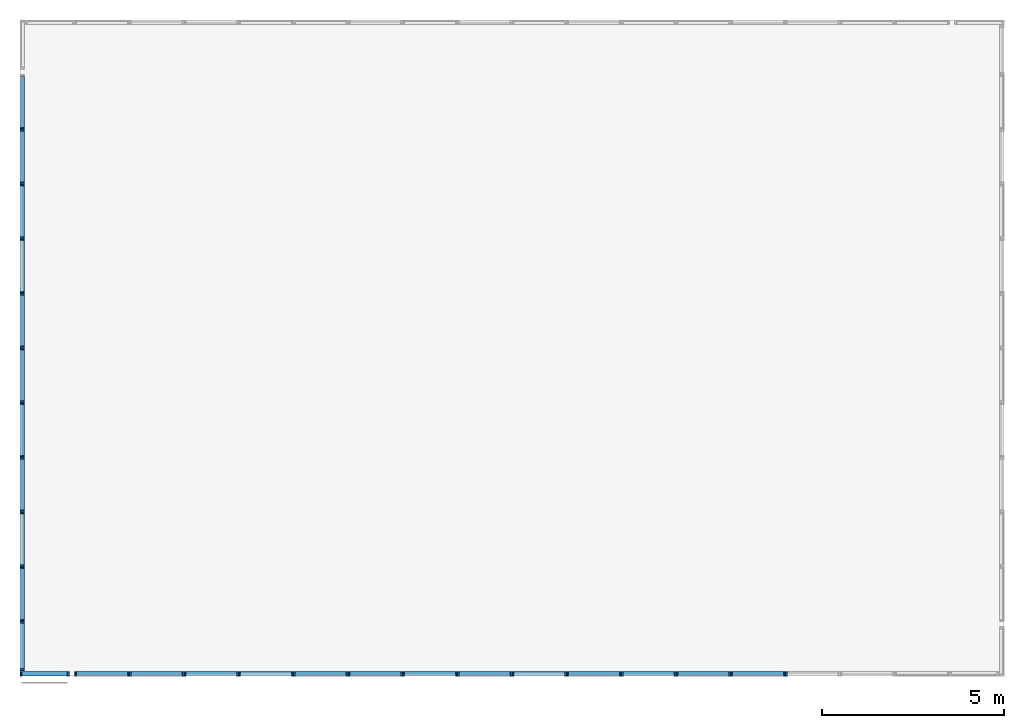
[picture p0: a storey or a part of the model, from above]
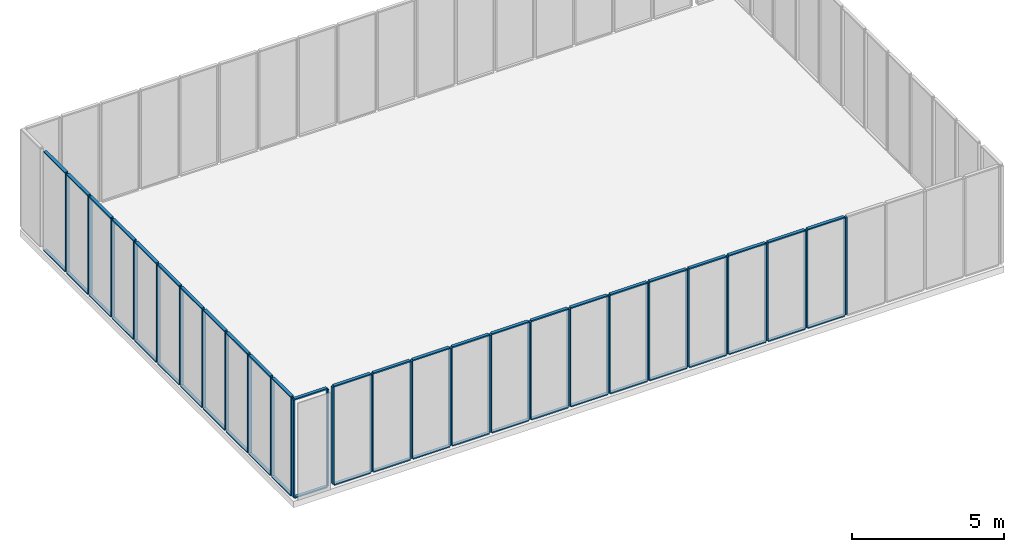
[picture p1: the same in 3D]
Properties of the parts of a building model (IFC4), part 1 of 7

# File
Description: ViewDefinition[DesignTransferView]
File name: ConX_Complex_Tower_IFC4.ifc
Time: 2026-09-19T02:26:32+05:00
Author: ConX Orbit
Written by: IfcOpenShell 0.8.5
Made in: IfcOpenShell 0.8.5
Authorization: Synthetic benchmark; not for construction

# IfcBuildingStorey (12)
In: Complex Tower
Name | Elevation (m)
L01 | 0
L02 | 4.2
L03 | 8.4
L04 | 12.6
L05 | 16.2
L06 | 19.8
L07 | 23.4
L08 | 27
L09 | 30.6
L10 | 34.2
L11 | 37.8
L12 | 41.4

# IfcMember (2304)
PredefinedType: MULLION; Material: Aluminium
ConX_Element - SyntheticData: yes; TypeCode: FR1; Thickness_mm: 120; DrawingRevision: A
Name | In | ElementID | Floor | Elevation | System = Group | Width_mm | Height_mm | Finish | DrawingRef | ParentPanelID
CT-L01-S-001-ML | L01 | CT-L01-S-001-ML | L01 | South | Curtain wall | 50 | 3900 | Blue-grey concept glass | CT-101 | CT-L01-S-001
CT-L01-S-001-MR | L01 | CT-L01-S-001-MR | L01 | South | Curtain wall | 50 | 3900 | Blue-grey concept glass | CT-101 | CT-L01-S-001
CT-L01-S-001-FB | L01 | CT-L01-S-001-FB | L01 | South | Curtain wall | 1250 | 50 | Blue-grey concept glass | CT-101 | CT-L01-S-001
CT-L01-S-001-FT | L01 | CT-L01-S-001-FT | L01 | South | Curtain wall | 1250 | 50 | Blue-grey concept glass | CT-101 | CT-L01-S-001
CT-L01-S-002-ML | L01 | CT-L01-S-002-ML | L01 | South | Curtain wall | 50 | 3900 | Blue-grey concept glass | CT-101 | CT-L01-S-002
CT-L01-S-002-MR | L01 | CT-L01-S-002-MR | L01 | South | Curtain wall | 50 | 3900 | Blue-grey concept glass | CT-101 | CT-L01-S-002
CT-L01-S-002-FB | L01 | CT-L01-S-002-FB | L01 | South | Curtain wall | 1400 | 50 | Blue-grey concept glass | CT-101 | CT-L01-S-002
CT-L01-S-002-FT | L01 | CT-L01-S-002-FT | L01 | South | Curtain wall | 1400 | 50 | Blue-grey concept glass | CT-101 | CT-L01-S-002
CT-L01-S-003-ML | L01 | CT-L01-S-003-ML | L01 | South | Curtain wall | 50 | 3900 | Blue-grey concept glass | CT-101 | CT-L01-S-003
CT-L01-S-003-MR | L01 | CT-L01-S-003-MR | L01 | South | Curtain wall | 50 | 3900 | Blue-grey concept glass | CT-101 | CT-L01-S-003
CT-L01-S-003-FB | L01 | CT-L01-S-003-FB | L01 | South | Curtain wall | 1400 | 50 | Blue-grey concept glass | CT-101 | CT-L01-S-003
CT-L01-S-003-FT | L01 | CT-L01-S-003-FT | L01 | South | Curtain wall | 1400 | 50 | Blue-grey concept glass | CT-101 | CT-L01-S-003
CT-L01-S-004-ML | L01 | CT-L01-S-004-ML | L01 | South | Stone cladding | 50 | 3900 | Warm beige stone | CT-101 | CT-L01-S-004
CT-L01-S-004-MR | L01 | CT-L01-S-004-MR | L01 | South | Stone cladding | 50 | 3900 | Warm beige stone | CT-101 | CT-L01-S-004
CT-L01-S-004-FB | L01 | CT-L01-S-004-FB | L01 | South | Stone cladding | 1400 | 50 | Warm beige stone | CT-101 | CT-L01-S-004
CT-L01-S-004-FT | L01 | CT-L01-S-004-FT | L01 | South | Stone cladding | 1400 | 50 | Warm beige stone | CT-101 | CT-L01-S-004
CT-L01-S-005-ML | L01 | CT-L01-S-005-ML | L01 | South | Metal rainscreen | 50 | 3900 | Olive powder coat | CT-101 | CT-L01-S-005
CT-L01-S-005-MR | L01 | CT-L01-S-005-MR | L01 | South | Metal rainscreen | 50 | 3900 | Olive powder coat | CT-101 | CT-L01-S-005
CT-L01-S-005-FB | L01 | CT-L01-S-005-FB | L01 | South | Metal rainscreen | 1400 | 50 | Olive powder coat | CT-101 | CT-L01-S-005
CT-L01-S-005-FT | L01 | CT-L01-S-005-FT | L01 | South | Metal rainscreen | 1400 | 50 | Olive powder coat | CT-101 | CT-L01-S-005
CT-L01-S-006-ML | L01 | CT-L01-S-006-ML | L01 | South | Curtain wall | 50 | 3900 | Blue-grey concept glass | CT-101 | CT-L01-S-006
CT-L01-S-006-MR | L01 | CT-L01-S-006-MR | L01 | South | Curtain wall | 50 | 3900 | Blue-grey concept glass | CT-101 | CT-L01-S-006
CT-L01-S-006-FB | L01 | CT-L01-S-006-FB | L01 | South | Curtain wall | 1400 | 50 | Blue-grey concept glass | CT-101 | CT-L01-S-006
CT-L01-S-006-FT | L01 | CT-L01-S-006-FT | L01 | South | Curtain wall | 1400 | 50 | Blue-grey concept glass | CT-101 | CT-L01-S-006
CT-L01-S-007-ML | L01 | CT-L01-S-007-ML | L01 | South | Curtain wall | 50 | 3900 | Blue-grey concept glass | CT-101 | CT-L01-S-007
CT-L01-S-007-MR | L01 | CT-L01-S-007-MR | L01 | South | Curtain wall | 50 | 3900 | Blue-grey concept glass | CT-101 | CT-L01-S-007
CT-L01-S-007-FB | L01 | CT-L01-S-007-FB | L01 | South | Curtain wall | 1400 | 50 | Blue-grey concept glass | CT-101 | CT-L01-S-007
CT-L01-S-007-FT | L01 | CT-L01-S-007-FT | L01 | South | Curtain wall | 1400 | 50 | Blue-grey concept glass | CT-101 | CT-L01-S-007
CT-L01-S-008-ML | L01 | CT-L01-S-008-ML | L01 | South | Stone cladding | 50 | 3900 | Warm beige stone | CT-101 | CT-L01-S-008
CT-L01-S-008-MR | L01 | CT-L01-S-008-MR | L01 | South | Stone cladding | 50 | 3900 | Warm beige stone | CT-101 | CT-L01-S-008
CT-L01-S-008-FB | L01 | CT-L01-S-008-FB | L01 | South | Stone cladding | 1400 | 50 | Warm beige stone | CT-101 | CT-L01-S-008
CT-L01-S-008-FT | L01 | CT-L01-S-008-FT | L01 | South | Stone cladding | 1400 | 50 | Warm beige stone | CT-101 | CT-L01-S-008
CT-L01-S-009-ML | L01 | CT-L01-S-009-ML | L01 | South | Curtain wall | 50 | 3900 | Blue-grey concept glass | CT-101 | CT-L01-S-009
CT-L01-S-009-MR | L01 | CT-L01-S-009-MR | L01 | South | Curtain wall | 50 | 3900 | Blue-grey concept glass | CT-101 | CT-L01-S-009
CT-L01-S-009-FB | L01 | CT-L01-S-009-FB | L01 | South | Curtain wall | 1400 | 50 | Blue-grey concept glass | CT-101 | CT-L01-S-009
CT-L01-S-009-FT | L01 | CT-L01-S-009-FT | L01 | South | Curtain wall | 1400 | 50 | Blue-grey concept glass | CT-101 | CT-L01-S-009
CT-L01-S-010-ML | L01 | CT-L01-S-010-ML | L01 | South | Metal rainscreen | 50 | 3900 | Olive powder coat | CT-101 | CT-L01-S-010
CT-L01-S-010-MR | L01 | CT-L01-S-010-MR | L01 | South | Metal rainscreen | 50 | 3900 | Olive powder coat | CT-101 | CT-L01-S-010
CT-L01-S-010-FB | L01 | CT-L01-S-010-FB | L01 | South | Metal rainscreen | 1400 | 50 | Olive powder coat | CT-101 | CT-L01-S-010
CT-L01-S-010-FT | L01 | CT-L01-S-010-FT | L01 | South | Metal rainscreen | 1400 | 50 | Olive powder coat | CT-101 | CT-L01-S-010
CT-L01-S-011-ML | L01 | CT-L01-S-011-ML | L01 | South | Curtain wall | 50 | 3900 | Blue-grey concept glass | CT-101 | CT-L01-S-011
CT-L01-S-011-MR | L01 | CT-L01-S-011-MR | L01 | South | Curtain wall | 50 | 3900 | Blue-grey concept glass | CT-101 | CT-L01-S-011
CT-L01-S-011-FB | L01 | CT-L01-S-011-FB | L01 | South | Curtain wall | 1400 | 50 | Blue-grey concept glass | CT-101 | CT-L01-S-011
CT-L01-S-011-FT | L01 | CT-L01-S-011-FT | L01 | South | Curtain wall | 1400 | 50 | Blue-grey concept glass | CT-101 | CT-L01-S-011
CT-L01-S-012-ML | L01 | CT-L01-S-012-ML | L01 | South | Stone cladding | 50 | 3900 | Warm beige stone | CT-101 | CT-L01-S-012
CT-L01-S-012-MR | L01 | CT-L01-S-012-MR | L01 | South | Stone cladding | 50 | 3900 | Warm beige stone | CT-101 | CT-L01-S-012
CT-L01-S-012-FB | L01 | CT-L01-S-012-FB | L01 | South | Stone cladding | 1400 | 50 | Warm beige stone | CT-101 | CT-L01-S-012
CT-L01-S-012-FT | L01 | CT-L01-S-012-FT | L01 | South | Stone cladding | 1400 | 50 | Warm beige stone | CT-101 | CT-L01-S-012
CT-L01-S-013-ML | L01 | CT-L01-S-013-ML | L01 | South | Curtain wall | 50 | 3900 | Blue-grey concept glass | CT-101 | CT-L01-S-013
CT-L01-S-013-MR | L01 | CT-L01-S-013-MR | L01 | South | Curtain wall | 50 | 3900 | Blue-grey concept glass | CT-101 | CT-L01-S-013
CT-L01-S-013-FB | L01 | CT-L01-S-013-FB | L01 | South | Curtain wall | 1400 | 50 | Blue-grey concept glass | CT-101 | CT-L01-S-013
CT-L01-S-013-FT | L01 | CT-L01-S-013-FT | L01 | South | Curtain wall | 1400 | 50 | Blue-grey concept glass | CT-101 | CT-L01-S-013
CT-L01-S-014-ML | L01 | CT-L01-S-014-ML | L01 | South | Curtain wall | 50 | 3900 | Blue-grey concept glass | CT-101 | CT-L01-S-014
CT-L01-S-014-MR | L01 | CT-L01-S-014-MR | L01 | South | Curtain wall | 50 | 3900 | Blue-grey concept glass | CT-101 | CT-L01-S-014
CT-L01-S-014-FB | L01 | CT-L01-S-014-FB | L01 | South | Curtain wall | 1400 | 50 | Blue-grey concept glass | CT-101 | CT-L01-S-014
CT-L01-S-014-FT | L01 | CT-L01-S-014-FT | L01 | South | Curtain wall | 1400 | 50 | Blue-grey concept glass | CT-101 | CT-L01-S-014
CT-L01-S-015-ML | L01 | CT-L01-S-015-ML | L01 | South | Metal rainscreen | 50 | 3900 | Olive powder coat | CT-101 | CT-L01-S-015
CT-L01-S-015-MR | L01 | CT-L01-S-015-MR | L01 | South | Metal rainscreen | 50 | 3900 | Olive powder coat | CT-101 | CT-L01-S-015
CT-L01-S-015-FB | L01 | CT-L01-S-015-FB | L01 | South | Metal rainscreen | 1400 | 50 | Olive powder coat | CT-101 | CT-L01-S-015
CT-L01-S-015-FT | L01 | CT-L01-S-015-FT | L01 | South | Metal rainscreen | 1400 | 50 | Olive powder coat | CT-101 | CT-L01-S-015
CT-L01-S-016-ML | L01 | CT-L01-S-016-ML | L01 | South | Stone cladding | 50 | 3900 | Warm beige stone | CT-101 | CT-L01-S-016
CT-L01-S-016-MR | L01 | CT-L01-S-016-MR | L01 | South | Stone cladding | 50 | 3900 | Warm beige stone | CT-101 | CT-L01-S-016
CT-L01-S-016-FB | L01 | CT-L01-S-016-FB | L01 | South | Stone cladding | 1400 | 50 | Warm beige stone | CT-101 | CT-L01-S-016
CT-L01-S-016-FT | L01 | CT-L01-S-016-FT | L01 | South | Stone cladding | 1400 | 50 | Warm beige stone | CT-101 | CT-L01-S-016
CT-L01-S-017-ML | L01 | CT-L01-S-017-ML | L01 | South | Curtain wall | 50 | 3900 | Blue-grey concept glass | CT-101 | CT-L01-S-017
CT-L01-S-017-MR | L01 | CT-L01-S-017-MR | L01 | South | Curtain wall | 50 | 3900 | Blue-grey concept glass | CT-101 | CT-L01-S-017
CT-L01-S-017-FB | L01 | CT-L01-S-017-FB | L01 | South | Curtain wall | 1400 | 50 | Blue-grey concept glass | CT-101 | CT-L01-S-017
CT-L01-S-017-FT | L01 | CT-L01-S-017-FT | L01 | South | Curtain wall | 1400 | 50 | Blue-grey concept glass | CT-101 | CT-L01-S-017
CT-L01-S-018-ML | L01 | CT-L01-S-018-ML | L01 | South | Curtain wall | 50 | 3900 | Blue-grey concept glass | CT-101 | CT-L01-S-018
CT-L01-S-018-MR | L01 | CT-L01-S-018-MR | L01 | South | Curtain wall | 50 | 3900 | Blue-grey concept glass | CT-101 | CT-L01-S-018
CT-L01-S-018-FB | L01 | CT-L01-S-018-FB | L01 | South | Curtain wall | 1250 | 50 | Blue-grey concept glass | CT-101 | CT-L01-S-018
CT-L01-S-018-FT | L01 | CT-L01-S-018-FT | L01 | South | Curtain wall | 1250 | 50 | Blue-grey concept glass | CT-101 | CT-L01-S-018
CT-L01-E-001-ML | L01 | CT-L01-E-001-ML | L01 | East | Curtain wall | 50 | 3900 | Blue-grey concept glass | CT-102 | CT-L01-E-001
CT-L01-E-001-MR | L01 | CT-L01-E-001-MR | L01 | East | Curtain wall | 50 | 3900 | Blue-grey concept glass | CT-102 | CT-L01-E-001
CT-L01-E-001-FB | L01 | CT-L01-E-001-FB | L01 | East | Curtain wall | 1250 | 50 | Blue-grey concept glass | CT-102 | CT-L01-E-001
CT-L01-E-001-FT | L01 | CT-L01-E-001-FT | L01 | East | Curtain wall | 1250 | 50 | Blue-grey concept glass | CT-102 | CT-L01-E-001
CT-L01-E-002-ML | L01 | CT-L01-E-002-ML | L01 | East | Curtain wall | 50 | 3900 | Blue-grey concept glass | CT-102 | CT-L01-E-002
CT-L01-E-002-MR | L01 | CT-L01-E-002-MR | L01 | East | Curtain wall | 50 | 3900 | Blue-grey concept glass | CT-102 | CT-L01-E-002
CT-L01-E-002-FB | L01 | CT-L01-E-002-FB | L01 | East | Curtain wall | 1400 | 50 | Blue-grey concept glass | CT-102 | CT-L01-E-002
CT-L01-E-002-FT | L01 | CT-L01-E-002-FT | L01 | East | Curtain wall | 1400 | 50 | Blue-grey concept glass | CT-102 | CT-L01-E-002
CT-L01-E-003-ML | L01 | CT-L01-E-003-ML | L01 | East | Curtain wall | 50 | 3900 | Blue-grey concept glass | CT-102 | CT-L01-E-003
CT-L01-E-003-MR | L01 | CT-L01-E-003-MR | L01 | East | Curtain wall | 50 | 3900 | Blue-grey concept glass | CT-102 | CT-L01-E-003
CT-L01-E-003-FB | L01 | CT-L01-E-003-FB | L01 | East | Curtain wall | 1400 | 50 | Blue-grey concept glass | CT-102 | CT-L01-E-003
CT-L01-E-003-FT | L01 | CT-L01-E-003-FT | L01 | East | Curtain wall | 1400 | 50 | Blue-grey concept glass | CT-102 | CT-L01-E-003
CT-L01-E-004-ML | L01 | CT-L01-E-004-ML | L01 | East | Stone cladding | 50 | 3900 | Warm beige stone | CT-102 | CT-L01-E-004
CT-L01-E-004-MR | L01 | CT-L01-E-004-MR | L01 | East | Stone cladding | 50 | 3900 | Warm beige stone | CT-102 | CT-L01-E-004
CT-L01-E-004-FB | L01 | CT-L01-E-004-FB | L01 | East | Stone cladding | 1400 | 50 | Warm beige stone | CT-102 | CT-L01-E-004
CT-L01-E-004-FT | L01 | CT-L01-E-004-FT | L01 | East | Stone cladding | 1400 | 50 | Warm beige stone | CT-102 | CT-L01-E-004
CT-L01-E-005-ML | L01 | CT-L01-E-005-ML | L01 | East | Metal rainscreen | 50 | 3900 | Olive powder coat | CT-102 | CT-L01-E-005
CT-L01-E-005-MR | L01 | CT-L01-E-005-MR | L01 | East | Metal rainscreen | 50 | 3900 | Olive powder coat | CT-102 | CT-L01-E-005
CT-L01-E-005-FB | L01 | CT-L01-E-005-FB | L01 | East | Metal rainscreen | 1400 | 50 | Olive powder coat | CT-102 | CT-L01-E-005
CT-L01-E-005-FT | L01 | CT-L01-E-005-FT | L01 | East | Metal rainscreen | 1400 | 50 | Olive powder coat | CT-102 | CT-L01-E-005
CT-L01-E-006-ML | L01 | CT-L01-E-006-ML | L01 | East | Curtain wall | 50 | 3900 | Blue-grey concept glass | CT-102 | CT-L01-E-006
CT-L01-E-006-MR | L01 | CT-L01-E-006-MR | L01 | East | Curtain wall | 50 | 3900 | Blue-grey concept glass | CT-102 | CT-L01-E-006
CT-L01-E-006-FB | L01 | CT-L01-E-006-FB | L01 | East | Curtain wall | 1400 | 50 | Blue-grey concept glass | CT-102 | CT-L01-E-006
CT-L01-E-006-FT | L01 | CT-L01-E-006-FT | L01 | East | Curtain wall | 1400 | 50 | Blue-grey concept glass | CT-102 | CT-L01-E-006
CT-L01-E-007-ML | L01 | CT-L01-E-007-ML | L01 | East | Curtain wall | 50 | 3900 | Blue-grey concept glass | CT-102 | CT-L01-E-007
CT-L01-E-007-MR | L01 | CT-L01-E-007-MR | L01 | East | Curtain wall | 50 | 3900 | Blue-grey concept glass | CT-102 | CT-L01-E-007
CT-L01-E-007-FB | L01 | CT-L01-E-007-FB | L01 | East | Curtain wall | 1400 | 50 | Blue-grey concept glass | CT-102 | CT-L01-E-007
CT-L01-E-007-FT | L01 | CT-L01-E-007-FT | L01 | East | Curtain wall | 1400 | 50 | Blue-grey concept glass | CT-102 | CT-L01-E-007
CT-L01-E-008-ML | L01 | CT-L01-E-008-ML | L01 | East | Stone cladding | 50 | 3900 | Warm beige stone | CT-102 | CT-L01-E-008
CT-L01-E-008-MR | L01 | CT-L01-E-008-MR | L01 | East | Stone cladding | 50 | 3900 | Warm beige stone | CT-102 | CT-L01-E-008
CT-L01-E-008-FB | L01 | CT-L01-E-008-FB | L01 | East | Stone cladding | 1400 | 50 | Warm beige stone | CT-102 | CT-L01-E-008
CT-L01-E-008-FT | L01 | CT-L01-E-008-FT | L01 | East | Stone cladding | 1400 | 50 | Warm beige stone | CT-102 | CT-L01-E-008
CT-L01-E-009-ML | L01 | CT-L01-E-009-ML | L01 | East | Curtain wall | 50 | 3900 | Blue-grey concept glass | CT-102 | CT-L01-E-009
CT-L01-E-009-MR | L01 | CT-L01-E-009-MR | L01 | East | Curtain wall | 50 | 3900 | Blue-grey concept glass | CT-102 | CT-L01-E-009
CT-L01-E-009-FB | L01 | CT-L01-E-009-FB | L01 | East | Curtain wall | 1400 | 50 | Blue-grey concept glass | CT-102 | CT-L01-E-009
CT-L01-E-009-FT | L01 | CT-L01-E-009-FT | L01 | East | Curtain wall | 1400 | 50 | Blue-grey concept glass | CT-102 | CT-L01-E-009
CT-L01-E-010-ML | L01 | CT-L01-E-010-ML | L01 | East | Metal rainscreen | 50 | 3900 | Olive powder coat | CT-102 | CT-L01-E-010
CT-L01-E-010-MR | L01 | CT-L01-E-010-MR | L01 | East | Metal rainscreen | 50 | 3900 | Olive powder coat | CT-102 | CT-L01-E-010
CT-L01-E-010-FB | L01 | CT-L01-E-010-FB | L01 | East | Metal rainscreen | 1400 | 50 | Olive powder coat | CT-102 | CT-L01-E-010
CT-L01-E-010-FT | L01 | CT-L01-E-010-FT | L01 | East | Metal rainscreen | 1400 | 50 | Olive powder coat | CT-102 | CT-L01-E-010
CT-L01-E-011-ML | L01 | CT-L01-E-011-ML | L01 | East | Curtain wall | 50 | 3900 | Blue-grey concept glass | CT-102 | CT-L01-E-011
CT-L01-E-011-MR | L01 | CT-L01-E-011-MR | L01 | East | Curtain wall | 50 | 3900 | Blue-grey concept glass | CT-102 | CT-L01-E-011
CT-L01-E-011-FB | L01 | CT-L01-E-011-FB | L01 | East | Curtain wall | 1400 | 50 | Blue-grey concept glass | CT-102 | CT-L01-E-011
CT-L01-E-011-FT | L01 | CT-L01-E-011-FT | L01 | East | Curtain wall | 1400 | 50 | Blue-grey concept glass | CT-102 | CT-L01-E-011
CT-L01-E-012-ML | L01 | CT-L01-E-012-ML | L01 | East | Stone cladding | 50 | 3900 | Warm beige stone | CT-102 | CT-L01-E-012
CT-L01-E-012-MR | L01 | CT-L01-E-012-MR | L01 | East | Stone cladding | 50 | 3900 | Warm beige stone | CT-102 | CT-L01-E-012
CT-L01-E-012-FB | L01 | CT-L01-E-012-FB | L01 | East | Stone cladding | 1250 | 50 | Warm beige stone | CT-102 | CT-L01-E-012
CT-L01-E-012-FT | L01 | CT-L01-E-012-FT | L01 | East | Stone cladding | 1250 | 50 | Warm beige stone | CT-102 | CT-L01-E-012
CT-L01-N-001-ML | L01 | CT-L01-N-001-ML | L01 | North | Curtain wall | 50 | 3900 | Blue-grey concept glass | CT-103 | CT-L01-N-001
CT-L01-N-001-MR | L01 | CT-L01-N-001-MR | L01 | North | Curtain wall | 50 | 3900 | Blue-grey concept glass | CT-103 | CT-L01-N-001
CT-L01-N-001-FB | L01 | CT-L01-N-001-FB | L01 | North | Curtain wall | 1250 | 50 | Blue-grey concept glass | CT-103 | CT-L01-N-001
CT-L01-N-001-FT | L01 | CT-L01-N-001-FT | L01 | North | Curtain wall | 1250 | 50 | Blue-grey concept glass | CT-103 | CT-L01-N-001
CT-L01-N-002-ML | L01 | CT-L01-N-002-ML | L01 | North | Curtain wall | 50 | 3900 | Blue-grey concept glass | CT-103 | CT-L01-N-002
CT-L01-N-002-MR | L01 | CT-L01-N-002-MR | L01 | North | Curtain wall | 50 | 3900 | Blue-grey concept glass | CT-103 | CT-L01-N-002
CT-L01-N-002-FB | L01 | CT-L01-N-002-FB | L01 | North | Curtain wall | 1400 | 50 | Blue-grey concept glass | CT-103 | CT-L01-N-002
CT-L01-N-002-FT | L01 | CT-L01-N-002-FT | L01 | North | Curtain wall | 1400 | 50 | Blue-grey concept glass | CT-103 | CT-L01-N-002
CT-L01-N-003-ML | L01 | CT-L01-N-003-ML | L01 | North | Curtain wall | 50 | 3900 | Blue-grey concept glass | CT-103 | CT-L01-N-003
CT-L01-N-003-MR | L01 | CT-L01-N-003-MR | L01 | North | Curtain wall | 50 | 3900 | Blue-grey concept glass | CT-103 | CT-L01-N-003
CT-L01-N-003-FB | L01 | CT-L01-N-003-FB | L01 | North | Curtain wall | 1400 | 50 | Blue-grey concept glass | CT-103 | CT-L01-N-003
CT-L01-N-003-FT | L01 | CT-L01-N-003-FT | L01 | North | Curtain wall | 1400 | 50 | Blue-grey concept glass | CT-103 | CT-L01-N-003
CT-L01-N-004-ML | L01 | CT-L01-N-004-ML | L01 | North | Stone cladding | 50 | 3900 | Warm beige stone | CT-103 | CT-L01-N-004
CT-L01-N-004-MR | L01 | CT-L01-N-004-MR | L01 | North | Stone cladding | 50 | 3900 | Warm beige stone | CT-103 | CT-L01-N-004
CT-L01-N-004-FB | L01 | CT-L01-N-004-FB | L01 | North | Stone cladding | 1400 | 50 | Warm beige stone | CT-103 | CT-L01-N-004
CT-L01-N-004-FT | L01 | CT-L01-N-004-FT | L01 | North | Stone cladding | 1400 | 50 | Warm beige stone | CT-103 | CT-L01-N-004
CT-L01-N-005-ML | L01 | CT-L01-N-005-ML | L01 | North | Metal rainscreen | 50 | 3900 | Olive powder coat | CT-103 | CT-L01-N-005
CT-L01-N-005-MR | L01 | CT-L01-N-005-MR | L01 | North | Metal rainscreen | 50 | 3900 | Olive powder coat | CT-103 | CT-L01-N-005
CT-L01-N-005-FB | L01 | CT-L01-N-005-FB | L01 | North | Metal rainscreen | 1400 | 50 | Olive powder coat | CT-103 | CT-L01-N-005
CT-L01-N-005-FT | L01 | CT-L01-N-005-FT | L01 | North | Metal rainscreen | 1400 | 50 | Olive powder coat | CT-103 | CT-L01-N-005
CT-L01-N-006-ML | L01 | CT-L01-N-006-ML | L01 | North | Curtain wall | 50 | 3900 | Blue-grey concept glass | CT-103 | CT-L01-N-006
CT-L01-N-006-MR | L01 | CT-L01-N-006-MR | L01 | North | Curtain wall | 50 | 3900 | Blue-grey concept glass | CT-103 | CT-L01-N-006
CT-L01-N-006-FB | L01 | CT-L01-N-006-FB | L01 | North | Curtain wall | 1400 | 50 | Blue-grey concept glass | CT-103 | CT-L01-N-006
CT-L01-N-006-FT | L01 | CT-L01-N-006-FT | L01 | North | Curtain wall | 1400 | 50 | Blue-grey concept glass | CT-103 | CT-L01-N-006
CT-L01-N-007-ML | L01 | CT-L01-N-007-ML | L01 | North | Curtain wall | 50 | 3900 | Blue-grey concept glass | CT-103 | CT-L01-N-007
CT-L01-N-007-MR | L01 | CT-L01-N-007-MR | L01 | North | Curtain wall | 50 | 3900 | Blue-grey concept glass | CT-103 | CT-L01-N-007
CT-L01-N-007-FB | L01 | CT-L01-N-007-FB | L01 | North | Curtain wall | 1400 | 50 | Blue-grey concept glass | CT-103 | CT-L01-N-007
CT-L01-N-007-FT | L01 | CT-L01-N-007-FT | L01 | North | Curtain wall | 1400 | 50 | Blue-grey concept glass | CT-103 | CT-L01-N-007
CT-L01-N-008-ML | L01 | CT-L01-N-008-ML | L01 | North | Stone cladding | 50 | 3900 | Warm beige stone | CT-103 | CT-L01-N-008
CT-L01-N-008-MR | L01 | CT-L01-N-008-MR | L01 | North | Stone cladding | 50 | 3900 | Warm beige stone | CT-103 | CT-L01-N-008
CT-L01-N-008-FB | L01 | CT-L01-N-008-FB | L01 | North | Stone cladding | 1400 | 50 | Warm beige stone | CT-103 | CT-L01-N-008
CT-L01-N-008-FT | L01 | CT-L01-N-008-FT | L01 | North | Stone cladding | 1400 | 50 | Warm beige stone | CT-103 | CT-L01-N-008
CT-L01-N-009-ML | L01 | CT-L01-N-009-ML | L01 | North | Curtain wall | 50 | 3900 | Blue-grey concept glass | CT-103 | CT-L01-N-009
CT-L01-N-009-MR | L01 | CT-L01-N-009-MR | L01 | North | Curtain wall | 50 | 3900 | Blue-grey concept glass | CT-103 | CT-L01-N-009
CT-L01-N-009-FB | L01 | CT-L01-N-009-FB | L01 | North | Curtain wall | 1400 | 50 | Blue-grey concept glass | CT-103 | CT-L01-N-009
CT-L01-N-009-FT | L01 | CT-L01-N-009-FT | L01 | North | Curtain wall | 1400 | 50 | Blue-grey concept glass | CT-103 | CT-L01-N-009
CT-L01-N-010-ML | L01 | CT-L01-N-010-ML | L01 | North | Metal rainscreen | 50 | 3900 | Olive powder coat | CT-103 | CT-L01-N-010
CT-L01-N-010-MR | L01 | CT-L01-N-010-MR | L01 | North | Metal rainscreen | 50 | 3900 | Olive powder coat | CT-103 | CT-L01-N-010
CT-L01-N-010-FB | L01 | CT-L01-N-010-FB | L01 | North | Metal rainscreen | 1400 | 50 | Olive powder coat | CT-103 | CT-L01-N-010
CT-L01-N-010-FT | L01 | CT-L01-N-010-FT | L01 | North | Metal rainscreen | 1400 | 50 | Olive powder coat | CT-103 | CT-L01-N-010
CT-L01-N-011-ML | L01 | CT-L01-N-011-ML | L01 | North | Curtain wall | 50 | 3900 | Blue-grey concept glass | CT-103 | CT-L01-N-011
CT-L01-N-011-MR | L01 | CT-L01-N-011-MR | L01 | North | Curtain wall | 50 | 3900 | Blue-grey concept glass | CT-103 | CT-L01-N-011
CT-L01-N-011-FB | L01 | CT-L01-N-011-FB | L01 | North | Curtain wall | 1400 | 50 | Blue-grey concept glass | CT-103 | CT-L01-N-011
CT-L01-N-011-FT | L01 | CT-L01-N-011-FT | L01 | North | Curtain wall | 1400 | 50 | Blue-grey concept glass | CT-103 | CT-L01-N-011
CT-L01-N-012-ML | L01 | CT-L01-N-012-ML | L01 | North | Stone cladding | 50 | 3900 | Warm beige stone | CT-103 | CT-L01-N-012
CT-L01-N-012-MR | L01 | CT-L01-N-012-MR | L01 | North | Stone cladding | 50 | 3900 | Warm beige stone | CT-103 | CT-L01-N-012
CT-L01-N-012-FB | L01 | CT-L01-N-012-FB | L01 | North | Stone cladding | 1400 | 50 | Warm beige stone | CT-103 | CT-L01-N-012
CT-L01-N-012-FT | L01 | CT-L01-N-012-FT | L01 | North | Stone cladding | 1400 | 50 | Warm beige stone | CT-103 | CT-L01-N-012
CT-L01-N-013-ML | L01 | CT-L01-N-013-ML | L01 | North | Curtain wall | 50 | 3900 | Blue-grey concept glass | CT-103 | CT-L01-N-013
CT-L01-N-013-MR | L01 | CT-L01-N-013-MR | L01 | North | Curtain wall | 50 | 3900 | Blue-grey concept glass | CT-103 | CT-L01-N-013
CT-L01-N-013-FB | L01 | CT-L01-N-013-FB | L01 | North | Curtain wall | 1400 | 50 | Blue-grey concept glass | CT-103 | CT-L01-N-013
CT-L01-N-013-FT | L01 | CT-L01-N-013-FT | L01 | North | Curtain wall | 1400 | 50 | Blue-grey concept glass | CT-103 | CT-L01-N-013
CT-L01-N-014-ML | L01 | CT-L01-N-014-ML | L01 | North | Curtain wall | 50 | 3900 | Blue-grey concept glass | CT-103 | CT-L01-N-014
CT-L01-N-014-MR | L01 | CT-L01-N-014-MR | L01 | North | Curtain wall | 50 | 3900 | Blue-grey concept glass | CT-103 | CT-L01-N-014
CT-L01-N-014-FB | L01 | CT-L01-N-014-FB | L01 | North | Curtain wall | 1400 | 50 | Blue-grey concept glass | CT-103 | CT-L01-N-014
CT-L01-N-014-FT | L01 | CT-L01-N-014-FT | L01 | North | Curtain wall | 1400 | 50 | Blue-grey concept glass | CT-103 | CT-L01-N-014
CT-L01-N-015-ML | L01 | CT-L01-N-015-ML | L01 | North | Metal rainscreen | 50 | 3900 | Olive powder coat | CT-103 | CT-L01-N-015
CT-L01-N-015-MR | L01 | CT-L01-N-015-MR | L01 | North | Metal rainscreen | 50 | 3900 | Olive powder coat | CT-103 | CT-L01-N-015
CT-L01-N-015-FB | L01 | CT-L01-N-015-FB | L01 | North | Metal rainscreen | 1400 | 50 | Olive powder coat | CT-103 | CT-L01-N-015
CT-L01-N-015-FT | L01 | CT-L01-N-015-FT | L01 | North | Metal rainscreen | 1400 | 50 | Olive powder coat | CT-103 | CT-L01-N-015
CT-L01-N-016-ML | L01 | CT-L01-N-016-ML | L01 | North | Stone cladding | 50 | 3900 | Warm beige stone | CT-103 | CT-L01-N-016
CT-L01-N-016-MR | L01 | CT-L01-N-016-MR | L01 | North | Stone cladding | 50 | 3900 | Warm beige stone | CT-103 | CT-L01-N-016
CT-L01-N-016-FB | L01 | CT-L01-N-016-FB | L01 | North | Stone cladding | 1400 | 50 | Warm beige stone | CT-103 | CT-L01-N-016
CT-L01-N-016-FT | L01 | CT-L01-N-016-FT | L01 | North | Stone cladding | 1400 | 50 | Warm beige stone | CT-103 | CT-L01-N-016
CT-L01-N-017-ML | L01 | CT-L01-N-017-ML | L01 | North | Curtain wall | 50 | 3900 | Blue-grey concept glass | CT-103 | CT-L01-N-017
CT-L01-N-017-MR | L01 | CT-L01-N-017-MR | L01 | North | Curtain wall | 50 | 3900 | Blue-grey concept glass | CT-103 | CT-L01-N-017
CT-L01-N-017-FB | L01 | CT-L01-N-017-FB | L01 | North | Curtain wall | 1400 | 50 | Blue-grey concept glass | CT-103 | CT-L01-N-017
CT-L01-N-017-FT | L01 | CT-L01-N-017-FT | L01 | North | Curtain wall | 1400 | 50 | Blue-grey concept glass | CT-103 | CT-L01-N-017
CT-L01-N-018-ML | L01 | CT-L01-N-018-ML | L01 | North | Curtain wall | 50 | 3900 | Blue-grey concept glass | CT-103 | CT-L01-N-018
CT-L01-N-018-MR | L01 | CT-L01-N-018-MR | L01 | North | Curtain wall | 50 | 3900 | Blue-grey concept glass | CT-103 | CT-L01-N-018
CT-L01-N-018-FB | L01 | CT-L01-N-018-FB | L01 | North | Curtain wall | 1250 | 50 | Blue-grey concept glass | CT-103 | CT-L01-N-018
CT-L01-N-018-FT | L01 | CT-L01-N-018-FT | L01 | North | Curtain wall | 1250 | 50 | Blue-grey concept glass | CT-103 | CT-L01-N-018
CT-L01-W-001-ML | L01 | CT-L01-W-001-ML | L01 | West | Curtain wall | 50 | 3900 | Blue-grey concept glass | CT-104 | CT-L01-W-001
CT-L01-W-001-MR | L01 | CT-L01-W-001-MR | L01 | West | Curtain wall | 50 | 3900 | Blue-grey concept glass | CT-104 | CT-L01-W-001
CT-L01-W-001-FB | L01 | CT-L01-W-001-FB | L01 | West | Curtain wall | 1250 | 50 | Blue-grey concept glass | CT-104 | CT-L01-W-001
CT-L01-W-001-FT | L01 | CT-L01-W-001-FT | L01 | West | Curtain wall | 1250 | 50 | Blue-grey concept glass | CT-104 | CT-L01-W-001
CT-L01-W-002-ML | L01 | CT-L01-W-002-ML | L01 | West | Curtain wall | 50 | 3900 | Blue-grey concept glass | CT-104 | CT-L01-W-002
CT-L01-W-002-MR | L01 | CT-L01-W-002-MR | L01 | West | Curtain wall | 50 | 3900 | Blue-grey concept glass | CT-104 | CT-L01-W-002
CT-L01-W-002-FB | L01 | CT-L01-W-002-FB | L01 | West | Curtain wall | 1400 | 50 | Blue-grey concept glass | CT-104 | CT-L01-W-002
CT-L01-W-002-FT | L01 | CT-L01-W-002-FT | L01 | West | Curtain wall | 1400 | 50 | Blue-grey concept glass | CT-104 | CT-L01-W-002
CT-L01-W-003-ML | L01 | CT-L01-W-003-ML | L01 | West | Curtain wall | 50 | 3900 | Blue-grey concept glass | CT-104 | CT-L01-W-003
CT-L01-W-003-MR | L01 | CT-L01-W-003-MR | L01 | West | Curtain wall | 50 | 3900 | Blue-grey concept glass | CT-104 | CT-L01-W-003
CT-L01-W-003-FB | L01 | CT-L01-W-003-FB | L01 | West | Curtain wall | 1400 | 50 | Blue-grey concept glass | CT-104 | CT-L01-W-003
CT-L01-W-003-FT | L01 | CT-L01-W-003-FT | L01 | West | Curtain wall | 1400 | 50 | Blue-grey concept glass | CT-104 | CT-L01-W-003
CT-L01-W-004-ML | L01 | CT-L01-W-004-ML | L01 | West | Stone cladding | 50 | 3900 | Warm beige stone | CT-104 | CT-L01-W-004
CT-L01-W-004-MR | L01 | CT-L01-W-004-MR | L01 | West | Stone cladding | 50 | 3900 | Warm beige stone | CT-104 | CT-L01-W-004
CT-L01-W-004-FB | L01 | CT-L01-W-004-FB | L01 | West | Stone cladding | 1400 | 50 | Warm beige stone | CT-104 | CT-L01-W-004
CT-L01-W-004-FT | L01 | CT-L01-W-004-FT | L01 | West | Stone cladding | 1400 | 50 | Warm beige stone | CT-104 | CT-L01-W-004
CT-L01-W-005-ML | L01 | CT-L01-W-005-ML | L01 | West | Metal rainscreen | 50 | 3900 | Olive powder coat | CT-104 | CT-L01-W-005
CT-L01-W-005-MR | L01 | CT-L01-W-005-MR | L01 | West | Metal rainscreen | 50 | 3900 | Olive powder coat | CT-104 | CT-L01-W-005
CT-L01-W-005-FB | L01 | CT-L01-W-005-FB | L01 | West | Metal rainscreen | 1400 | 50 | Olive powder coat | CT-104 | CT-L01-W-005
CT-L01-W-005-FT | L01 | CT-L01-W-005-FT | L01 | West | Metal rainscreen | 1400 | 50 | Olive powder coat | CT-104 | CT-L01-W-005
CT-L01-W-006-ML | L01 | CT-L01-W-006-ML | L01 | West | Curtain wall | 50 | 3900 | Blue-grey concept glass | CT-104 | CT-L01-W-006
CT-L01-W-006-MR | L01 | CT-L01-W-006-MR | L01 | West | Curtain wall | 50 | 3900 | Blue-grey concept glass | CT-104 | CT-L01-W-006
CT-L01-W-006-FB | L01 | CT-L01-W-006-FB | L01 | West | Curtain wall | 1400 | 50 | Blue-grey concept glass | CT-104 | CT-L01-W-006
CT-L01-W-006-FT | L01 | CT-L01-W-006-FT | L01 | West | Curtain wall | 1400 | 50 | Blue-grey concept glass | CT-104 | CT-L01-W-006
CT-L01-W-007-ML | L01 | CT-L01-W-007-ML | L01 | West | Curtain wall | 50 | 3900 | Blue-grey concept glass | CT-104 | CT-L01-W-007
CT-L01-W-007-MR | L01 | CT-L01-W-007-MR | L01 | West | Curtain wall | 50 | 3900 | Blue-grey concept glass | CT-104 | CT-L01-W-007
CT-L01-W-007-FB | L01 | CT-L01-W-007-FB | L01 | West | Curtain wall | 1400 | 50 | Blue-grey concept glass | CT-104 | CT-L01-W-007
CT-L01-W-007-FT | L01 | CT-L01-W-007-FT | L01 | West | Curtain wall | 1400 | 50 | Blue-grey concept glass | CT-104 | CT-L01-W-007
CT-L01-W-008-ML | L01 | CT-L01-W-008-ML | L01 | West | Stone cladding | 50 | 3900 | Warm beige stone | CT-104 | CT-L01-W-008
CT-L01-W-008-MR | L01 | CT-L01-W-008-MR | L01 | West | Stone cladding | 50 | 3900 | Warm beige stone | CT-104 | CT-L01-W-008
CT-L01-W-008-FB | L01 | CT-L01-W-008-FB | L01 | West | Stone cladding | 1400 | 50 | Warm beige stone | CT-104 | CT-L01-W-008
CT-L01-W-008-FT | L01 | CT-L01-W-008-FT | L01 | West | Stone cladding | 1400 | 50 | Warm beige stone | CT-104 | CT-L01-W-008
CT-L01-W-009-ML | L01 | CT-L01-W-009-ML | L01 | West | Curtain wall | 50 | 3900 | Blue-grey concept glass | CT-104 | CT-L01-W-009
CT-L01-W-009-MR | L01 | CT-L01-W-009-MR | L01 | West | Curtain wall | 50 | 3900 | Blue-grey concept glass | CT-104 | CT-L01-W-009
CT-L01-W-009-FB | L01 | CT-L01-W-009-FB | L01 | West | Curtain wall | 1400 | 50 | Blue-grey concept glass | CT-104 | CT-L01-W-009
CT-L01-W-009-FT | L01 | CT-L01-W-009-FT | L01 | West | Curtain wall | 1400 | 50 | Blue-grey concept glass | CT-104 | CT-L01-W-009
CT-L01-W-010-ML | L01 | CT-L01-W-010-ML | L01 | West | Metal rainscreen | 50 | 3900 | Olive powder coat | CT-104 | CT-L01-W-010
CT-L01-W-010-MR | L01 | CT-L01-W-010-MR | L01 | West | Metal rainscreen | 50 | 3900 | Olive powder coat | CT-104 | CT-L01-W-010
CT-L01-W-010-FB | L01 | CT-L01-W-010-FB | L01 | West | Metal rainscreen | 1400 | 50 | Olive powder coat | CT-104 | CT-L01-W-010
CT-L01-W-010-FT | L01 | CT-L01-W-010-FT | L01 | West | Metal rainscreen | 1400 | 50 | Olive powder coat | CT-104 | CT-L01-W-010
CT-L01-W-011-ML | L01 | CT-L01-W-011-ML | L01 | West | Curtain wall | 50 | 3900 | Blue-grey concept glass | CT-104 | CT-L01-W-011
CT-L01-W-011-MR | L01 | CT-L01-W-011-MR | L01 | West | Curtain wall | 50 | 3900 | Blue-grey concept glass | CT-104 | CT-L01-W-011
CT-L01-W-011-FB | L01 | CT-L01-W-011-FB | L01 | West | Curtain wall | 1400 | 50 | Blue-grey concept glass | CT-104 | CT-L01-W-011
CT-L01-W-011-FT | L01 | CT-L01-W-011-FT | L01 | West | Curtain wall | 1400 | 50 | Blue-grey concept glass | CT-104 | CT-L01-W-011
CT-L01-W-012-ML | L01 | CT-L01-W-012-ML | L01 | West | Stone cladding | 50 | 3900 | Warm beige stone | CT-104 | CT-L01-W-012
CT-L01-W-012-MR | L01 | CT-L01-W-012-MR | L01 | West | Stone cladding | 50 | 3900 | Warm beige stone | CT-104 | CT-L01-W-012
CT-L01-W-012-FB | L01 | CT-L01-W-012-FB | L01 | West | Stone cladding | 1250 | 50 | Warm beige stone | CT-104 | CT-L01-W-012
CT-L01-W-012-FT | L01 | CT-L01-W-012-FT | L01 | West | Stone cladding | 1250 | 50 | Warm beige stone | CT-104 | CT-L01-W-012
CT-L02-S-001-ML | L02 | CT-L02-S-001-ML | L02 | South | Curtain wall | 50 | 3900 | Blue-grey concept glass | CT-101 | CT-L02-S-001
CT-L02-S-001-MR | L02 | CT-L02-S-001-MR | L02 | South | Curtain wall | 50 | 3900 | Blue-grey concept glass | CT-101 | CT-L02-S-001
CT-L02-S-001-FB | L02 | CT-L02-S-001-FB | L02 | South | Curtain wall | 1250 | 50 | Blue-grey concept glass | CT-101 | CT-L02-S-001
CT-L02-S-001-FT | L02 | CT-L02-S-001-FT | L02 | South | Curtain wall | 1250 | 50 | Blue-grey concept glass | CT-101 | CT-L02-S-001
CT-L02-S-002-ML | L02 | CT-L02-S-002-ML | L02 | South | Curtain wall | 50 | 3900 | Blue-grey concept glass | CT-101 | CT-L02-S-002
CT-L02-S-002-MR | L02 | CT-L02-S-002-MR | L02 | South | Curtain wall | 50 | 3900 | Blue-grey concept glass | CT-101 | CT-L02-S-002
CT-L02-S-002-FB | L02 | CT-L02-S-002-FB | L02 | South | Curtain wall | 1400 | 50 | Blue-grey concept glass | CT-101 | CT-L02-S-002
CT-L02-S-002-FT | L02 | CT-L02-S-002-FT | L02 | South | Curtain wall | 1400 | 50 | Blue-grey concept glass | CT-101 | CT-L02-S-002
CT-L02-S-003-ML | L02 | CT-L02-S-003-ML | L02 | South | Curtain wall | 50 | 3900 | Blue-grey concept glass | CT-101 | CT-L02-S-003
CT-L02-S-003-MR | L02 | CT-L02-S-003-MR | L02 | South | Curtain wall | 50 | 3900 | Blue-grey concept glass | CT-101 | CT-L02-S-003
CT-L02-S-003-FB | L02 | CT-L02-S-003-FB | L02 | South | Curtain wall | 1400 | 50 | Blue-grey concept glass | CT-101 | CT-L02-S-003
CT-L02-S-003-FT | L02 | CT-L02-S-003-FT | L02 | South | Curtain wall | 1400 | 50 | Blue-grey concept glass | CT-101 | CT-L02-S-003
CT-L02-S-004-ML | L02 | CT-L02-S-004-ML | L02 | South | Stone cladding | 50 | 3900 | Warm beige stone | CT-101 | CT-L02-S-004
CT-L02-S-004-MR | L02 | CT-L02-S-004-MR | L02 | South | Stone cladding | 50 | 3900 | Warm beige stone | CT-101 | CT-L02-S-004
CT-L02-S-004-FB | L02 | CT-L02-S-004-FB | L02 | South | Stone cladding | 1400 | 50 | Warm beige stone | CT-101 | CT-L02-S-004
CT-L02-S-004-FT | L02 | CT-L02-S-004-FT | L02 | South | Stone cladding | 1400 | 50 | Warm beige stone | CT-101 | CT-L02-S-004
CT-L02-S-005-ML | L02 | CT-L02-S-005-ML | L02 | South | Metal rainscreen | 50 | 3900 | Olive powder coat | CT-101 | CT-L02-S-005
CT-L02-S-005-MR | L02 | CT-L02-S-005-MR | L02 | South | Metal rainscreen | 50 | 3900 | Olive powder coat | CT-101 | CT-L02-S-005
CT-L02-S-005-FB | L02 | CT-L02-S-005-FB | L02 | South | Metal rainscreen | 1400 | 50 | Olive powder coat | CT-101 | CT-L02-S-005
CT-L02-S-005-FT | L02 | CT-L02-S-005-FT | L02 | South | Metal rainscreen | 1400 | 50 | Olive powder coat | CT-101 | CT-L02-S-005
CT-L02-S-006-ML | L02 | CT-L02-S-006-ML | L02 | South | Curtain wall | 50 | 3900 | Blue-grey concept glass | CT-101 | CT-L02-S-006
CT-L02-S-006-MR | L02 | CT-L02-S-006-MR | L02 | South | Curtain wall | 50 | 3900 | Blue-grey concept glass | CT-101 | CT-L02-S-006
CT-L02-S-006-FB | L02 | CT-L02-S-006-FB | L02 | South | Curtain wall | 1400 | 50 | Blue-grey concept glass | CT-101 | CT-L02-S-006
CT-L02-S-006-FT | L02 | CT-L02-S-006-FT | L02 | South | Curtain wall | 1400 | 50 | Blue-grey concept glass | CT-101 | CT-L02-S-006
CT-L02-S-007-ML | L02 | CT-L02-S-007-ML | L02 | South | Curtain wall | 50 | 3900 | Blue-grey concept glass | CT-101 | CT-L02-S-007
CT-L02-S-007-MR | L02 | CT-L02-S-007-MR | L02 | South | Curtain wall | 50 | 3900 | Blue-grey concept glass | CT-101 | CT-L02-S-007
CT-L02-S-007-FB | L02 | CT-L02-S-007-FB | L02 | South | Curtain wall | 1400 | 50 | Blue-grey concept glass | CT-101 | CT-L02-S-007
CT-L02-S-007-FT | L02 | CT-L02-S-007-FT | L02 | South | Curtain wall | 1400 | 50 | Blue-grey concept glass | CT-101 | CT-L02-S-007
CT-L02-S-008-ML | L02 | CT-L02-S-008-ML | L02 | South | Stone cladding | 50 | 3900 | Warm beige stone | CT-101 | CT-L02-S-008
CT-L02-S-008-MR | L02 | CT-L02-S-008-MR | L02 | South | Stone cladding | 50 | 3900 | Warm beige stone | CT-101 | CT-L02-S-008
CT-L02-S-008-FB | L02 | CT-L02-S-008-FB | L02 | South | Stone cladding | 1400 | 50 | Warm beige stone | CT-101 | CT-L02-S-008
CT-L02-S-008-FT | L02 | CT-L02-S-008-FT | L02 | South | Stone cladding | 1400 | 50 | Warm beige stone | CT-101 | CT-L02-S-008
CT-L02-S-009-ML | L02 | CT-L02-S-009-ML | L02 | South | Curtain wall | 50 | 3900 | Blue-grey concept glass | CT-101 | CT-L02-S-009
CT-L02-S-009-MR | L02 | CT-L02-S-009-MR | L02 | South | Curtain wall | 50 | 3900 | Blue-grey concept glass | CT-101 | CT-L02-S-009
CT-L02-S-009-FB | L02 | CT-L02-S-009-FB | L02 | South | Curtain wall | 1400 | 50 | Blue-grey concept glass | CT-101 | CT-L02-S-009
CT-L02-S-009-FT | L02 | CT-L02-S-009-FT | L02 | South | Curtain wall | 1400 | 50 | Blue-grey concept glass | CT-101 | CT-L02-S-009
CT-L02-S-010-ML | L02 | CT-L02-S-010-ML | L02 | South | Metal rainscreen | 50 | 3900 | Olive powder coat | CT-101 | CT-L02-S-010
CT-L02-S-010-MR | L02 | CT-L02-S-010-MR | L02 | South | Metal rainscreen | 50 | 3900 | Olive powder coat | CT-101 | CT-L02-S-010
CT-L02-S-010-FB | L02 | CT-L02-S-010-FB | L02 | South | Metal rainscreen | 1400 | 50 | Olive powder coat | CT-101 | CT-L02-S-010
CT-L02-S-010-FT | L02 | CT-L02-S-010-FT | L02 | South | Metal rainscreen | 1400 | 50 | Olive powder coat | CT-101 | CT-L02-S-010
CT-L02-S-011-ML | L02 | CT-L02-S-011-ML | L02 | South | Curtain wall | 50 | 3900 | Blue-grey concept glass | CT-101 | CT-L02-S-011
CT-L02-S-011-MR | L02 | CT-L02-S-011-MR | L02 | South | Curtain wall | 50 | 3900 | Blue-grey concept glass | CT-101 | CT-L02-S-011
CT-L02-S-011-FB | L02 | CT-L02-S-011-FB | L02 | South | Curtain wall | 1400 | 50 | Blue-grey concept glass | CT-101 | CT-L02-S-011
CT-L02-S-011-FT | L02 | CT-L02-S-011-FT | L02 | South | Curtain wall | 1400 | 50 | Blue-grey concept glass | CT-101 | CT-L02-S-011
CT-L02-S-012-ML | L02 | CT-L02-S-012-ML | L02 | South | Stone cladding | 50 | 3900 | Warm beige stone | CT-101 | CT-L02-S-012
CT-L02-S-012-MR | L02 | CT-L02-S-012-MR | L02 | South | Stone cladding | 50 | 3900 | Warm beige stone | CT-101 | CT-L02-S-012
CT-L02-S-012-FB | L02 | CT-L02-S-012-FB | L02 | South | Stone cladding | 1400 | 50 | Warm beige stone | CT-101 | CT-L02-S-012
CT-L02-S-012-FT | L02 | CT-L02-S-012-FT | L02 | South | Stone cladding | 1400 | 50 | Warm beige stone | CT-101 | CT-L02-S-012
CT-L02-S-013-ML | L02 | CT-L02-S-013-ML | L02 | South | Curtain wall | 50 | 3900 | Blue-grey concept glass | CT-101 | CT-L02-S-013
CT-L02-S-013-MR | L02 | CT-L02-S-013-MR | L02 | South | Curtain wall | 50 | 3900 | Blue-grey concept glass | CT-101 | CT-L02-S-013
CT-L02-S-013-FB | L02 | CT-L02-S-013-FB | L02 | South | Curtain wall | 1400 | 50 | Blue-grey concept glass | CT-101 | CT-L02-S-013
CT-L02-S-013-FT | L02 | CT-L02-S-013-FT | L02 | South | Curtain wall | 1400 | 50 | Blue-grey concept glass | CT-101 | CT-L02-S-013
CT-L02-S-014-ML | L02 | CT-L02-S-014-ML | L02 | South | Curtain wall | 50 | 3900 | Blue-grey concept glass | CT-101 | CT-L02-S-014
CT-L02-S-014-MR | L02 | CT-L02-S-014-MR | L02 | South | Curtain wall | 50 | 3900 | Blue-grey concept glass | CT-101 | CT-L02-S-014
CT-L02-S-014-FB | L02 | CT-L02-S-014-FB | L02 | South | Curtain wall | 1400 | 50 | Blue-grey concept glass | CT-101 | CT-L02-S-014
CT-L02-S-014-FT | L02 | CT-L02-S-014-FT | L02 | South | Curtain wall | 1400 | 50 | Blue-grey concept glass | CT-101 | CT-L02-S-014
CT-L02-S-015-ML | L02 | CT-L02-S-015-ML | L02 | South | Metal rainscreen | 50 | 3900 | Olive powder coat | CT-101 | CT-L02-S-015
CT-L02-S-015-MR | L02 | CT-L02-S-015-MR | L02 | South | Metal rainscreen | 50 | 3900 | Olive powder coat | CT-101 | CT-L02-S-015
CT-L02-S-015-FB | L02 | CT-L02-S-015-FB | L02 | South | Metal rainscreen | 1400 | 50 | Olive powder coat | CT-101 | CT-L02-S-015
CT-L02-S-015-FT | L02 | CT-L02-S-015-FT | L02 | South | Metal rainscreen | 1400 | 50 | Olive powder coat | CT-101 | CT-L02-S-015
CT-L02-S-016-ML | L02 | CT-L02-S-016-ML | L02 | South | Stone cladding | 50 | 3900 | Warm beige stone | CT-101 | CT-L02-S-016
CT-L02-S-016-MR | L02 | CT-L02-S-016-MR | L02 | South | Stone cladding | 50 | 3900 | Warm beige stone | CT-101 | CT-L02-S-016
CT-L02-S-016-FB | L02 | CT-L02-S-016-FB | L02 | South | Stone cladding | 1400 | 50 | Warm beige stone | CT-101 | CT-L02-S-016
CT-L02-S-016-FT | L02 | CT-L02-S-016-FT | L02 | South | Stone cladding | 1400 | 50 | Warm beige stone | CT-101 | CT-L02-S-016
CT-L02-S-017-ML | L02 | CT-L02-S-017-ML | L02 | South | Curtain wall | 50 | 3900 | Blue-grey concept glass | CT-101 | CT-L02-S-017
CT-L02-S-017-MR | L02 | CT-L02-S-017-MR | L02 | South | Curtain wall | 50 | 3900 | Blue-grey concept glass | CT-101 | CT-L02-S-017
CT-L02-S-017-FB | L02 | CT-L02-S-017-FB | L02 | South | Curtain wall | 1400 | 50 | Blue-grey concept glass | CT-101 | CT-L02-S-017
CT-L02-S-017-FT | L02 | CT-L02-S-017-FT | L02 | South | Curtain wall | 1400 | 50 | Blue-grey concept glass | CT-101 | CT-L02-S-017
CT-L02-S-018-ML | L02 | CT-L02-S-018-ML | L02 | South | Curtain wall | 50 | 3900 | Blue-grey concept glass | CT-101 | CT-L02-S-018
CT-L02-S-018-MR | L02 | CT-L02-S-018-MR | L02 | South | Curtain wall | 50 | 3900 | Blue-grey concept glass | CT-101 | CT-L02-S-018
CT-L02-S-018-FB | L02 | CT-L02-S-018-FB | L02 | South | Curtain wall | 1250 | 50 | Blue-grey concept glass | CT-101 | CT-L02-S-018
CT-L02-S-018-FT | L02 | CT-L02-S-018-FT | L02 | South | Curtain wall | 1250 | 50 | Blue-grey concept glass | CT-101 | CT-L02-S-018
CT-L02-E-001-ML | L02 | CT-L02-E-001-ML | L02 | East | Curtain wall | 50 | 3900 | Blue-grey concept glass | CT-102 | CT-L02-E-001
CT-L02-E-001-MR | L02 | CT-L02-E-001-MR | L02 | East | Curtain wall | 50 | 3900 | Blue-grey concept glass | CT-102 | CT-L02-E-001
CT-L02-E-001-FB | L02 | CT-L02-E-001-FB | L02 | East | Curtain wall | 1250 | 50 | Blue-grey concept glass | CT-102 | CT-L02-E-001
CT-L02-E-001-FT | L02 | CT-L02-E-001-FT | L02 | East | Curtain wall | 1250 | 50 | Blue-grey concept glass | CT-102 | CT-L02-E-001
CT-L02-E-002-ML | L02 | CT-L02-E-002-ML | L02 | East | Curtain wall | 50 | 3900 | Blue-grey concept glass | CT-102 | CT-L02-E-002
CT-L02-E-002-MR | L02 | CT-L02-E-002-MR | L02 | East | Curtain wall | 50 | 3900 | Blue-grey concept glass | CT-102 | CT-L02-E-002
CT-L02-E-002-FB | L02 | CT-L02-E-002-FB | L02 | East | Curtain wall | 1400 | 50 | Blue-grey concept glass | CT-102 | CT-L02-E-002
CT-L02-E-002-FT | L02 | CT-L02-E-002-FT | L02 | East | Curtain wall | 1400 | 50 | Blue-grey concept glass | CT-102 | CT-L02-E-002
CT-L02-E-003-ML | L02 | CT-L02-E-003-ML | L02 | East | Curtain wall | 50 | 3900 | Blue-grey concept glass | CT-102 | CT-L02-E-003
CT-L02-E-003-MR | L02 | CT-L02-E-003-MR | L02 | East | Curtain wall | 50 | 3900 | Blue-grey concept glass | CT-102 | CT-L02-E-003
CT-L02-E-003-FB | L02 | CT-L02-E-003-FB | L02 | East | Curtain wall | 1400 | 50 | Blue-grey concept glass | CT-102 | CT-L02-E-003
CT-L02-E-003-FT | L02 | CT-L02-E-003-FT | L02 | East | Curtain wall | 1400 | 50 | Blue-grey concept glass | CT-102 | CT-L02-E-003
CT-L02-E-004-ML | L02 | CT-L02-E-004-ML | L02 | East | Stone cladding | 50 | 3900 | Warm beige stone | CT-102 | CT-L02-E-004
CT-L02-E-004-MR | L02 | CT-L02-E-004-MR | L02 | East | Stone cladding | 50 | 3900 | Warm beige stone | CT-102 | CT-L02-E-004
CT-L02-E-004-FB | L02 | CT-L02-E-004-FB | L02 | East | Stone cladding | 1400 | 50 | Warm beige stone | CT-102 | CT-L02-E-004
CT-L02-E-004-FT | L02 | CT-L02-E-004-FT | L02 | East | Stone cladding | 1400 | 50 | Warm beige stone | CT-102 | CT-L02-E-004
CT-L02-E-005-ML | L02 | CT-L02-E-005-ML | L02 | East | Metal rainscreen | 50 | 3900 | Olive powder coat | CT-102 | CT-L02-E-005
CT-L02-E-005-MR | L02 | CT-L02-E-005-MR | L02 | East | Metal rainscreen | 50 | 3900 | Olive powder coat | CT-102 | CT-L02-E-005
CT-L02-E-005-FB | L02 | CT-L02-E-005-FB | L02 | East | Metal rainscreen | 1400 | 50 | Olive powder coat | CT-102 | CT-L02-E-005
CT-L02-E-005-FT | L02 | CT-L02-E-005-FT | L02 | East | Metal rainscreen | 1400 | 50 | Olive powder coat | CT-102 | CT-L02-E-005
CT-L02-E-006-ML | L02 | CT-L02-E-006-ML | L02 | East | Curtain wall | 50 | 3900 | Blue-grey concept glass | CT-102 | CT-L02-E-006
CT-L02-E-006-MR | L02 | CT-L02-E-006-MR | L02 | East | Curtain wall | 50 | 3900 | Blue-grey concept glass | CT-102 | CT-L02-E-006
CT-L02-E-006-FB | L02 | CT-L02-E-006-FB | L02 | East | Curtain wall | 1400 | 50 | Blue-grey concept glass | CT-102 | CT-L02-E-006
CT-L02-E-006-FT | L02 | CT-L02-E-006-FT | L02 | East | Curtain wall | 1400 | 50 | Blue-grey concept glass | CT-102 | CT-L02-E-006
CT-L02-E-007-ML | L02 | CT-L02-E-007-ML | L02 | East | Curtain wall | 50 | 3900 | Blue-grey concept glass | CT-102 | CT-L02-E-007
CT-L02-E-007-MR | L02 | CT-L02-E-007-MR | L02 | East | Curtain wall | 50 | 3900 | Blue-grey concept glass | CT-102 | CT-L02-E-007
CT-L02-E-007-FB | L02 | CT-L02-E-007-FB | L02 | East | Curtain wall | 1400 | 50 | Blue-grey concept glass | CT-102 | CT-L02-E-007
CT-L02-E-007-FT | L02 | CT-L02-E-007-FT | L02 | East | Curtain wall | 1400 | 50 | Blue-grey concept glass | CT-102 | CT-L02-E-007
CT-L02-E-008-ML | L02 | CT-L02-E-008-ML | L02 | East | Stone cladding | 50 | 3900 | Warm beige stone | CT-102 | CT-L02-E-008
CT-L02-E-008-MR | L02 | CT-L02-E-008-MR | L02 | East | Stone cladding | 50 | 3900 | Warm beige stone | CT-102 | CT-L02-E-008
CT-L02-E-008-FB | L02 | CT-L02-E-008-FB | L02 | East | Stone cladding | 1400 | 50 | Warm beige stone | CT-102 | CT-L02-E-008
CT-L02-E-008-FT | L02 | CT-L02-E-008-FT | L02 | East | Stone cladding | 1400 | 50 | Warm beige stone | CT-102 | CT-L02-E-008
CT-L02-E-009-ML | L02 | CT-L02-E-009-ML | L02 | East | Curtain wall | 50 | 3900 | Blue-grey concept glass | CT-102 | CT-L02-E-009
CT-L02-E-009-MR | L02 | CT-L02-E-009-MR | L02 | East | Curtain wall | 50 | 3900 | Blue-grey concept glass | CT-102 | CT-L02-E-009
CT-L02-E-009-FB | L02 | CT-L02-E-009-FB | L02 | East | Curtain wall | 1400 | 50 | Blue-grey concept glass | CT-102 | CT-L02-E-009
CT-L02-E-009-FT | L02 | CT-L02-E-009-FT | L02 | East | Curtain wall | 1400 | 50 | Blue-grey concept glass | CT-102 | CT-L02-E-009
CT-L02-E-010-ML | L02 | CT-L02-E-010-ML | L02 | East | Metal rainscreen | 50 | 3900 | Olive powder coat | CT-102 | CT-L02-E-010
CT-L02-E-010-MR | L02 | CT-L02-E-010-MR | L02 | East | Metal rainscreen | 50 | 3900 | Olive powder coat | CT-102 | CT-L02-E-010
CT-L02-E-010-FB | L02 | CT-L02-E-010-FB | L02 | East | Metal rainscreen | 1400 | 50 | Olive powder coat | CT-102 | CT-L02-E-010
CT-L02-E-010-FT | L02 | CT-L02-E-010-FT | L02 | East | Metal rainscreen | 1400 | 50 | Olive powder coat | CT-102 | CT-L02-E-010
CT-L02-E-011-ML | L02 | CT-L02-E-011-ML | L02 | East | Curtain wall | 50 | 3900 | Blue-grey concept glass | CT-102 | CT-L02-E-011
CT-L02-E-011-MR | L02 | CT-L02-E-011-MR | L02 | East | Curtain wall | 50 | 3900 | Blue-grey concept glass | CT-102 | CT-L02-E-011
CT-L02-E-011-FB | L02 | CT-L02-E-011-FB | L02 | East | Curtain wall | 1400 | 50 | Blue-grey concept glass | CT-102 | CT-L02-E-011
CT-L02-E-011-FT | L02 | CT-L02-E-011-FT | L02 | East | Curtain wall | 1400 | 50 | Blue-grey concept glass | CT-102 | CT-L02-E-011
CT-L02-E-012-ML | L02 | CT-L02-E-012-ML | L02 | East | Stone cladding | 50 | 3900 | Warm beige stone | CT-102 | CT-L02-E-012
CT-L02-E-012-MR | L02 | CT-L02-E-012-MR | L02 | East | Stone cladding | 50 | 3900 | Warm beige stone | CT-102 | CT-L02-E-012
CT-L02-E-012-FB | L02 | CT-L02-E-012-FB | L02 | East | Stone cladding | 1250 | 50 | Warm beige stone | CT-102 | CT-L02-E-012
CT-L02-E-012-FT | L02 | CT-L02-E-012-FT | L02 | East | Stone cladding | 1250 | 50 | Warm beige stone | CT-102 | CT-L02-E-012
CT-L02-N-001-ML | L02 | CT-L02-N-001-ML | L02 | North | Curtain wall | 50 | 3900 | Blue-grey concept glass | CT-103 | CT-L02-N-001
CT-L02-N-001-MR | L02 | CT-L02-N-001-MR | L02 | North | Curtain wall | 50 | 3900 | Blue-grey concept glass | CT-103 | CT-L02-N-001
CT-L02-N-001-FB | L02 | CT-L02-N-001-FB | L02 | North | Curtain wall | 1250 | 50 | Blue-grey concept glass | CT-103 | CT-L02-N-001
CT-L02-N-001-FT | L02 | CT-L02-N-001-FT | L02 | North | Curtain wall | 1250 | 50 | Blue-grey concept glass | CT-103 | CT-L02-N-001
CT-L02-N-002-ML | L02 | CT-L02-N-002-ML | L02 | North | Curtain wall | 50 | 3900 | Blue-grey concept glass | CT-103 | CT-L02-N-002
CT-L02-N-002-MR | L02 | CT-L02-N-002-MR | L02 | North | Curtain wall | 50 | 3900 | Blue-grey concept glass | CT-103 | CT-L02-N-002
CT-L02-N-002-FB | L02 | CT-L02-N-002-FB | L02 | North | Curtain wall | 1400 | 50 | Blue-grey concept glass | CT-103 | CT-L02-N-002
CT-L02-N-002-FT | L02 | CT-L02-N-002-FT | L02 | North | Curtain wall | 1400 | 50 | Blue-grey concept glass | CT-103 | CT-L02-N-002
CT-L02-N-003-ML | L02 | CT-L02-N-003-ML | L02 | North | Curtain wall | 50 | 3900 | Blue-grey concept glass | CT-103 | CT-L02-N-003
CT-L02-N-003-MR | L02 | CT-L02-N-003-MR | L02 | North | Curtain wall | 50 | 3900 | Blue-grey concept glass | CT-103 | CT-L02-N-003
CT-L02-N-003-FB | L02 | CT-L02-N-003-FB | L02 | North | Curtain wall | 1400 | 50 | Blue-grey concept glass | CT-103 | CT-L02-N-003
CT-L02-N-003-FT | L02 | CT-L02-N-003-FT | L02 | North | Curtain wall | 1400 | 50 | Blue-grey concept glass | CT-103 | CT-L02-N-003
CT-L02-N-004-ML | L02 | CT-L02-N-004-ML | L02 | North | Stone cladding | 50 | 3900 | Warm beige stone | CT-103 | CT-L02-N-004
CT-L02-N-004-MR | L02 | CT-L02-N-004-MR | L02 | North | Stone cladding | 50 | 3900 | Warm beige stone | CT-103 | CT-L02-N-004
CT-L02-N-004-FB | L02 | CT-L02-N-004-FB | L02 | North | Stone cladding | 1400 | 50 | Warm beige stone | CT-103 | CT-L02-N-004
CT-L02-N-004-FT | L02 | CT-L02-N-004-FT | L02 | North | Stone cladding | 1400 | 50 | Warm beige stone | CT-103 | CT-L02-N-004
CT-L02-N-005-ML | L02 | CT-L02-N-005-ML | L02 | North | Metal rainscreen | 50 | 3900 | Olive powder coat | CT-103 | CT-L02-N-005
CT-L02-N-005-MR | L02 | CT-L02-N-005-MR | L02 | North | Metal rainscreen | 50 | 3900 | Olive powder coat | CT-103 | CT-L02-N-005
CT-L02-N-005-FB | L02 | CT-L02-N-005-FB | L02 | North | Metal rainscreen | 1400 | 50 | Olive powder coat | CT-103 | CT-L02-N-005
CT-L02-N-005-FT | L02 | CT-L02-N-005-FT | L02 | North | Metal rainscreen | 1400 | 50 | Olive powder coat | CT-103 | CT-L02-N-005
CT-L02-N-006-ML | L02 | CT-L02-N-006-ML | L02 | North | Curtain wall | 50 | 3900 | Blue-grey concept glass | CT-103 | CT-L02-N-006
CT-L02-N-006-MR | L02 | CT-L02-N-006-MR | L02 | North | Curtain wall | 50 | 3900 | Blue-grey concept glass | CT-103 | CT-L02-N-006
CT-L02-N-006-FB | L02 | CT-L02-N-006-FB | L02 | North | Curtain wall | 1400 | 50 | Blue-grey concept glass | CT-103 | CT-L02-N-006
CT-L02-N-006-FT | L02 | CT-L02-N-006-FT | L02 | North | Curtain wall | 1400 | 50 | Blue-grey concept glass | CT-103 | CT-L02-N-006
CT-L02-N-007-ML | L02 | CT-L02-N-007-ML | L02 | North | Curtain wall | 50 | 3900 | Blue-grey concept glass | CT-103 | CT-L02-N-007
CT-L02-N-007-MR | L02 | CT-L02-N-007-MR | L02 | North | Curtain wall | 50 | 3900 | Blue-grey concept glass | CT-103 | CT-L02-N-007
CT-L02-N-007-FB | L02 | CT-L02-N-007-FB | L02 | North | Curtain wall | 1400 | 50 | Blue-grey concept glass | CT-103 | CT-L02-N-007
CT-L02-N-007-FT | L02 | CT-L02-N-007-FT | L02 | North | Curtain wall | 1400 | 50 | Blue-grey concept glass | CT-103 | CT-L02-N-007
CT-L02-N-008-ML | L02 | CT-L02-N-008-ML | L02 | North | Stone cladding | 50 | 3900 | Warm beige stone | CT-103 | CT-L02-N-008
CT-L02-N-008-MR | L02 | CT-L02-N-008-MR | L02 | North | Stone cladding | 50 | 3900 | Warm beige stone | CT-103 | CT-L02-N-008
CT-L02-N-008-FB | L02 | CT-L02-N-008-FB | L02 | North | Stone cladding | 1400 | 50 | Warm beige stone | CT-103 | CT-L02-N-008
CT-L02-N-008-FT | L02 | CT-L02-N-008-FT | L02 | North | Stone cladding | 1400 | 50 | Warm beige stone | CT-103 | CT-L02-N-008
CT-L02-N-009-ML | L02 | CT-L02-N-009-ML | L02 | North | Curtain wall | 50 | 3900 | Blue-grey concept glass | CT-103 | CT-L02-N-009
CT-L02-N-009-MR | L02 | CT-L02-N-009-MR | L02 | North | Curtain wall | 50 | 3900 | Blue-grey concept glass | CT-103 | CT-L02-N-009
CT-L02-N-009-FB | L02 | CT-L02-N-009-FB | L02 | North | Curtain wall | 1400 | 50 | Blue-grey concept glass | CT-103 | CT-L02-N-009
CT-L02-N-009-FT | L02 | CT-L02-N-009-FT | L02 | North | Curtain wall | 1400 | 50 | Blue-grey concept glass | CT-103 | CT-L02-N-009
CT-L02-N-010-ML | L02 | CT-L02-N-010-ML | L02 | North | Metal rainscreen | 50 | 3900 | Olive powder coat | CT-103 | CT-L02-N-010
CT-L02-N-010-MR | L02 | CT-L02-N-010-MR | L02 | North | Metal rainscreen | 50 | 3900 | Olive powder coat | CT-103 | CT-L02-N-010
CT-L02-N-010-FB | L02 | CT-L02-N-010-FB | L02 | North | Metal rainscreen | 1400 | 50 | Olive powder coat | CT-103 | CT-L02-N-010
CT-L02-N-010-FT | L02 | CT-L02-N-010-FT | L02 | North | Metal rainscreen | 1400 | 50 | Olive powder coat | CT-103 | CT-L02-N-010
CT-L02-N-011-ML | L02 | CT-L02-N-011-ML | L02 | North | Curtain wall | 50 | 3900 | Blue-grey concept glass | CT-103 | CT-L02-N-011
CT-L02-N-011-MR | L02 | CT-L02-N-011-MR | L02 | North | Curtain wall | 50 | 3900 | Blue-grey concept glass | CT-103 | CT-L02-N-011
CT-L02-N-011-FB | L02 | CT-L02-N-011-FB | L02 | North | Curtain wall | 1400 | 50 | Blue-grey concept glass | CT-103 | CT-L02-N-011
CT-L02-N-011-FT | L02 | CT-L02-N-011-FT | L02 | North | Curtain wall | 1400 | 50 | Blue-grey concept glass | CT-103 | CT-L02-N-011
CT-L02-N-012-ML | L02 | CT-L02-N-012-ML | L02 | North | Stone cladding | 50 | 3900 | Warm beige stone | CT-103 | CT-L02-N-012
CT-L02-N-012-MR | L02 | CT-L02-N-012-MR | L02 | North | Stone cladding | 50 | 3900 | Warm beige stone | CT-103 | CT-L02-N-012
CT-L02-N-012-FB | L02 | CT-L02-N-012-FB | L02 | North | Stone cladding | 1400 | 50 | Warm beige stone | CT-103 | CT-L02-N-012
CT-L02-N-012-FT | L02 | CT-L02-N-012-FT | L02 | North | Stone cladding | 1400 | 50 | Warm beige stone | CT-103 | CT-L02-N-012
CT-L02-N-013-ML | L02 | CT-L02-N-013-ML | L02 | North | Curtain wall | 50 | 3900 | Blue-grey concept glass | CT-103 | CT-L02-N-013
CT-L02-N-013-MR | L02 | CT-L02-N-013-MR | L02 | North | Curtain wall | 50 | 3900 | Blue-grey concept glass | CT-103 | CT-L02-N-013
CT-L02-N-013-FB | L02 | CT-L02-N-013-FB | L02 | North | Curtain wall | 1400 | 50 | Blue-grey concept glass | CT-103 | CT-L02-N-013
CT-L02-N-013-FT | L02 | CT-L02-N-013-FT | L02 | North | Curtain wall | 1400 | 50 | Blue-grey concept glass | CT-103 | CT-L02-N-013
CT-L02-N-014-ML | L02 | CT-L02-N-014-ML | L02 | North | Curtain wall | 50 | 3900 | Blue-grey concept glass | CT-103 | CT-L02-N-014
CT-L02-N-014-MR | L02 | CT-L02-N-014-MR | L02 | North | Curtain wall | 50 | 3900 | Blue-grey concept glass | CT-103 | CT-L02-N-014
CT-L02-N-014-FB | L02 | CT-L02-N-014-FB | L02 | North | Curtain wall | 1400 | 50 | Blue-grey concept glass | CT-103 | CT-L02-N-014
CT-L02-N-014-FT | L02 | CT-L02-N-014-FT | L02 | North | Curtain wall | 1400 | 50 | Blue-grey concept glass | CT-103 | CT-L02-N-014
CT-L02-N-015-ML | L02 | CT-L02-N-015-ML | L02 | North | Metal rainscreen | 50 | 3900 | Olive powder coat | CT-103 | CT-L02-N-015
CT-L02-N-015-MR | L02 | CT-L02-N-015-MR | L02 | North | Metal rainscreen | 50 | 3900 | Olive powder coat | CT-103 | CT-L02-N-015
CT-L02-N-015-FB | L02 | CT-L02-N-015-FB | L02 | North | Metal rainscreen | 1400 | 50 | Olive powder coat | CT-103 | CT-L02-N-015
CT-L02-N-015-FT | L02 | CT-L02-N-015-FT | L02 | North | Metal rainscreen | 1400 | 50 | Olive powder coat | CT-103 | CT-L02-N-015
CT-L02-N-016-ML | L02 | CT-L02-N-016-ML | L02 | North | Stone cladding | 50 | 3900 | Warm beige stone | CT-103 | CT-L02-N-016
CT-L02-N-016-MR | L02 | CT-L02-N-016-MR | L02 | North | Stone cladding | 50 | 3900 | Warm beige stone | CT-103 | CT-L02-N-016
CT-L02-N-016-FB | L02 | CT-L02-N-016-FB | L02 | North | Stone cladding | 1400 | 50 | Warm beige stone | CT-103 | CT-L02-N-016
CT-L02-N-016-FT | L02 | CT-L02-N-016-FT | L02 | North | Stone cladding | 1400 | 50 | Warm beige stone | CT-103 | CT-L02-N-016
CT-L02-N-017-ML | L02 | CT-L02-N-017-ML | L02 | North | Curtain wall | 50 | 3900 | Blue-grey concept glass | CT-103 | CT-L02-N-017
CT-L02-N-017-MR | L02 | CT-L02-N-017-MR | L02 | North | Curtain wall | 50 | 3900 | Blue-grey concept glass | CT-103 | CT-L02-N-017
CT-L02-N-017-FB | L02 | CT-L02-N-017-FB | L02 | North | Curtain wall | 1400 | 50 | Blue-grey concept glass | CT-103 | CT-L02-N-017
CT-L02-N-017-FT | L02 | CT-L02-N-017-FT | L02 | North | Curtain wall | 1400 | 50 | Blue-grey concept glass | CT-103 | CT-L02-N-017
CT-L02-N-018-ML | L02 | CT-L02-N-018-ML | L02 | North | Curtain wall | 50 | 3900 | Blue-grey concept glass | CT-103 | CT-L02-N-018
CT-L02-N-018-MR | L02 | CT-L02-N-018-MR | L02 | North | Curtain wall | 50 | 3900 | Blue-grey concept glass | CT-103 | CT-L02-N-018
CT-L02-N-018-FB | L02 | CT-L02-N-018-FB | L02 | North | Curtain wall | 1250 | 50 | Blue-grey concept glass | CT-103 | CT-L02-N-018
CT-L02-N-018-FT | L02 | CT-L02-N-018-FT | L02 | North | Curtain wall | 1250 | 50 | Blue-grey concept glass | CT-103 | CT-L02-N-018
CT-L02-W-001-ML | L02 | CT-L02-W-001-ML | L02 | West | Curtain wall | 50 | 3900 | Blue-grey concept glass | CT-104 | CT-L02-W-001
CT-L02-W-001-MR | L02 | CT-L02-W-001-MR | L02 | West | Curtain wall | 50 | 3900 | Blue-grey concept glass | CT-104 | CT-L02-W-001
CT-L02-W-001-FB | L02 | CT-L02-W-001-FB | L02 | West | Curtain wall | 1250 | 50 | Blue-grey concept glass | CT-104 | CT-L02-W-001
CT-L02-W-001-FT | L02 | CT-L02-W-001-FT | L02 | West | Curtain wall | 1250 | 50 | Blue-grey concept glass | CT-104 | CT-L02-W-001
CT-L02-W-002-ML | L02 | CT-L02-W-002-ML | L02 | West | Curtain wall | 50 | 3900 | Blue-grey concept glass | CT-104 | CT-L02-W-002
CT-L02-W-002-MR | L02 | CT-L02-W-002-MR | L02 | West | Curtain wall | 50 | 3900 | Blue-grey concept glass | CT-104 | CT-L02-W-002
CT-L02-W-002-FB | L02 | CT-L02-W-002-FB | L02 | West | Curtain wall | 1400 | 50 | Blue-grey concept glass | CT-104 | CT-L02-W-002
CT-L02-W-002-FT | L02 | CT-L02-W-002-FT | L02 | West | Curtain wall | 1400 | 50 | Blue-grey concept glass | CT-104 | CT-L02-W-002
CT-L02-W-003-ML | L02 | CT-L02-W-003-ML | L02 | West | Curtain wall | 50 | 3900 | Blue-grey concept glass | CT-104 | CT-L02-W-003
CT-L02-W-003-MR | L02 | CT-L02-W-003-MR | L02 | West | Curtain wall | 50 | 3900 | Blue-grey concept glass | CT-104 | CT-L02-W-003
CT-L02-W-003-FB | L02 | CT-L02-W-003-FB | L02 | West | Curtain wall | 1400 | 50 | Blue-grey concept glass | CT-104 | CT-L02-W-003
CT-L02-W-003-FT | L02 | CT-L02-W-003-FT | L02 | West | Curtain wall | 1400 | 50 | Blue-grey concept glass | CT-104 | CT-L02-W-003
CT-L02-W-004-ML | L02 | CT-L02-W-004-ML | L02 | West | Stone cladding | 50 | 3900 | Warm beige stone | CT-104 | CT-L02-W-004
CT-L02-W-004-MR | L02 | CT-L02-W-004-MR | L02 | West | Stone cladding | 50 | 3900 | Warm beige stone | CT-104 | CT-L02-W-004
CT-L02-W-004-FB | L02 | CT-L02-W-004-FB | L02 | West | Stone cladding | 1400 | 50 | Warm beige stone | CT-104 | CT-L02-W-004
CT-L02-W-004-FT | L02 | CT-L02-W-004-FT | L02 | West | Stone cladding | 1400 | 50 | Warm beige stone | CT-104 | CT-L02-W-004
CT-L02-W-005-ML | L02 | CT-L02-W-005-ML | L02 | West | Metal rainscreen | 50 | 3900 | Olive powder coat | CT-104 | CT-L02-W-005
CT-L02-W-005-MR | L02 | CT-L02-W-005-MR | L02 | West | Metal rainscreen | 50 | 3900 | Olive powder coat | CT-104 | CT-L02-W-005
CT-L02-W-005-FB | L02 | CT-L02-W-005-FB | L02 | West | Metal rainscreen | 1400 | 50 | Olive powder coat | CT-104 | CT-L02-W-005
CT-L02-W-005-FT | L02 | CT-L02-W-005-FT | L02 | West | Metal rainscreen | 1400 | 50 | Olive powder coat | CT-104 | CT-L02-W-005
CT-L02-W-006-ML | L02 | CT-L02-W-006-ML | L02 | West | Curtain wall | 50 | 3900 | Blue-grey concept glass | CT-104 | CT-L02-W-006
CT-L02-W-006-MR | L02 | CT-L02-W-006-MR | L02 | West | Curtain wall | 50 | 3900 | Blue-grey concept glass | CT-104 | CT-L02-W-006
CT-L02-W-006-FB | L02 | CT-L02-W-006-FB | L02 | West | Curtain wall | 1400 | 50 | Blue-grey concept glass | CT-104 | CT-L02-W-006
CT-L02-W-006-FT | L02 | CT-L02-W-006-FT | L02 | West | Curtain wall | 1400 | 50 | Blue-grey concept glass | CT-104 | CT-L02-W-006
CT-L02-W-007-ML | L02 | CT-L02-W-007-ML | L02 | West | Curtain wall | 50 | 3900 | Blue-grey concept glass | CT-104 | CT-L02-W-007
CT-L02-W-007-MR | L02 | CT-L02-W-007-MR | L02 | West | Curtain wall | 50 | 3900 | Blue-grey concept glass | CT-104 | CT-L02-W-007
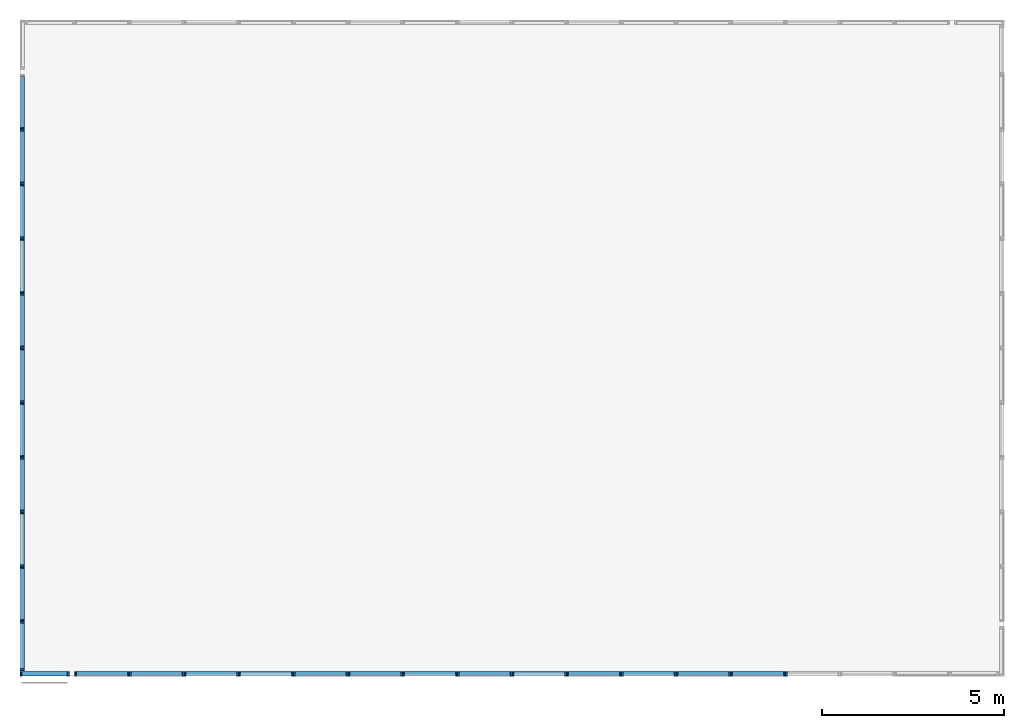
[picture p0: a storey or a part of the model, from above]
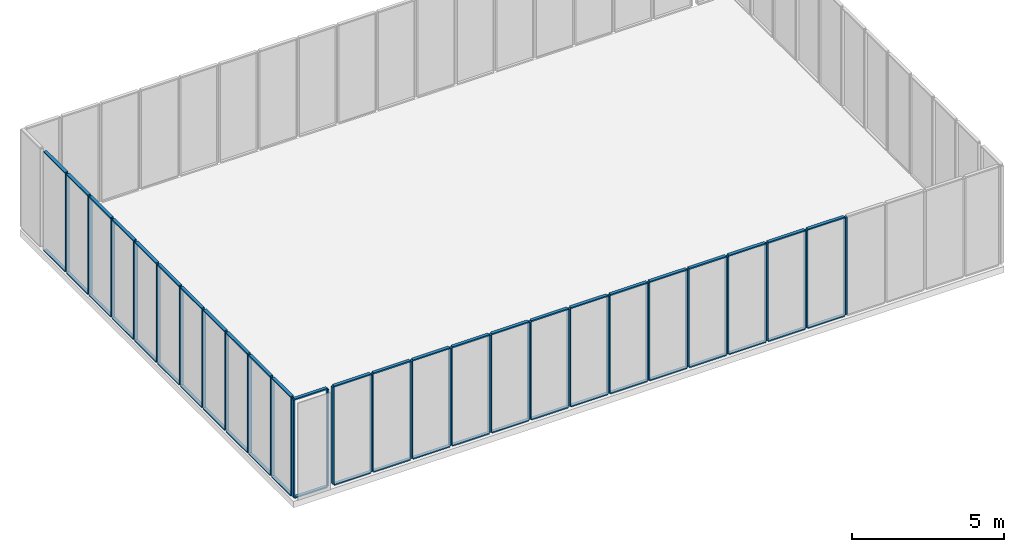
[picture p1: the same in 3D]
Properties of the parts of a building model (IFC4), part 2 of 7

# IfcMember (2304)
Name | In | ElementID | Floor | Elevation | System = Group | Width_mm | Height_mm | Finish | DrawingRef | ParentPanelID
CT-L02-W-007-FB | L02 | CT-L02-W-007-FB | L02 | West | Curtain wall | 1400 | 50 | Blue-grey concept glass | CT-104 | CT-L02-W-007
CT-L02-W-007-FT | L02 | CT-L02-W-007-FT | L02 | West | Curtain wall | 1400 | 50 | Blue-grey concept glass | CT-104 | CT-L02-W-007
CT-L02-W-008-ML | L02 | CT-L02-W-008-ML | L02 | West | Stone cladding | 50 | 3900 | Warm beige stone | CT-104 | CT-L02-W-008
CT-L02-W-008-MR | L02 | CT-L02-W-008-MR | L02 | West | Stone cladding | 50 | 3900 | Warm beige stone | CT-104 | CT-L02-W-008
CT-L02-W-008-FB | L02 | CT-L02-W-008-FB | L02 | West | Stone cladding | 1400 | 50 | Warm beige stone | CT-104 | CT-L02-W-008
CT-L02-W-008-FT | L02 | CT-L02-W-008-FT | L02 | West | Stone cladding | 1400 | 50 | Warm beige stone | CT-104 | CT-L02-W-008
CT-L02-W-009-ML | L02 | CT-L02-W-009-ML | L02 | West | Curtain wall | 50 | 3900 | Blue-grey concept glass | CT-104 | CT-L02-W-009
CT-L02-W-009-MR | L02 | CT-L02-W-009-MR | L02 | West | Curtain wall | 50 | 3900 | Blue-grey concept glass | CT-104 | CT-L02-W-009
CT-L02-W-009-FB | L02 | CT-L02-W-009-FB | L02 | West | Curtain wall | 1400 | 50 | Blue-grey concept glass | CT-104 | CT-L02-W-009
CT-L02-W-009-FT | L02 | CT-L02-W-009-FT | L02 | West | Curtain wall | 1400 | 50 | Blue-grey concept glass | CT-104 | CT-L02-W-009
CT-L02-W-010-ML | L02 | CT-L02-W-010-ML | L02 | West | Metal rainscreen | 50 | 3900 | Olive powder coat | CT-104 | CT-L02-W-010
CT-L02-W-010-MR | L02 | CT-L02-W-010-MR | L02 | West | Metal rainscreen | 50 | 3900 | Olive powder coat | CT-104 | CT-L02-W-010
CT-L02-W-010-FB | L02 | CT-L02-W-010-FB | L02 | West | Metal rainscreen | 1400 | 50 | Olive powder coat | CT-104 | CT-L02-W-010
CT-L02-W-010-FT | L02 | CT-L02-W-010-FT | L02 | West | Metal rainscreen | 1400 | 50 | Olive powder coat | CT-104 | CT-L02-W-010
CT-L02-W-011-ML | L02 | CT-L02-W-011-ML | L02 | West | Curtain wall | 50 | 3900 | Blue-grey concept glass | CT-104 | CT-L02-W-011
CT-L02-W-011-MR | L02 | CT-L02-W-011-MR | L02 | West | Curtain wall | 50 | 3900 | Blue-grey concept glass | CT-104 | CT-L02-W-011
CT-L02-W-011-FB | L02 | CT-L02-W-011-FB | L02 | West | Curtain wall | 1400 | 50 | Blue-grey concept glass | CT-104 | CT-L02-W-011
CT-L02-W-011-FT | L02 | CT-L02-W-011-FT | L02 | West | Curtain wall | 1400 | 50 | Blue-grey concept glass | CT-104 | CT-L02-W-011
CT-L02-W-012-ML | L02 | CT-L02-W-012-ML | L02 | West | Stone cladding | 50 | 3900 | Warm beige stone | CT-104 | CT-L02-W-012
CT-L02-W-012-MR | L02 | CT-L02-W-012-MR | L02 | West | Stone cladding | 50 | 3900 | Warm beige stone | CT-104 | CT-L02-W-012
CT-L02-W-012-FB | L02 | CT-L02-W-012-FB | L02 | West | Stone cladding | 1250 | 50 | Warm beige stone | CT-104 | CT-L02-W-012
CT-L02-W-012-FT | L02 | CT-L02-W-012-FT | L02 | West | Stone cladding | 1250 | 50 | Warm beige stone | CT-104 | CT-L02-W-012
CT-L03-S-001-ML | L03 | CT-L03-S-001-ML | L03 | South | Curtain wall | 50 | 3900 | Blue-grey concept glass | CT-101 | CT-L03-S-001
CT-L03-S-001-MR | L03 | CT-L03-S-001-MR | L03 | South | Curtain wall | 50 | 3900 | Blue-grey concept glass | CT-101 | CT-L03-S-001
CT-L03-S-001-FB | L03 | CT-L03-S-001-FB | L03 | South | Curtain wall | 1250 | 50 | Blue-grey concept glass | CT-101 | CT-L03-S-001
CT-L03-S-001-FT | L03 | CT-L03-S-001-FT | L03 | South | Curtain wall | 1250 | 50 | Blue-grey concept glass | CT-101 | CT-L03-S-001
CT-L03-S-002-ML | L03 | CT-L03-S-002-ML | L03 | South | Curtain wall | 50 | 3900 | Blue-grey concept glass | CT-101 | CT-L03-S-002
CT-L03-S-002-MR | L03 | CT-L03-S-002-MR | L03 | South | Curtain wall | 50 | 3900 | Blue-grey concept glass | CT-101 | CT-L03-S-002
CT-L03-S-002-FB | L03 | CT-L03-S-002-FB | L03 | South | Curtain wall | 1400 | 50 | Blue-grey concept glass | CT-101 | CT-L03-S-002
CT-L03-S-002-FT | L03 | CT-L03-S-002-FT | L03 | South | Curtain wall | 1400 | 50 | Blue-grey concept glass | CT-101 | CT-L03-S-002
CT-L03-S-003-ML | L03 | CT-L03-S-003-ML | L03 | South | Curtain wall | 50 | 3900 | Blue-grey concept glass | CT-101 | CT-L03-S-003
CT-L03-S-003-MR | L03 | CT-L03-S-003-MR | L03 | South | Curtain wall | 50 | 3900 | Blue-grey concept glass | CT-101 | CT-L03-S-003
CT-L03-S-003-FB | L03 | CT-L03-S-003-FB | L03 | South | Curtain wall | 1400 | 50 | Blue-grey concept glass | CT-101 | CT-L03-S-003
CT-L03-S-003-FT | L03 | CT-L03-S-003-FT | L03 | South | Curtain wall | 1400 | 50 | Blue-grey concept glass | CT-101 | CT-L03-S-003
CT-L03-S-004-ML | L03 | CT-L03-S-004-ML | L03 | South | Stone cladding | 50 | 3900 | Warm beige stone | CT-101 | CT-L03-S-004
CT-L03-S-004-MR | L03 | CT-L03-S-004-MR | L03 | South | Stone cladding | 50 | 3900 | Warm beige stone | CT-101 | CT-L03-S-004
CT-L03-S-004-FB | L03 | CT-L03-S-004-FB | L03 | South | Stone cladding | 1400 | 50 | Warm beige stone | CT-101 | CT-L03-S-004
CT-L03-S-004-FT | L03 | CT-L03-S-004-FT | L03 | South | Stone cladding | 1400 | 50 | Warm beige stone | CT-101 | CT-L03-S-004
CT-L03-S-005-ML | L03 | CT-L03-S-005-ML | L03 | South | Metal rainscreen | 50 | 3900 | Olive powder coat | CT-101 | CT-L03-S-005
CT-L03-S-005-MR | L03 | CT-L03-S-005-MR | L03 | South | Metal rainscreen | 50 | 3900 | Olive powder coat | CT-101 | CT-L03-S-005
CT-L03-S-005-FB | L03 | CT-L03-S-005-FB | L03 | South | Metal rainscreen | 1400 | 50 | Olive powder coat | CT-101 | CT-L03-S-005
CT-L03-S-005-FT | L03 | CT-L03-S-005-FT | L03 | South | Metal rainscreen | 1400 | 50 | Olive powder coat | CT-101 | CT-L03-S-005
CT-L03-S-006-ML | L03 | CT-L03-S-006-ML | L03 | South | Curtain wall | 50 | 3900 | Blue-grey concept glass | CT-101 | CT-L03-S-006
CT-L03-S-006-MR | L03 | CT-L03-S-006-MR | L03 | South | Curtain wall | 50 | 3900 | Blue-grey concept glass | CT-101 | CT-L03-S-006
CT-L03-S-006-FB | L03 | CT-L03-S-006-FB | L03 | South | Curtain wall | 1400 | 50 | Blue-grey concept glass | CT-101 | CT-L03-S-006
CT-L03-S-006-FT | L03 | CT-L03-S-006-FT | L03 | South | Curtain wall | 1400 | 50 | Blue-grey concept glass | CT-101 | CT-L03-S-006
CT-L03-S-007-ML | L03 | CT-L03-S-007-ML | L03 | South | Curtain wall | 50 | 3900 | Blue-grey concept glass | CT-101 | CT-L03-S-007
CT-L03-S-007-MR | L03 | CT-L03-S-007-MR | L03 | South | Curtain wall | 50 | 3900 | Blue-grey concept glass | CT-101 | CT-L03-S-007
CT-L03-S-007-FB | L03 | CT-L03-S-007-FB | L03 | South | Curtain wall | 1400 | 50 | Blue-grey concept glass | CT-101 | CT-L03-S-007
CT-L03-S-007-FT | L03 | CT-L03-S-007-FT | L03 | South | Curtain wall | 1400 | 50 | Blue-grey concept glass | CT-101 | CT-L03-S-007
CT-L03-S-008-ML | L03 | CT-L03-S-008-ML | L03 | South | Stone cladding | 50 | 3900 | Warm beige stone | CT-101 | CT-L03-S-008
CT-L03-S-008-MR | L03 | CT-L03-S-008-MR | L03 | South | Stone cladding | 50 | 3900 | Warm beige stone | CT-101 | CT-L03-S-008
CT-L03-S-008-FB | L03 | CT-L03-S-008-FB | L03 | South | Stone cladding | 1400 | 50 | Warm beige stone | CT-101 | CT-L03-S-008
CT-L03-S-008-FT | L03 | CT-L03-S-008-FT | L03 | South | Stone cladding | 1400 | 50 | Warm beige stone | CT-101 | CT-L03-S-008
CT-L03-S-009-ML | L03 | CT-L03-S-009-ML | L03 | South | Curtain wall | 50 | 3900 | Blue-grey concept glass | CT-101 | CT-L03-S-009
CT-L03-S-009-MR | L03 | CT-L03-S-009-MR | L03 | South | Curtain wall | 50 | 3900 | Blue-grey concept glass | CT-101 | CT-L03-S-009
CT-L03-S-009-FB | L03 | CT-L03-S-009-FB | L03 | South | Curtain wall | 1400 | 50 | Blue-grey concept glass | CT-101 | CT-L03-S-009
CT-L03-S-009-FT | L03 | CT-L03-S-009-FT | L03 | South | Curtain wall | 1400 | 50 | Blue-grey concept glass | CT-101 | CT-L03-S-009
CT-L03-S-010-ML | L03 | CT-L03-S-010-ML | L03 | South | Metal rainscreen | 50 | 3900 | Olive powder coat | CT-101 | CT-L03-S-010
CT-L03-S-010-MR | L03 | CT-L03-S-010-MR | L03 | South | Metal rainscreen | 50 | 3900 | Olive powder coat | CT-101 | CT-L03-S-010
CT-L03-S-010-FB | L03 | CT-L03-S-010-FB | L03 | South | Metal rainscreen | 1400 | 50 | Olive powder coat | CT-101 | CT-L03-S-010
CT-L03-S-010-FT | L03 | CT-L03-S-010-FT | L03 | South | Metal rainscreen | 1400 | 50 | Olive powder coat | CT-101 | CT-L03-S-010
CT-L03-S-011-ML | L03 | CT-L03-S-011-ML | L03 | South | Curtain wall | 50 | 3900 | Blue-grey concept glass | CT-101 | CT-L03-S-011
CT-L03-S-011-MR | L03 | CT-L03-S-011-MR | L03 | South | Curtain wall | 50 | 3900 | Blue-grey concept glass | CT-101 | CT-L03-S-011
CT-L03-S-011-FB | L03 | CT-L03-S-011-FB | L03 | South | Curtain wall | 1400 | 50 | Blue-grey concept glass | CT-101 | CT-L03-S-011
CT-L03-S-011-FT | L03 | CT-L03-S-011-FT | L03 | South | Curtain wall | 1400 | 50 | Blue-grey concept glass | CT-101 | CT-L03-S-011
CT-L03-S-012-ML | L03 | CT-L03-S-012-ML | L03 | South | Stone cladding | 50 | 3900 | Warm beige stone | CT-101 | CT-L03-S-012
CT-L03-S-012-MR | L03 | CT-L03-S-012-MR | L03 | South | Stone cladding | 50 | 3900 | Warm beige stone | CT-101 | CT-L03-S-012
CT-L03-S-012-FB | L03 | CT-L03-S-012-FB | L03 | South | Stone cladding | 1400 | 50 | Warm beige stone | CT-101 | CT-L03-S-012
CT-L03-S-012-FT | L03 | CT-L03-S-012-FT | L03 | South | Stone cladding | 1400 | 50 | Warm beige stone | CT-101 | CT-L03-S-012
CT-L03-S-013-ML | L03 | CT-L03-S-013-ML | L03 | South | Curtain wall | 50 | 3900 | Blue-grey concept glass | CT-101 | CT-L03-S-013
CT-L03-S-013-MR | L03 | CT-L03-S-013-MR | L03 | South | Curtain wall | 50 | 3900 | Blue-grey concept glass | CT-101 | CT-L03-S-013
CT-L03-S-013-FB | L03 | CT-L03-S-013-FB | L03 | South | Curtain wall | 1400 | 50 | Blue-grey concept glass | CT-101 | CT-L03-S-013
CT-L03-S-013-FT | L03 | CT-L03-S-013-FT | L03 | South | Curtain wall | 1400 | 50 | Blue-grey concept glass | CT-101 | CT-L03-S-013
CT-L03-S-014-ML | L03 | CT-L03-S-014-ML | L03 | South | Curtain wall | 50 | 3900 | Blue-grey concept glass | CT-101 | CT-L03-S-014
CT-L03-S-014-MR | L03 | CT-L03-S-014-MR | L03 | South | Curtain wall | 50 | 3900 | Blue-grey concept glass | CT-101 | CT-L03-S-014
CT-L03-S-014-FB | L03 | CT-L03-S-014-FB | L03 | South | Curtain wall | 1400 | 50 | Blue-grey concept glass | CT-101 | CT-L03-S-014
CT-L03-S-014-FT | L03 | CT-L03-S-014-FT | L03 | South | Curtain wall | 1400 | 50 | Blue-grey concept glass | CT-101 | CT-L03-S-014
CT-L03-S-015-ML | L03 | CT-L03-S-015-ML | L03 | South | Metal rainscreen | 50 | 3900 | Olive powder coat | CT-101 | CT-L03-S-015
CT-L03-S-015-MR | L03 | CT-L03-S-015-MR | L03 | South | Metal rainscreen | 50 | 3900 | Olive powder coat | CT-101 | CT-L03-S-015
CT-L03-S-015-FB | L03 | CT-L03-S-015-FB | L03 | South | Metal rainscreen | 1400 | 50 | Olive powder coat | CT-101 | CT-L03-S-015
CT-L03-S-015-FT | L03 | CT-L03-S-015-FT | L03 | South | Metal rainscreen | 1400 | 50 | Olive powder coat | CT-101 | CT-L03-S-015
CT-L03-S-016-ML | L03 | CT-L03-S-016-ML | L03 | South | Stone cladding | 50 | 3900 | Warm beige stone | CT-101 | CT-L03-S-016
CT-L03-S-016-MR | L03 | CT-L03-S-016-MR | L03 | South | Stone cladding | 50 | 3900 | Warm beige stone | CT-101 | CT-L03-S-016
CT-L03-S-016-FB | L03 | CT-L03-S-016-FB | L03 | South | Stone cladding | 1400 | 50 | Warm beige stone | CT-101 | CT-L03-S-016
CT-L03-S-016-FT | L03 | CT-L03-S-016-FT | L03 | South | Stone cladding | 1400 | 50 | Warm beige stone | CT-101 | CT-L03-S-016
CT-L03-S-017-ML | L03 | CT-L03-S-017-ML | L03 | South | Curtain wall | 50 | 3900 | Blue-grey concept glass | CT-101 | CT-L03-S-017
CT-L03-S-017-MR | L03 | CT-L03-S-017-MR | L03 | South | Curtain wall | 50 | 3900 | Blue-grey concept glass | CT-101 | CT-L03-S-017
CT-L03-S-017-FB | L03 | CT-L03-S-017-FB | L03 | South | Curtain wall | 1400 | 50 | Blue-grey concept glass | CT-101 | CT-L03-S-017
CT-L03-S-017-FT | L03 | CT-L03-S-017-FT | L03 | South | Curtain wall | 1400 | 50 | Blue-grey concept glass | CT-101 | CT-L03-S-017
CT-L03-S-018-ML | L03 | CT-L03-S-018-ML | L03 | South | Curtain wall | 50 | 3900 | Blue-grey concept glass | CT-101 | CT-L03-S-018
CT-L03-S-018-MR | L03 | CT-L03-S-018-MR | L03 | South | Curtain wall | 50 | 3900 | Blue-grey concept glass | CT-101 | CT-L03-S-018
CT-L03-S-018-FB | L03 | CT-L03-S-018-FB | L03 | South | Curtain wall | 1250 | 50 | Blue-grey concept glass | CT-101 | CT-L03-S-018
CT-L03-S-018-FT | L03 | CT-L03-S-018-FT | L03 | South | Curtain wall | 1250 | 50 | Blue-grey concept glass | CT-101 | CT-L03-S-018
CT-L03-E-001-ML | L03 | CT-L03-E-001-ML | L03 | East | Curtain wall | 50 | 3900 | Blue-grey concept glass | CT-102 | CT-L03-E-001
CT-L03-E-001-MR | L03 | CT-L03-E-001-MR | L03 | East | Curtain wall | 50 | 3900 | Blue-grey concept glass | CT-102 | CT-L03-E-001
CT-L03-E-001-FB | L03 | CT-L03-E-001-FB | L03 | East | Curtain wall | 1250 | 50 | Blue-grey concept glass | CT-102 | CT-L03-E-001
CT-L03-E-001-FT | L03 | CT-L03-E-001-FT | L03 | East | Curtain wall | 1250 | 50 | Blue-grey concept glass | CT-102 | CT-L03-E-001
CT-L03-E-002-ML | L03 | CT-L03-E-002-ML | L03 | East | Curtain wall | 50 | 3900 | Blue-grey concept glass | CT-102 | CT-L03-E-002
CT-L03-E-002-MR | L03 | CT-L03-E-002-MR | L03 | East | Curtain wall | 50 | 3900 | Blue-grey concept glass | CT-102 | CT-L03-E-002
CT-L03-E-002-FB | L03 | CT-L03-E-002-FB | L03 | East | Curtain wall | 1400 | 50 | Blue-grey concept glass | CT-102 | CT-L03-E-002
CT-L03-E-002-FT | L03 | CT-L03-E-002-FT | L03 | East | Curtain wall | 1400 | 50 | Blue-grey concept glass | CT-102 | CT-L03-E-002
CT-L03-E-003-ML | L03 | CT-L03-E-003-ML | L03 | East | Curtain wall | 50 | 3900 | Blue-grey concept glass | CT-102 | CT-L03-E-003
CT-L03-E-003-MR | L03 | CT-L03-E-003-MR | L03 | East | Curtain wall | 50 | 3900 | Blue-grey concept glass | CT-102 | CT-L03-E-003
CT-L03-E-003-FB | L03 | CT-L03-E-003-FB | L03 | East | Curtain wall | 1400 | 50 | Blue-grey concept glass | CT-102 | CT-L03-E-003
CT-L03-E-003-FT | L03 | CT-L03-E-003-FT | L03 | East | Curtain wall | 1400 | 50 | Blue-grey concept glass | CT-102 | CT-L03-E-003
CT-L03-E-004-ML | L03 | CT-L03-E-004-ML | L03 | East | Stone cladding | 50 | 3900 | Warm beige stone | CT-102 | CT-L03-E-004
CT-L03-E-004-MR | L03 | CT-L03-E-004-MR | L03 | East | Stone cladding | 50 | 3900 | Warm beige stone | CT-102 | CT-L03-E-004
CT-L03-E-004-FB | L03 | CT-L03-E-004-FB | L03 | East | Stone cladding | 1400 | 50 | Warm beige stone | CT-102 | CT-L03-E-004
CT-L03-E-004-FT | L03 | CT-L03-E-004-FT | L03 | East | Stone cladding | 1400 | 50 | Warm beige stone | CT-102 | CT-L03-E-004
CT-L03-E-005-ML | L03 | CT-L03-E-005-ML | L03 | East | Metal rainscreen | 50 | 3900 | Olive powder coat | CT-102 | CT-L03-E-005
CT-L03-E-005-MR | L03 | CT-L03-E-005-MR | L03 | East | Metal rainscreen | 50 | 3900 | Olive powder coat | CT-102 | CT-L03-E-005
CT-L03-E-005-FB | L03 | CT-L03-E-005-FB | L03 | East | Metal rainscreen | 1400 | 50 | Olive powder coat | CT-102 | CT-L03-E-005
CT-L03-E-005-FT | L03 | CT-L03-E-005-FT | L03 | East | Metal rainscreen | 1400 | 50 | Olive powder coat | CT-102 | CT-L03-E-005
CT-L03-E-006-ML | L03 | CT-L03-E-006-ML | L03 | East | Curtain wall | 50 | 3900 | Blue-grey concept glass | CT-102 | CT-L03-E-006
CT-L03-E-006-MR | L03 | CT-L03-E-006-MR | L03 | East | Curtain wall | 50 | 3900 | Blue-grey concept glass | CT-102 | CT-L03-E-006
CT-L03-E-006-FB | L03 | CT-L03-E-006-FB | L03 | East | Curtain wall | 1400 | 50 | Blue-grey concept glass | CT-102 | CT-L03-E-006
CT-L03-E-006-FT | L03 | CT-L03-E-006-FT | L03 | East | Curtain wall | 1400 | 50 | Blue-grey concept glass | CT-102 | CT-L03-E-006
CT-L03-E-007-ML | L03 | CT-L03-E-007-ML | L03 | East | Curtain wall | 50 | 3900 | Blue-grey concept glass | CT-102 | CT-L03-E-007
CT-L03-E-007-MR | L03 | CT-L03-E-007-MR | L03 | East | Curtain wall | 50 | 3900 | Blue-grey concept glass | CT-102 | CT-L03-E-007
CT-L03-E-007-FB | L03 | CT-L03-E-007-FB | L03 | East | Curtain wall | 1400 | 50 | Blue-grey concept glass | CT-102 | CT-L03-E-007
CT-L03-E-007-FT | L03 | CT-L03-E-007-FT | L03 | East | Curtain wall | 1400 | 50 | Blue-grey concept glass | CT-102 | CT-L03-E-007
CT-L03-E-008-ML | L03 | CT-L03-E-008-ML | L03 | East | Stone cladding | 50 | 3900 | Warm beige stone | CT-102 | CT-L03-E-008
CT-L03-E-008-MR | L03 | CT-L03-E-008-MR | L03 | East | Stone cladding | 50 | 3900 | Warm beige stone | CT-102 | CT-L03-E-008
CT-L03-E-008-FB | L03 | CT-L03-E-008-FB | L03 | East | Stone cladding | 1400 | 50 | Warm beige stone | CT-102 | CT-L03-E-008
CT-L03-E-008-FT | L03 | CT-L03-E-008-FT | L03 | East | Stone cladding | 1400 | 50 | Warm beige stone | CT-102 | CT-L03-E-008
CT-L03-E-009-ML | L03 | CT-L03-E-009-ML | L03 | East | Curtain wall | 50 | 3900 | Blue-grey concept glass | CT-102 | CT-L03-E-009
CT-L03-E-009-MR | L03 | CT-L03-E-009-MR | L03 | East | Curtain wall | 50 | 3900 | Blue-grey concept glass | CT-102 | CT-L03-E-009
CT-L03-E-009-FB | L03 | CT-L03-E-009-FB | L03 | East | Curtain wall | 1400 | 50 | Blue-grey concept glass | CT-102 | CT-L03-E-009
CT-L03-E-009-FT | L03 | CT-L03-E-009-FT | L03 | East | Curtain wall | 1400 | 50 | Blue-grey concept glass | CT-102 | CT-L03-E-009
CT-L03-E-010-ML | L03 | CT-L03-E-010-ML | L03 | East | Metal rainscreen | 50 | 3900 | Olive powder coat | CT-102 | CT-L03-E-010
CT-L03-E-010-MR | L03 | CT-L03-E-010-MR | L03 | East | Metal rainscreen | 50 | 3900 | Olive powder coat | CT-102 | CT-L03-E-010
CT-L03-E-010-FB | L03 | CT-L03-E-010-FB | L03 | East | Metal rainscreen | 1400 | 50 | Olive powder coat | CT-102 | CT-L03-E-010
CT-L03-E-010-FT | L03 | CT-L03-E-010-FT | L03 | East | Metal rainscreen | 1400 | 50 | Olive powder coat | CT-102 | CT-L03-E-010
CT-L03-E-011-ML | L03 | CT-L03-E-011-ML | L03 | East | Curtain wall | 50 | 3900 | Blue-grey concept glass | CT-102 | CT-L03-E-011
CT-L03-E-011-MR | L03 | CT-L03-E-011-MR | L03 | East | Curtain wall | 50 | 3900 | Blue-grey concept glass | CT-102 | CT-L03-E-011
CT-L03-E-011-FB | L03 | CT-L03-E-011-FB | L03 | East | Curtain wall | 1400 | 50 | Blue-grey concept glass | CT-102 | CT-L03-E-011
CT-L03-E-011-FT | L03 | CT-L03-E-011-FT | L03 | East | Curtain wall | 1400 | 50 | Blue-grey concept glass | CT-102 | CT-L03-E-011
CT-L03-E-012-ML | L03 | CT-L03-E-012-ML | L03 | East | Stone cladding | 50 | 3900 | Warm beige stone | CT-102 | CT-L03-E-012
CT-L03-E-012-MR | L03 | CT-L03-E-012-MR | L03 | East | Stone cladding | 50 | 3900 | Warm beige stone | CT-102 | CT-L03-E-012
CT-L03-E-012-FB | L03 | CT-L03-E-012-FB | L03 | East | Stone cladding | 1250 | 50 | Warm beige stone | CT-102 | CT-L03-E-012
CT-L03-E-012-FT | L03 | CT-L03-E-012-FT | L03 | East | Stone cladding | 1250 | 50 | Warm beige stone | CT-102 | CT-L03-E-012
CT-L03-N-001-ML | L03 | CT-L03-N-001-ML | L03 | North | Curtain wall | 50 | 3900 | Blue-grey concept glass | CT-103 | CT-L03-N-001
CT-L03-N-001-MR | L03 | CT-L03-N-001-MR | L03 | North | Curtain wall | 50 | 3900 | Blue-grey concept glass | CT-103 | CT-L03-N-001
CT-L03-N-001-FB | L03 | CT-L03-N-001-FB | L03 | North | Curtain wall | 1250 | 50 | Blue-grey concept glass | CT-103 | CT-L03-N-001
CT-L03-N-001-FT | L03 | CT-L03-N-001-FT | L03 | North | Curtain wall | 1250 | 50 | Blue-grey concept glass | CT-103 | CT-L03-N-001
CT-L03-N-002-ML | L03 | CT-L03-N-002-ML | L03 | North | Curtain wall | 50 | 3900 | Blue-grey concept glass | CT-103 | CT-L03-N-002
CT-L03-N-002-MR | L03 | CT-L03-N-002-MR | L03 | North | Curtain wall | 50 | 3900 | Blue-grey concept glass | CT-103 | CT-L03-N-002
CT-L03-N-002-FB | L03 | CT-L03-N-002-FB | L03 | North | Curtain wall | 1400 | 50 | Blue-grey concept glass | CT-103 | CT-L03-N-002
CT-L03-N-002-FT | L03 | CT-L03-N-002-FT | L03 | North | Curtain wall | 1400 | 50 | Blue-grey concept glass | CT-103 | CT-L03-N-002
CT-L03-N-003-ML | L03 | CT-L03-N-003-ML | L03 | North | Curtain wall | 50 | 3900 | Blue-grey concept glass | CT-103 | CT-L03-N-003
CT-L03-N-003-MR | L03 | CT-L03-N-003-MR | L03 | North | Curtain wall | 50 | 3900 | Blue-grey concept glass | CT-103 | CT-L03-N-003
CT-L03-N-003-FB | L03 | CT-L03-N-003-FB | L03 | North | Curtain wall | 1400 | 50 | Blue-grey concept glass | CT-103 | CT-L03-N-003
CT-L03-N-003-FT | L03 | CT-L03-N-003-FT | L03 | North | Curtain wall | 1400 | 50 | Blue-grey concept glass | CT-103 | CT-L03-N-003
CT-L03-N-004-ML | L03 | CT-L03-N-004-ML | L03 | North | Stone cladding | 50 | 3900 | Warm beige stone | CT-103 | CT-L03-N-004
CT-L03-N-004-MR | L03 | CT-L03-N-004-MR | L03 | North | Stone cladding | 50 | 3900 | Warm beige stone | CT-103 | CT-L03-N-004
CT-L03-N-004-FB | L03 | CT-L03-N-004-FB | L03 | North | Stone cladding | 1400 | 50 | Warm beige stone | CT-103 | CT-L03-N-004
CT-L03-N-004-FT | L03 | CT-L03-N-004-FT | L03 | North | Stone cladding | 1400 | 50 | Warm beige stone | CT-103 | CT-L03-N-004
CT-L03-N-005-ML | L03 | CT-L03-N-005-ML | L03 | North | Metal rainscreen | 50 | 3900 | Olive powder coat | CT-103 | CT-L03-N-005
CT-L03-N-005-MR | L03 | CT-L03-N-005-MR | L03 | North | Metal rainscreen | 50 | 3900 | Olive powder coat | CT-103 | CT-L03-N-005
CT-L03-N-005-FB | L03 | CT-L03-N-005-FB | L03 | North | Metal rainscreen | 1400 | 50 | Olive powder coat | CT-103 | CT-L03-N-005
CT-L03-N-005-FT | L03 | CT-L03-N-005-FT | L03 | North | Metal rainscreen | 1400 | 50 | Olive powder coat | CT-103 | CT-L03-N-005
CT-L03-N-006-ML | L03 | CT-L03-N-006-ML | L03 | North | Curtain wall | 50 | 3900 | Blue-grey concept glass | CT-103 | CT-L03-N-006
CT-L03-N-006-MR | L03 | CT-L03-N-006-MR | L03 | North | Curtain wall | 50 | 3900 | Blue-grey concept glass | CT-103 | CT-L03-N-006
CT-L03-N-006-FB | L03 | CT-L03-N-006-FB | L03 | North | Curtain wall | 1400 | 50 | Blue-grey concept glass | CT-103 | CT-L03-N-006
CT-L03-N-006-FT | L03 | CT-L03-N-006-FT | L03 | North | Curtain wall | 1400 | 50 | Blue-grey concept glass | CT-103 | CT-L03-N-006
CT-L03-N-007-ML | L03 | CT-L03-N-007-ML | L03 | North | Curtain wall | 50 | 3900 | Blue-grey concept glass | CT-103 | CT-L03-N-007
CT-L03-N-007-MR | L03 | CT-L03-N-007-MR | L03 | North | Curtain wall | 50 | 3900 | Blue-grey concept glass | CT-103 | CT-L03-N-007
CT-L03-N-007-FB | L03 | CT-L03-N-007-FB | L03 | North | Curtain wall | 1400 | 50 | Blue-grey concept glass | CT-103 | CT-L03-N-007
CT-L03-N-007-FT | L03 | CT-L03-N-007-FT | L03 | North | Curtain wall | 1400 | 50 | Blue-grey concept glass | CT-103 | CT-L03-N-007
CT-L03-N-008-ML | L03 | CT-L03-N-008-ML | L03 | North | Stone cladding | 50 | 3900 | Warm beige stone | CT-103 | CT-L03-N-008
CT-L03-N-008-MR | L03 | CT-L03-N-008-MR | L03 | North | Stone cladding | 50 | 3900 | Warm beige stone | CT-103 | CT-L03-N-008
CT-L03-N-008-FB | L03 | CT-L03-N-008-FB | L03 | North | Stone cladding | 1400 | 50 | Warm beige stone | CT-103 | CT-L03-N-008
CT-L03-N-008-FT | L03 | CT-L03-N-008-FT | L03 | North | Stone cladding | 1400 | 50 | Warm beige stone | CT-103 | CT-L03-N-008
CT-L03-N-009-ML | L03 | CT-L03-N-009-ML | L03 | North | Curtain wall | 50 | 3900 | Blue-grey concept glass | CT-103 | CT-L03-N-009
CT-L03-N-009-MR | L03 | CT-L03-N-009-MR | L03 | North | Curtain wall | 50 | 3900 | Blue-grey concept glass | CT-103 | CT-L03-N-009
CT-L03-N-009-FB | L03 | CT-L03-N-009-FB | L03 | North | Curtain wall | 1400 | 50 | Blue-grey concept glass | CT-103 | CT-L03-N-009
CT-L03-N-009-FT | L03 | CT-L03-N-009-FT | L03 | North | Curtain wall | 1400 | 50 | Blue-grey concept glass | CT-103 | CT-L03-N-009
CT-L03-N-010-ML | L03 | CT-L03-N-010-ML | L03 | North | Metal rainscreen | 50 | 3900 | Olive powder coat | CT-103 | CT-L03-N-010
CT-L03-N-010-MR | L03 | CT-L03-N-010-MR | L03 | North | Metal rainscreen | 50 | 3900 | Olive powder coat | CT-103 | CT-L03-N-010
CT-L03-N-010-FB | L03 | CT-L03-N-010-FB | L03 | North | Metal rainscreen | 1400 | 50 | Olive powder coat | CT-103 | CT-L03-N-010
CT-L03-N-010-FT | L03 | CT-L03-N-010-FT | L03 | North | Metal rainscreen | 1400 | 50 | Olive powder coat | CT-103 | CT-L03-N-010
CT-L03-N-011-ML | L03 | CT-L03-N-011-ML | L03 | North | Curtain wall | 50 | 3900 | Blue-grey concept glass | CT-103 | CT-L03-N-011
CT-L03-N-011-MR | L03 | CT-L03-N-011-MR | L03 | North | Curtain wall | 50 | 3900 | Blue-grey concept glass | CT-103 | CT-L03-N-011
CT-L03-N-011-FB | L03 | CT-L03-N-011-FB | L03 | North | Curtain wall | 1400 | 50 | Blue-grey concept glass | CT-103 | CT-L03-N-011
CT-L03-N-011-FT | L03 | CT-L03-N-011-FT | L03 | North | Curtain wall | 1400 | 50 | Blue-grey concept glass | CT-103 | CT-L03-N-011
CT-L03-N-012-ML | L03 | CT-L03-N-012-ML | L03 | North | Stone cladding | 50 | 3900 | Warm beige stone | CT-103 | CT-L03-N-012
CT-L03-N-012-MR | L03 | CT-L03-N-012-MR | L03 | North | Stone cladding | 50 | 3900 | Warm beige stone | CT-103 | CT-L03-N-012
CT-L03-N-012-FB | L03 | CT-L03-N-012-FB | L03 | North | Stone cladding | 1400 | 50 | Warm beige stone | CT-103 | CT-L03-N-012
CT-L03-N-012-FT | L03 | CT-L03-N-012-FT | L03 | North | Stone cladding | 1400 | 50 | Warm beige stone | CT-103 | CT-L03-N-012
CT-L03-N-013-ML | L03 | CT-L03-N-013-ML | L03 | North | Curtain wall | 50 | 3900 | Blue-grey concept glass | CT-103 | CT-L03-N-013
CT-L03-N-013-MR | L03 | CT-L03-N-013-MR | L03 | North | Curtain wall | 50 | 3900 | Blue-grey concept glass | CT-103 | CT-L03-N-013
CT-L03-N-013-FB | L03 | CT-L03-N-013-FB | L03 | North | Curtain wall | 1400 | 50 | Blue-grey concept glass | CT-103 | CT-L03-N-013
CT-L03-N-013-FT | L03 | CT-L03-N-013-FT | L03 | North | Curtain wall | 1400 | 50 | Blue-grey concept glass | CT-103 | CT-L03-N-013
CT-L03-N-014-ML | L03 | CT-L03-N-014-ML | L03 | North | Curtain wall | 50 | 3900 | Blue-grey concept glass | CT-103 | CT-L03-N-014
CT-L03-N-014-MR | L03 | CT-L03-N-014-MR | L03 | North | Curtain wall | 50 | 3900 | Blue-grey concept glass | CT-103 | CT-L03-N-014
CT-L03-N-014-FB | L03 | CT-L03-N-014-FB | L03 | North | Curtain wall | 1400 | 50 | Blue-grey concept glass | CT-103 | CT-L03-N-014
CT-L03-N-014-FT | L03 | CT-L03-N-014-FT | L03 | North | Curtain wall | 1400 | 50 | Blue-grey concept glass | CT-103 | CT-L03-N-014
CT-L03-N-015-ML | L03 | CT-L03-N-015-ML | L03 | North | Metal rainscreen | 50 | 3900 | Olive powder coat | CT-103 | CT-L03-N-015
CT-L03-N-015-MR | L03 | CT-L03-N-015-MR | L03 | North | Metal rainscreen | 50 | 3900 | Olive powder coat | CT-103 | CT-L03-N-015
CT-L03-N-015-FB | L03 | CT-L03-N-015-FB | L03 | North | Metal rainscreen | 1400 | 50 | Olive powder coat | CT-103 | CT-L03-N-015
CT-L03-N-015-FT | L03 | CT-L03-N-015-FT | L03 | North | Metal rainscreen | 1400 | 50 | Olive powder coat | CT-103 | CT-L03-N-015
CT-L03-N-016-ML | L03 | CT-L03-N-016-ML | L03 | North | Stone cladding | 50 | 3900 | Warm beige stone | CT-103 | CT-L03-N-016
CT-L03-N-016-MR | L03 | CT-L03-N-016-MR | L03 | North | Stone cladding | 50 | 3900 | Warm beige stone | CT-103 | CT-L03-N-016
CT-L03-N-016-FB | L03 | CT-L03-N-016-FB | L03 | North | Stone cladding | 1400 | 50 | Warm beige stone | CT-103 | CT-L03-N-016
CT-L03-N-016-FT | L03 | CT-L03-N-016-FT | L03 | North | Stone cladding | 1400 | 50 | Warm beige stone | CT-103 | CT-L03-N-016
CT-L03-N-017-ML | L03 | CT-L03-N-017-ML | L03 | North | Curtain wall | 50 | 3900 | Blue-grey concept glass | CT-103 | CT-L03-N-017
CT-L03-N-017-MR | L03 | CT-L03-N-017-MR | L03 | North | Curtain wall | 50 | 3900 | Blue-grey concept glass | CT-103 | CT-L03-N-017
CT-L03-N-017-FB | L03 | CT-L03-N-017-FB | L03 | North | Curtain wall | 1400 | 50 | Blue-grey concept glass | CT-103 | CT-L03-N-017
CT-L03-N-017-FT | L03 | CT-L03-N-017-FT | L03 | North | Curtain wall | 1400 | 50 | Blue-grey concept glass | CT-103 | CT-L03-N-017
CT-L03-N-018-ML | L03 | CT-L03-N-018-ML | L03 | North | Curtain wall | 50 | 3900 | Blue-grey concept glass | CT-103 | CT-L03-N-018
CT-L03-N-018-MR | L03 | CT-L03-N-018-MR | L03 | North | Curtain wall | 50 | 3900 | Blue-grey concept glass | CT-103 | CT-L03-N-018
CT-L03-N-018-FB | L03 | CT-L03-N-018-FB | L03 | North | Curtain wall | 1250 | 50 | Blue-grey concept glass | CT-103 | CT-L03-N-018
CT-L03-N-018-FT | L03 | CT-L03-N-018-FT | L03 | North | Curtain wall | 1250 | 50 | Blue-grey concept glass | CT-103 | CT-L03-N-018
CT-L03-W-001-ML | L03 | CT-L03-W-001-ML | L03 | West | Curtain wall | 50 | 3900 | Blue-grey concept glass | CT-104 | CT-L03-W-001
CT-L03-W-001-MR | L03 | CT-L03-W-001-MR | L03 | West | Curtain wall | 50 | 3900 | Blue-grey concept glass | CT-104 | CT-L03-W-001
CT-L03-W-001-FB | L03 | CT-L03-W-001-FB | L03 | West | Curtain wall | 1250 | 50 | Blue-grey concept glass | CT-104 | CT-L03-W-001
CT-L03-W-001-FT | L03 | CT-L03-W-001-FT | L03 | West | Curtain wall | 1250 | 50 | Blue-grey concept glass | CT-104 | CT-L03-W-001
CT-L03-W-002-ML | L03 | CT-L03-W-002-ML | L03 | West | Curtain wall | 50 | 3900 | Blue-grey concept glass | CT-104 | CT-L03-W-002
CT-L03-W-002-MR | L03 | CT-L03-W-002-MR | L03 | West | Curtain wall | 50 | 3900 | Blue-grey concept glass | CT-104 | CT-L03-W-002
CT-L03-W-002-FB | L03 | CT-L03-W-002-FB | L03 | West | Curtain wall | 1400 | 50 | Blue-grey concept glass | CT-104 | CT-L03-W-002
CT-L03-W-002-FT | L03 | CT-L03-W-002-FT | L03 | West | Curtain wall | 1400 | 50 | Blue-grey concept glass | CT-104 | CT-L03-W-002
CT-L03-W-003-ML | L03 | CT-L03-W-003-ML | L03 | West | Curtain wall | 50 | 3900 | Blue-grey concept glass | CT-104 | CT-L03-W-003
CT-L03-W-003-MR | L03 | CT-L03-W-003-MR | L03 | West | Curtain wall | 50 | 3900 | Blue-grey concept glass | CT-104 | CT-L03-W-003
CT-L03-W-003-FB | L03 | CT-L03-W-003-FB | L03 | West | Curtain wall | 1400 | 50 | Blue-grey concept glass | CT-104 | CT-L03-W-003
CT-L03-W-003-FT | L03 | CT-L03-W-003-FT | L03 | West | Curtain wall | 1400 | 50 | Blue-grey concept glass | CT-104 | CT-L03-W-003
CT-L03-W-004-ML | L03 | CT-L03-W-004-ML | L03 | West | Stone cladding | 50 | 3900 | Warm beige stone | CT-104 | CT-L03-W-004
CT-L03-W-004-MR | L03 | CT-L03-W-004-MR | L03 | West | Stone cladding | 50 | 3900 | Warm beige stone | CT-104 | CT-L03-W-004
CT-L03-W-004-FB | L03 | CT-L03-W-004-FB | L03 | West | Stone cladding | 1400 | 50 | Warm beige stone | CT-104 | CT-L03-W-004
CT-L03-W-004-FT | L03 | CT-L03-W-004-FT | L03 | West | Stone cladding | 1400 | 50 | Warm beige stone | CT-104 | CT-L03-W-004
CT-L03-W-005-ML | L03 | CT-L03-W-005-ML | L03 | West | Metal rainscreen | 50 | 3900 | Olive powder coat | CT-104 | CT-L03-W-005
CT-L03-W-005-MR | L03 | CT-L03-W-005-MR | L03 | West | Metal rainscreen | 50 | 3900 | Olive powder coat | CT-104 | CT-L03-W-005
CT-L03-W-005-FB | L03 | CT-L03-W-005-FB | L03 | West | Metal rainscreen | 1400 | 50 | Olive powder coat | CT-104 | CT-L03-W-005
CT-L03-W-005-FT | L03 | CT-L03-W-005-FT | L03 | West | Metal rainscreen | 1400 | 50 | Olive powder coat | CT-104 | CT-L03-W-005
CT-L03-W-006-ML | L03 | CT-L03-W-006-ML | L03 | West | Curtain wall | 50 | 3900 | Blue-grey concept glass | CT-104 | CT-L03-W-006
CT-L03-W-006-MR | L03 | CT-L03-W-006-MR | L03 | West | Curtain wall | 50 | 3900 | Blue-grey concept glass | CT-104 | CT-L03-W-006
CT-L03-W-006-FB | L03 | CT-L03-W-006-FB | L03 | West | Curtain wall | 1400 | 50 | Blue-grey concept glass | CT-104 | CT-L03-W-006
CT-L03-W-006-FT | L03 | CT-L03-W-006-FT | L03 | West | Curtain wall | 1400 | 50 | Blue-grey concept glass | CT-104 | CT-L03-W-006
CT-L03-W-007-ML | L03 | CT-L03-W-007-ML | L03 | West | Curtain wall | 50 | 3900 | Blue-grey concept glass | CT-104 | CT-L03-W-007
CT-L03-W-007-MR | L03 | CT-L03-W-007-MR | L03 | West | Curtain wall | 50 | 3900 | Blue-grey concept glass | CT-104 | CT-L03-W-007
CT-L03-W-007-FB | L03 | CT-L03-W-007-FB | L03 | West | Curtain wall | 1400 | 50 | Blue-grey concept glass | CT-104 | CT-L03-W-007
CT-L03-W-007-FT | L03 | CT-L03-W-007-FT | L03 | West | Curtain wall | 1400 | 50 | Blue-grey concept glass | CT-104 | CT-L03-W-007
CT-L03-W-008-ML | L03 | CT-L03-W-008-ML | L03 | West | Stone cladding | 50 | 3900 | Warm beige stone | CT-104 | CT-L03-W-008
CT-L03-W-008-MR | L03 | CT-L03-W-008-MR | L03 | West | Stone cladding | 50 | 3900 | Warm beige stone | CT-104 | CT-L03-W-008
CT-L03-W-008-FB | L03 | CT-L03-W-008-FB | L03 | West | Stone cladding | 1400 | 50 | Warm beige stone | CT-104 | CT-L03-W-008
CT-L03-W-008-FT | L03 | CT-L03-W-008-FT | L03 | West | Stone cladding | 1400 | 50 | Warm beige stone | CT-104 | CT-L03-W-008
CT-L03-W-009-ML | L03 | CT-L03-W-009-ML | L03 | West | Curtain wall | 50 | 3900 | Blue-grey concept glass | CT-104 | CT-L03-W-009
CT-L03-W-009-MR | L03 | CT-L03-W-009-MR | L03 | West | Curtain wall | 50 | 3900 | Blue-grey concept glass | CT-104 | CT-L03-W-009
CT-L03-W-009-FB | L03 | CT-L03-W-009-FB | L03 | West | Curtain wall | 1400 | 50 | Blue-grey concept glass | CT-104 | CT-L03-W-009
CT-L03-W-009-FT | L03 | CT-L03-W-009-FT | L03 | West | Curtain wall | 1400 | 50 | Blue-grey concept glass | CT-104 | CT-L03-W-009
CT-L03-W-010-ML | L03 | CT-L03-W-010-ML | L03 | West | Metal rainscreen | 50 | 3900 | Olive powder coat | CT-104 | CT-L03-W-010
CT-L03-W-010-MR | L03 | CT-L03-W-010-MR | L03 | West | Metal rainscreen | 50 | 3900 | Olive powder coat | CT-104 | CT-L03-W-010
CT-L03-W-010-FB | L03 | CT-L03-W-010-FB | L03 | West | Metal rainscreen | 1400 | 50 | Olive powder coat | CT-104 | CT-L03-W-010
CT-L03-W-010-FT | L03 | CT-L03-W-010-FT | L03 | West | Metal rainscreen | 1400 | 50 | Olive powder coat | CT-104 | CT-L03-W-010
CT-L03-W-011-ML | L03 | CT-L03-W-011-ML | L03 | West | Curtain wall | 50 | 3900 | Blue-grey concept glass | CT-104 | CT-L03-W-011
CT-L03-W-011-MR | L03 | CT-L03-W-011-MR | L03 | West | Curtain wall | 50 | 3900 | Blue-grey concept glass | CT-104 | CT-L03-W-011
CT-L03-W-011-FB | L03 | CT-L03-W-011-FB | L03 | West | Curtain wall | 1400 | 50 | Blue-grey concept glass | CT-104 | CT-L03-W-011
CT-L03-W-011-FT | L03 | CT-L03-W-011-FT | L03 | West | Curtain wall | 1400 | 50 | Blue-grey concept glass | CT-104 | CT-L03-W-011
CT-L03-W-012-ML | L03 | CT-L03-W-012-ML | L03 | West | Stone cladding | 50 | 3900 | Warm beige stone | CT-104 | CT-L03-W-012
CT-L03-W-012-MR | L03 | CT-L03-W-012-MR | L03 | West | Stone cladding | 50 | 3900 | Warm beige stone | CT-104 | CT-L03-W-012
CT-L03-W-012-FB | L03 | CT-L03-W-012-FB | L03 | West | Stone cladding | 1250 | 50 | Warm beige stone | CT-104 | CT-L03-W-012
CT-L03-W-012-FT | L03 | CT-L03-W-012-FT | L03 | West | Stone cladding | 1250 | 50 | Warm beige stone | CT-104 | CT-L03-W-012
CT-L04-S-001-ML | L04 | CT-L04-S-001-ML | L04 | South | Curtain wall | 50 | 3300 | Blue-grey concept glass | CT-101 | CT-L04-S-001
CT-L04-S-001-MR | L04 | CT-L04-S-001-MR | L04 | South | Curtain wall | 50 | 3300 | Blue-grey concept glass | CT-101 | CT-L04-S-001
CT-L04-S-001-FB | L04 | CT-L04-S-001-FB | L04 | South | Curtain wall | 1250 | 50 | Blue-grey concept glass | CT-101 | CT-L04-S-001
CT-L04-S-001-FT | L04 | CT-L04-S-001-FT | L04 | South | Curtain wall | 1250 | 50 | Blue-grey concept glass | CT-101 | CT-L04-S-001
CT-L04-S-002-ML | L04 | CT-L04-S-002-ML | L04 | South | Curtain wall | 50 | 3300 | Blue-grey concept glass | CT-101 | CT-L04-S-002
CT-L04-S-002-MR | L04 | CT-L04-S-002-MR | L04 | South | Curtain wall | 50 | 3300 | Blue-grey concept glass | CT-101 | CT-L04-S-002
CT-L04-S-002-FB | L04 | CT-L04-S-002-FB | L04 | South | Curtain wall | 1400 | 50 | Blue-grey concept glass | CT-101 | CT-L04-S-002
CT-L04-S-002-FT | L04 | CT-L04-S-002-FT | L04 | South | Curtain wall | 1400 | 50 | Blue-grey concept glass | CT-101 | CT-L04-S-002
CT-L04-S-003-ML | L04 | CT-L04-S-003-ML | L04 | South | Curtain wall | 50 | 3300 | Blue-grey concept glass | CT-101 | CT-L04-S-003
CT-L04-S-003-MR | L04 | CT-L04-S-003-MR | L04 | South | Curtain wall | 50 | 3300 | Blue-grey concept glass | CT-101 | CT-L04-S-003
CT-L04-S-003-FB | L04 | CT-L04-S-003-FB | L04 | South | Curtain wall | 1400 | 50 | Blue-grey concept glass | CT-101 | CT-L04-S-003
CT-L04-S-003-FT | L04 | CT-L04-S-003-FT | L04 | South | Curtain wall | 1400 | 50 | Blue-grey concept glass | CT-101 | CT-L04-S-003
CT-L04-S-004-ML | L04 | CT-L04-S-004-ML | L04 | South | Curtain wall | 50 | 3300 | Blue-grey concept glass | CT-101 | CT-L04-S-004
CT-L04-S-004-MR | L04 | CT-L04-S-004-MR | L04 | South | Curtain wall | 50 | 3300 | Blue-grey concept glass | CT-101 | CT-L04-S-004
CT-L04-S-004-FB | L04 | CT-L04-S-004-FB | L04 | South | Curtain wall | 1400 | 50 | Blue-grey concept glass | CT-101 | CT-L04-S-004
CT-L04-S-004-FT | L04 | CT-L04-S-004-FT | L04 | South | Curtain wall | 1400 | 50 | Blue-grey concept glass | CT-101 | CT-L04-S-004
CT-L04-S-005-ML | L04 | CT-L04-S-005-ML | L04 | South | Metal rainscreen | 50 | 3300 | Olive powder coat | CT-101 | CT-L04-S-005
CT-L04-S-005-MR | L04 | CT-L04-S-005-MR | L04 | South | Metal rainscreen | 50 | 3300 | Olive powder coat | CT-101 | CT-L04-S-005
CT-L04-S-005-FB | L04 | CT-L04-S-005-FB | L04 | South | Metal rainscreen | 1400 | 50 | Olive powder coat | CT-101 | CT-L04-S-005
CT-L04-S-005-FT | L04 | CT-L04-S-005-FT | L04 | South | Metal rainscreen | 1400 | 50 | Olive powder coat | CT-101 | CT-L04-S-005
CT-L04-S-006-ML | L04 | CT-L04-S-006-ML | L04 | South | Curtain wall | 50 | 3300 | Blue-grey concept glass | CT-101 | CT-L04-S-006
CT-L04-S-006-MR | L04 | CT-L04-S-006-MR | L04 | South | Curtain wall | 50 | 3300 | Blue-grey concept glass | CT-101 | CT-L04-S-006
CT-L04-S-006-FB | L04 | CT-L04-S-006-FB | L04 | South | Curtain wall | 1400 | 50 | Blue-grey concept glass | CT-101 | CT-L04-S-006
CT-L04-S-006-FT | L04 | CT-L04-S-006-FT | L04 | South | Curtain wall | 1400 | 50 | Blue-grey concept glass | CT-101 | CT-L04-S-006
CT-L04-S-007-ML | L04 | CT-L04-S-007-ML | L04 | South | Curtain wall | 50 | 3300 | Blue-grey concept glass | CT-101 | CT-L04-S-007
CT-L04-S-007-MR | L04 | CT-L04-S-007-MR | L04 | South | Curtain wall | 50 | 3300 | Blue-grey concept glass | CT-101 | CT-L04-S-007
CT-L04-S-007-FB | L04 | CT-L04-S-007-FB | L04 | South | Curtain wall | 1400 | 50 | Blue-grey concept glass | CT-101 | CT-L04-S-007
CT-L04-S-007-FT | L04 | CT-L04-S-007-FT | L04 | South | Curtain wall | 1400 | 50 | Blue-grey concept glass | CT-101 | CT-L04-S-007
CT-L04-S-008-ML | L04 | CT-L04-S-008-ML | L04 | South | Curtain wall | 50 | 3300 | Blue-grey concept glass | CT-101 | CT-L04-S-008
CT-L04-S-008-MR | L04 | CT-L04-S-008-MR | L04 | South | Curtain wall | 50 | 3300 | Blue-grey concept glass | CT-101 | CT-L04-S-008
CT-L04-S-008-FB | L04 | CT-L04-S-008-FB | L04 | South | Curtain wall | 1400 | 50 | Blue-grey concept glass | CT-101 | CT-L04-S-008
CT-L04-S-008-FT | L04 | CT-L04-S-008-FT | L04 | South | Curtain wall | 1400 | 50 | Blue-grey concept glass | CT-101 | CT-L04-S-008
CT-L04-S-009-ML | L04 | CT-L04-S-009-ML | L04 | South | Curtain wall | 50 | 3300 | Blue-grey concept glass | CT-101 | CT-L04-S-009
CT-L04-S-009-MR | L04 | CT-L04-S-009-MR | L04 | South | Curtain wall | 50 | 3300 | Blue-grey concept glass | CT-101 | CT-L04-S-009
CT-L04-S-009-FB | L04 | CT-L04-S-009-FB | L04 | South | Curtain wall | 1400 | 50 | Blue-grey concept glass | CT-101 | CT-L04-S-009
CT-L04-S-009-FT | L04 | CT-L04-S-009-FT | L04 | South | Curtain wall | 1400 | 50 | Blue-grey concept glass | CT-101 | CT-L04-S-009
CT-L04-S-010-ML | L04 | CT-L04-S-010-ML | L04 | South | Metal rainscreen | 50 | 3300 | Olive powder coat | CT-101 | CT-L04-S-010
CT-L04-S-010-MR | L04 | CT-L04-S-010-MR | L04 | South | Metal rainscreen | 50 | 3300 | Olive powder coat | CT-101 | CT-L04-S-010
CT-L04-S-010-FB | L04 | CT-L04-S-010-FB | L04 | South | Metal rainscreen | 1400 | 50 | Olive powder coat | CT-101 | CT-L04-S-010
CT-L04-S-010-FT | L04 | CT-L04-S-010-FT | L04 | South | Metal rainscreen | 1400 | 50 | Olive powder coat | CT-101 | CT-L04-S-010
CT-L04-S-011-ML | L04 | CT-L04-S-011-ML | L04 | South | Curtain wall | 50 | 3300 | Blue-grey concept glass | CT-101 | CT-L04-S-011
CT-L04-S-011-MR | L04 | CT-L04-S-011-MR | L04 | South | Curtain wall | 50 | 3300 | Blue-grey concept glass | CT-101 | CT-L04-S-011
CT-L04-S-011-FB | L04 | CT-L04-S-011-FB | L04 | South | Curtain wall | 1400 | 50 | Blue-grey concept glass | CT-101 | CT-L04-S-011
CT-L04-S-011-FT | L04 | CT-L04-S-011-FT | L04 | South | Curtain wall | 1400 | 50 | Blue-grey concept glass | CT-101 | CT-L04-S-011
CT-L04-S-012-ML | L04 | CT-L04-S-012-ML | L04 | South | Curtain wall | 50 | 3300 | Blue-grey concept glass | CT-101 | CT-L04-S-012
CT-L04-S-012-MR | L04 | CT-L04-S-012-MR | L04 | South | Curtain wall | 50 | 3300 | Blue-grey concept glass | CT-101 | CT-L04-S-012
CT-L04-S-012-FB | L04 | CT-L04-S-012-FB | L04 | South | Curtain wall | 1400 | 50 | Blue-grey concept glass | CT-101 | CT-L04-S-012
CT-L04-S-012-FT | L04 | CT-L04-S-012-FT | L04 | South | Curtain wall | 1400 | 50 | Blue-grey concept glass | CT-101 | CT-L04-S-012
CT-L04-S-013-ML | L04 | CT-L04-S-013-ML | L04 | South | Curtain wall | 50 | 3300 | Blue-grey concept glass | CT-101 | CT-L04-S-013
CT-L04-S-013-MR | L04 | CT-L04-S-013-MR | L04 | South | Curtain wall | 50 | 3300 | Blue-grey concept glass | CT-101 | CT-L04-S-013
CT-L04-S-013-FB | L04 | CT-L04-S-013-FB | L04 | South | Curtain wall | 1400 | 50 | Blue-grey concept glass | CT-101 | CT-L04-S-013
CT-L04-S-013-FT | L04 | CT-L04-S-013-FT | L04 | South | Curtain wall | 1400 | 50 | Blue-grey concept glass | CT-101 | CT-L04-S-013
CT-L04-S-014-ML | L04 | CT-L04-S-014-ML | L04 | South | Curtain wall | 50 | 3300 | Blue-grey concept glass | CT-101 | CT-L04-S-014
CT-L04-S-014-MR | L04 | CT-L04-S-014-MR | L04 | South | Curtain wall | 50 | 3300 | Blue-grey concept glass | CT-101 | CT-L04-S-014
CT-L04-S-014-FB | L04 | CT-L04-S-014-FB | L04 | South | Curtain wall | 1250 | 50 | Blue-grey concept glass | CT-101 | CT-L04-S-014
CT-L04-S-014-FT | L04 | CT-L04-S-014-FT | L04 | South | Curtain wall | 1250 | 50 | Blue-grey concept glass | CT-101 | CT-L04-S-014
CT-L04-E-001-ML | L04 | CT-L04-E-001-ML | L04 | East | Curtain wall | 50 | 3300 | Blue-grey concept glass | CT-102 | CT-L04-E-001
CT-L04-E-001-MR | L04 | CT-L04-E-001-MR | L04 | East | Curtain wall | 50 | 3300 | Blue-grey concept glass | CT-102 | CT-L04-E-001
CT-L04-E-001-FB | L04 | CT-L04-E-001-FB | L04 | East | Curtain wall | 1250 | 50 | Blue-grey concept glass | CT-102 | CT-L04-E-001
CT-L04-E-001-FT | L04 | CT-L04-E-001-FT | L04 | East | Curtain wall | 1250 | 50 | Blue-grey concept glass | CT-102 | CT-L04-E-001
CT-L04-E-002-ML | L04 | CT-L04-E-002-ML | L04 | East | Curtain wall | 50 | 3300 | Blue-grey concept glass | CT-102 | CT-L04-E-002
CT-L04-E-002-MR | L04 | CT-L04-E-002-MR | L04 | East | Curtain wall | 50 | 3300 | Blue-grey concept glass | CT-102 | CT-L04-E-002
CT-L04-E-002-FB | L04 | CT-L04-E-002-FB | L04 | East | Curtain wall | 1400 | 50 | Blue-grey concept glass | CT-102 | CT-L04-E-002
CT-L04-E-002-FT | L04 | CT-L04-E-002-FT | L04 | East | Curtain wall | 1400 | 50 | Blue-grey concept glass | CT-102 | CT-L04-E-002
CT-L04-E-003-ML | L04 | CT-L04-E-003-ML | L04 | East | Curtain wall | 50 | 3300 | Blue-grey concept glass | CT-102 | CT-L04-E-003
CT-L04-E-003-MR | L04 | CT-L04-E-003-MR | L04 | East | Curtain wall | 50 | 3300 | Blue-grey concept glass | CT-102 | CT-L04-E-003
CT-L04-E-003-FB | L04 | CT-L04-E-003-FB | L04 | East | Curtain wall | 1400 | 50 | Blue-grey concept glass | CT-102 | CT-L04-E-003
CT-L04-E-003-FT | L04 | CT-L04-E-003-FT | L04 | East | Curtain wall | 1400 | 50 | Blue-grey concept glass | CT-102 | CT-L04-E-003
CT-L04-E-004-ML | L04 | CT-L04-E-004-ML | L04 | East | Curtain wall | 50 | 3300 | Blue-grey concept glass | CT-102 | CT-L04-E-004
CT-L04-E-004-MR | L04 | CT-L04-E-004-MR | L04 | East | Curtain wall | 50 | 3300 | Blue-grey concept glass | CT-102 | CT-L04-E-004
CT-L04-E-004-FB | L04 | CT-L04-E-004-FB | L04 | East | Curtain wall | 1400 | 50 | Blue-grey concept glass | CT-102 | CT-L04-E-004
CT-L04-E-004-FT | L04 | CT-L04-E-004-FT | L04 | East | Curtain wall | 1400 | 50 | Blue-grey concept glass | CT-102 | CT-L04-E-004
CT-L04-E-005-ML | L04 | CT-L04-E-005-ML | L04 | East | Metal rainscreen | 50 | 3300 | Olive powder coat | CT-102 | CT-L04-E-005
CT-L04-E-005-MR | L04 | CT-L04-E-005-MR | L04 | East | Metal rainscreen | 50 | 3300 | Olive powder coat | CT-102 | CT-L04-E-005
CT-L04-E-005-FB | L04 | CT-L04-E-005-FB | L04 | East | Metal rainscreen | 1400 | 50 | Olive powder coat | CT-102 | CT-L04-E-005
CT-L04-E-005-FT | L04 | CT-L04-E-005-FT | L04 | East | Metal rainscreen | 1400 | 50 | Olive powder coat | CT-102 | CT-L04-E-005
CT-L04-E-006-ML | L04 | CT-L04-E-006-ML | L04 | East | Curtain wall | 50 | 3300 | Blue-grey concept glass | CT-102 | CT-L04-E-006
CT-L04-E-006-MR | L04 | CT-L04-E-006-MR | L04 | East | Curtain wall | 50 | 3300 | Blue-grey concept glass | CT-102 | CT-L04-E-006
CT-L04-E-006-FB | L04 | CT-L04-E-006-FB | L04 | East | Curtain wall | 1400 | 50 | Blue-grey concept glass | CT-102 | CT-L04-E-006
CT-L04-E-006-FT | L04 | CT-L04-E-006-FT | L04 | East | Curtain wall | 1400 | 50 | Blue-grey concept glass | CT-102 | CT-L04-E-006
CT-L04-E-007-ML | L04 | CT-L04-E-007-ML | L04 | East | Curtain wall | 50 | 3300 | Blue-grey concept glass | CT-102 | CT-L04-E-007
CT-L04-E-007-MR | L04 | CT-L04-E-007-MR | L04 | East | Curtain wall | 50 | 3300 | Blue-grey concept glass | CT-102 | CT-L04-E-007
CT-L04-E-007-FB | L04 | CT-L04-E-007-FB | L04 | East | Curtain wall | 1400 | 50 | Blue-grey concept glass | CT-102 | CT-L04-E-007
CT-L04-E-007-FT | L04 | CT-L04-E-007-FT | L04 | East | Curtain wall | 1400 | 50 | Blue-grey concept glass | CT-102 | CT-L04-E-007
CT-L04-E-008-ML | L04 | CT-L04-E-008-ML | L04 | East | Curtain wall | 50 | 3300 | Blue-grey concept glass | CT-102 | CT-L04-E-008
CT-L04-E-008-MR | L04 | CT-L04-E-008-MR | L04 | East | Curtain wall | 50 | 3300 | Blue-grey concept glass | CT-102 | CT-L04-E-008
CT-L04-E-008-FB | L04 | CT-L04-E-008-FB | L04 | East | Curtain wall | 1400 | 50 | Blue-grey concept glass | CT-102 | CT-L04-E-008
CT-L04-E-008-FT | L04 | CT-L04-E-008-FT | L04 | East | Curtain wall | 1400 | 50 | Blue-grey concept glass | CT-102 | CT-L04-E-008
CT-L04-E-009-ML | L04 | CT-L04-E-009-ML | L04 | East | Curtain wall | 50 | 3300 | Blue-grey concept glass | CT-102 | CT-L04-E-009
CT-L04-E-009-MR | L04 | CT-L04-E-009-MR | L04 | East | Curtain wall | 50 | 3300 | Blue-grey concept glass | CT-102 | CT-L04-E-009
CT-L04-E-009-FB | L04 | CT-L04-E-009-FB | L04 | East | Curtain wall | 1400 | 50 | Blue-grey concept glass | CT-102 | CT-L04-E-009
CT-L04-E-009-FT | L04 | CT-L04-E-009-FT | L04 | East | Curtain wall | 1400 | 50 | Blue-grey concept glass | CT-102 | CT-L04-E-009
CT-L04-E-010-ML | L04 | CT-L04-E-010-ML | L04 | East | Metal rainscreen | 50 | 3300 | Olive powder coat | CT-102 | CT-L04-E-010
CT-L04-E-010-MR | L04 | CT-L04-E-010-MR | L04 | East | Metal rainscreen | 50 | 3300 | Olive powder coat | CT-102 | CT-L04-E-010
CT-L04-E-010-FB | L04 | CT-L04-E-010-FB | L04 | East | Metal rainscreen | 1250 | 50 | Olive powder coat | CT-102 | CT-L04-E-010
CT-L04-E-010-FT | L04 | CT-L04-E-010-FT | L04 | East | Metal rainscreen | 1250 | 50 | Olive powder coat | CT-102 | CT-L04-E-010
CT-L04-N-001-ML | L04 | CT-L04-N-001-ML | L04 | North | Curtain wall | 50 | 3300 | Blue-grey concept glass | CT-103 | CT-L04-N-001
CT-L04-N-001-MR | L04 | CT-L04-N-001-MR | L04 | North | Curtain wall | 50 | 3300 | Blue-grey concept glass | CT-103 | CT-L04-N-001
CT-L04-N-001-FB | L04 | CT-L04-N-001-FB | L04 | North | Curtain wall | 1250 | 50 | Blue-grey concept glass | CT-103 | CT-L04-N-001
CT-L04-N-001-FT | L04 | CT-L04-N-001-FT | L04 | North | Curtain wall | 1250 | 50 | Blue-grey concept glass | CT-103 | CT-L04-N-001
CT-L04-N-002-ML | L04 | CT-L04-N-002-ML | L04 | North | Curtain wall | 50 | 3300 | Blue-grey concept glass | CT-103 | CT-L04-N-002
CT-L04-N-002-MR | L04 | CT-L04-N-002-MR | L04 | North | Curtain wall | 50 | 3300 | Blue-grey concept glass | CT-103 | CT-L04-N-002
CT-L04-N-002-FB | L04 | CT-L04-N-002-FB | L04 | North | Curtain wall | 1400 | 50 | Blue-grey concept glass | CT-103 | CT-L04-N-002
CT-L04-N-002-FT | L04 | CT-L04-N-002-FT | L04 | North | Curtain wall | 1400 | 50 | Blue-grey concept glass | CT-103 | CT-L04-N-002
CT-L04-N-003-ML | L04 | CT-L04-N-003-ML | L04 | North | Curtain wall | 50 | 3300 | Blue-grey concept glass | CT-103 | CT-L04-N-003
CT-L04-N-003-MR | L04 | CT-L04-N-003-MR | L04 | North | Curtain wall | 50 | 3300 | Blue-grey concept glass | CT-103 | CT-L04-N-003
CT-L04-N-003-FB | L04 | CT-L04-N-003-FB | L04 | North | Curtain wall | 1400 | 50 | Blue-grey concept glass | CT-103 | CT-L04-N-003
CT-L04-N-003-FT | L04 | CT-L04-N-003-FT | L04 | North | Curtain wall | 1400 | 50 | Blue-grey concept glass | CT-103 | CT-L04-N-003
CT-L04-N-004-ML | L04 | CT-L04-N-004-ML | L04 | North | Curtain wall | 50 | 3300 | Blue-grey concept glass | CT-103 | CT-L04-N-004
CT-L04-N-004-MR | L04 | CT-L04-N-004-MR | L04 | North | Curtain wall | 50 | 3300 | Blue-grey concept glass | CT-103 | CT-L04-N-004
CT-L04-N-004-FB | L04 | CT-L04-N-004-FB | L04 | North | Curtain wall | 1400 | 50 | Blue-grey concept glass | CT-103 | CT-L04-N-004
CT-L04-N-004-FT | L04 | CT-L04-N-004-FT | L04 | North | Curtain wall | 1400 | 50 | Blue-grey concept glass | CT-103 | CT-L04-N-004
CT-L04-N-005-ML | L04 | CT-L04-N-005-ML | L04 | North | Metal rainscreen | 50 | 3300 | Olive powder coat | CT-103 | CT-L04-N-005
CT-L04-N-005-MR | L04 | CT-L04-N-005-MR | L04 | North | Metal rainscreen | 50 | 3300 | Olive powder coat | CT-103 | CT-L04-N-005
CT-L04-N-005-FB | L04 | CT-L04-N-005-FB | L04 | North | Metal rainscreen | 1400 | 50 | Olive powder coat | CT-103 | CT-L04-N-005
CT-L04-N-005-FT | L04 | CT-L04-N-005-FT | L04 | North | Metal rainscreen | 1400 | 50 | Olive powder coat | CT-103 | CT-L04-N-005
CT-L04-N-006-ML | L04 | CT-L04-N-006-ML | L04 | North | Curtain wall | 50 | 3300 | Blue-grey concept glass | CT-103 | CT-L04-N-006
CT-L04-N-006-MR | L04 | CT-L04-N-006-MR | L04 | North | Curtain wall | 50 | 3300 | Blue-grey concept glass | CT-103 | CT-L04-N-006
CT-L04-N-006-FB | L04 | CT-L04-N-006-FB | L04 | North | Curtain wall | 1400 | 50 | Blue-grey concept glass | CT-103 | CT-L04-N-006
CT-L04-N-006-FT | L04 | CT-L04-N-006-FT | L04 | North | Curtain wall | 1400 | 50 | Blue-grey concept glass | CT-103 | CT-L04-N-006
CT-L04-N-007-ML | L04 | CT-L04-N-007-ML | L04 | North | Curtain wall | 50 | 3300 | Blue-grey concept glass | CT-103 | CT-L04-N-007
CT-L04-N-007-MR | L04 | CT-L04-N-007-MR | L04 | North | Curtain wall | 50 | 3300 | Blue-grey concept glass | CT-103 | CT-L04-N-007
CT-L04-N-007-FB | L04 | CT-L04-N-007-FB | L04 | North | Curtain wall | 1400 | 50 | Blue-grey concept glass | CT-103 | CT-L04-N-007
CT-L04-N-007-FT | L04 | CT-L04-N-007-FT | L04 | North | Curtain wall | 1400 | 50 | Blue-grey concept glass | CT-103 | CT-L04-N-007
CT-L04-N-008-ML | L04 | CT-L04-N-008-ML | L04 | North | Curtain wall | 50 | 3300 | Blue-grey concept glass | CT-103 | CT-L04-N-008
CT-L04-N-008-MR | L04 | CT-L04-N-008-MR | L04 | North | Curtain wall | 50 | 3300 | Blue-grey concept glass | CT-103 | CT-L04-N-008
CT-L04-N-008-FB | L04 | CT-L04-N-008-FB | L04 | North | Curtain wall | 1400 | 50 | Blue-grey concept glass | CT-103 | CT-L04-N-008
CT-L04-N-008-FT | L04 | CT-L04-N-008-FT | L04 | North | Curtain wall | 1400 | 50 | Blue-grey concept glass | CT-103 | CT-L04-N-008
CT-L04-N-009-ML | L04 | CT-L04-N-009-ML | L04 | North | Curtain wall | 50 | 3300 | Blue-grey concept glass | CT-103 | CT-L04-N-009
CT-L04-N-009-MR | L04 | CT-L04-N-009-MR | L04 | North | Curtain wall | 50 | 3300 | Blue-grey concept glass | CT-103 | CT-L04-N-009
CT-L04-N-009-FB | L04 | CT-L04-N-009-FB | L04 | North | Curtain wall | 1400 | 50 | Blue-grey concept glass | CT-103 | CT-L04-N-009
CT-L04-N-009-FT | L04 | CT-L04-N-009-FT | L04 | North | Curtain wall | 1400 | 50 | Blue-grey concept glass | CT-103 | CT-L04-N-009
CT-L04-N-010-ML | L04 | CT-L04-N-010-ML | L04 | North | Metal rainscreen | 50 | 3300 | Olive powder coat | CT-103 | CT-L04-N-010
CT-L04-N-010-MR | L04 | CT-L04-N-010-MR | L04 | North | Metal rainscreen | 50 | 3300 | Olive powder coat | CT-103 | CT-L04-N-010
CT-L04-N-010-FB | L04 | CT-L04-N-010-FB | L04 | North | Metal rainscreen | 1400 | 50 | Olive powder coat | CT-103 | CT-L04-N-010
CT-L04-N-010-FT | L04 | CT-L04-N-010-FT | L04 | North | Metal rainscreen | 1400 | 50 | Olive powder coat | CT-103 | CT-L04-N-010
CT-L04-N-011-ML | L04 | CT-L04-N-011-ML | L04 | North | Curtain wall | 50 | 3300 | Blue-grey concept glass | CT-103 | CT-L04-N-011
CT-L04-N-011-MR | L04 | CT-L04-N-011-MR | L04 | North | Curtain wall | 50 | 3300 | Blue-grey concept glass | CT-103 | CT-L04-N-011
CT-L04-N-011-FB | L04 | CT-L04-N-011-FB | L04 | North | Curtain wall | 1400 | 50 | Blue-grey concept glass | CT-103 | CT-L04-N-011
CT-L04-N-011-FT | L04 | CT-L04-N-011-FT | L04 | North | Curtain wall | 1400 | 50 | Blue-grey concept glass | CT-103 | CT-L04-N-011
CT-L04-N-012-ML | L04 | CT-L04-N-012-ML | L04 | North | Curtain wall | 50 | 3300 | Blue-grey concept glass | CT-103 | CT-L04-N-012
CT-L04-N-012-MR | L04 | CT-L04-N-012-MR | L04 | North | Curtain wall | 50 | 3300 | Blue-grey concept glass | CT-103 | CT-L04-N-012
CT-L04-N-012-FB | L04 | CT-L04-N-012-FB | L04 | North | Curtain wall | 1400 | 50 | Blue-grey concept glass | CT-103 | CT-L04-N-012
CT-L04-N-012-FT | L04 | CT-L04-N-012-FT | L04 | North | Curtain wall | 1400 | 50 | Blue-grey concept glass | CT-103 | CT-L04-N-012
CT-L04-N-013-ML | L04 | CT-L04-N-013-ML | L04 | North | Curtain wall | 50 | 3300 | Blue-grey concept glass | CT-103 | CT-L04-N-013
CT-L04-N-013-MR | L04 | CT-L04-N-013-MR | L04 | North | Curtain wall | 50 | 3300 | Blue-grey concept glass | CT-103 | CT-L04-N-013
CT-L04-N-013-FB | L04 | CT-L04-N-013-FB | L04 | North | Curtain wall | 1400 | 50 | Blue-grey concept glass | CT-103 | CT-L04-N-013
CT-L04-N-013-FT | L04 | CT-L04-N-013-FT | L04 | North | Curtain wall | 1400 | 50 | Blue-grey concept glass | CT-103 | CT-L04-N-013
CT-L04-N-014-ML | L04 | CT-L04-N-014-ML | L04 | North | Curtain wall | 50 | 3300 | Blue-grey concept glass | CT-103 | CT-L04-N-014
CT-L04-N-014-MR | L04 | CT-L04-N-014-MR | L04 | North | Curtain wall | 50 | 3300 | Blue-grey concept glass | CT-103 | CT-L04-N-014
CT-L04-N-014-FB | L04 | CT-L04-N-014-FB | L04 | North | Curtain wall | 1250 | 50 | Blue-grey concept glass | CT-103 | CT-L04-N-014
CT-L04-N-014-FT | L04 | CT-L04-N-014-FT | L04 | North | Curtain wall | 1250 | 50 | Blue-grey concept glass | CT-103 | CT-L04-N-014
CT-L04-W-001-ML | L04 | CT-L04-W-001-ML | L04 | West | Curtain wall | 50 | 3300 | Blue-grey concept glass | CT-104 | CT-L04-W-001
CT-L04-W-001-MR | L04 | CT-L04-W-001-MR | L04 | West | Curtain wall | 50 | 3300 | Blue-grey concept glass | CT-104 | CT-L04-W-001
CT-L04-W-001-FB | L04 | CT-L04-W-001-FB | L04 | West | Curtain wall | 1250 | 50 | Blue-grey concept glass | CT-104 | CT-L04-W-001
CT-L04-W-001-FT | L04 | CT-L04-W-001-FT | L04 | West | Curtain wall | 1250 | 50 | Blue-grey concept glass | CT-104 | CT-L04-W-001
CT-L04-W-002-ML | L04 | CT-L04-W-002-ML | L04 | West | Curtain wall | 50 | 3300 | Blue-grey concept glass | CT-104 | CT-L04-W-002
CT-L04-W-002-MR | L04 | CT-L04-W-002-MR | L04 | West | Curtain wall | 50 | 3300 | Blue-grey concept glass | CT-104 | CT-L04-W-002
CT-L04-W-002-FB | L04 | CT-L04-W-002-FB | L04 | West | Curtain wall | 1400 | 50 | Blue-grey concept glass | CT-104 | CT-L04-W-002
CT-L04-W-002-FT | L04 | CT-L04-W-002-FT | L04 | West | Curtain wall | 1400 | 50 | Blue-grey concept glass | CT-104 | CT-L04-W-002
CT-L04-W-003-ML | L04 | CT-L04-W-003-ML | L04 | West | Curtain wall | 50 | 3300 | Blue-grey concept glass | CT-104 | CT-L04-W-003
CT-L04-W-003-MR | L04 | CT-L04-W-003-MR | L04 | West | Curtain wall | 50 | 3300 | Blue-grey concept glass | CT-104 | CT-L04-W-003
CT-L04-W-003-FB | L04 | CT-L04-W-003-FB | L04 | West | Curtain wall | 1400 | 50 | Blue-grey concept glass | CT-104 | CT-L04-W-003
CT-L04-W-003-FT | L04 | CT-L04-W-003-FT | L04 | West | Curtain wall | 1400 | 50 | Blue-grey concept glass | CT-104 | CT-L04-W-003
CT-L04-W-004-ML | L04 | CT-L04-W-004-ML | L04 | West | Curtain wall | 50 | 3300 | Blue-grey concept glass | CT-104 | CT-L04-W-004
CT-L04-W-004-MR | L04 | CT-L04-W-004-MR | L04 | West | Curtain wall | 50 | 3300 | Blue-grey concept glass | CT-104 | CT-L04-W-004
CT-L04-W-004-FB | L04 | CT-L04-W-004-FB | L04 | West | Curtain wall | 1400 | 50 | Blue-grey concept glass | CT-104 | CT-L04-W-004
CT-L04-W-004-FT | L04 | CT-L04-W-004-FT | L04 | West | Curtain wall | 1400 | 50 | Blue-grey concept glass | CT-104 | CT-L04-W-004
CT-L04-W-005-ML | L04 | CT-L04-W-005-ML | L04 | West | Metal rainscreen | 50 | 3300 | Olive powder coat | CT-104 | CT-L04-W-005
CT-L04-W-005-MR | L04 | CT-L04-W-005-MR | L04 | West | Metal rainscreen | 50 | 3300 | Olive powder coat | CT-104 | CT-L04-W-005
CT-L04-W-005-FB | L04 | CT-L04-W-005-FB | L04 | West | Metal rainscreen | 1400 | 50 | Olive powder coat | CT-104 | CT-L04-W-005
CT-L04-W-005-FT | L04 | CT-L04-W-005-FT | L04 | West | Metal rainscreen | 1400 | 50 | Olive powder coat | CT-104 | CT-L04-W-005
CT-L04-W-006-ML | L04 | CT-L04-W-006-ML | L04 | West | Curtain wall | 50 | 3300 | Blue-grey concept glass | CT-104 | CT-L04-W-006
CT-L04-W-006-MR | L04 | CT-L04-W-006-MR | L04 | West | Curtain wall | 50 | 3300 | Blue-grey concept glass | CT-104 | CT-L04-W-006
CT-L04-W-006-FB | L04 | CT-L04-W-006-FB | L04 | West | Curtain wall | 1400 | 50 | Blue-grey concept glass | CT-104 | CT-L04-W-006
CT-L04-W-006-FT | L04 | CT-L04-W-006-FT | L04 | West | Curtain wall | 1400 | 50 | Blue-grey concept glass | CT-104 | CT-L04-W-006
CT-L04-W-007-ML | L04 | CT-L04-W-007-ML | L04 | West | Curtain wall | 50 | 3300 | Blue-grey concept glass | CT-104 | CT-L04-W-007
CT-L04-W-007-MR | L04 | CT-L04-W-007-MR | L04 | West | Curtain wall | 50 | 3300 | Blue-grey concept glass | CT-104 | CT-L04-W-007
CT-L04-W-007-FB | L04 | CT-L04-W-007-FB | L04 | West | Curtain wall | 1400 | 50 | Blue-grey concept glass | CT-104 | CT-L04-W-007
CT-L04-W-007-FT | L04 | CT-L04-W-007-FT | L04 | West | Curtain wall | 1400 | 50 | Blue-grey concept glass | CT-104 | CT-L04-W-007
CT-L04-W-008-ML | L04 | CT-L04-W-008-ML | L04 | West | Curtain wall | 50 | 3300 | Blue-grey concept glass | CT-104 | CT-L04-W-008
CT-L04-W-008-MR | L04 | CT-L04-W-008-MR | L04 | West | Curtain wall | 50 | 3300 | Blue-grey concept glass | CT-104 | CT-L04-W-008
CT-L04-W-008-FB | L04 | CT-L04-W-008-FB | L04 | West | Curtain wall | 1400 | 50 | Blue-grey concept glass | CT-104 | CT-L04-W-008
CT-L04-W-008-FT | L04 | CT-L04-W-008-FT | L04 | West | Curtain wall | 1400 | 50 | Blue-grey concept glass | CT-104 | CT-L04-W-008
CT-L04-W-009-ML | L04 | CT-L04-W-009-ML | L04 | West | Curtain wall | 50 | 3300 | Blue-grey concept glass | CT-104 | CT-L04-W-009
CT-L04-W-009-MR | L04 | CT-L04-W-009-MR | L04 | West | Curtain wall | 50 | 3300 | Blue-grey concept glass | CT-104 | CT-L04-W-009
CT-L04-W-009-FB | L04 | CT-L04-W-009-FB | L04 | West | Curtain wall | 1400 | 50 | Blue-grey concept glass | CT-104 | CT-L04-W-009
CT-L04-W-009-FT | L04 | CT-L04-W-009-FT | L04 | West | Curtain wall | 1400 | 50 | Blue-grey concept glass | CT-104 | CT-L04-W-009
CT-L04-W-010-ML | L04 | CT-L04-W-010-ML | L04 | West | Metal rainscreen | 50 | 3300 | Olive powder coat | CT-104 | CT-L04-W-010
CT-L04-W-010-MR | L04 | CT-L04-W-010-MR | L04 | West | Metal rainscreen | 50 | 3300 | Olive powder coat | CT-104 | CT-L04-W-010
CT-L04-W-010-FB | L04 | CT-L04-W-010-FB | L04 | West | Metal rainscreen | 1250 | 50 | Olive powder coat | CT-104 | CT-L04-W-010
CT-L04-W-010-FT | L04 | CT-L04-W-010-FT | L04 | West | Metal rainscreen | 1250 | 50 | Olive powder coat | CT-104 | CT-L04-W-010
CT-L05-S-001-ML | L05 | CT-L05-S-001-ML | L05 | South | Curtain wall | 50 | 3300 | Blue-grey concept glass | CT-101 | CT-L05-S-001
CT-L05-S-001-MR | L05 | CT-L05-S-001-MR | L05 | South | Curtain wall | 50 | 3300 | Blue-grey concept glass | CT-101 | CT-L05-S-001
CT-L05-S-001-FB | L05 | CT-L05-S-001-FB | L05 | South | Curtain wall | 1250 | 50 | Blue-grey concept glass | CT-101 | CT-L05-S-001
CT-L05-S-001-FT | L05 | CT-L05-S-001-FT | L05 | South | Curtain wall | 1250 | 50 | Blue-grey concept glass | CT-101 | CT-L05-S-001
CT-L05-S-002-ML | L05 | CT-L05-S-002-ML | L05 | South | Curtain wall | 50 | 3300 | Blue-grey concept glass | CT-101 | CT-L05-S-002
CT-L05-S-002-MR | L05 | CT-L05-S-002-MR | L05 | South | Curtain wall | 50 | 3300 | Blue-grey concept glass | CT-101 | CT-L05-S-002
CT-L05-S-002-FB | L05 | CT-L05-S-002-FB | L05 | South | Curtain wall | 1400 | 50 | Blue-grey concept glass | CT-101 | CT-L05-S-002
CT-L05-S-002-FT | L05 | CT-L05-S-002-FT | L05 | South | Curtain wall | 1400 | 50 | Blue-grey concept glass | CT-101 | CT-L05-S-002
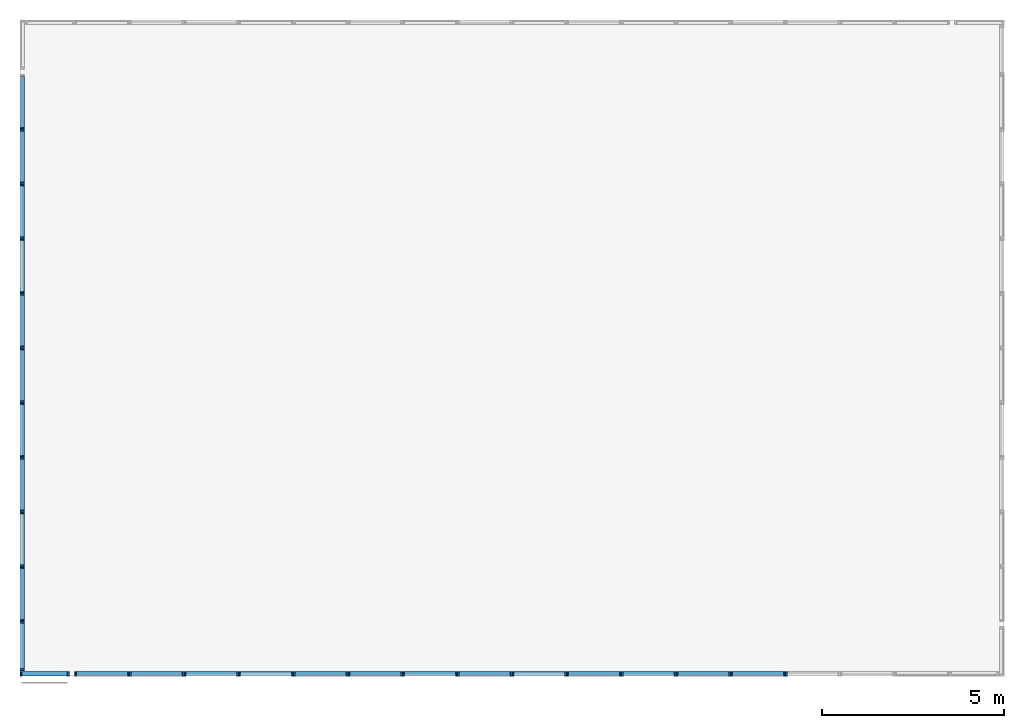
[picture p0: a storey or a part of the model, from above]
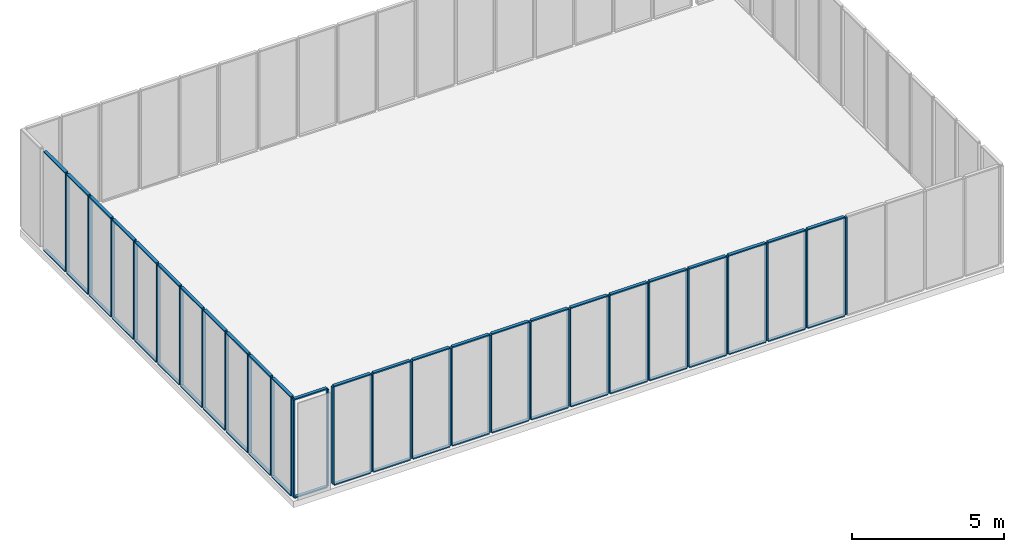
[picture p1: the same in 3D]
Properties of the parts of a building model (IFC4), part 3 of 7

# IfcMember (2304)
Name | In | ElementID | Floor | Elevation | System = Group | Width_mm | Height_mm | Finish | DrawingRef | ParentPanelID
CT-L05-S-003-ML | L05 | CT-L05-S-003-ML | L05 | South | Curtain wall | 50 | 3300 | Blue-grey concept glass | CT-101 | CT-L05-S-003
CT-L05-S-003-MR | L05 | CT-L05-S-003-MR | L05 | South | Curtain wall | 50 | 3300 | Blue-grey concept glass | CT-101 | CT-L05-S-003
CT-L05-S-003-FB | L05 | CT-L05-S-003-FB | L05 | South | Curtain wall | 1400 | 50 | Blue-grey concept glass | CT-101 | CT-L05-S-003
CT-L05-S-003-FT | L05 | CT-L05-S-003-FT | L05 | South | Curtain wall | 1400 | 50 | Blue-grey concept glass | CT-101 | CT-L05-S-003
CT-L05-S-004-ML | L05 | CT-L05-S-004-ML | L05 | South | Curtain wall | 50 | 3300 | Blue-grey concept glass | CT-101 | CT-L05-S-004
CT-L05-S-004-MR | L05 | CT-L05-S-004-MR | L05 | South | Curtain wall | 50 | 3300 | Blue-grey concept glass | CT-101 | CT-L05-S-004
CT-L05-S-004-FB | L05 | CT-L05-S-004-FB | L05 | South | Curtain wall | 1400 | 50 | Blue-grey concept glass | CT-101 | CT-L05-S-004
CT-L05-S-004-FT | L05 | CT-L05-S-004-FT | L05 | South | Curtain wall | 1400 | 50 | Blue-grey concept glass | CT-101 | CT-L05-S-004
CT-L05-S-005-ML | L05 | CT-L05-S-005-ML | L05 | South | Metal rainscreen | 50 | 3300 | Olive powder coat | CT-101 | CT-L05-S-005
CT-L05-S-005-MR | L05 | CT-L05-S-005-MR | L05 | South | Metal rainscreen | 50 | 3300 | Olive powder coat | CT-101 | CT-L05-S-005
CT-L05-S-005-FB | L05 | CT-L05-S-005-FB | L05 | South | Metal rainscreen | 1400 | 50 | Olive powder coat | CT-101 | CT-L05-S-005
CT-L05-S-005-FT | L05 | CT-L05-S-005-FT | L05 | South | Metal rainscreen | 1400 | 50 | Olive powder coat | CT-101 | CT-L05-S-005
CT-L05-S-006-ML | L05 | CT-L05-S-006-ML | L05 | South | Curtain wall | 50 | 3300 | Blue-grey concept glass | CT-101 | CT-L05-S-006
CT-L05-S-006-MR | L05 | CT-L05-S-006-MR | L05 | South | Curtain wall | 50 | 3300 | Blue-grey concept glass | CT-101 | CT-L05-S-006
CT-L05-S-006-FB | L05 | CT-L05-S-006-FB | L05 | South | Curtain wall | 1400 | 50 | Blue-grey concept glass | CT-101 | CT-L05-S-006
CT-L05-S-006-FT | L05 | CT-L05-S-006-FT | L05 | South | Curtain wall | 1400 | 50 | Blue-grey concept glass | CT-101 | CT-L05-S-006
CT-L05-S-007-ML | L05 | CT-L05-S-007-ML | L05 | South | Curtain wall | 50 | 3300 | Blue-grey concept glass | CT-101 | CT-L05-S-007
CT-L05-S-007-MR | L05 | CT-L05-S-007-MR | L05 | South | Curtain wall | 50 | 3300 | Blue-grey concept glass | CT-101 | CT-L05-S-007
CT-L05-S-007-FB | L05 | CT-L05-S-007-FB | L05 | South | Curtain wall | 1400 | 50 | Blue-grey concept glass | CT-101 | CT-L05-S-007
CT-L05-S-007-FT | L05 | CT-L05-S-007-FT | L05 | South | Curtain wall | 1400 | 50 | Blue-grey concept glass | CT-101 | CT-L05-S-007
CT-L05-S-008-ML | L05 | CT-L05-S-008-ML | L05 | South | Curtain wall | 50 | 3300 | Blue-grey concept glass | CT-101 | CT-L05-S-008
CT-L05-S-008-MR | L05 | CT-L05-S-008-MR | L05 | South | Curtain wall | 50 | 3300 | Blue-grey concept glass | CT-101 | CT-L05-S-008
CT-L05-S-008-FB | L05 | CT-L05-S-008-FB | L05 | South | Curtain wall | 1400 | 50 | Blue-grey concept glass | CT-101 | CT-L05-S-008
CT-L05-S-008-FT | L05 | CT-L05-S-008-FT | L05 | South | Curtain wall | 1400 | 50 | Blue-grey concept glass | CT-101 | CT-L05-S-008
CT-L05-S-009-ML | L05 | CT-L05-S-009-ML | L05 | South | Curtain wall | 50 | 3300 | Blue-grey concept glass | CT-101 | CT-L05-S-009
CT-L05-S-009-MR | L05 | CT-L05-S-009-MR | L05 | South | Curtain wall | 50 | 3300 | Blue-grey concept glass | CT-101 | CT-L05-S-009
CT-L05-S-009-FB | L05 | CT-L05-S-009-FB | L05 | South | Curtain wall | 1400 | 50 | Blue-grey concept glass | CT-101 | CT-L05-S-009
CT-L05-S-009-FT | L05 | CT-L05-S-009-FT | L05 | South | Curtain wall | 1400 | 50 | Blue-grey concept glass | CT-101 | CT-L05-S-009
CT-L05-S-010-ML | L05 | CT-L05-S-010-ML | L05 | South | Metal rainscreen | 50 | 3300 | Olive powder coat | CT-101 | CT-L05-S-010
CT-L05-S-010-MR | L05 | CT-L05-S-010-MR | L05 | South | Metal rainscreen | 50 | 3300 | Olive powder coat | CT-101 | CT-L05-S-010
CT-L05-S-010-FB | L05 | CT-L05-S-010-FB | L05 | South | Metal rainscreen | 1400 | 50 | Olive powder coat | CT-101 | CT-L05-S-010
CT-L05-S-010-FT | L05 | CT-L05-S-010-FT | L05 | South | Metal rainscreen | 1400 | 50 | Olive powder coat | CT-101 | CT-L05-S-010
CT-L05-S-011-ML | L05 | CT-L05-S-011-ML | L05 | South | Curtain wall | 50 | 3300 | Blue-grey concept glass | CT-101 | CT-L05-S-011
CT-L05-S-011-MR | L05 | CT-L05-S-011-MR | L05 | South | Curtain wall | 50 | 3300 | Blue-grey concept glass | CT-101 | CT-L05-S-011
CT-L05-S-011-FB | L05 | CT-L05-S-011-FB | L05 | South | Curtain wall | 1400 | 50 | Blue-grey concept glass | CT-101 | CT-L05-S-011
CT-L05-S-011-FT | L05 | CT-L05-S-011-FT | L05 | South | Curtain wall | 1400 | 50 | Blue-grey concept glass | CT-101 | CT-L05-S-011
CT-L05-S-012-ML | L05 | CT-L05-S-012-ML | L05 | South | Curtain wall | 50 | 3300 | Blue-grey concept glass | CT-101 | CT-L05-S-012
CT-L05-S-012-MR | L05 | CT-L05-S-012-MR | L05 | South | Curtain wall | 50 | 3300 | Blue-grey concept glass | CT-101 | CT-L05-S-012
CT-L05-S-012-FB | L05 | CT-L05-S-012-FB | L05 | South | Curtain wall | 1400 | 50 | Blue-grey concept glass | CT-101 | CT-L05-S-012
CT-L05-S-012-FT | L05 | CT-L05-S-012-FT | L05 | South | Curtain wall | 1400 | 50 | Blue-grey concept glass | CT-101 | CT-L05-S-012
CT-L05-S-013-ML | L05 | CT-L05-S-013-ML | L05 | South | Curtain wall | 50 | 3300 | Blue-grey concept glass | CT-101 | CT-L05-S-013
CT-L05-S-013-MR | L05 | CT-L05-S-013-MR | L05 | South | Curtain wall | 50 | 3300 | Blue-grey concept glass | CT-101 | CT-L05-S-013
CT-L05-S-013-FB | L05 | CT-L05-S-013-FB | L05 | South | Curtain wall | 1400 | 50 | Blue-grey concept glass | CT-101 | CT-L05-S-013
CT-L05-S-013-FT | L05 | CT-L05-S-013-FT | L05 | South | Curtain wall | 1400 | 50 | Blue-grey concept glass | CT-101 | CT-L05-S-013
CT-L05-S-014-ML | L05 | CT-L05-S-014-ML | L05 | South | Curtain wall | 50 | 3300 | Blue-grey concept glass | CT-101 | CT-L05-S-014
CT-L05-S-014-MR | L05 | CT-L05-S-014-MR | L05 | South | Curtain wall | 50 | 3300 | Blue-grey concept glass | CT-101 | CT-L05-S-014
CT-L05-S-014-FB | L05 | CT-L05-S-014-FB | L05 | South | Curtain wall | 1250 | 50 | Blue-grey concept glass | CT-101 | CT-L05-S-014
CT-L05-S-014-FT | L05 | CT-L05-S-014-FT | L05 | South | Curtain wall | 1250 | 50 | Blue-grey concept glass | CT-101 | CT-L05-S-014
CT-L05-E-001-ML | L05 | CT-L05-E-001-ML | L05 | East | Curtain wall | 50 | 3300 | Blue-grey concept glass | CT-102 | CT-L05-E-001
CT-L05-E-001-MR | L05 | CT-L05-E-001-MR | L05 | East | Curtain wall | 50 | 3300 | Blue-grey concept glass | CT-102 | CT-L05-E-001
CT-L05-E-001-FB | L05 | CT-L05-E-001-FB | L05 | East | Curtain wall | 1250 | 50 | Blue-grey concept glass | CT-102 | CT-L05-E-001
CT-L05-E-001-FT | L05 | CT-L05-E-001-FT | L05 | East | Curtain wall | 1250 | 50 | Blue-grey concept glass | CT-102 | CT-L05-E-001
CT-L05-E-002-ML | L05 | CT-L05-E-002-ML | L05 | East | Curtain wall | 50 | 3300 | Blue-grey concept glass | CT-102 | CT-L05-E-002
CT-L05-E-002-MR | L05 | CT-L05-E-002-MR | L05 | East | Curtain wall | 50 | 3300 | Blue-grey concept glass | CT-102 | CT-L05-E-002
CT-L05-E-002-FB | L05 | CT-L05-E-002-FB | L05 | East | Curtain wall | 1400 | 50 | Blue-grey concept glass | CT-102 | CT-L05-E-002
CT-L05-E-002-FT | L05 | CT-L05-E-002-FT | L05 | East | Curtain wall | 1400 | 50 | Blue-grey concept glass | CT-102 | CT-L05-E-002
CT-L05-E-003-ML | L05 | CT-L05-E-003-ML | L05 | East | Curtain wall | 50 | 3300 | Blue-grey concept glass | CT-102 | CT-L05-E-003
CT-L05-E-003-MR | L05 | CT-L05-E-003-MR | L05 | East | Curtain wall | 50 | 3300 | Blue-grey concept glass | CT-102 | CT-L05-E-003
CT-L05-E-003-FB | L05 | CT-L05-E-003-FB | L05 | East | Curtain wall | 1400 | 50 | Blue-grey concept glass | CT-102 | CT-L05-E-003
CT-L05-E-003-FT | L05 | CT-L05-E-003-FT | L05 | East | Curtain wall | 1400 | 50 | Blue-grey concept glass | CT-102 | CT-L05-E-003
CT-L05-E-004-ML | L05 | CT-L05-E-004-ML | L05 | East | Curtain wall | 50 | 3300 | Blue-grey concept glass | CT-102 | CT-L05-E-004
CT-L05-E-004-MR | L05 | CT-L05-E-004-MR | L05 | East | Curtain wall | 50 | 3300 | Blue-grey concept glass | CT-102 | CT-L05-E-004
CT-L05-E-004-FB | L05 | CT-L05-E-004-FB | L05 | East | Curtain wall | 1400 | 50 | Blue-grey concept glass | CT-102 | CT-L05-E-004
CT-L05-E-004-FT | L05 | CT-L05-E-004-FT | L05 | East | Curtain wall | 1400 | 50 | Blue-grey concept glass | CT-102 | CT-L05-E-004
CT-L05-E-005-ML | L05 | CT-L05-E-005-ML | L05 | East | Metal rainscreen | 50 | 3300 | Olive powder coat | CT-102 | CT-L05-E-005
CT-L05-E-005-MR | L05 | CT-L05-E-005-MR | L05 | East | Metal rainscreen | 50 | 3300 | Olive powder coat | CT-102 | CT-L05-E-005
CT-L05-E-005-FB | L05 | CT-L05-E-005-FB | L05 | East | Metal rainscreen | 1400 | 50 | Olive powder coat | CT-102 | CT-L05-E-005
CT-L05-E-005-FT | L05 | CT-L05-E-005-FT | L05 | East | Metal rainscreen | 1400 | 50 | Olive powder coat | CT-102 | CT-L05-E-005
CT-L05-E-006-ML | L05 | CT-L05-E-006-ML | L05 | East | Curtain wall | 50 | 3300 | Blue-grey concept glass | CT-102 | CT-L05-E-006
CT-L05-E-006-MR | L05 | CT-L05-E-006-MR | L05 | East | Curtain wall | 50 | 3300 | Blue-grey concept glass | CT-102 | CT-L05-E-006
CT-L05-E-006-FB | L05 | CT-L05-E-006-FB | L05 | East | Curtain wall | 1400 | 50 | Blue-grey concept glass | CT-102 | CT-L05-E-006
CT-L05-E-006-FT | L05 | CT-L05-E-006-FT | L05 | East | Curtain wall | 1400 | 50 | Blue-grey concept glass | CT-102 | CT-L05-E-006
CT-L05-E-007-ML | L05 | CT-L05-E-007-ML | L05 | East | Curtain wall | 50 | 3300 | Blue-grey concept glass | CT-102 | CT-L05-E-007
CT-L05-E-007-MR | L05 | CT-L05-E-007-MR | L05 | East | Curtain wall | 50 | 3300 | Blue-grey concept glass | CT-102 | CT-L05-E-007
CT-L05-E-007-FB | L05 | CT-L05-E-007-FB | L05 | East | Curtain wall | 1400 | 50 | Blue-grey concept glass | CT-102 | CT-L05-E-007
CT-L05-E-007-FT | L05 | CT-L05-E-007-FT | L05 | East | Curtain wall | 1400 | 50 | Blue-grey concept glass | CT-102 | CT-L05-E-007
CT-L05-E-008-ML | L05 | CT-L05-E-008-ML | L05 | East | Curtain wall | 50 | 3300 | Blue-grey concept glass | CT-102 | CT-L05-E-008
CT-L05-E-008-MR | L05 | CT-L05-E-008-MR | L05 | East | Curtain wall | 50 | 3300 | Blue-grey concept glass | CT-102 | CT-L05-E-008
CT-L05-E-008-FB | L05 | CT-L05-E-008-FB | L05 | East | Curtain wall | 1400 | 50 | Blue-grey concept glass | CT-102 | CT-L05-E-008
CT-L05-E-008-FT | L05 | CT-L05-E-008-FT | L05 | East | Curtain wall | 1400 | 50 | Blue-grey concept glass | CT-102 | CT-L05-E-008
CT-L05-E-009-ML | L05 | CT-L05-E-009-ML | L05 | East | Curtain wall | 50 | 3300 | Blue-grey concept glass | CT-102 | CT-L05-E-009
CT-L05-E-009-MR | L05 | CT-L05-E-009-MR | L05 | East | Curtain wall | 50 | 3300 | Blue-grey concept glass | CT-102 | CT-L05-E-009
CT-L05-E-009-FB | L05 | CT-L05-E-009-FB | L05 | East | Curtain wall | 1400 | 50 | Blue-grey concept glass | CT-102 | CT-L05-E-009
CT-L05-E-009-FT | L05 | CT-L05-E-009-FT | L05 | East | Curtain wall | 1400 | 50 | Blue-grey concept glass | CT-102 | CT-L05-E-009
CT-L05-E-010-ML | L05 | CT-L05-E-010-ML | L05 | East | Metal rainscreen | 50 | 3300 | Olive powder coat | CT-102 | CT-L05-E-010
CT-L05-E-010-MR | L05 | CT-L05-E-010-MR | L05 | East | Metal rainscreen | 50 | 3300 | Olive powder coat | CT-102 | CT-L05-E-010
CT-L05-E-010-FB | L05 | CT-L05-E-010-FB | L05 | East | Metal rainscreen | 1250 | 50 | Olive powder coat | CT-102 | CT-L05-E-010
CT-L05-E-010-FT | L05 | CT-L05-E-010-FT | L05 | East | Metal rainscreen | 1250 | 50 | Olive powder coat | CT-102 | CT-L05-E-010
CT-L05-N-001-ML | L05 | CT-L05-N-001-ML | L05 | North | Curtain wall | 50 | 3300 | Blue-grey concept glass | CT-103 | CT-L05-N-001
CT-L05-N-001-MR | L05 | CT-L05-N-001-MR | L05 | North | Curtain wall | 50 | 3300 | Blue-grey concept glass | CT-103 | CT-L05-N-001
CT-L05-N-001-FB | L05 | CT-L05-N-001-FB | L05 | North | Curtain wall | 1250 | 50 | Blue-grey concept glass | CT-103 | CT-L05-N-001
CT-L05-N-001-FT | L05 | CT-L05-N-001-FT | L05 | North | Curtain wall | 1250 | 50 | Blue-grey concept glass | CT-103 | CT-L05-N-001
CT-L05-N-002-ML | L05 | CT-L05-N-002-ML | L05 | North | Curtain wall | 50 | 3300 | Blue-grey concept glass | CT-103 | CT-L05-N-002
CT-L05-N-002-MR | L05 | CT-L05-N-002-MR | L05 | North | Curtain wall | 50 | 3300 | Blue-grey concept glass | CT-103 | CT-L05-N-002
CT-L05-N-002-FB | L05 | CT-L05-N-002-FB | L05 | North | Curtain wall | 1400 | 50 | Blue-grey concept glass | CT-103 | CT-L05-N-002
CT-L05-N-002-FT | L05 | CT-L05-N-002-FT | L05 | North | Curtain wall | 1400 | 50 | Blue-grey concept glass | CT-103 | CT-L05-N-002
CT-L05-N-003-ML | L05 | CT-L05-N-003-ML | L05 | North | Curtain wall | 50 | 3300 | Blue-grey concept glass | CT-103 | CT-L05-N-003
CT-L05-N-003-MR | L05 | CT-L05-N-003-MR | L05 | North | Curtain wall | 50 | 3300 | Blue-grey concept glass | CT-103 | CT-L05-N-003
CT-L05-N-003-FB | L05 | CT-L05-N-003-FB | L05 | North | Curtain wall | 1400 | 50 | Blue-grey concept glass | CT-103 | CT-L05-N-003
CT-L05-N-003-FT | L05 | CT-L05-N-003-FT | L05 | North | Curtain wall | 1400 | 50 | Blue-grey concept glass | CT-103 | CT-L05-N-003
CT-L05-N-004-ML | L05 | CT-L05-N-004-ML | L05 | North | Curtain wall | 50 | 3300 | Blue-grey concept glass | CT-103 | CT-L05-N-004
CT-L05-N-004-MR | L05 | CT-L05-N-004-MR | L05 | North | Curtain wall | 50 | 3300 | Blue-grey concept glass | CT-103 | CT-L05-N-004
CT-L05-N-004-FB | L05 | CT-L05-N-004-FB | L05 | North | Curtain wall | 1400 | 50 | Blue-grey concept glass | CT-103 | CT-L05-N-004
CT-L05-N-004-FT | L05 | CT-L05-N-004-FT | L05 | North | Curtain wall | 1400 | 50 | Blue-grey concept glass | CT-103 | CT-L05-N-004
CT-L05-N-005-ML | L05 | CT-L05-N-005-ML | L05 | North | Metal rainscreen | 50 | 3300 | Olive powder coat | CT-103 | CT-L05-N-005
CT-L05-N-005-MR | L05 | CT-L05-N-005-MR | L05 | North | Metal rainscreen | 50 | 3300 | Olive powder coat | CT-103 | CT-L05-N-005
CT-L05-N-005-FB | L05 | CT-L05-N-005-FB | L05 | North | Metal rainscreen | 1400 | 50 | Olive powder coat | CT-103 | CT-L05-N-005
CT-L05-N-005-FT | L05 | CT-L05-N-005-FT | L05 | North | Metal rainscreen | 1400 | 50 | Olive powder coat | CT-103 | CT-L05-N-005
CT-L05-N-006-ML | L05 | CT-L05-N-006-ML | L05 | North | Curtain wall | 50 | 3300 | Blue-grey concept glass | CT-103 | CT-L05-N-006
CT-L05-N-006-MR | L05 | CT-L05-N-006-MR | L05 | North | Curtain wall | 50 | 3300 | Blue-grey concept glass | CT-103 | CT-L05-N-006
CT-L05-N-006-FB | L05 | CT-L05-N-006-FB | L05 | North | Curtain wall | 1400 | 50 | Blue-grey concept glass | CT-103 | CT-L05-N-006
CT-L05-N-006-FT | L05 | CT-L05-N-006-FT | L05 | North | Curtain wall | 1400 | 50 | Blue-grey concept glass | CT-103 | CT-L05-N-006
CT-L05-N-007-ML | L05 | CT-L05-N-007-ML | L05 | North | Curtain wall | 50 | 3300 | Blue-grey concept glass | CT-103 | CT-L05-N-007
CT-L05-N-007-MR | L05 | CT-L05-N-007-MR | L05 | North | Curtain wall | 50 | 3300 | Blue-grey concept glass | CT-103 | CT-L05-N-007
CT-L05-N-007-FB | L05 | CT-L05-N-007-FB | L05 | North | Curtain wall | 1400 | 50 | Blue-grey concept glass | CT-103 | CT-L05-N-007
CT-L05-N-007-FT | L05 | CT-L05-N-007-FT | L05 | North | Curtain wall | 1400 | 50 | Blue-grey concept glass | CT-103 | CT-L05-N-007
CT-L05-N-008-ML | L05 | CT-L05-N-008-ML | L05 | North | Curtain wall | 50 | 3300 | Blue-grey concept glass | CT-103 | CT-L05-N-008
CT-L05-N-008-MR | L05 | CT-L05-N-008-MR | L05 | North | Curtain wall | 50 | 3300 | Blue-grey concept glass | CT-103 | CT-L05-N-008
CT-L05-N-008-FB | L05 | CT-L05-N-008-FB | L05 | North | Curtain wall | 1400 | 50 | Blue-grey concept glass | CT-103 | CT-L05-N-008
CT-L05-N-008-FT | L05 | CT-L05-N-008-FT | L05 | North | Curtain wall | 1400 | 50 | Blue-grey concept glass | CT-103 | CT-L05-N-008
CT-L05-N-009-ML | L05 | CT-L05-N-009-ML | L05 | North | Curtain wall | 50 | 3300 | Blue-grey concept glass | CT-103 | CT-L05-N-009
CT-L05-N-009-MR | L05 | CT-L05-N-009-MR | L05 | North | Curtain wall | 50 | 3300 | Blue-grey concept glass | CT-103 | CT-L05-N-009
CT-L05-N-009-FB | L05 | CT-L05-N-009-FB | L05 | North | Curtain wall | 1400 | 50 | Blue-grey concept glass | CT-103 | CT-L05-N-009
CT-L05-N-009-FT | L05 | CT-L05-N-009-FT | L05 | North | Curtain wall | 1400 | 50 | Blue-grey concept glass | CT-103 | CT-L05-N-009
CT-L05-N-010-ML | L05 | CT-L05-N-010-ML | L05 | North | Metal rainscreen | 50 | 3300 | Olive powder coat | CT-103 | CT-L05-N-010
CT-L05-N-010-MR | L05 | CT-L05-N-010-MR | L05 | North | Metal rainscreen | 50 | 3300 | Olive powder coat | CT-103 | CT-L05-N-010
CT-L05-N-010-FB | L05 | CT-L05-N-010-FB | L05 | North | Metal rainscreen | 1400 | 50 | Olive powder coat | CT-103 | CT-L05-N-010
CT-L05-N-010-FT | L05 | CT-L05-N-010-FT | L05 | North | Metal rainscreen | 1400 | 50 | Olive powder coat | CT-103 | CT-L05-N-010
CT-L05-N-011-ML | L05 | CT-L05-N-011-ML | L05 | North | Curtain wall | 50 | 3300 | Blue-grey concept glass | CT-103 | CT-L05-N-011
CT-L05-N-011-MR | L05 | CT-L05-N-011-MR | L05 | North | Curtain wall | 50 | 3300 | Blue-grey concept glass | CT-103 | CT-L05-N-011
CT-L05-N-011-FB | L05 | CT-L05-N-011-FB | L05 | North | Curtain wall | 1400 | 50 | Blue-grey concept glass | CT-103 | CT-L05-N-011
CT-L05-N-011-FT | L05 | CT-L05-N-011-FT | L05 | North | Curtain wall | 1400 | 50 | Blue-grey concept glass | CT-103 | CT-L05-N-011
CT-L05-N-012-ML | L05 | CT-L05-N-012-ML | L05 | North | Curtain wall | 50 | 3300 | Blue-grey concept glass | CT-103 | CT-L05-N-012
CT-L05-N-012-MR | L05 | CT-L05-N-012-MR | L05 | North | Curtain wall | 50 | 3300 | Blue-grey concept glass | CT-103 | CT-L05-N-012
CT-L05-N-012-FB | L05 | CT-L05-N-012-FB | L05 | North | Curtain wall | 1400 | 50 | Blue-grey concept glass | CT-103 | CT-L05-N-012
CT-L05-N-012-FT | L05 | CT-L05-N-012-FT | L05 | North | Curtain wall | 1400 | 50 | Blue-grey concept glass | CT-103 | CT-L05-N-012
CT-L05-N-013-ML | L05 | CT-L05-N-013-ML | L05 | North | Curtain wall | 50 | 3300 | Blue-grey concept glass | CT-103 | CT-L05-N-013
CT-L05-N-013-MR | L05 | CT-L05-N-013-MR | L05 | North | Curtain wall | 50 | 3300 | Blue-grey concept glass | CT-103 | CT-L05-N-013
CT-L05-N-013-FB | L05 | CT-L05-N-013-FB | L05 | North | Curtain wall | 1400 | 50 | Blue-grey concept glass | CT-103 | CT-L05-N-013
CT-L05-N-013-FT | L05 | CT-L05-N-013-FT | L05 | North | Curtain wall | 1400 | 50 | Blue-grey concept glass | CT-103 | CT-L05-N-013
CT-L05-N-014-ML | L05 | CT-L05-N-014-ML | L05 | North | Curtain wall | 50 | 3300 | Blue-grey concept glass | CT-103 | CT-L05-N-014
CT-L05-N-014-MR | L05 | CT-L05-N-014-MR | L05 | North | Curtain wall | 50 | 3300 | Blue-grey concept glass | CT-103 | CT-L05-N-014
CT-L05-N-014-FB | L05 | CT-L05-N-014-FB | L05 | North | Curtain wall | 1250 | 50 | Blue-grey concept glass | CT-103 | CT-L05-N-014
CT-L05-N-014-FT | L05 | CT-L05-N-014-FT | L05 | North | Curtain wall | 1250 | 50 | Blue-grey concept glass | CT-103 | CT-L05-N-014
CT-L05-W-001-ML | L05 | CT-L05-W-001-ML | L05 | West | Curtain wall | 50 | 3300 | Blue-grey concept glass | CT-104 | CT-L05-W-001
CT-L05-W-001-MR | L05 | CT-L05-W-001-MR | L05 | West | Curtain wall | 50 | 3300 | Blue-grey concept glass | CT-104 | CT-L05-W-001
CT-L05-W-001-FB | L05 | CT-L05-W-001-FB | L05 | West | Curtain wall | 1250 | 50 | Blue-grey concept glass | CT-104 | CT-L05-W-001
CT-L05-W-001-FT | L05 | CT-L05-W-001-FT | L05 | West | Curtain wall | 1250 | 50 | Blue-grey concept glass | CT-104 | CT-L05-W-001
CT-L05-W-002-ML | L05 | CT-L05-W-002-ML | L05 | West | Curtain wall | 50 | 3300 | Blue-grey concept glass | CT-104 | CT-L05-W-002
CT-L05-W-002-MR | L05 | CT-L05-W-002-MR | L05 | West | Curtain wall | 50 | 3300 | Blue-grey concept glass | CT-104 | CT-L05-W-002
CT-L05-W-002-FB | L05 | CT-L05-W-002-FB | L05 | West | Curtain wall | 1400 | 50 | Blue-grey concept glass | CT-104 | CT-L05-W-002
CT-L05-W-002-FT | L05 | CT-L05-W-002-FT | L05 | West | Curtain wall | 1400 | 50 | Blue-grey concept glass | CT-104 | CT-L05-W-002
CT-L05-W-003-ML | L05 | CT-L05-W-003-ML | L05 | West | Curtain wall | 50 | 3300 | Blue-grey concept glass | CT-104 | CT-L05-W-003
CT-L05-W-003-MR | L05 | CT-L05-W-003-MR | L05 | West | Curtain wall | 50 | 3300 | Blue-grey concept glass | CT-104 | CT-L05-W-003
CT-L05-W-003-FB | L05 | CT-L05-W-003-FB | L05 | West | Curtain wall | 1400 | 50 | Blue-grey concept glass | CT-104 | CT-L05-W-003
CT-L05-W-003-FT | L05 | CT-L05-W-003-FT | L05 | West | Curtain wall | 1400 | 50 | Blue-grey concept glass | CT-104 | CT-L05-W-003
CT-L05-W-004-ML | L05 | CT-L05-W-004-ML | L05 | West | Curtain wall | 50 | 3300 | Blue-grey concept glass | CT-104 | CT-L05-W-004
CT-L05-W-004-MR | L05 | CT-L05-W-004-MR | L05 | West | Curtain wall | 50 | 3300 | Blue-grey concept glass | CT-104 | CT-L05-W-004
CT-L05-W-004-FB | L05 | CT-L05-W-004-FB | L05 | West | Curtain wall | 1400 | 50 | Blue-grey concept glass | CT-104 | CT-L05-W-004
CT-L05-W-004-FT | L05 | CT-L05-W-004-FT | L05 | West | Curtain wall | 1400 | 50 | Blue-grey concept glass | CT-104 | CT-L05-W-004
CT-L05-W-005-ML | L05 | CT-L05-W-005-ML | L05 | West | Metal rainscreen | 50 | 3300 | Olive powder coat | CT-104 | CT-L05-W-005
CT-L05-W-005-MR | L05 | CT-L05-W-005-MR | L05 | West | Metal rainscreen | 50 | 3300 | Olive powder coat | CT-104 | CT-L05-W-005
CT-L05-W-005-FB | L05 | CT-L05-W-005-FB | L05 | West | Metal rainscreen | 1400 | 50 | Olive powder coat | CT-104 | CT-L05-W-005
CT-L05-W-005-FT | L05 | CT-L05-W-005-FT | L05 | West | Metal rainscreen | 1400 | 50 | Olive powder coat | CT-104 | CT-L05-W-005
CT-L05-W-006-ML | L05 | CT-L05-W-006-ML | L05 | West | Curtain wall | 50 | 3300 | Blue-grey concept glass | CT-104 | CT-L05-W-006
CT-L05-W-006-MR | L05 | CT-L05-W-006-MR | L05 | West | Curtain wall | 50 | 3300 | Blue-grey concept glass | CT-104 | CT-L05-W-006
CT-L05-W-006-FB | L05 | CT-L05-W-006-FB | L05 | West | Curtain wall | 1400 | 50 | Blue-grey concept glass | CT-104 | CT-L05-W-006
CT-L05-W-006-FT | L05 | CT-L05-W-006-FT | L05 | West | Curtain wall | 1400 | 50 | Blue-grey concept glass | CT-104 | CT-L05-W-006
CT-L05-W-007-ML | L05 | CT-L05-W-007-ML | L05 | West | Curtain wall | 50 | 3300 | Blue-grey concept glass | CT-104 | CT-L05-W-007
CT-L05-W-007-MR | L05 | CT-L05-W-007-MR | L05 | West | Curtain wall | 50 | 3300 | Blue-grey concept glass | CT-104 | CT-L05-W-007
CT-L05-W-007-FB | L05 | CT-L05-W-007-FB | L05 | West | Curtain wall | 1400 | 50 | Blue-grey concept glass | CT-104 | CT-L05-W-007
CT-L05-W-007-FT | L05 | CT-L05-W-007-FT | L05 | West | Curtain wall | 1400 | 50 | Blue-grey concept glass | CT-104 | CT-L05-W-007
CT-L05-W-008-ML | L05 | CT-L05-W-008-ML | L05 | West | Curtain wall | 50 | 3300 | Blue-grey concept glass | CT-104 | CT-L05-W-008
CT-L05-W-008-MR | L05 | CT-L05-W-008-MR | L05 | West | Curtain wall | 50 | 3300 | Blue-grey concept glass | CT-104 | CT-L05-W-008
CT-L05-W-008-FB | L05 | CT-L05-W-008-FB | L05 | West | Curtain wall | 1400 | 50 | Blue-grey concept glass | CT-104 | CT-L05-W-008
CT-L05-W-008-FT | L05 | CT-L05-W-008-FT | L05 | West | Curtain wall | 1400 | 50 | Blue-grey concept glass | CT-104 | CT-L05-W-008
CT-L05-W-009-ML | L05 | CT-L05-W-009-ML | L05 | West | Curtain wall | 50 | 3300 | Blue-grey concept glass | CT-104 | CT-L05-W-009
CT-L05-W-009-MR | L05 | CT-L05-W-009-MR | L05 | West | Curtain wall | 50 | 3300 | Blue-grey concept glass | CT-104 | CT-L05-W-009
CT-L05-W-009-FB | L05 | CT-L05-W-009-FB | L05 | West | Curtain wall | 1400 | 50 | Blue-grey concept glass | CT-104 | CT-L05-W-009
CT-L05-W-009-FT | L05 | CT-L05-W-009-FT | L05 | West | Curtain wall | 1400 | 50 | Blue-grey concept glass | CT-104 | CT-L05-W-009
CT-L05-W-010-ML | L05 | CT-L05-W-010-ML | L05 | West | Metal rainscreen | 50 | 3300 | Olive powder coat | CT-104 | CT-L05-W-010
CT-L05-W-010-MR | L05 | CT-L05-W-010-MR | L05 | West | Metal rainscreen | 50 | 3300 | Olive powder coat | CT-104 | CT-L05-W-010
CT-L05-W-010-FB | L05 | CT-L05-W-010-FB | L05 | West | Metal rainscreen | 1250 | 50 | Olive powder coat | CT-104 | CT-L05-W-010
CT-L05-W-010-FT | L05 | CT-L05-W-010-FT | L05 | West | Metal rainscreen | 1250 | 50 | Olive powder coat | CT-104 | CT-L05-W-010
CT-L06-S-001-ML | L06 | CT-L06-S-001-ML | L06 | South | Curtain wall | 50 | 3300 | Blue-grey concept glass | CT-101 | CT-L06-S-001
CT-L06-S-001-MR | L06 | CT-L06-S-001-MR | L06 | South | Curtain wall | 50 | 3300 | Blue-grey concept glass | CT-101 | CT-L06-S-001
CT-L06-S-001-FB | L06 | CT-L06-S-001-FB | L06 | South | Curtain wall | 1250 | 50 | Blue-grey concept glass | CT-101 | CT-L06-S-001
CT-L06-S-001-FT | L06 | CT-L06-S-001-FT | L06 | South | Curtain wall | 1250 | 50 | Blue-grey concept glass | CT-101 | CT-L06-S-001
CT-L06-S-002-ML | L06 | CT-L06-S-002-ML | L06 | South | Curtain wall | 50 | 3300 | Blue-grey concept glass | CT-101 | CT-L06-S-002
CT-L06-S-002-MR | L06 | CT-L06-S-002-MR | L06 | South | Curtain wall | 50 | 3300 | Blue-grey concept glass | CT-101 | CT-L06-S-002
CT-L06-S-002-FB | L06 | CT-L06-S-002-FB | L06 | South | Curtain wall | 1400 | 50 | Blue-grey concept glass | CT-101 | CT-L06-S-002
CT-L06-S-002-FT | L06 | CT-L06-S-002-FT | L06 | South | Curtain wall | 1400 | 50 | Blue-grey concept glass | CT-101 | CT-L06-S-002
CT-L06-S-003-ML | L06 | CT-L06-S-003-ML | L06 | South | Curtain wall | 50 | 3300 | Blue-grey concept glass | CT-101 | CT-L06-S-003
CT-L06-S-003-MR | L06 | CT-L06-S-003-MR | L06 | South | Curtain wall | 50 | 3300 | Blue-grey concept glass | CT-101 | CT-L06-S-003
CT-L06-S-003-FB | L06 | CT-L06-S-003-FB | L06 | South | Curtain wall | 1400 | 50 | Blue-grey concept glass | CT-101 | CT-L06-S-003
CT-L06-S-003-FT | L06 | CT-L06-S-003-FT | L06 | South | Curtain wall | 1400 | 50 | Blue-grey concept glass | CT-101 | CT-L06-S-003
CT-L06-S-004-ML | L06 | CT-L06-S-004-ML | L06 | South | Curtain wall | 50 | 3300 | Blue-grey concept glass | CT-101 | CT-L06-S-004
CT-L06-S-004-MR | L06 | CT-L06-S-004-MR | L06 | South | Curtain wall | 50 | 3300 | Blue-grey concept glass | CT-101 | CT-L06-S-004
CT-L06-S-004-FB | L06 | CT-L06-S-004-FB | L06 | South | Curtain wall | 1400 | 50 | Blue-grey concept glass | CT-101 | CT-L06-S-004
CT-L06-S-004-FT | L06 | CT-L06-S-004-FT | L06 | South | Curtain wall | 1400 | 50 | Blue-grey concept glass | CT-101 | CT-L06-S-004
CT-L06-S-005-ML | L06 | CT-L06-S-005-ML | L06 | South | Metal rainscreen | 50 | 3300 | Olive powder coat | CT-101 | CT-L06-S-005
CT-L06-S-005-MR | L06 | CT-L06-S-005-MR | L06 | South | Metal rainscreen | 50 | 3300 | Olive powder coat | CT-101 | CT-L06-S-005
CT-L06-S-005-FB | L06 | CT-L06-S-005-FB | L06 | South | Metal rainscreen | 1400 | 50 | Olive powder coat | CT-101 | CT-L06-S-005
CT-L06-S-005-FT | L06 | CT-L06-S-005-FT | L06 | South | Metal rainscreen | 1400 | 50 | Olive powder coat | CT-101 | CT-L06-S-005
CT-L06-S-006-ML | L06 | CT-L06-S-006-ML | L06 | South | Curtain wall | 50 | 3300 | Blue-grey concept glass | CT-101 | CT-L06-S-006
CT-L06-S-006-MR | L06 | CT-L06-S-006-MR | L06 | South | Curtain wall | 50 | 3300 | Blue-grey concept glass | CT-101 | CT-L06-S-006
CT-L06-S-006-FB | L06 | CT-L06-S-006-FB | L06 | South | Curtain wall | 1400 | 50 | Blue-grey concept glass | CT-101 | CT-L06-S-006
CT-L06-S-006-FT | L06 | CT-L06-S-006-FT | L06 | South | Curtain wall | 1400 | 50 | Blue-grey concept glass | CT-101 | CT-L06-S-006
CT-L06-S-007-ML | L06 | CT-L06-S-007-ML | L06 | South | Curtain wall | 50 | 3300 | Blue-grey concept glass | CT-101 | CT-L06-S-007
CT-L06-S-007-MR | L06 | CT-L06-S-007-MR | L06 | South | Curtain wall | 50 | 3300 | Blue-grey concept glass | CT-101 | CT-L06-S-007
CT-L06-S-007-FB | L06 | CT-L06-S-007-FB | L06 | South | Curtain wall | 1400 | 50 | Blue-grey concept glass | CT-101 | CT-L06-S-007
CT-L06-S-007-FT | L06 | CT-L06-S-007-FT | L06 | South | Curtain wall | 1400 | 50 | Blue-grey concept glass | CT-101 | CT-L06-S-007
CT-L06-S-008-ML | L06 | CT-L06-S-008-ML | L06 | South | Curtain wall | 50 | 3300 | Blue-grey concept glass | CT-101 | CT-L06-S-008
CT-L06-S-008-MR | L06 | CT-L06-S-008-MR | L06 | South | Curtain wall | 50 | 3300 | Blue-grey concept glass | CT-101 | CT-L06-S-008
CT-L06-S-008-FB | L06 | CT-L06-S-008-FB | L06 | South | Curtain wall | 1400 | 50 | Blue-grey concept glass | CT-101 | CT-L06-S-008
CT-L06-S-008-FT | L06 | CT-L06-S-008-FT | L06 | South | Curtain wall | 1400 | 50 | Blue-grey concept glass | CT-101 | CT-L06-S-008
CT-L06-S-009-ML | L06 | CT-L06-S-009-ML | L06 | South | Curtain wall | 50 | 3300 | Blue-grey concept glass | CT-101 | CT-L06-S-009
CT-L06-S-009-MR | L06 | CT-L06-S-009-MR | L06 | South | Curtain wall | 50 | 3300 | Blue-grey concept glass | CT-101 | CT-L06-S-009
CT-L06-S-009-FB | L06 | CT-L06-S-009-FB | L06 | South | Curtain wall | 1400 | 50 | Blue-grey concept glass | CT-101 | CT-L06-S-009
CT-L06-S-009-FT | L06 | CT-L06-S-009-FT | L06 | South | Curtain wall | 1400 | 50 | Blue-grey concept glass | CT-101 | CT-L06-S-009
CT-L06-S-010-ML | L06 | CT-L06-S-010-ML | L06 | South | Metal rainscreen | 50 | 3300 | Olive powder coat | CT-101 | CT-L06-S-010
CT-L06-S-010-MR | L06 | CT-L06-S-010-MR | L06 | South | Metal rainscreen | 50 | 3300 | Olive powder coat | CT-101 | CT-L06-S-010
CT-L06-S-010-FB | L06 | CT-L06-S-010-FB | L06 | South | Metal rainscreen | 1400 | 50 | Olive powder coat | CT-101 | CT-L06-S-010
CT-L06-S-010-FT | L06 | CT-L06-S-010-FT | L06 | South | Metal rainscreen | 1400 | 50 | Olive powder coat | CT-101 | CT-L06-S-010
CT-L06-S-011-ML | L06 | CT-L06-S-011-ML | L06 | South | Curtain wall | 50 | 3300 | Blue-grey concept glass | CT-101 | CT-L06-S-011
CT-L06-S-011-MR | L06 | CT-L06-S-011-MR | L06 | South | Curtain wall | 50 | 3300 | Blue-grey concept glass | CT-101 | CT-L06-S-011
CT-L06-S-011-FB | L06 | CT-L06-S-011-FB | L06 | South | Curtain wall | 1400 | 50 | Blue-grey concept glass | CT-101 | CT-L06-S-011
CT-L06-S-011-FT | L06 | CT-L06-S-011-FT | L06 | South | Curtain wall | 1400 | 50 | Blue-grey concept glass | CT-101 | CT-L06-S-011
CT-L06-S-012-ML | L06 | CT-L06-S-012-ML | L06 | South | Curtain wall | 50 | 3300 | Blue-grey concept glass | CT-101 | CT-L06-S-012
CT-L06-S-012-MR | L06 | CT-L06-S-012-MR | L06 | South | Curtain wall | 50 | 3300 | Blue-grey concept glass | CT-101 | CT-L06-S-012
CT-L06-S-012-FB | L06 | CT-L06-S-012-FB | L06 | South | Curtain wall | 1400 | 50 | Blue-grey concept glass | CT-101 | CT-L06-S-012
CT-L06-S-012-FT | L06 | CT-L06-S-012-FT | L06 | South | Curtain wall | 1400 | 50 | Blue-grey concept glass | CT-101 | CT-L06-S-012
CT-L06-S-013-ML | L06 | CT-L06-S-013-ML | L06 | South | Curtain wall | 50 | 3300 | Blue-grey concept glass | CT-101 | CT-L06-S-013
CT-L06-S-013-MR | L06 | CT-L06-S-013-MR | L06 | South | Curtain wall | 50 | 3300 | Blue-grey concept glass | CT-101 | CT-L06-S-013
CT-L06-S-013-FB | L06 | CT-L06-S-013-FB | L06 | South | Curtain wall | 1400 | 50 | Blue-grey concept glass | CT-101 | CT-L06-S-013
CT-L06-S-013-FT | L06 | CT-L06-S-013-FT | L06 | South | Curtain wall | 1400 | 50 | Blue-grey concept glass | CT-101 | CT-L06-S-013
CT-L06-S-014-ML | L06 | CT-L06-S-014-ML | L06 | South | Curtain wall | 50 | 3300 | Blue-grey concept glass | CT-101 | CT-L06-S-014
CT-L06-S-014-MR | L06 | CT-L06-S-014-MR | L06 | South | Curtain wall | 50 | 3300 | Blue-grey concept glass | CT-101 | CT-L06-S-014
CT-L06-S-014-FB | L06 | CT-L06-S-014-FB | L06 | South | Curtain wall | 1250 | 50 | Blue-grey concept glass | CT-101 | CT-L06-S-014
CT-L06-S-014-FT | L06 | CT-L06-S-014-FT | L06 | South | Curtain wall | 1250 | 50 | Blue-grey concept glass | CT-101 | CT-L06-S-014
CT-L06-E-001-ML | L06 | CT-L06-E-001-ML | L06 | East | Curtain wall | 50 | 3300 | Blue-grey concept glass | CT-102 | CT-L06-E-001
CT-L06-E-001-MR | L06 | CT-L06-E-001-MR | L06 | East | Curtain wall | 50 | 3300 | Blue-grey concept glass | CT-102 | CT-L06-E-001
CT-L06-E-001-FB | L06 | CT-L06-E-001-FB | L06 | East | Curtain wall | 1250 | 50 | Blue-grey concept glass | CT-102 | CT-L06-E-001
CT-L06-E-001-FT | L06 | CT-L06-E-001-FT | L06 | East | Curtain wall | 1250 | 50 | Blue-grey concept glass | CT-102 | CT-L06-E-001
CT-L06-E-002-ML | L06 | CT-L06-E-002-ML | L06 | East | Curtain wall | 50 | 3300 | Blue-grey concept glass | CT-102 | CT-L06-E-002
CT-L06-E-002-MR | L06 | CT-L06-E-002-MR | L06 | East | Curtain wall | 50 | 3300 | Blue-grey concept glass | CT-102 | CT-L06-E-002
CT-L06-E-002-FB | L06 | CT-L06-E-002-FB | L06 | East | Curtain wall | 1400 | 50 | Blue-grey concept glass | CT-102 | CT-L06-E-002
CT-L06-E-002-FT | L06 | CT-L06-E-002-FT | L06 | East | Curtain wall | 1400 | 50 | Blue-grey concept glass | CT-102 | CT-L06-E-002
CT-L06-E-003-ML | L06 | CT-L06-E-003-ML | L06 | East | Curtain wall | 50 | 3300 | Blue-grey concept glass | CT-102 | CT-L06-E-003
CT-L06-E-003-MR | L06 | CT-L06-E-003-MR | L06 | East | Curtain wall | 50 | 3300 | Blue-grey concept glass | CT-102 | CT-L06-E-003
CT-L06-E-003-FB | L06 | CT-L06-E-003-FB | L06 | East | Curtain wall | 1400 | 50 | Blue-grey concept glass | CT-102 | CT-L06-E-003
CT-L06-E-003-FT | L06 | CT-L06-E-003-FT | L06 | East | Curtain wall | 1400 | 50 | Blue-grey concept glass | CT-102 | CT-L06-E-003
CT-L06-E-004-ML | L06 | CT-L06-E-004-ML | L06 | East | Curtain wall | 50 | 3300 | Blue-grey concept glass | CT-102 | CT-L06-E-004
CT-L06-E-004-MR | L06 | CT-L06-E-004-MR | L06 | East | Curtain wall | 50 | 3300 | Blue-grey concept glass | CT-102 | CT-L06-E-004
CT-L06-E-004-FB | L06 | CT-L06-E-004-FB | L06 | East | Curtain wall | 1400 | 50 | Blue-grey concept glass | CT-102 | CT-L06-E-004
CT-L06-E-004-FT | L06 | CT-L06-E-004-FT | L06 | East | Curtain wall | 1400 | 50 | Blue-grey concept glass | CT-102 | CT-L06-E-004
CT-L06-E-005-ML | L06 | CT-L06-E-005-ML | L06 | East | Metal rainscreen | 50 | 3300 | Olive powder coat | CT-102 | CT-L06-E-005
CT-L06-E-005-MR | L06 | CT-L06-E-005-MR | L06 | East | Metal rainscreen | 50 | 3300 | Olive powder coat | CT-102 | CT-L06-E-005
CT-L06-E-005-FB | L06 | CT-L06-E-005-FB | L06 | East | Metal rainscreen | 1400 | 50 | Olive powder coat | CT-102 | CT-L06-E-005
CT-L06-E-005-FT | L06 | CT-L06-E-005-FT | L06 | East | Metal rainscreen | 1400 | 50 | Olive powder coat | CT-102 | CT-L06-E-005
CT-L06-E-006-ML | L06 | CT-L06-E-006-ML | L06 | East | Curtain wall | 50 | 3300 | Blue-grey concept glass | CT-102 | CT-L06-E-006
CT-L06-E-006-MR | L06 | CT-L06-E-006-MR | L06 | East | Curtain wall | 50 | 3300 | Blue-grey concept glass | CT-102 | CT-L06-E-006
CT-L06-E-006-FB | L06 | CT-L06-E-006-FB | L06 | East | Curtain wall | 1400 | 50 | Blue-grey concept glass | CT-102 | CT-L06-E-006
CT-L06-E-006-FT | L06 | CT-L06-E-006-FT | L06 | East | Curtain wall | 1400 | 50 | Blue-grey concept glass | CT-102 | CT-L06-E-006
CT-L06-E-007-ML | L06 | CT-L06-E-007-ML | L06 | East | Curtain wall | 50 | 3300 | Blue-grey concept glass | CT-102 | CT-L06-E-007
CT-L06-E-007-MR | L06 | CT-L06-E-007-MR | L06 | East | Curtain wall | 50 | 3300 | Blue-grey concept glass | CT-102 | CT-L06-E-007
CT-L06-E-007-FB | L06 | CT-L06-E-007-FB | L06 | East | Curtain wall | 1400 | 50 | Blue-grey concept glass | CT-102 | CT-L06-E-007
CT-L06-E-007-FT | L06 | CT-L06-E-007-FT | L06 | East | Curtain wall | 1400 | 50 | Blue-grey concept glass | CT-102 | CT-L06-E-007
CT-L06-E-008-ML | L06 | CT-L06-E-008-ML | L06 | East | Curtain wall | 50 | 3300 | Blue-grey concept glass | CT-102 | CT-L06-E-008
CT-L06-E-008-MR | L06 | CT-L06-E-008-MR | L06 | East | Curtain wall | 50 | 3300 | Blue-grey concept glass | CT-102 | CT-L06-E-008
CT-L06-E-008-FB | L06 | CT-L06-E-008-FB | L06 | East | Curtain wall | 1400 | 50 | Blue-grey concept glass | CT-102 | CT-L06-E-008
CT-L06-E-008-FT | L06 | CT-L06-E-008-FT | L06 | East | Curtain wall | 1400 | 50 | Blue-grey concept glass | CT-102 | CT-L06-E-008
CT-L06-E-009-ML | L06 | CT-L06-E-009-ML | L06 | East | Curtain wall | 50 | 3300 | Blue-grey concept glass | CT-102 | CT-L06-E-009
CT-L06-E-009-MR | L06 | CT-L06-E-009-MR | L06 | East | Curtain wall | 50 | 3300 | Blue-grey concept glass | CT-102 | CT-L06-E-009
CT-L06-E-009-FB | L06 | CT-L06-E-009-FB | L06 | East | Curtain wall | 1400 | 50 | Blue-grey concept glass | CT-102 | CT-L06-E-009
CT-L06-E-009-FT | L06 | CT-L06-E-009-FT | L06 | East | Curtain wall | 1400 | 50 | Blue-grey concept glass | CT-102 | CT-L06-E-009
CT-L06-E-010-ML | L06 | CT-L06-E-010-ML | L06 | East | Metal rainscreen | 50 | 3300 | Olive powder coat | CT-102 | CT-L06-E-010
CT-L06-E-010-MR | L06 | CT-L06-E-010-MR | L06 | East | Metal rainscreen | 50 | 3300 | Olive powder coat | CT-102 | CT-L06-E-010
CT-L06-E-010-FB | L06 | CT-L06-E-010-FB | L06 | East | Metal rainscreen | 1250 | 50 | Olive powder coat | CT-102 | CT-L06-E-010
CT-L06-E-010-FT | L06 | CT-L06-E-010-FT | L06 | East | Metal rainscreen | 1250 | 50 | Olive powder coat | CT-102 | CT-L06-E-010
CT-L06-N-001-ML | L06 | CT-L06-N-001-ML | L06 | North | Curtain wall | 50 | 3300 | Blue-grey concept glass | CT-103 | CT-L06-N-001
CT-L06-N-001-MR | L06 | CT-L06-N-001-MR | L06 | North | Curtain wall | 50 | 3300 | Blue-grey concept glass | CT-103 | CT-L06-N-001
CT-L06-N-001-FB | L06 | CT-L06-N-001-FB | L06 | North | Curtain wall | 1250 | 50 | Blue-grey concept glass | CT-103 | CT-L06-N-001
CT-L06-N-001-FT | L06 | CT-L06-N-001-FT | L06 | North | Curtain wall | 1250 | 50 | Blue-grey concept glass | CT-103 | CT-L06-N-001
CT-L06-N-002-ML | L06 | CT-L06-N-002-ML | L06 | North | Curtain wall | 50 | 3300 | Blue-grey concept glass | CT-103 | CT-L06-N-002
CT-L06-N-002-MR | L06 | CT-L06-N-002-MR | L06 | North | Curtain wall | 50 | 3300 | Blue-grey concept glass | CT-103 | CT-L06-N-002
CT-L06-N-002-FB | L06 | CT-L06-N-002-FB | L06 | North | Curtain wall | 1400 | 50 | Blue-grey concept glass | CT-103 | CT-L06-N-002
CT-L06-N-002-FT | L06 | CT-L06-N-002-FT | L06 | North | Curtain wall | 1400 | 50 | Blue-grey concept glass | CT-103 | CT-L06-N-002
CT-L06-N-003-ML | L06 | CT-L06-N-003-ML | L06 | North | Curtain wall | 50 | 3300 | Blue-grey concept glass | CT-103 | CT-L06-N-003
CT-L06-N-003-MR | L06 | CT-L06-N-003-MR | L06 | North | Curtain wall | 50 | 3300 | Blue-grey concept glass | CT-103 | CT-L06-N-003
CT-L06-N-003-FB | L06 | CT-L06-N-003-FB | L06 | North | Curtain wall | 1400 | 50 | Blue-grey concept glass | CT-103 | CT-L06-N-003
CT-L06-N-003-FT | L06 | CT-L06-N-003-FT | L06 | North | Curtain wall | 1400 | 50 | Blue-grey concept glass | CT-103 | CT-L06-N-003
CT-L06-N-004-ML | L06 | CT-L06-N-004-ML | L06 | North | Curtain wall | 50 | 3300 | Blue-grey concept glass | CT-103 | CT-L06-N-004
CT-L06-N-004-MR | L06 | CT-L06-N-004-MR | L06 | North | Curtain wall | 50 | 3300 | Blue-grey concept glass | CT-103 | CT-L06-N-004
CT-L06-N-004-FB | L06 | CT-L06-N-004-FB | L06 | North | Curtain wall | 1400 | 50 | Blue-grey concept glass | CT-103 | CT-L06-N-004
CT-L06-N-004-FT | L06 | CT-L06-N-004-FT | L06 | North | Curtain wall | 1400 | 50 | Blue-grey concept glass | CT-103 | CT-L06-N-004
CT-L06-N-005-ML | L06 | CT-L06-N-005-ML | L06 | North | Metal rainscreen | 50 | 3300 | Olive powder coat | CT-103 | CT-L06-N-005
CT-L06-N-005-MR | L06 | CT-L06-N-005-MR | L06 | North | Metal rainscreen | 50 | 3300 | Olive powder coat | CT-103 | CT-L06-N-005
CT-L06-N-005-FB | L06 | CT-L06-N-005-FB | L06 | North | Metal rainscreen | 1400 | 50 | Olive powder coat | CT-103 | CT-L06-N-005
CT-L06-N-005-FT | L06 | CT-L06-N-005-FT | L06 | North | Metal rainscreen | 1400 | 50 | Olive powder coat | CT-103 | CT-L06-N-005
CT-L06-N-006-ML | L06 | CT-L06-N-006-ML | L06 | North | Curtain wall | 50 | 3300 | Blue-grey concept glass | CT-103 | CT-L06-N-006
CT-L06-N-006-MR | L06 | CT-L06-N-006-MR | L06 | North | Curtain wall | 50 | 3300 | Blue-grey concept glass | CT-103 | CT-L06-N-006
CT-L06-N-006-FB | L06 | CT-L06-N-006-FB | L06 | North | Curtain wall | 1400 | 50 | Blue-grey concept glass | CT-103 | CT-L06-N-006
CT-L06-N-006-FT | L06 | CT-L06-N-006-FT | L06 | North | Curtain wall | 1400 | 50 | Blue-grey concept glass | CT-103 | CT-L06-N-006
CT-L06-N-007-ML | L06 | CT-L06-N-007-ML | L06 | North | Curtain wall | 50 | 3300 | Blue-grey concept glass | CT-103 | CT-L06-N-007
CT-L06-N-007-MR | L06 | CT-L06-N-007-MR | L06 | North | Curtain wall | 50 | 3300 | Blue-grey concept glass | CT-103 | CT-L06-N-007
CT-L06-N-007-FB | L06 | CT-L06-N-007-FB | L06 | North | Curtain wall | 1400 | 50 | Blue-grey concept glass | CT-103 | CT-L06-N-007
CT-L06-N-007-FT | L06 | CT-L06-N-007-FT | L06 | North | Curtain wall | 1400 | 50 | Blue-grey concept glass | CT-103 | CT-L06-N-007
CT-L06-N-008-ML | L06 | CT-L06-N-008-ML | L06 | North | Curtain wall | 50 | 3300 | Blue-grey concept glass | CT-103 | CT-L06-N-008
CT-L06-N-008-MR | L06 | CT-L06-N-008-MR | L06 | North | Curtain wall | 50 | 3300 | Blue-grey concept glass | CT-103 | CT-L06-N-008
CT-L06-N-008-FB | L06 | CT-L06-N-008-FB | L06 | North | Curtain wall | 1400 | 50 | Blue-grey concept glass | CT-103 | CT-L06-N-008
CT-L06-N-008-FT | L06 | CT-L06-N-008-FT | L06 | North | Curtain wall | 1400 | 50 | Blue-grey concept glass | CT-103 | CT-L06-N-008
CT-L06-N-009-ML | L06 | CT-L06-N-009-ML | L06 | North | Curtain wall | 50 | 3300 | Blue-grey concept glass | CT-103 | CT-L06-N-009
CT-L06-N-009-MR | L06 | CT-L06-N-009-MR | L06 | North | Curtain wall | 50 | 3300 | Blue-grey concept glass | CT-103 | CT-L06-N-009
CT-L06-N-009-FB | L06 | CT-L06-N-009-FB | L06 | North | Curtain wall | 1400 | 50 | Blue-grey concept glass | CT-103 | CT-L06-N-009
CT-L06-N-009-FT | L06 | CT-L06-N-009-FT | L06 | North | Curtain wall | 1400 | 50 | Blue-grey concept glass | CT-103 | CT-L06-N-009
CT-L06-N-010-ML | L06 | CT-L06-N-010-ML | L06 | North | Metal rainscreen | 50 | 3300 | Olive powder coat | CT-103 | CT-L06-N-010
CT-L06-N-010-MR | L06 | CT-L06-N-010-MR | L06 | North | Metal rainscreen | 50 | 3300 | Olive powder coat | CT-103 | CT-L06-N-010
CT-L06-N-010-FB | L06 | CT-L06-N-010-FB | L06 | North | Metal rainscreen | 1400 | 50 | Olive powder coat | CT-103 | CT-L06-N-010
CT-L06-N-010-FT | L06 | CT-L06-N-010-FT | L06 | North | Metal rainscreen | 1400 | 50 | Olive powder coat | CT-103 | CT-L06-N-010
CT-L06-N-011-ML | L06 | CT-L06-N-011-ML | L06 | North | Curtain wall | 50 | 3300 | Blue-grey concept glass | CT-103 | CT-L06-N-011
CT-L06-N-011-MR | L06 | CT-L06-N-011-MR | L06 | North | Curtain wall | 50 | 3300 | Blue-grey concept glass | CT-103 | CT-L06-N-011
CT-L06-N-011-FB | L06 | CT-L06-N-011-FB | L06 | North | Curtain wall | 1400 | 50 | Blue-grey concept glass | CT-103 | CT-L06-N-011
CT-L06-N-011-FT | L06 | CT-L06-N-011-FT | L06 | North | Curtain wall | 1400 | 50 | Blue-grey concept glass | CT-103 | CT-L06-N-011
CT-L06-N-012-ML | L06 | CT-L06-N-012-ML | L06 | North | Curtain wall | 50 | 3300 | Blue-grey concept glass | CT-103 | CT-L06-N-012
CT-L06-N-012-MR | L06 | CT-L06-N-012-MR | L06 | North | Curtain wall | 50 | 3300 | Blue-grey concept glass | CT-103 | CT-L06-N-012
CT-L06-N-012-FB | L06 | CT-L06-N-012-FB | L06 | North | Curtain wall | 1400 | 50 | Blue-grey concept glass | CT-103 | CT-L06-N-012
CT-L06-N-012-FT | L06 | CT-L06-N-012-FT | L06 | North | Curtain wall | 1400 | 50 | Blue-grey concept glass | CT-103 | CT-L06-N-012
CT-L06-N-013-ML | L06 | CT-L06-N-013-ML | L06 | North | Curtain wall | 50 | 3300 | Blue-grey concept glass | CT-103 | CT-L06-N-013
CT-L06-N-013-MR | L06 | CT-L06-N-013-MR | L06 | North | Curtain wall | 50 | 3300 | Blue-grey concept glass | CT-103 | CT-L06-N-013
CT-L06-N-013-FB | L06 | CT-L06-N-013-FB | L06 | North | Curtain wall | 1400 | 50 | Blue-grey concept glass | CT-103 | CT-L06-N-013
CT-L06-N-013-FT | L06 | CT-L06-N-013-FT | L06 | North | Curtain wall | 1400 | 50 | Blue-grey concept glass | CT-103 | CT-L06-N-013
CT-L06-N-014-ML | L06 | CT-L06-N-014-ML | L06 | North | Curtain wall | 50 | 3300 | Blue-grey concept glass | CT-103 | CT-L06-N-014
CT-L06-N-014-MR | L06 | CT-L06-N-014-MR | L06 | North | Curtain wall | 50 | 3300 | Blue-grey concept glass | CT-103 | CT-L06-N-014
CT-L06-N-014-FB | L06 | CT-L06-N-014-FB | L06 | North | Curtain wall | 1250 | 50 | Blue-grey concept glass | CT-103 | CT-L06-N-014
CT-L06-N-014-FT | L06 | CT-L06-N-014-FT | L06 | North | Curtain wall | 1250 | 50 | Blue-grey concept glass | CT-103 | CT-L06-N-014
CT-L06-W-001-ML | L06 | CT-L06-W-001-ML | L06 | West | Curtain wall | 50 | 3300 | Blue-grey concept glass | CT-104 | CT-L06-W-001
CT-L06-W-001-MR | L06 | CT-L06-W-001-MR | L06 | West | Curtain wall | 50 | 3300 | Blue-grey concept glass | CT-104 | CT-L06-W-001
CT-L06-W-001-FB | L06 | CT-L06-W-001-FB | L06 | West | Curtain wall | 1250 | 50 | Blue-grey concept glass | CT-104 | CT-L06-W-001
CT-L06-W-001-FT | L06 | CT-L06-W-001-FT | L06 | West | Curtain wall | 1250 | 50 | Blue-grey concept glass | CT-104 | CT-L06-W-001
CT-L06-W-002-ML | L06 | CT-L06-W-002-ML | L06 | West | Curtain wall | 50 | 3300 | Blue-grey concept glass | CT-104 | CT-L06-W-002
CT-L06-W-002-MR | L06 | CT-L06-W-002-MR | L06 | West | Curtain wall | 50 | 3300 | Blue-grey concept glass | CT-104 | CT-L06-W-002
CT-L06-W-002-FB | L06 | CT-L06-W-002-FB | L06 | West | Curtain wall | 1400 | 50 | Blue-grey concept glass | CT-104 | CT-L06-W-002
CT-L06-W-002-FT | L06 | CT-L06-W-002-FT | L06 | West | Curtain wall | 1400 | 50 | Blue-grey concept glass | CT-104 | CT-L06-W-002
CT-L06-W-003-ML | L06 | CT-L06-W-003-ML | L06 | West | Curtain wall | 50 | 3300 | Blue-grey concept glass | CT-104 | CT-L06-W-003
CT-L06-W-003-MR | L06 | CT-L06-W-003-MR | L06 | West | Curtain wall | 50 | 3300 | Blue-grey concept glass | CT-104 | CT-L06-W-003
CT-L06-W-003-FB | L06 | CT-L06-W-003-FB | L06 | West | Curtain wall | 1400 | 50 | Blue-grey concept glass | CT-104 | CT-L06-W-003
CT-L06-W-003-FT | L06 | CT-L06-W-003-FT | L06 | West | Curtain wall | 1400 | 50 | Blue-grey concept glass | CT-104 | CT-L06-W-003
CT-L06-W-004-ML | L06 | CT-L06-W-004-ML | L06 | West | Curtain wall | 50 | 3300 | Blue-grey concept glass | CT-104 | CT-L06-W-004
CT-L06-W-004-MR | L06 | CT-L06-W-004-MR | L06 | West | Curtain wall | 50 | 3300 | Blue-grey concept glass | CT-104 | CT-L06-W-004
CT-L06-W-004-FB | L06 | CT-L06-W-004-FB | L06 | West | Curtain wall | 1400 | 50 | Blue-grey concept glass | CT-104 | CT-L06-W-004
CT-L06-W-004-FT | L06 | CT-L06-W-004-FT | L06 | West | Curtain wall | 1400 | 50 | Blue-grey concept glass | CT-104 | CT-L06-W-004
CT-L06-W-005-ML | L06 | CT-L06-W-005-ML | L06 | West | Metal rainscreen | 50 | 3300 | Olive powder coat | CT-104 | CT-L06-W-005
CT-L06-W-005-MR | L06 | CT-L06-W-005-MR | L06 | West | Metal rainscreen | 50 | 3300 | Olive powder coat | CT-104 | CT-L06-W-005
CT-L06-W-005-FB | L06 | CT-L06-W-005-FB | L06 | West | Metal rainscreen | 1400 | 50 | Olive powder coat | CT-104 | CT-L06-W-005
CT-L06-W-005-FT | L06 | CT-L06-W-005-FT | L06 | West | Metal rainscreen | 1400 | 50 | Olive powder coat | CT-104 | CT-L06-W-005
CT-L06-W-006-ML | L06 | CT-L06-W-006-ML | L06 | West | Curtain wall | 50 | 3300 | Blue-grey concept glass | CT-104 | CT-L06-W-006
CT-L06-W-006-MR | L06 | CT-L06-W-006-MR | L06 | West | Curtain wall | 50 | 3300 | Blue-grey concept glass | CT-104 | CT-L06-W-006
CT-L06-W-006-FB | L06 | CT-L06-W-006-FB | L06 | West | Curtain wall | 1400 | 50 | Blue-grey concept glass | CT-104 | CT-L06-W-006
CT-L06-W-006-FT | L06 | CT-L06-W-006-FT | L06 | West | Curtain wall | 1400 | 50 | Blue-grey concept glass | CT-104 | CT-L06-W-006
CT-L06-W-007-ML | L06 | CT-L06-W-007-ML | L06 | West | Curtain wall | 50 | 3300 | Blue-grey concept glass | CT-104 | CT-L06-W-007
CT-L06-W-007-MR | L06 | CT-L06-W-007-MR | L06 | West | Curtain wall | 50 | 3300 | Blue-grey concept glass | CT-104 | CT-L06-W-007
CT-L06-W-007-FB | L06 | CT-L06-W-007-FB | L06 | West | Curtain wall | 1400 | 50 | Blue-grey concept glass | CT-104 | CT-L06-W-007
CT-L06-W-007-FT | L06 | CT-L06-W-007-FT | L06 | West | Curtain wall | 1400 | 50 | Blue-grey concept glass | CT-104 | CT-L06-W-007
CT-L06-W-008-ML | L06 | CT-L06-W-008-ML | L06 | West | Curtain wall | 50 | 3300 | Blue-grey concept glass | CT-104 | CT-L06-W-008
CT-L06-W-008-MR | L06 | CT-L06-W-008-MR | L06 | West | Curtain wall | 50 | 3300 | Blue-grey concept glass | CT-104 | CT-L06-W-008
CT-L06-W-008-FB | L06 | CT-L06-W-008-FB | L06 | West | Curtain wall | 1400 | 50 | Blue-grey concept glass | CT-104 | CT-L06-W-008
CT-L06-W-008-FT | L06 | CT-L06-W-008-FT | L06 | West | Curtain wall | 1400 | 50 | Blue-grey concept glass | CT-104 | CT-L06-W-008
CT-L06-W-009-ML | L06 | CT-L06-W-009-ML | L06 | West | Curtain wall | 50 | 3300 | Blue-grey concept glass | CT-104 | CT-L06-W-009
CT-L06-W-009-MR | L06 | CT-L06-W-009-MR | L06 | West | Curtain wall | 50 | 3300 | Blue-grey concept glass | CT-104 | CT-L06-W-009
CT-L06-W-009-FB | L06 | CT-L06-W-009-FB | L06 | West | Curtain wall | 1400 | 50 | Blue-grey concept glass | CT-104 | CT-L06-W-009
CT-L06-W-009-FT | L06 | CT-L06-W-009-FT | L06 | West | Curtain wall | 1400 | 50 | Blue-grey concept glass | CT-104 | CT-L06-W-009
CT-L06-W-010-ML | L06 | CT-L06-W-010-ML | L06 | West | Metal rainscreen | 50 | 3300 | Olive powder coat | CT-104 | CT-L06-W-010
CT-L06-W-010-MR | L06 | CT-L06-W-010-MR | L06 | West | Metal rainscreen | 50 | 3300 | Olive powder coat | CT-104 | CT-L06-W-010
CT-L06-W-010-FB | L06 | CT-L06-W-010-FB | L06 | West | Metal rainscreen | 1250 | 50 | Olive powder coat | CT-104 | CT-L06-W-010
CT-L06-W-010-FT | L06 | CT-L06-W-010-FT | L06 | West | Metal rainscreen | 1250 | 50 | Olive powder coat | CT-104 | CT-L06-W-010
CT-L07-S-001-ML | L07 | CT-L07-S-001-ML | L07 | South | Curtain wall | 50 | 3300 | Blue-grey concept glass | CT-101 | CT-L07-S-001
CT-L07-S-001-MR | L07 | CT-L07-S-001-MR | L07 | South | Curtain wall | 50 | 3300 | Blue-grey concept glass | CT-101 | CT-L07-S-001
CT-L07-S-001-FB | L07 | CT-L07-S-001-FB | L07 | South | Curtain wall | 1250 | 50 | Blue-grey concept glass | CT-101 | CT-L07-S-001
CT-L07-S-001-FT | L07 | CT-L07-S-001-FT | L07 | South | Curtain wall | 1250 | 50 | Blue-grey concept glass | CT-101 | CT-L07-S-001
CT-L07-S-002-ML | L07 | CT-L07-S-002-ML | L07 | South | Curtain wall | 50 | 3300 | Blue-grey concept glass | CT-101 | CT-L07-S-002
CT-L07-S-002-MR | L07 | CT-L07-S-002-MR | L07 | South | Curtain wall | 50 | 3300 | Blue-grey concept glass | CT-101 | CT-L07-S-002
CT-L07-S-002-FB | L07 | CT-L07-S-002-FB | L07 | South | Curtain wall | 1400 | 50 | Blue-grey concept glass | CT-101 | CT-L07-S-002
CT-L07-S-002-FT | L07 | CT-L07-S-002-FT | L07 | South | Curtain wall | 1400 | 50 | Blue-grey concept glass | CT-101 | CT-L07-S-002
CT-L07-S-003-ML | L07 | CT-L07-S-003-ML | L07 | South | Curtain wall | 50 | 3300 | Blue-grey concept glass | CT-101 | CT-L07-S-003
CT-L07-S-003-MR | L07 | CT-L07-S-003-MR | L07 | South | Curtain wall | 50 | 3300 | Blue-grey concept glass | CT-101 | CT-L07-S-003
CT-L07-S-003-FB | L07 | CT-L07-S-003-FB | L07 | South | Curtain wall | 1400 | 50 | Blue-grey concept glass | CT-101 | CT-L07-S-003
CT-L07-S-003-FT | L07 | CT-L07-S-003-FT | L07 | South | Curtain wall | 1400 | 50 | Blue-grey concept glass | CT-101 | CT-L07-S-003
CT-L07-S-004-ML | L07 | CT-L07-S-004-ML | L07 | South | Curtain wall | 50 | 3300 | Blue-grey concept glass | CT-101 | CT-L07-S-004
CT-L07-S-004-MR | L07 | CT-L07-S-004-MR | L07 | South | Curtain wall | 50 | 3300 | Blue-grey concept glass | CT-101 | CT-L07-S-004
CT-L07-S-004-FB | L07 | CT-L07-S-004-FB | L07 | South | Curtain wall | 1400 | 50 | Blue-grey concept glass | CT-101 | CT-L07-S-004
CT-L07-S-004-FT | L07 | CT-L07-S-004-FT | L07 | South | Curtain wall | 1400 | 50 | Blue-grey concept glass | CT-101 | CT-L07-S-004
CT-L07-S-005-ML | L07 | CT-L07-S-005-ML | L07 | South | Metal rainscreen | 50 | 3300 | Olive powder coat | CT-101 | CT-L07-S-005
CT-L07-S-005-MR | L07 | CT-L07-S-005-MR | L07 | South | Metal rainscreen | 50 | 3300 | Olive powder coat | CT-101 | CT-L07-S-005
CT-L07-S-005-FB | L07 | CT-L07-S-005-FB | L07 | South | Metal rainscreen | 1400 | 50 | Olive powder coat | CT-101 | CT-L07-S-005
CT-L07-S-005-FT | L07 | CT-L07-S-005-FT | L07 | South | Metal rainscreen | 1400 | 50 | Olive powder coat | CT-101 | CT-L07-S-005
CT-L07-S-006-ML | L07 | CT-L07-S-006-ML | L07 | South | Curtain wall | 50 | 3300 | Blue-grey concept glass | CT-101 | CT-L07-S-006
CT-L07-S-006-MR | L07 | CT-L07-S-006-MR | L07 | South | Curtain wall | 50 | 3300 | Blue-grey concept glass | CT-101 | CT-L07-S-006
CT-L07-S-006-FB | L07 | CT-L07-S-006-FB | L07 | South | Curtain wall | 1400 | 50 | Blue-grey concept glass | CT-101 | CT-L07-S-006
CT-L07-S-006-FT | L07 | CT-L07-S-006-FT | L07 | South | Curtain wall | 1400 | 50 | Blue-grey concept glass | CT-101 | CT-L07-S-006
CT-L07-S-007-ML | L07 | CT-L07-S-007-ML | L07 | South | Curtain wall | 50 | 3300 | Blue-grey concept glass | CT-101 | CT-L07-S-007
CT-L07-S-007-MR | L07 | CT-L07-S-007-MR | L07 | South | Curtain wall | 50 | 3300 | Blue-grey concept glass | CT-101 | CT-L07-S-007
CT-L07-S-007-FB | L07 | CT-L07-S-007-FB | L07 | South | Curtain wall | 1400 | 50 | Blue-grey concept glass | CT-101 | CT-L07-S-007
CT-L07-S-007-FT | L07 | CT-L07-S-007-FT | L07 | South | Curtain wall | 1400 | 50 | Blue-grey concept glass | CT-101 | CT-L07-S-007
CT-L07-S-008-ML | L07 | CT-L07-S-008-ML | L07 | South | Curtain wall | 50 | 3300 | Blue-grey concept glass | CT-101 | CT-L07-S-008
CT-L07-S-008-MR | L07 | CT-L07-S-008-MR | L07 | South | Curtain wall | 50 | 3300 | Blue-grey concept glass | CT-101 | CT-L07-S-008
CT-L07-S-008-FB | L07 | CT-L07-S-008-FB | L07 | South | Curtain wall | 1400 | 50 | Blue-grey concept glass | CT-101 | CT-L07-S-008
CT-L07-S-008-FT | L07 | CT-L07-S-008-FT | L07 | South | Curtain wall | 1400 | 50 | Blue-grey concept glass | CT-101 | CT-L07-S-008
CT-L07-S-009-ML | L07 | CT-L07-S-009-ML | L07 | South | Curtain wall | 50 | 3300 | Blue-grey concept glass | CT-101 | CT-L07-S-009
CT-L07-S-009-MR | L07 | CT-L07-S-009-MR | L07 | South | Curtain wall | 50 | 3300 | Blue-grey concept glass | CT-101 | CT-L07-S-009
CT-L07-S-009-FB | L07 | CT-L07-S-009-FB | L07 | South | Curtain wall | 1400 | 50 | Blue-grey concept glass | CT-101 | CT-L07-S-009
CT-L07-S-009-FT | L07 | CT-L07-S-009-FT | L07 | South | Curtain wall | 1400 | 50 | Blue-grey concept glass | CT-101 | CT-L07-S-009
CT-L07-S-010-ML | L07 | CT-L07-S-010-ML | L07 | South | Metal rainscreen | 50 | 3300 | Olive powder coat | CT-101 | CT-L07-S-010
CT-L07-S-010-MR | L07 | CT-L07-S-010-MR | L07 | South | Metal rainscreen | 50 | 3300 | Olive powder coat | CT-101 | CT-L07-S-010
CT-L07-S-010-FB | L07 | CT-L07-S-010-FB | L07 | South | Metal rainscreen | 1400 | 50 | Olive powder coat | CT-101 | CT-L07-S-010
CT-L07-S-010-FT | L07 | CT-L07-S-010-FT | L07 | South | Metal rainscreen | 1400 | 50 | Olive powder coat | CT-101 | CT-L07-S-010
CT-L07-S-011-ML | L07 | CT-L07-S-011-ML | L07 | South | Curtain wall | 50 | 3300 | Blue-grey concept glass | CT-101 | CT-L07-S-011
CT-L07-S-011-MR | L07 | CT-L07-S-011-MR | L07 | South | Curtain wall | 50 | 3300 | Blue-grey concept glass | CT-101 | CT-L07-S-011
CT-L07-S-011-FB | L07 | CT-L07-S-011-FB | L07 | South | Curtain wall | 1400 | 50 | Blue-grey concept glass | CT-101 | CT-L07-S-011
CT-L07-S-011-FT | L07 | CT-L07-S-011-FT | L07 | South | Curtain wall | 1400 | 50 | Blue-grey concept glass | CT-101 | CT-L07-S-011
CT-L07-S-012-ML | L07 | CT-L07-S-012-ML | L07 | South | Curtain wall | 50 | 3300 | Blue-grey concept glass | CT-101 | CT-L07-S-012
CT-L07-S-012-MR | L07 | CT-L07-S-012-MR | L07 | South | Curtain wall | 50 | 3300 | Blue-grey concept glass | CT-101 | CT-L07-S-012
CT-L07-S-012-FB | L07 | CT-L07-S-012-FB | L07 | South | Curtain wall | 1400 | 50 | Blue-grey concept glass | CT-101 | CT-L07-S-012
CT-L07-S-012-FT | L07 | CT-L07-S-012-FT | L07 | South | Curtain wall | 1400 | 50 | Blue-grey concept glass | CT-101 | CT-L07-S-012
CT-L07-S-013-ML | L07 | CT-L07-S-013-ML | L07 | South | Curtain wall | 50 | 3300 | Blue-grey concept glass | CT-101 | CT-L07-S-013
CT-L07-S-013-MR | L07 | CT-L07-S-013-MR | L07 | South | Curtain wall | 50 | 3300 | Blue-grey concept glass | CT-101 | CT-L07-S-013
CT-L07-S-013-FB | L07 | CT-L07-S-013-FB | L07 | South | Curtain wall | 1400 | 50 | Blue-grey concept glass | CT-101 | CT-L07-S-013
CT-L07-S-013-FT | L07 | CT-L07-S-013-FT | L07 | South | Curtain wall | 1400 | 50 | Blue-grey concept glass | CT-101 | CT-L07-S-013
CT-L07-S-014-ML | L07 | CT-L07-S-014-ML | L07 | South | Curtain wall | 50 | 3300 | Blue-grey concept glass | CT-101 | CT-L07-S-014
CT-L07-S-014-MR | L07 | CT-L07-S-014-MR | L07 | South | Curtain wall | 50 | 3300 | Blue-grey concept glass | CT-101 | CT-L07-S-014
CT-L07-S-014-FB | L07 | CT-L07-S-014-FB | L07 | South | Curtain wall | 1250 | 50 | Blue-grey concept glass | CT-101 | CT-L07-S-014
CT-L07-S-014-FT | L07 | CT-L07-S-014-FT | L07 | South | Curtain wall | 1250 | 50 | Blue-grey concept glass | CT-101 | CT-L07-S-014
CT-L07-E-001-ML | L07 | CT-L07-E-001-ML | L07 | East | Curtain wall | 50 | 3300 | Blue-grey concept glass | CT-102 | CT-L07-E-001
CT-L07-E-001-MR | L07 | CT-L07-E-001-MR | L07 | East | Curtain wall | 50 | 3300 | Blue-grey concept glass | CT-102 | CT-L07-E-001
CT-L07-E-001-FB | L07 | CT-L07-E-001-FB | L07 | East | Curtain wall | 1250 | 50 | Blue-grey concept glass | CT-102 | CT-L07-E-001
CT-L07-E-001-FT | L07 | CT-L07-E-001-FT | L07 | East | Curtain wall | 1250 | 50 | Blue-grey concept glass | CT-102 | CT-L07-E-001
CT-L07-E-002-ML | L07 | CT-L07-E-002-ML | L07 | East | Curtain wall | 50 | 3300 | Blue-grey concept glass | CT-102 | CT-L07-E-002
CT-L07-E-002-MR | L07 | CT-L07-E-002-MR | L07 | East | Curtain wall | 50 | 3300 | Blue-grey concept glass | CT-102 | CT-L07-E-002
CT-L07-E-002-FB | L07 | CT-L07-E-002-FB | L07 | East | Curtain wall | 1400 | 50 | Blue-grey concept glass | CT-102 | CT-L07-E-002
CT-L07-E-002-FT | L07 | CT-L07-E-002-FT | L07 | East | Curtain wall | 1400 | 50 | Blue-grey concept glass | CT-102 | CT-L07-E-002
CT-L07-E-003-ML | L07 | CT-L07-E-003-ML | L07 | East | Curtain wall | 50 | 3300 | Blue-grey concept glass | CT-102 | CT-L07-E-003
CT-L07-E-003-MR | L07 | CT-L07-E-003-MR | L07 | East | Curtain wall | 50 | 3300 | Blue-grey concept glass | CT-102 | CT-L07-E-003
CT-L07-E-003-FB | L07 | CT-L07-E-003-FB | L07 | East | Curtain wall | 1400 | 50 | Blue-grey concept glass | CT-102 | CT-L07-E-003
CT-L07-E-003-FT | L07 | CT-L07-E-003-FT | L07 | East | Curtain wall | 1400 | 50 | Blue-grey concept glass | CT-102 | CT-L07-E-003
CT-L07-E-004-ML | L07 | CT-L07-E-004-ML | L07 | East | Curtain wall | 50 | 3300 | Blue-grey concept glass | CT-102 | CT-L07-E-004
CT-L07-E-004-MR | L07 | CT-L07-E-004-MR | L07 | East | Curtain wall | 50 | 3300 | Blue-grey concept glass | CT-102 | CT-L07-E-004
CT-L07-E-004-FB | L07 | CT-L07-E-004-FB | L07 | East | Curtain wall | 1400 | 50 | Blue-grey concept glass | CT-102 | CT-L07-E-004
CT-L07-E-004-FT | L07 | CT-L07-E-004-FT | L07 | East | Curtain wall | 1400 | 50 | Blue-grey concept glass | CT-102 | CT-L07-E-004
CT-L07-E-005-ML | L07 | CT-L07-E-005-ML | L07 | East | Metal rainscreen | 50 | 3300 | Olive powder coat | CT-102 | CT-L07-E-005
CT-L07-E-005-MR | L07 | CT-L07-E-005-MR | L07 | East | Metal rainscreen | 50 | 3300 | Olive powder coat | CT-102 | CT-L07-E-005
CT-L07-E-005-FB | L07 | CT-L07-E-005-FB | L07 | East | Metal rainscreen | 1400 | 50 | Olive powder coat | CT-102 | CT-L07-E-005
CT-L07-E-005-FT | L07 | CT-L07-E-005-FT | L07 | East | Metal rainscreen | 1400 | 50 | Olive powder coat | CT-102 | CT-L07-E-005
CT-L07-E-006-ML | L07 | CT-L07-E-006-ML | L07 | East | Curtain wall | 50 | 3300 | Blue-grey concept glass | CT-102 | CT-L07-E-006
CT-L07-E-006-MR | L07 | CT-L07-E-006-MR | L07 | East | Curtain wall | 50 | 3300 | Blue-grey concept glass | CT-102 | CT-L07-E-006
CT-L07-E-006-FB | L07 | CT-L07-E-006-FB | L07 | East | Curtain wall | 1400 | 50 | Blue-grey concept glass | CT-102 | CT-L07-E-006
CT-L07-E-006-FT | L07 | CT-L07-E-006-FT | L07 | East | Curtain wall | 1400 | 50 | Blue-grey concept glass | CT-102 | CT-L07-E-006
CT-L07-E-007-ML | L07 | CT-L07-E-007-ML | L07 | East | Curtain wall | 50 | 3300 | Blue-grey concept glass | CT-102 | CT-L07-E-007
CT-L07-E-007-MR | L07 | CT-L07-E-007-MR | L07 | East | Curtain wall | 50 | 3300 | Blue-grey concept glass | CT-102 | CT-L07-E-007
CT-L07-E-007-FB | L07 | CT-L07-E-007-FB | L07 | East | Curtain wall | 1400 | 50 | Blue-grey concept glass | CT-102 | CT-L07-E-007
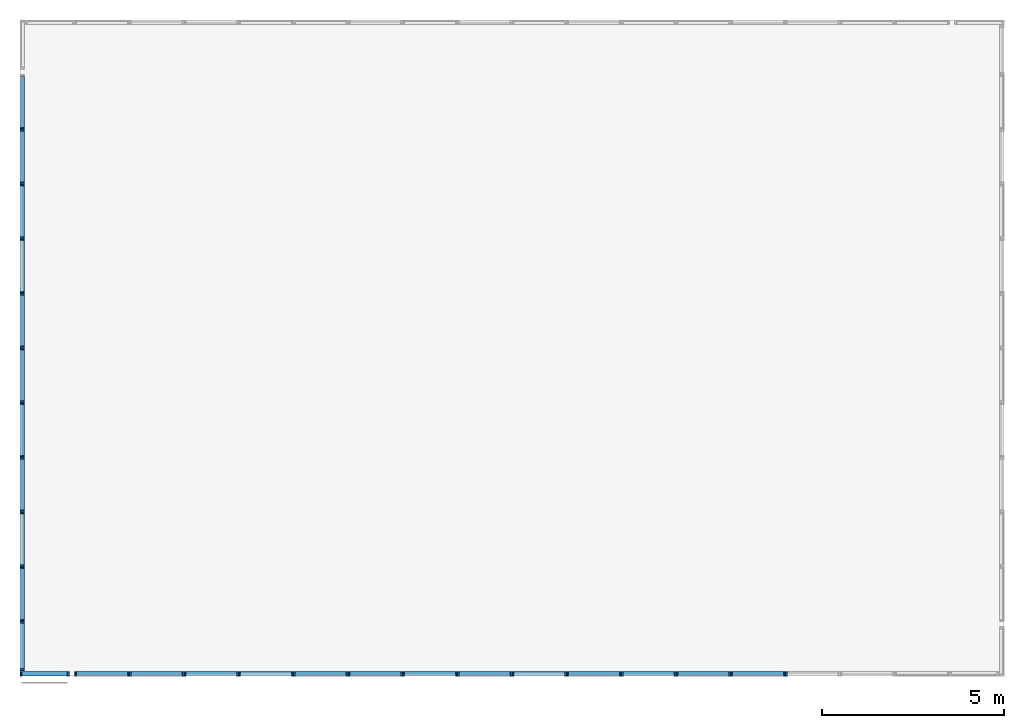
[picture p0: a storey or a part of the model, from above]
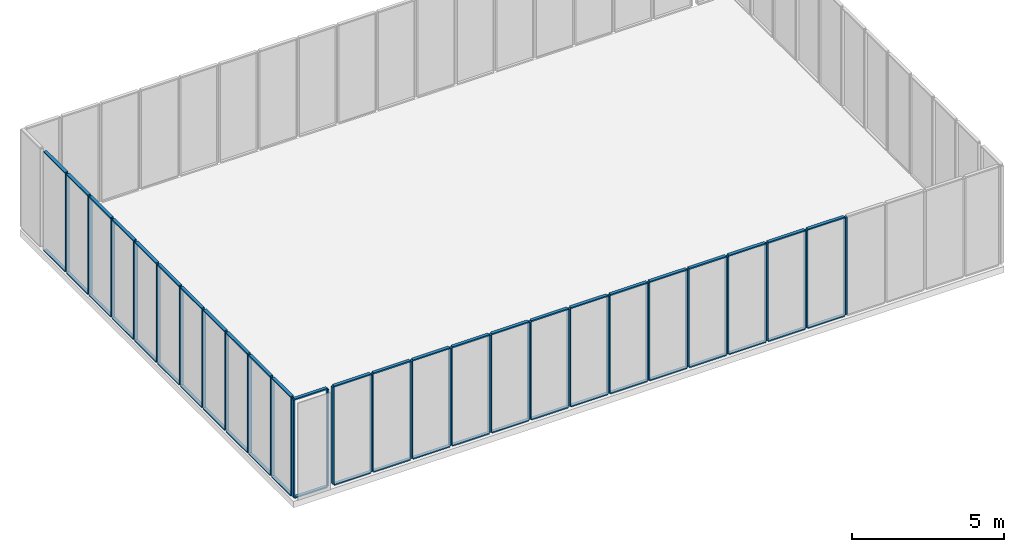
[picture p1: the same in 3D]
Properties of the parts of a building model (IFC4), part 4 of 7

# IfcMember (2304)
Name | In | ElementID | Floor | Elevation | System = Group | Width_mm | Height_mm | Finish | DrawingRef | ParentPanelID
CT-L07-E-007-FT | L07 | CT-L07-E-007-FT | L07 | East | Curtain wall | 1400 | 50 | Blue-grey concept glass | CT-102 | CT-L07-E-007
CT-L07-E-008-ML | L07 | CT-L07-E-008-ML | L07 | East | Curtain wall | 50 | 3300 | Blue-grey concept glass | CT-102 | CT-L07-E-008
CT-L07-E-008-MR | L07 | CT-L07-E-008-MR | L07 | East | Curtain wall | 50 | 3300 | Blue-grey concept glass | CT-102 | CT-L07-E-008
CT-L07-E-008-FB | L07 | CT-L07-E-008-FB | L07 | East | Curtain wall | 1400 | 50 | Blue-grey concept glass | CT-102 | CT-L07-E-008
CT-L07-E-008-FT | L07 | CT-L07-E-008-FT | L07 | East | Curtain wall | 1400 | 50 | Blue-grey concept glass | CT-102 | CT-L07-E-008
CT-L07-E-009-ML | L07 | CT-L07-E-009-ML | L07 | East | Curtain wall | 50 | 3300 | Blue-grey concept glass | CT-102 | CT-L07-E-009
CT-L07-E-009-MR | L07 | CT-L07-E-009-MR | L07 | East | Curtain wall | 50 | 3300 | Blue-grey concept glass | CT-102 | CT-L07-E-009
CT-L07-E-009-FB | L07 | CT-L07-E-009-FB | L07 | East | Curtain wall | 1400 | 50 | Blue-grey concept glass | CT-102 | CT-L07-E-009
CT-L07-E-009-FT | L07 | CT-L07-E-009-FT | L07 | East | Curtain wall | 1400 | 50 | Blue-grey concept glass | CT-102 | CT-L07-E-009
CT-L07-E-010-ML | L07 | CT-L07-E-010-ML | L07 | East | Metal rainscreen | 50 | 3300 | Olive powder coat | CT-102 | CT-L07-E-010
CT-L07-E-010-MR | L07 | CT-L07-E-010-MR | L07 | East | Metal rainscreen | 50 | 3300 | Olive powder coat | CT-102 | CT-L07-E-010
CT-L07-E-010-FB | L07 | CT-L07-E-010-FB | L07 | East | Metal rainscreen | 1250 | 50 | Olive powder coat | CT-102 | CT-L07-E-010
CT-L07-E-010-FT | L07 | CT-L07-E-010-FT | L07 | East | Metal rainscreen | 1250 | 50 | Olive powder coat | CT-102 | CT-L07-E-010
CT-L07-N-001-ML | L07 | CT-L07-N-001-ML | L07 | North | Curtain wall | 50 | 3300 | Blue-grey concept glass | CT-103 | CT-L07-N-001
CT-L07-N-001-MR | L07 | CT-L07-N-001-MR | L07 | North | Curtain wall | 50 | 3300 | Blue-grey concept glass | CT-103 | CT-L07-N-001
CT-L07-N-001-FB | L07 | CT-L07-N-001-FB | L07 | North | Curtain wall | 1250 | 50 | Blue-grey concept glass | CT-103 | CT-L07-N-001
CT-L07-N-001-FT | L07 | CT-L07-N-001-FT | L07 | North | Curtain wall | 1250 | 50 | Blue-grey concept glass | CT-103 | CT-L07-N-001
CT-L07-N-002-ML | L07 | CT-L07-N-002-ML | L07 | North | Curtain wall | 50 | 3300 | Blue-grey concept glass | CT-103 | CT-L07-N-002
CT-L07-N-002-MR | L07 | CT-L07-N-002-MR | L07 | North | Curtain wall | 50 | 3300 | Blue-grey concept glass | CT-103 | CT-L07-N-002
CT-L07-N-002-FB | L07 | CT-L07-N-002-FB | L07 | North | Curtain wall | 1400 | 50 | Blue-grey concept glass | CT-103 | CT-L07-N-002
CT-L07-N-002-FT | L07 | CT-L07-N-002-FT | L07 | North | Curtain wall | 1400 | 50 | Blue-grey concept glass | CT-103 | CT-L07-N-002
CT-L07-N-003-ML | L07 | CT-L07-N-003-ML | L07 | North | Curtain wall | 50 | 3300 | Blue-grey concept glass | CT-103 | CT-L07-N-003
CT-L07-N-003-MR | L07 | CT-L07-N-003-MR | L07 | North | Curtain wall | 50 | 3300 | Blue-grey concept glass | CT-103 | CT-L07-N-003
CT-L07-N-003-FB | L07 | CT-L07-N-003-FB | L07 | North | Curtain wall | 1400 | 50 | Blue-grey concept glass | CT-103 | CT-L07-N-003
CT-L07-N-003-FT | L07 | CT-L07-N-003-FT | L07 | North | Curtain wall | 1400 | 50 | Blue-grey concept glass | CT-103 | CT-L07-N-003
CT-L07-N-004-ML | L07 | CT-L07-N-004-ML | L07 | North | Curtain wall | 50 | 3300 | Blue-grey concept glass | CT-103 | CT-L07-N-004
CT-L07-N-004-MR | L07 | CT-L07-N-004-MR | L07 | North | Curtain wall | 50 | 3300 | Blue-grey concept glass | CT-103 | CT-L07-N-004
CT-L07-N-004-FB | L07 | CT-L07-N-004-FB | L07 | North | Curtain wall | 1400 | 50 | Blue-grey concept glass | CT-103 | CT-L07-N-004
CT-L07-N-004-FT | L07 | CT-L07-N-004-FT | L07 | North | Curtain wall | 1400 | 50 | Blue-grey concept glass | CT-103 | CT-L07-N-004
CT-L07-N-005-ML | L07 | CT-L07-N-005-ML | L07 | North | Metal rainscreen | 50 | 3300 | Olive powder coat | CT-103 | CT-L07-N-005
CT-L07-N-005-MR | L07 | CT-L07-N-005-MR | L07 | North | Metal rainscreen | 50 | 3300 | Olive powder coat | CT-103 | CT-L07-N-005
CT-L07-N-005-FB | L07 | CT-L07-N-005-FB | L07 | North | Metal rainscreen | 1400 | 50 | Olive powder coat | CT-103 | CT-L07-N-005
CT-L07-N-005-FT | L07 | CT-L07-N-005-FT | L07 | North | Metal rainscreen | 1400 | 50 | Olive powder coat | CT-103 | CT-L07-N-005
CT-L07-N-006-ML | L07 | CT-L07-N-006-ML | L07 | North | Curtain wall | 50 | 3300 | Blue-grey concept glass | CT-103 | CT-L07-N-006
CT-L07-N-006-MR | L07 | CT-L07-N-006-MR | L07 | North | Curtain wall | 50 | 3300 | Blue-grey concept glass | CT-103 | CT-L07-N-006
CT-L07-N-006-FB | L07 | CT-L07-N-006-FB | L07 | North | Curtain wall | 1400 | 50 | Blue-grey concept glass | CT-103 | CT-L07-N-006
CT-L07-N-006-FT | L07 | CT-L07-N-006-FT | L07 | North | Curtain wall | 1400 | 50 | Blue-grey concept glass | CT-103 | CT-L07-N-006
CT-L07-N-007-ML | L07 | CT-L07-N-007-ML | L07 | North | Curtain wall | 50 | 3300 | Blue-grey concept glass | CT-103 | CT-L07-N-007
CT-L07-N-007-MR | L07 | CT-L07-N-007-MR | L07 | North | Curtain wall | 50 | 3300 | Blue-grey concept glass | CT-103 | CT-L07-N-007
CT-L07-N-007-FB | L07 | CT-L07-N-007-FB | L07 | North | Curtain wall | 1400 | 50 | Blue-grey concept glass | CT-103 | CT-L07-N-007
CT-L07-N-007-FT | L07 | CT-L07-N-007-FT | L07 | North | Curtain wall | 1400 | 50 | Blue-grey concept glass | CT-103 | CT-L07-N-007
CT-L07-N-008-ML | L07 | CT-L07-N-008-ML | L07 | North | Curtain wall | 50 | 3300 | Blue-grey concept glass | CT-103 | CT-L07-N-008
CT-L07-N-008-MR | L07 | CT-L07-N-008-MR | L07 | North | Curtain wall | 50 | 3300 | Blue-grey concept glass | CT-103 | CT-L07-N-008
CT-L07-N-008-FB | L07 | CT-L07-N-008-FB | L07 | North | Curtain wall | 1400 | 50 | Blue-grey concept glass | CT-103 | CT-L07-N-008
CT-L07-N-008-FT | L07 | CT-L07-N-008-FT | L07 | North | Curtain wall | 1400 | 50 | Blue-grey concept glass | CT-103 | CT-L07-N-008
CT-L07-N-009-ML | L07 | CT-L07-N-009-ML | L07 | North | Curtain wall | 50 | 3300 | Blue-grey concept glass | CT-103 | CT-L07-N-009
CT-L07-N-009-MR | L07 | CT-L07-N-009-MR | L07 | North | Curtain wall | 50 | 3300 | Blue-grey concept glass | CT-103 | CT-L07-N-009
CT-L07-N-009-FB | L07 | CT-L07-N-009-FB | L07 | North | Curtain wall | 1400 | 50 | Blue-grey concept glass | CT-103 | CT-L07-N-009
CT-L07-N-009-FT | L07 | CT-L07-N-009-FT | L07 | North | Curtain wall | 1400 | 50 | Blue-grey concept glass | CT-103 | CT-L07-N-009
CT-L07-N-010-ML | L07 | CT-L07-N-010-ML | L07 | North | Metal rainscreen | 50 | 3300 | Olive powder coat | CT-103 | CT-L07-N-010
CT-L07-N-010-MR | L07 | CT-L07-N-010-MR | L07 | North | Metal rainscreen | 50 | 3300 | Olive powder coat | CT-103 | CT-L07-N-010
CT-L07-N-010-FB | L07 | CT-L07-N-010-FB | L07 | North | Metal rainscreen | 1400 | 50 | Olive powder coat | CT-103 | CT-L07-N-010
CT-L07-N-010-FT | L07 | CT-L07-N-010-FT | L07 | North | Metal rainscreen | 1400 | 50 | Olive powder coat | CT-103 | CT-L07-N-010
CT-L07-N-011-ML | L07 | CT-L07-N-011-ML | L07 | North | Curtain wall | 50 | 3300 | Blue-grey concept glass | CT-103 | CT-L07-N-011
CT-L07-N-011-MR | L07 | CT-L07-N-011-MR | L07 | North | Curtain wall | 50 | 3300 | Blue-grey concept glass | CT-103 | CT-L07-N-011
CT-L07-N-011-FB | L07 | CT-L07-N-011-FB | L07 | North | Curtain wall | 1400 | 50 | Blue-grey concept glass | CT-103 | CT-L07-N-011
CT-L07-N-011-FT | L07 | CT-L07-N-011-FT | L07 | North | Curtain wall | 1400 | 50 | Blue-grey concept glass | CT-103 | CT-L07-N-011
CT-L07-N-012-ML | L07 | CT-L07-N-012-ML | L07 | North | Curtain wall | 50 | 3300 | Blue-grey concept glass | CT-103 | CT-L07-N-012
CT-L07-N-012-MR | L07 | CT-L07-N-012-MR | L07 | North | Curtain wall | 50 | 3300 | Blue-grey concept glass | CT-103 | CT-L07-N-012
CT-L07-N-012-FB | L07 | CT-L07-N-012-FB | L07 | North | Curtain wall | 1400 | 50 | Blue-grey concept glass | CT-103 | CT-L07-N-012
CT-L07-N-012-FT | L07 | CT-L07-N-012-FT | L07 | North | Curtain wall | 1400 | 50 | Blue-grey concept glass | CT-103 | CT-L07-N-012
CT-L07-N-013-ML | L07 | CT-L07-N-013-ML | L07 | North | Curtain wall | 50 | 3300 | Blue-grey concept glass | CT-103 | CT-L07-N-013
CT-L07-N-013-MR | L07 | CT-L07-N-013-MR | L07 | North | Curtain wall | 50 | 3300 | Blue-grey concept glass | CT-103 | CT-L07-N-013
CT-L07-N-013-FB | L07 | CT-L07-N-013-FB | L07 | North | Curtain wall | 1400 | 50 | Blue-grey concept glass | CT-103 | CT-L07-N-013
CT-L07-N-013-FT | L07 | CT-L07-N-013-FT | L07 | North | Curtain wall | 1400 | 50 | Blue-grey concept glass | CT-103 | CT-L07-N-013
CT-L07-N-014-ML | L07 | CT-L07-N-014-ML | L07 | North | Curtain wall | 50 | 3300 | Blue-grey concept glass | CT-103 | CT-L07-N-014
CT-L07-N-014-MR | L07 | CT-L07-N-014-MR | L07 | North | Curtain wall | 50 | 3300 | Blue-grey concept glass | CT-103 | CT-L07-N-014
CT-L07-N-014-FB | L07 | CT-L07-N-014-FB | L07 | North | Curtain wall | 1250 | 50 | Blue-grey concept glass | CT-103 | CT-L07-N-014
CT-L07-N-014-FT | L07 | CT-L07-N-014-FT | L07 | North | Curtain wall | 1250 | 50 | Blue-grey concept glass | CT-103 | CT-L07-N-014
CT-L07-W-001-ML | L07 | CT-L07-W-001-ML | L07 | West | Curtain wall | 50 | 3300 | Blue-grey concept glass | CT-104 | CT-L07-W-001
CT-L07-W-001-MR | L07 | CT-L07-W-001-MR | L07 | West | Curtain wall | 50 | 3300 | Blue-grey concept glass | CT-104 | CT-L07-W-001
CT-L07-W-001-FB | L07 | CT-L07-W-001-FB | L07 | West | Curtain wall | 1250 | 50 | Blue-grey concept glass | CT-104 | CT-L07-W-001
CT-L07-W-001-FT | L07 | CT-L07-W-001-FT | L07 | West | Curtain wall | 1250 | 50 | Blue-grey concept glass | CT-104 | CT-L07-W-001
CT-L07-W-002-ML | L07 | CT-L07-W-002-ML | L07 | West | Curtain wall | 50 | 3300 | Blue-grey concept glass | CT-104 | CT-L07-W-002
CT-L07-W-002-MR | L07 | CT-L07-W-002-MR | L07 | West | Curtain wall | 50 | 3300 | Blue-grey concept glass | CT-104 | CT-L07-W-002
CT-L07-W-002-FB | L07 | CT-L07-W-002-FB | L07 | West | Curtain wall | 1400 | 50 | Blue-grey concept glass | CT-104 | CT-L07-W-002
CT-L07-W-002-FT | L07 | CT-L07-W-002-FT | L07 | West | Curtain wall | 1400 | 50 | Blue-grey concept glass | CT-104 | CT-L07-W-002
CT-L07-W-003-ML | L07 | CT-L07-W-003-ML | L07 | West | Curtain wall | 50 | 3300 | Blue-grey concept glass | CT-104 | CT-L07-W-003
CT-L07-W-003-MR | L07 | CT-L07-W-003-MR | L07 | West | Curtain wall | 50 | 3300 | Blue-grey concept glass | CT-104 | CT-L07-W-003
CT-L07-W-003-FB | L07 | CT-L07-W-003-FB | L07 | West | Curtain wall | 1400 | 50 | Blue-grey concept glass | CT-104 | CT-L07-W-003
CT-L07-W-003-FT | L07 | CT-L07-W-003-FT | L07 | West | Curtain wall | 1400 | 50 | Blue-grey concept glass | CT-104 | CT-L07-W-003
CT-L07-W-004-ML | L07 | CT-L07-W-004-ML | L07 | West | Curtain wall | 50 | 3300 | Blue-grey concept glass | CT-104 | CT-L07-W-004
CT-L07-W-004-MR | L07 | CT-L07-W-004-MR | L07 | West | Curtain wall | 50 | 3300 | Blue-grey concept glass | CT-104 | CT-L07-W-004
CT-L07-W-004-FB | L07 | CT-L07-W-004-FB | L07 | West | Curtain wall | 1400 | 50 | Blue-grey concept glass | CT-104 | CT-L07-W-004
CT-L07-W-004-FT | L07 | CT-L07-W-004-FT | L07 | West | Curtain wall | 1400 | 50 | Blue-grey concept glass | CT-104 | CT-L07-W-004
CT-L07-W-005-ML | L07 | CT-L07-W-005-ML | L07 | West | Metal rainscreen | 50 | 3300 | Olive powder coat | CT-104 | CT-L07-W-005
CT-L07-W-005-MR | L07 | CT-L07-W-005-MR | L07 | West | Metal rainscreen | 50 | 3300 | Olive powder coat | CT-104 | CT-L07-W-005
CT-L07-W-005-FB | L07 | CT-L07-W-005-FB | L07 | West | Metal rainscreen | 1400 | 50 | Olive powder coat | CT-104 | CT-L07-W-005
CT-L07-W-005-FT | L07 | CT-L07-W-005-FT | L07 | West | Metal rainscreen | 1400 | 50 | Olive powder coat | CT-104 | CT-L07-W-005
CT-L07-W-006-ML | L07 | CT-L07-W-006-ML | L07 | West | Curtain wall | 50 | 3300 | Blue-grey concept glass | CT-104 | CT-L07-W-006
CT-L07-W-006-MR | L07 | CT-L07-W-006-MR | L07 | West | Curtain wall | 50 | 3300 | Blue-grey concept glass | CT-104 | CT-L07-W-006
CT-L07-W-006-FB | L07 | CT-L07-W-006-FB | L07 | West | Curtain wall | 1400 | 50 | Blue-grey concept glass | CT-104 | CT-L07-W-006
CT-L07-W-006-FT | L07 | CT-L07-W-006-FT | L07 | West | Curtain wall | 1400 | 50 | Blue-grey concept glass | CT-104 | CT-L07-W-006
CT-L07-W-007-ML | L07 | CT-L07-W-007-ML | L07 | West | Curtain wall | 50 | 3300 | Blue-grey concept glass | CT-104 | CT-L07-W-007
CT-L07-W-007-MR | L07 | CT-L07-W-007-MR | L07 | West | Curtain wall | 50 | 3300 | Blue-grey concept glass | CT-104 | CT-L07-W-007
CT-L07-W-007-FB | L07 | CT-L07-W-007-FB | L07 | West | Curtain wall | 1400 | 50 | Blue-grey concept glass | CT-104 | CT-L07-W-007
CT-L07-W-007-FT | L07 | CT-L07-W-007-FT | L07 | West | Curtain wall | 1400 | 50 | Blue-grey concept glass | CT-104 | CT-L07-W-007
CT-L07-W-008-ML | L07 | CT-L07-W-008-ML | L07 | West | Curtain wall | 50 | 3300 | Blue-grey concept glass | CT-104 | CT-L07-W-008
CT-L07-W-008-MR | L07 | CT-L07-W-008-MR | L07 | West | Curtain wall | 50 | 3300 | Blue-grey concept glass | CT-104 | CT-L07-W-008
CT-L07-W-008-FB | L07 | CT-L07-W-008-FB | L07 | West | Curtain wall | 1400 | 50 | Blue-grey concept glass | CT-104 | CT-L07-W-008
CT-L07-W-008-FT | L07 | CT-L07-W-008-FT | L07 | West | Curtain wall | 1400 | 50 | Blue-grey concept glass | CT-104 | CT-L07-W-008
CT-L07-W-009-ML | L07 | CT-L07-W-009-ML | L07 | West | Curtain wall | 50 | 3300 | Blue-grey concept glass | CT-104 | CT-L07-W-009
CT-L07-W-009-MR | L07 | CT-L07-W-009-MR | L07 | West | Curtain wall | 50 | 3300 | Blue-grey concept glass | CT-104 | CT-L07-W-009
CT-L07-W-009-FB | L07 | CT-L07-W-009-FB | L07 | West | Curtain wall | 1400 | 50 | Blue-grey concept glass | CT-104 | CT-L07-W-009
CT-L07-W-009-FT | L07 | CT-L07-W-009-FT | L07 | West | Curtain wall | 1400 | 50 | Blue-grey concept glass | CT-104 | CT-L07-W-009
CT-L07-W-010-ML | L07 | CT-L07-W-010-ML | L07 | West | Metal rainscreen | 50 | 3300 | Olive powder coat | CT-104 | CT-L07-W-010
CT-L07-W-010-MR | L07 | CT-L07-W-010-MR | L07 | West | Metal rainscreen | 50 | 3300 | Olive powder coat | CT-104 | CT-L07-W-010
CT-L07-W-010-FB | L07 | CT-L07-W-010-FB | L07 | West | Metal rainscreen | 1250 | 50 | Olive powder coat | CT-104 | CT-L07-W-010
CT-L07-W-010-FT | L07 | CT-L07-W-010-FT | L07 | West | Metal rainscreen | 1250 | 50 | Olive powder coat | CT-104 | CT-L07-W-010
CT-L08-S-001-ML | L08 | CT-L08-S-001-ML | L08 | South | Curtain wall | 50 | 3300 | Blue-grey concept glass | CT-101 | CT-L08-S-001
CT-L08-S-001-MR | L08 | CT-L08-S-001-MR | L08 | South | Curtain wall | 50 | 3300 | Blue-grey concept glass | CT-101 | CT-L08-S-001
CT-L08-S-001-FB | L08 | CT-L08-S-001-FB | L08 | South | Curtain wall | 1250 | 50 | Blue-grey concept glass | CT-101 | CT-L08-S-001
CT-L08-S-001-FT | L08 | CT-L08-S-001-FT | L08 | South | Curtain wall | 1250 | 50 | Blue-grey concept glass | CT-101 | CT-L08-S-001
CT-L08-S-002-ML | L08 | CT-L08-S-002-ML | L08 | South | Curtain wall | 50 | 3300 | Blue-grey concept glass | CT-101 | CT-L08-S-002
CT-L08-S-002-MR | L08 | CT-L08-S-002-MR | L08 | South | Curtain wall | 50 | 3300 | Blue-grey concept glass | CT-101 | CT-L08-S-002
CT-L08-S-002-FB | L08 | CT-L08-S-002-FB | L08 | South | Curtain wall | 1400 | 50 | Blue-grey concept glass | CT-101 | CT-L08-S-002
CT-L08-S-002-FT | L08 | CT-L08-S-002-FT | L08 | South | Curtain wall | 1400 | 50 | Blue-grey concept glass | CT-101 | CT-L08-S-002
CT-L08-S-003-ML | L08 | CT-L08-S-003-ML | L08 | South | Curtain wall | 50 | 3300 | Blue-grey concept glass | CT-101 | CT-L08-S-003
CT-L08-S-003-MR | L08 | CT-L08-S-003-MR | L08 | South | Curtain wall | 50 | 3300 | Blue-grey concept glass | CT-101 | CT-L08-S-003
CT-L08-S-003-FB | L08 | CT-L08-S-003-FB | L08 | South | Curtain wall | 1400 | 50 | Blue-grey concept glass | CT-101 | CT-L08-S-003
CT-L08-S-003-FT | L08 | CT-L08-S-003-FT | L08 | South | Curtain wall | 1400 | 50 | Blue-grey concept glass | CT-101 | CT-L08-S-003
CT-L08-S-004-ML | L08 | CT-L08-S-004-ML | L08 | South | Curtain wall | 50 | 3300 | Blue-grey concept glass | CT-101 | CT-L08-S-004
CT-L08-S-004-MR | L08 | CT-L08-S-004-MR | L08 | South | Curtain wall | 50 | 3300 | Blue-grey concept glass | CT-101 | CT-L08-S-004
CT-L08-S-004-FB | L08 | CT-L08-S-004-FB | L08 | South | Curtain wall | 1400 | 50 | Blue-grey concept glass | CT-101 | CT-L08-S-004
CT-L08-S-004-FT | L08 | CT-L08-S-004-FT | L08 | South | Curtain wall | 1400 | 50 | Blue-grey concept glass | CT-101 | CT-L08-S-004
CT-L08-S-005-ML | L08 | CT-L08-S-005-ML | L08 | South | Metal rainscreen | 50 | 3300 | Olive powder coat | CT-101 | CT-L08-S-005
CT-L08-S-005-MR | L08 | CT-L08-S-005-MR | L08 | South | Metal rainscreen | 50 | 3300 | Olive powder coat | CT-101 | CT-L08-S-005
CT-L08-S-005-FB | L08 | CT-L08-S-005-FB | L08 | South | Metal rainscreen | 1400 | 50 | Olive powder coat | CT-101 | CT-L08-S-005
CT-L08-S-005-FT | L08 | CT-L08-S-005-FT | L08 | South | Metal rainscreen | 1400 | 50 | Olive powder coat | CT-101 | CT-L08-S-005
CT-L08-S-006-ML | L08 | CT-L08-S-006-ML | L08 | South | Curtain wall | 50 | 3300 | Blue-grey concept glass | CT-101 | CT-L08-S-006
CT-L08-S-006-MR | L08 | CT-L08-S-006-MR | L08 | South | Curtain wall | 50 | 3300 | Blue-grey concept glass | CT-101 | CT-L08-S-006
CT-L08-S-006-FB | L08 | CT-L08-S-006-FB | L08 | South | Curtain wall | 1400 | 50 | Blue-grey concept glass | CT-101 | CT-L08-S-006
CT-L08-S-006-FT | L08 | CT-L08-S-006-FT | L08 | South | Curtain wall | 1400 | 50 | Blue-grey concept glass | CT-101 | CT-L08-S-006
CT-L08-S-007-ML | L08 | CT-L08-S-007-ML | L08 | South | Curtain wall | 50 | 3300 | Blue-grey concept glass | CT-101 | CT-L08-S-007
CT-L08-S-007-MR | L08 | CT-L08-S-007-MR | L08 | South | Curtain wall | 50 | 3300 | Blue-grey concept glass | CT-101 | CT-L08-S-007
CT-L08-S-007-FB | L08 | CT-L08-S-007-FB | L08 | South | Curtain wall | 1400 | 50 | Blue-grey concept glass | CT-101 | CT-L08-S-007
CT-L08-S-007-FT | L08 | CT-L08-S-007-FT | L08 | South | Curtain wall | 1400 | 50 | Blue-grey concept glass | CT-101 | CT-L08-S-007
CT-L08-S-008-ML | L08 | CT-L08-S-008-ML | L08 | South | Curtain wall | 50 | 3300 | Blue-grey concept glass | CT-101 | CT-L08-S-008
CT-L08-S-008-MR | L08 | CT-L08-S-008-MR | L08 | South | Curtain wall | 50 | 3300 | Blue-grey concept glass | CT-101 | CT-L08-S-008
CT-L08-S-008-FB | L08 | CT-L08-S-008-FB | L08 | South | Curtain wall | 1400 | 50 | Blue-grey concept glass | CT-101 | CT-L08-S-008
CT-L08-S-008-FT | L08 | CT-L08-S-008-FT | L08 | South | Curtain wall | 1400 | 50 | Blue-grey concept glass | CT-101 | CT-L08-S-008
CT-L08-S-009-ML | L08 | CT-L08-S-009-ML | L08 | South | Curtain wall | 50 | 3300 | Blue-grey concept glass | CT-101 | CT-L08-S-009
CT-L08-S-009-MR | L08 | CT-L08-S-009-MR | L08 | South | Curtain wall | 50 | 3300 | Blue-grey concept glass | CT-101 | CT-L08-S-009
CT-L08-S-009-FB | L08 | CT-L08-S-009-FB | L08 | South | Curtain wall | 1400 | 50 | Blue-grey concept glass | CT-101 | CT-L08-S-009
CT-L08-S-009-FT | L08 | CT-L08-S-009-FT | L08 | South | Curtain wall | 1400 | 50 | Blue-grey concept glass | CT-101 | CT-L08-S-009
CT-L08-S-010-ML | L08 | CT-L08-S-010-ML | L08 | South | Metal rainscreen | 50 | 3300 | Olive powder coat | CT-101 | CT-L08-S-010
CT-L08-S-010-MR | L08 | CT-L08-S-010-MR | L08 | South | Metal rainscreen | 50 | 3300 | Olive powder coat | CT-101 | CT-L08-S-010
CT-L08-S-010-FB | L08 | CT-L08-S-010-FB | L08 | South | Metal rainscreen | 1400 | 50 | Olive powder coat | CT-101 | CT-L08-S-010
CT-L08-S-010-FT | L08 | CT-L08-S-010-FT | L08 | South | Metal rainscreen | 1400 | 50 | Olive powder coat | CT-101 | CT-L08-S-010
CT-L08-S-011-ML | L08 | CT-L08-S-011-ML | L08 | South | Curtain wall | 50 | 3300 | Blue-grey concept glass | CT-101 | CT-L08-S-011
CT-L08-S-011-MR | L08 | CT-L08-S-011-MR | L08 | South | Curtain wall | 50 | 3300 | Blue-grey concept glass | CT-101 | CT-L08-S-011
CT-L08-S-011-FB | L08 | CT-L08-S-011-FB | L08 | South | Curtain wall | 1400 | 50 | Blue-grey concept glass | CT-101 | CT-L08-S-011
CT-L08-S-011-FT | L08 | CT-L08-S-011-FT | L08 | South | Curtain wall | 1400 | 50 | Blue-grey concept glass | CT-101 | CT-L08-S-011
CT-L08-S-012-ML | L08 | CT-L08-S-012-ML | L08 | South | Curtain wall | 50 | 3300 | Blue-grey concept glass | CT-101 | CT-L08-S-012
CT-L08-S-012-MR | L08 | CT-L08-S-012-MR | L08 | South | Curtain wall | 50 | 3300 | Blue-grey concept glass | CT-101 | CT-L08-S-012
CT-L08-S-012-FB | L08 | CT-L08-S-012-FB | L08 | South | Curtain wall | 1400 | 50 | Blue-grey concept glass | CT-101 | CT-L08-S-012
CT-L08-S-012-FT | L08 | CT-L08-S-012-FT | L08 | South | Curtain wall | 1400 | 50 | Blue-grey concept glass | CT-101 | CT-L08-S-012
CT-L08-S-013-ML | L08 | CT-L08-S-013-ML | L08 | South | Curtain wall | 50 | 3300 | Blue-grey concept glass | CT-101 | CT-L08-S-013
CT-L08-S-013-MR | L08 | CT-L08-S-013-MR | L08 | South | Curtain wall | 50 | 3300 | Blue-grey concept glass | CT-101 | CT-L08-S-013
CT-L08-S-013-FB | L08 | CT-L08-S-013-FB | L08 | South | Curtain wall | 1400 | 50 | Blue-grey concept glass | CT-101 | CT-L08-S-013
CT-L08-S-013-FT | L08 | CT-L08-S-013-FT | L08 | South | Curtain wall | 1400 | 50 | Blue-grey concept glass | CT-101 | CT-L08-S-013
CT-L08-S-014-ML | L08 | CT-L08-S-014-ML | L08 | South | Curtain wall | 50 | 3300 | Blue-grey concept glass | CT-101 | CT-L08-S-014
CT-L08-S-014-MR | L08 | CT-L08-S-014-MR | L08 | South | Curtain wall | 50 | 3300 | Blue-grey concept glass | CT-101 | CT-L08-S-014
CT-L08-S-014-FB | L08 | CT-L08-S-014-FB | L08 | South | Curtain wall | 1250 | 50 | Blue-grey concept glass | CT-101 | CT-L08-S-014
CT-L08-S-014-FT | L08 | CT-L08-S-014-FT | L08 | South | Curtain wall | 1250 | 50 | Blue-grey concept glass | CT-101 | CT-L08-S-014
CT-L08-E-001-ML | L08 | CT-L08-E-001-ML | L08 | East | Curtain wall | 50 | 3300 | Blue-grey concept glass | CT-102 | CT-L08-E-001
CT-L08-E-001-MR | L08 | CT-L08-E-001-MR | L08 | East | Curtain wall | 50 | 3300 | Blue-grey concept glass | CT-102 | CT-L08-E-001
CT-L08-E-001-FB | L08 | CT-L08-E-001-FB | L08 | East | Curtain wall | 1250 | 50 | Blue-grey concept glass | CT-102 | CT-L08-E-001
CT-L08-E-001-FT | L08 | CT-L08-E-001-FT | L08 | East | Curtain wall | 1250 | 50 | Blue-grey concept glass | CT-102 | CT-L08-E-001
CT-L08-E-002-ML | L08 | CT-L08-E-002-ML | L08 | East | Curtain wall | 50 | 3300 | Blue-grey concept glass | CT-102 | CT-L08-E-002
CT-L08-E-002-MR | L08 | CT-L08-E-002-MR | L08 | East | Curtain wall | 50 | 3300 | Blue-grey concept glass | CT-102 | CT-L08-E-002
CT-L08-E-002-FB | L08 | CT-L08-E-002-FB | L08 | East | Curtain wall | 1400 | 50 | Blue-grey concept glass | CT-102 | CT-L08-E-002
CT-L08-E-002-FT | L08 | CT-L08-E-002-FT | L08 | East | Curtain wall | 1400 | 50 | Blue-grey concept glass | CT-102 | CT-L08-E-002
CT-L08-E-003-ML | L08 | CT-L08-E-003-ML | L08 | East | Curtain wall | 50 | 3300 | Blue-grey concept glass | CT-102 | CT-L08-E-003
CT-L08-E-003-MR | L08 | CT-L08-E-003-MR | L08 | East | Curtain wall | 50 | 3300 | Blue-grey concept glass | CT-102 | CT-L08-E-003
CT-L08-E-003-FB | L08 | CT-L08-E-003-FB | L08 | East | Curtain wall | 1400 | 50 | Blue-grey concept glass | CT-102 | CT-L08-E-003
CT-L08-E-003-FT | L08 | CT-L08-E-003-FT | L08 | East | Curtain wall | 1400 | 50 | Blue-grey concept glass | CT-102 | CT-L08-E-003
CT-L08-E-004-ML | L08 | CT-L08-E-004-ML | L08 | East | Curtain wall | 50 | 3300 | Blue-grey concept glass | CT-102 | CT-L08-E-004
CT-L08-E-004-MR | L08 | CT-L08-E-004-MR | L08 | East | Curtain wall | 50 | 3300 | Blue-grey concept glass | CT-102 | CT-L08-E-004
CT-L08-E-004-FB | L08 | CT-L08-E-004-FB | L08 | East | Curtain wall | 1400 | 50 | Blue-grey concept glass | CT-102 | CT-L08-E-004
CT-L08-E-004-FT | L08 | CT-L08-E-004-FT | L08 | East | Curtain wall | 1400 | 50 | Blue-grey concept glass | CT-102 | CT-L08-E-004
CT-L08-E-005-ML | L08 | CT-L08-E-005-ML | L08 | East | Metal rainscreen | 50 | 3300 | Olive powder coat | CT-102 | CT-L08-E-005
CT-L08-E-005-MR | L08 | CT-L08-E-005-MR | L08 | East | Metal rainscreen | 50 | 3300 | Olive powder coat | CT-102 | CT-L08-E-005
CT-L08-E-005-FB | L08 | CT-L08-E-005-FB | L08 | East | Metal rainscreen | 1400 | 50 | Olive powder coat | CT-102 | CT-L08-E-005
CT-L08-E-005-FT | L08 | CT-L08-E-005-FT | L08 | East | Metal rainscreen | 1400 | 50 | Olive powder coat | CT-102 | CT-L08-E-005
CT-L08-E-006-ML | L08 | CT-L08-E-006-ML | L08 | East | Curtain wall | 50 | 3300 | Blue-grey concept glass | CT-102 | CT-L08-E-006
CT-L08-E-006-MR | L08 | CT-L08-E-006-MR | L08 | East | Curtain wall | 50 | 3300 | Blue-grey concept glass | CT-102 | CT-L08-E-006
CT-L08-E-006-FB | L08 | CT-L08-E-006-FB | L08 | East | Curtain wall | 1400 | 50 | Blue-grey concept glass | CT-102 | CT-L08-E-006
CT-L08-E-006-FT | L08 | CT-L08-E-006-FT | L08 | East | Curtain wall | 1400 | 50 | Blue-grey concept glass | CT-102 | CT-L08-E-006
CT-L08-E-007-ML | L08 | CT-L08-E-007-ML | L08 | East | Curtain wall | 50 | 3300 | Blue-grey concept glass | CT-102 | CT-L08-E-007
CT-L08-E-007-MR | L08 | CT-L08-E-007-MR | L08 | East | Curtain wall | 50 | 3300 | Blue-grey concept glass | CT-102 | CT-L08-E-007
CT-L08-E-007-FB | L08 | CT-L08-E-007-FB | L08 | East | Curtain wall | 1400 | 50 | Blue-grey concept glass | CT-102 | CT-L08-E-007
CT-L08-E-007-FT | L08 | CT-L08-E-007-FT | L08 | East | Curtain wall | 1400 | 50 | Blue-grey concept glass | CT-102 | CT-L08-E-007
CT-L08-E-008-ML | L08 | CT-L08-E-008-ML | L08 | East | Curtain wall | 50 | 3300 | Blue-grey concept glass | CT-102 | CT-L08-E-008
CT-L08-E-008-MR | L08 | CT-L08-E-008-MR | L08 | East | Curtain wall | 50 | 3300 | Blue-grey concept glass | CT-102 | CT-L08-E-008
CT-L08-E-008-FB | L08 | CT-L08-E-008-FB | L08 | East | Curtain wall | 1400 | 50 | Blue-grey concept glass | CT-102 | CT-L08-E-008
CT-L08-E-008-FT | L08 | CT-L08-E-008-FT | L08 | East | Curtain wall | 1400 | 50 | Blue-grey concept glass | CT-102 | CT-L08-E-008
CT-L08-E-009-ML | L08 | CT-L08-E-009-ML | L08 | East | Curtain wall | 50 | 3300 | Blue-grey concept glass | CT-102 | CT-L08-E-009
CT-L08-E-009-MR | L08 | CT-L08-E-009-MR | L08 | East | Curtain wall | 50 | 3300 | Blue-grey concept glass | CT-102 | CT-L08-E-009
CT-L08-E-009-FB | L08 | CT-L08-E-009-FB | L08 | East | Curtain wall | 1400 | 50 | Blue-grey concept glass | CT-102 | CT-L08-E-009
CT-L08-E-009-FT | L08 | CT-L08-E-009-FT | L08 | East | Curtain wall | 1400 | 50 | Blue-grey concept glass | CT-102 | CT-L08-E-009
CT-L08-E-010-ML | L08 | CT-L08-E-010-ML | L08 | East | Metal rainscreen | 50 | 3300 | Olive powder coat | CT-102 | CT-L08-E-010
CT-L08-E-010-MR | L08 | CT-L08-E-010-MR | L08 | East | Metal rainscreen | 50 | 3300 | Olive powder coat | CT-102 | CT-L08-E-010
CT-L08-E-010-FB | L08 | CT-L08-E-010-FB | L08 | East | Metal rainscreen | 1250 | 50 | Olive powder coat | CT-102 | CT-L08-E-010
CT-L08-E-010-FT | L08 | CT-L08-E-010-FT | L08 | East | Metal rainscreen | 1250 | 50 | Olive powder coat | CT-102 | CT-L08-E-010
CT-L08-N-001-ML | L08 | CT-L08-N-001-ML | L08 | North | Curtain wall | 50 | 3300 | Blue-grey concept glass | CT-103 | CT-L08-N-001
CT-L08-N-001-MR | L08 | CT-L08-N-001-MR | L08 | North | Curtain wall | 50 | 3300 | Blue-grey concept glass | CT-103 | CT-L08-N-001
CT-L08-N-001-FB | L08 | CT-L08-N-001-FB | L08 | North | Curtain wall | 1250 | 50 | Blue-grey concept glass | CT-103 | CT-L08-N-001
CT-L08-N-001-FT | L08 | CT-L08-N-001-FT | L08 | North | Curtain wall | 1250 | 50 | Blue-grey concept glass | CT-103 | CT-L08-N-001
CT-L08-N-002-ML | L08 | CT-L08-N-002-ML | L08 | North | Curtain wall | 50 | 3300 | Blue-grey concept glass | CT-103 | CT-L08-N-002
CT-L08-N-002-MR | L08 | CT-L08-N-002-MR | L08 | North | Curtain wall | 50 | 3300 | Blue-grey concept glass | CT-103 | CT-L08-N-002
CT-L08-N-002-FB | L08 | CT-L08-N-002-FB | L08 | North | Curtain wall | 1400 | 50 | Blue-grey concept glass | CT-103 | CT-L08-N-002
CT-L08-N-002-FT | L08 | CT-L08-N-002-FT | L08 | North | Curtain wall | 1400 | 50 | Blue-grey concept glass | CT-103 | CT-L08-N-002
CT-L08-N-003-ML | L08 | CT-L08-N-003-ML | L08 | North | Curtain wall | 50 | 3300 | Blue-grey concept glass | CT-103 | CT-L08-N-003
CT-L08-N-003-MR | L08 | CT-L08-N-003-MR | L08 | North | Curtain wall | 50 | 3300 | Blue-grey concept glass | CT-103 | CT-L08-N-003
CT-L08-N-003-FB | L08 | CT-L08-N-003-FB | L08 | North | Curtain wall | 1400 | 50 | Blue-grey concept glass | CT-103 | CT-L08-N-003
CT-L08-N-003-FT | L08 | CT-L08-N-003-FT | L08 | North | Curtain wall | 1400 | 50 | Blue-grey concept glass | CT-103 | CT-L08-N-003
CT-L08-N-004-ML | L08 | CT-L08-N-004-ML | L08 | North | Curtain wall | 50 | 3300 | Blue-grey concept glass | CT-103 | CT-L08-N-004
CT-L08-N-004-MR | L08 | CT-L08-N-004-MR | L08 | North | Curtain wall | 50 | 3300 | Blue-grey concept glass | CT-103 | CT-L08-N-004
CT-L08-N-004-FB | L08 | CT-L08-N-004-FB | L08 | North | Curtain wall | 1400 | 50 | Blue-grey concept glass | CT-103 | CT-L08-N-004
CT-L08-N-004-FT | L08 | CT-L08-N-004-FT | L08 | North | Curtain wall | 1400 | 50 | Blue-grey concept glass | CT-103 | CT-L08-N-004
CT-L08-N-005-ML | L08 | CT-L08-N-005-ML | L08 | North | Metal rainscreen | 50 | 3300 | Olive powder coat | CT-103 | CT-L08-N-005
CT-L08-N-005-MR | L08 | CT-L08-N-005-MR | L08 | North | Metal rainscreen | 50 | 3300 | Olive powder coat | CT-103 | CT-L08-N-005
CT-L08-N-005-FB | L08 | CT-L08-N-005-FB | L08 | North | Metal rainscreen | 1400 | 50 | Olive powder coat | CT-103 | CT-L08-N-005
CT-L08-N-005-FT | L08 | CT-L08-N-005-FT | L08 | North | Metal rainscreen | 1400 | 50 | Olive powder coat | CT-103 | CT-L08-N-005
CT-L08-N-006-ML | L08 | CT-L08-N-006-ML | L08 | North | Curtain wall | 50 | 3300 | Blue-grey concept glass | CT-103 | CT-L08-N-006
CT-L08-N-006-MR | L08 | CT-L08-N-006-MR | L08 | North | Curtain wall | 50 | 3300 | Blue-grey concept glass | CT-103 | CT-L08-N-006
CT-L08-N-006-FB | L08 | CT-L08-N-006-FB | L08 | North | Curtain wall | 1400 | 50 | Blue-grey concept glass | CT-103 | CT-L08-N-006
CT-L08-N-006-FT | L08 | CT-L08-N-006-FT | L08 | North | Curtain wall | 1400 | 50 | Blue-grey concept glass | CT-103 | CT-L08-N-006
CT-L08-N-007-ML | L08 | CT-L08-N-007-ML | L08 | North | Curtain wall | 50 | 3300 | Blue-grey concept glass | CT-103 | CT-L08-N-007
CT-L08-N-007-MR | L08 | CT-L08-N-007-MR | L08 | North | Curtain wall | 50 | 3300 | Blue-grey concept glass | CT-103 | CT-L08-N-007
CT-L08-N-007-FB | L08 | CT-L08-N-007-FB | L08 | North | Curtain wall | 1400 | 50 | Blue-grey concept glass | CT-103 | CT-L08-N-007
CT-L08-N-007-FT | L08 | CT-L08-N-007-FT | L08 | North | Curtain wall | 1400 | 50 | Blue-grey concept glass | CT-103 | CT-L08-N-007
CT-L08-N-008-ML | L08 | CT-L08-N-008-ML | L08 | North | Curtain wall | 50 | 3300 | Blue-grey concept glass | CT-103 | CT-L08-N-008
CT-L08-N-008-MR | L08 | CT-L08-N-008-MR | L08 | North | Curtain wall | 50 | 3300 | Blue-grey concept glass | CT-103 | CT-L08-N-008
CT-L08-N-008-FB | L08 | CT-L08-N-008-FB | L08 | North | Curtain wall | 1400 | 50 | Blue-grey concept glass | CT-103 | CT-L08-N-008
CT-L08-N-008-FT | L08 | CT-L08-N-008-FT | L08 | North | Curtain wall | 1400 | 50 | Blue-grey concept glass | CT-103 | CT-L08-N-008
CT-L08-N-009-ML | L08 | CT-L08-N-009-ML | L08 | North | Curtain wall | 50 | 3300 | Blue-grey concept glass | CT-103 | CT-L08-N-009
CT-L08-N-009-MR | L08 | CT-L08-N-009-MR | L08 | North | Curtain wall | 50 | 3300 | Blue-grey concept glass | CT-103 | CT-L08-N-009
CT-L08-N-009-FB | L08 | CT-L08-N-009-FB | L08 | North | Curtain wall | 1400 | 50 | Blue-grey concept glass | CT-103 | CT-L08-N-009
CT-L08-N-009-FT | L08 | CT-L08-N-009-FT | L08 | North | Curtain wall | 1400 | 50 | Blue-grey concept glass | CT-103 | CT-L08-N-009
CT-L08-N-010-ML | L08 | CT-L08-N-010-ML | L08 | North | Metal rainscreen | 50 | 3300 | Olive powder coat | CT-103 | CT-L08-N-010
CT-L08-N-010-MR | L08 | CT-L08-N-010-MR | L08 | North | Metal rainscreen | 50 | 3300 | Olive powder coat | CT-103 | CT-L08-N-010
CT-L08-N-010-FB | L08 | CT-L08-N-010-FB | L08 | North | Metal rainscreen | 1400 | 50 | Olive powder coat | CT-103 | CT-L08-N-010
CT-L08-N-010-FT | L08 | CT-L08-N-010-FT | L08 | North | Metal rainscreen | 1400 | 50 | Olive powder coat | CT-103 | CT-L08-N-010
CT-L08-N-011-ML | L08 | CT-L08-N-011-ML | L08 | North | Curtain wall | 50 | 3300 | Blue-grey concept glass | CT-103 | CT-L08-N-011
CT-L08-N-011-MR | L08 | CT-L08-N-011-MR | L08 | North | Curtain wall | 50 | 3300 | Blue-grey concept glass | CT-103 | CT-L08-N-011
CT-L08-N-011-FB | L08 | CT-L08-N-011-FB | L08 | North | Curtain wall | 1400 | 50 | Blue-grey concept glass | CT-103 | CT-L08-N-011
CT-L08-N-011-FT | L08 | CT-L08-N-011-FT | L08 | North | Curtain wall | 1400 | 50 | Blue-grey concept glass | CT-103 | CT-L08-N-011
CT-L08-N-012-ML | L08 | CT-L08-N-012-ML | L08 | North | Curtain wall | 50 | 3300 | Blue-grey concept glass | CT-103 | CT-L08-N-012
CT-L08-N-012-MR | L08 | CT-L08-N-012-MR | L08 | North | Curtain wall | 50 | 3300 | Blue-grey concept glass | CT-103 | CT-L08-N-012
CT-L08-N-012-FB | L08 | CT-L08-N-012-FB | L08 | North | Curtain wall | 1400 | 50 | Blue-grey concept glass | CT-103 | CT-L08-N-012
CT-L08-N-012-FT | L08 | CT-L08-N-012-FT | L08 | North | Curtain wall | 1400 | 50 | Blue-grey concept glass | CT-103 | CT-L08-N-012
CT-L08-N-013-ML | L08 | CT-L08-N-013-ML | L08 | North | Curtain wall | 50 | 3300 | Blue-grey concept glass | CT-103 | CT-L08-N-013
CT-L08-N-013-MR | L08 | CT-L08-N-013-MR | L08 | North | Curtain wall | 50 | 3300 | Blue-grey concept glass | CT-103 | CT-L08-N-013
CT-L08-N-013-FB | L08 | CT-L08-N-013-FB | L08 | North | Curtain wall | 1400 | 50 | Blue-grey concept glass | CT-103 | CT-L08-N-013
CT-L08-N-013-FT | L08 | CT-L08-N-013-FT | L08 | North | Curtain wall | 1400 | 50 | Blue-grey concept glass | CT-103 | CT-L08-N-013
CT-L08-N-014-ML | L08 | CT-L08-N-014-ML | L08 | North | Curtain wall | 50 | 3300 | Blue-grey concept glass | CT-103 | CT-L08-N-014
CT-L08-N-014-MR | L08 | CT-L08-N-014-MR | L08 | North | Curtain wall | 50 | 3300 | Blue-grey concept glass | CT-103 | CT-L08-N-014
CT-L08-N-014-FB | L08 | CT-L08-N-014-FB | L08 | North | Curtain wall | 1250 | 50 | Blue-grey concept glass | CT-103 | CT-L08-N-014
CT-L08-N-014-FT | L08 | CT-L08-N-014-FT | L08 | North | Curtain wall | 1250 | 50 | Blue-grey concept glass | CT-103 | CT-L08-N-014
CT-L08-W-001-ML | L08 | CT-L08-W-001-ML | L08 | West | Curtain wall | 50 | 3300 | Blue-grey concept glass | CT-104 | CT-L08-W-001
CT-L08-W-001-MR | L08 | CT-L08-W-001-MR | L08 | West | Curtain wall | 50 | 3300 | Blue-grey concept glass | CT-104 | CT-L08-W-001
CT-L08-W-001-FB | L08 | CT-L08-W-001-FB | L08 | West | Curtain wall | 1250 | 50 | Blue-grey concept glass | CT-104 | CT-L08-W-001
CT-L08-W-001-FT | L08 | CT-L08-W-001-FT | L08 | West | Curtain wall | 1250 | 50 | Blue-grey concept glass | CT-104 | CT-L08-W-001
CT-L08-W-002-ML | L08 | CT-L08-W-002-ML | L08 | West | Curtain wall | 50 | 3300 | Blue-grey concept glass | CT-104 | CT-L08-W-002
CT-L08-W-002-MR | L08 | CT-L08-W-002-MR | L08 | West | Curtain wall | 50 | 3300 | Blue-grey concept glass | CT-104 | CT-L08-W-002
CT-L08-W-002-FB | L08 | CT-L08-W-002-FB | L08 | West | Curtain wall | 1400 | 50 | Blue-grey concept glass | CT-104 | CT-L08-W-002
CT-L08-W-002-FT | L08 | CT-L08-W-002-FT | L08 | West | Curtain wall | 1400 | 50 | Blue-grey concept glass | CT-104 | CT-L08-W-002
CT-L08-W-003-ML | L08 | CT-L08-W-003-ML | L08 | West | Curtain wall | 50 | 3300 | Blue-grey concept glass | CT-104 | CT-L08-W-003
CT-L08-W-003-MR | L08 | CT-L08-W-003-MR | L08 | West | Curtain wall | 50 | 3300 | Blue-grey concept glass | CT-104 | CT-L08-W-003
CT-L08-W-003-FB | L08 | CT-L08-W-003-FB | L08 | West | Curtain wall | 1400 | 50 | Blue-grey concept glass | CT-104 | CT-L08-W-003
CT-L08-W-003-FT | L08 | CT-L08-W-003-FT | L08 | West | Curtain wall | 1400 | 50 | Blue-grey concept glass | CT-104 | CT-L08-W-003
CT-L08-W-004-ML | L08 | CT-L08-W-004-ML | L08 | West | Curtain wall | 50 | 3300 | Blue-grey concept glass | CT-104 | CT-L08-W-004
CT-L08-W-004-MR | L08 | CT-L08-W-004-MR | L08 | West | Curtain wall | 50 | 3300 | Blue-grey concept glass | CT-104 | CT-L08-W-004
CT-L08-W-004-FB | L08 | CT-L08-W-004-FB | L08 | West | Curtain wall | 1400 | 50 | Blue-grey concept glass | CT-104 | CT-L08-W-004
CT-L08-W-004-FT | L08 | CT-L08-W-004-FT | L08 | West | Curtain wall | 1400 | 50 | Blue-grey concept glass | CT-104 | CT-L08-W-004
CT-L08-W-005-ML | L08 | CT-L08-W-005-ML | L08 | West | Metal rainscreen | 50 | 3300 | Olive powder coat | CT-104 | CT-L08-W-005
CT-L08-W-005-MR | L08 | CT-L08-W-005-MR | L08 | West | Metal rainscreen | 50 | 3300 | Olive powder coat | CT-104 | CT-L08-W-005
CT-L08-W-005-FB | L08 | CT-L08-W-005-FB | L08 | West | Metal rainscreen | 1400 | 50 | Olive powder coat | CT-104 | CT-L08-W-005
CT-L08-W-005-FT | L08 | CT-L08-W-005-FT | L08 | West | Metal rainscreen | 1400 | 50 | Olive powder coat | CT-104 | CT-L08-W-005
CT-L08-W-006-ML | L08 | CT-L08-W-006-ML | L08 | West | Curtain wall | 50 | 3300 | Blue-grey concept glass | CT-104 | CT-L08-W-006
CT-L08-W-006-MR | L08 | CT-L08-W-006-MR | L08 | West | Curtain wall | 50 | 3300 | Blue-grey concept glass | CT-104 | CT-L08-W-006
CT-L08-W-006-FB | L08 | CT-L08-W-006-FB | L08 | West | Curtain wall | 1400 | 50 | Blue-grey concept glass | CT-104 | CT-L08-W-006
CT-L08-W-006-FT | L08 | CT-L08-W-006-FT | L08 | West | Curtain wall | 1400 | 50 | Blue-grey concept glass | CT-104 | CT-L08-W-006
CT-L08-W-007-ML | L08 | CT-L08-W-007-ML | L08 | West | Curtain wall | 50 | 3300 | Blue-grey concept glass | CT-104 | CT-L08-W-007
CT-L08-W-007-MR | L08 | CT-L08-W-007-MR | L08 | West | Curtain wall | 50 | 3300 | Blue-grey concept glass | CT-104 | CT-L08-W-007
CT-L08-W-007-FB | L08 | CT-L08-W-007-FB | L08 | West | Curtain wall | 1400 | 50 | Blue-grey concept glass | CT-104 | CT-L08-W-007
CT-L08-W-007-FT | L08 | CT-L08-W-007-FT | L08 | West | Curtain wall | 1400 | 50 | Blue-grey concept glass | CT-104 | CT-L08-W-007
CT-L08-W-008-ML | L08 | CT-L08-W-008-ML | L08 | West | Curtain wall | 50 | 3300 | Blue-grey concept glass | CT-104 | CT-L08-W-008
CT-L08-W-008-MR | L08 | CT-L08-W-008-MR | L08 | West | Curtain wall | 50 | 3300 | Blue-grey concept glass | CT-104 | CT-L08-W-008
CT-L08-W-008-FB | L08 | CT-L08-W-008-FB | L08 | West | Curtain wall | 1400 | 50 | Blue-grey concept glass | CT-104 | CT-L08-W-008
CT-L08-W-008-FT | L08 | CT-L08-W-008-FT | L08 | West | Curtain wall | 1400 | 50 | Blue-grey concept glass | CT-104 | CT-L08-W-008
CT-L08-W-009-ML | L08 | CT-L08-W-009-ML | L08 | West | Curtain wall | 50 | 3300 | Blue-grey concept glass | CT-104 | CT-L08-W-009
CT-L08-W-009-MR | L08 | CT-L08-W-009-MR | L08 | West | Curtain wall | 50 | 3300 | Blue-grey concept glass | CT-104 | CT-L08-W-009
CT-L08-W-009-FB | L08 | CT-L08-W-009-FB | L08 | West | Curtain wall | 1400 | 50 | Blue-grey concept glass | CT-104 | CT-L08-W-009
CT-L08-W-009-FT | L08 | CT-L08-W-009-FT | L08 | West | Curtain wall | 1400 | 50 | Blue-grey concept glass | CT-104 | CT-L08-W-009
CT-L08-W-010-ML | L08 | CT-L08-W-010-ML | L08 | West | Metal rainscreen | 50 | 3300 | Olive powder coat | CT-104 | CT-L08-W-010
CT-L08-W-010-MR | L08 | CT-L08-W-010-MR | L08 | West | Metal rainscreen | 50 | 3300 | Olive powder coat | CT-104 | CT-L08-W-010
CT-L08-W-010-FB | L08 | CT-L08-W-010-FB | L08 | West | Metal rainscreen | 1250 | 50 | Olive powder coat | CT-104 | CT-L08-W-010
CT-L08-W-010-FT | L08 | CT-L08-W-010-FT | L08 | West | Metal rainscreen | 1250 | 50 | Olive powder coat | CT-104 | CT-L08-W-010
CT-L09-S-001-ML | L09 | CT-L09-S-001-ML | L09 | South | Curtain wall | 50 | 3300 | Blue-grey concept glass | CT-101 | CT-L09-S-001
CT-L09-S-001-MR | L09 | CT-L09-S-001-MR | L09 | South | Curtain wall | 50 | 3300 | Blue-grey concept glass | CT-101 | CT-L09-S-001
CT-L09-S-001-FB | L09 | CT-L09-S-001-FB | L09 | South | Curtain wall | 1250 | 50 | Blue-grey concept glass | CT-101 | CT-L09-S-001
CT-L09-S-001-FT | L09 | CT-L09-S-001-FT | L09 | South | Curtain wall | 1250 | 50 | Blue-grey concept glass | CT-101 | CT-L09-S-001
CT-L09-S-002-ML | L09 | CT-L09-S-002-ML | L09 | South | Curtain wall | 50 | 3300 | Blue-grey concept glass | CT-101 | CT-L09-S-002
CT-L09-S-002-MR | L09 | CT-L09-S-002-MR | L09 | South | Curtain wall | 50 | 3300 | Blue-grey concept glass | CT-101 | CT-L09-S-002
CT-L09-S-002-FB | L09 | CT-L09-S-002-FB | L09 | South | Curtain wall | 1400 | 50 | Blue-grey concept glass | CT-101 | CT-L09-S-002
CT-L09-S-002-FT | L09 | CT-L09-S-002-FT | L09 | South | Curtain wall | 1400 | 50 | Blue-grey concept glass | CT-101 | CT-L09-S-002
CT-L09-S-003-ML | L09 | CT-L09-S-003-ML | L09 | South | Curtain wall | 50 | 3300 | Blue-grey concept glass | CT-101 | CT-L09-S-003
CT-L09-S-003-MR | L09 | CT-L09-S-003-MR | L09 | South | Curtain wall | 50 | 3300 | Blue-grey concept glass | CT-101 | CT-L09-S-003
CT-L09-S-003-FB | L09 | CT-L09-S-003-FB | L09 | South | Curtain wall | 1400 | 50 | Blue-grey concept glass | CT-101 | CT-L09-S-003
CT-L09-S-003-FT | L09 | CT-L09-S-003-FT | L09 | South | Curtain wall | 1400 | 50 | Blue-grey concept glass | CT-101 | CT-L09-S-003
CT-L09-S-004-ML | L09 | CT-L09-S-004-ML | L09 | South | Curtain wall | 50 | 3300 | Blue-grey concept glass | CT-101 | CT-L09-S-004
CT-L09-S-004-MR | L09 | CT-L09-S-004-MR | L09 | South | Curtain wall | 50 | 3300 | Blue-grey concept glass | CT-101 | CT-L09-S-004
CT-L09-S-004-FB | L09 | CT-L09-S-004-FB | L09 | South | Curtain wall | 1400 | 50 | Blue-grey concept glass | CT-101 | CT-L09-S-004
CT-L09-S-004-FT | L09 | CT-L09-S-004-FT | L09 | South | Curtain wall | 1400 | 50 | Blue-grey concept glass | CT-101 | CT-L09-S-004
CT-L09-S-005-ML | L09 | CT-L09-S-005-ML | L09 | South | Metal rainscreen | 50 | 3300 | Olive powder coat | CT-101 | CT-L09-S-005
CT-L09-S-005-MR | L09 | CT-L09-S-005-MR | L09 | South | Metal rainscreen | 50 | 3300 | Olive powder coat | CT-101 | CT-L09-S-005
CT-L09-S-005-FB | L09 | CT-L09-S-005-FB | L09 | South | Metal rainscreen | 1400 | 50 | Olive powder coat | CT-101 | CT-L09-S-005
CT-L09-S-005-FT | L09 | CT-L09-S-005-FT | L09 | South | Metal rainscreen | 1400 | 50 | Olive powder coat | CT-101 | CT-L09-S-005
CT-L09-S-006-ML | L09 | CT-L09-S-006-ML | L09 | South | Curtain wall | 50 | 3300 | Blue-grey concept glass | CT-101 | CT-L09-S-006
CT-L09-S-006-MR | L09 | CT-L09-S-006-MR | L09 | South | Curtain wall | 50 | 3300 | Blue-grey concept glass | CT-101 | CT-L09-S-006
CT-L09-S-006-FB | L09 | CT-L09-S-006-FB | L09 | South | Curtain wall | 1400 | 50 | Blue-grey concept glass | CT-101 | CT-L09-S-006
CT-L09-S-006-FT | L09 | CT-L09-S-006-FT | L09 | South | Curtain wall | 1400 | 50 | Blue-grey concept glass | CT-101 | CT-L09-S-006
CT-L09-S-007-ML | L09 | CT-L09-S-007-ML | L09 | South | Curtain wall | 50 | 3300 | Blue-grey concept glass | CT-101 | CT-L09-S-007
CT-L09-S-007-MR | L09 | CT-L09-S-007-MR | L09 | South | Curtain wall | 50 | 3300 | Blue-grey concept glass | CT-101 | CT-L09-S-007
CT-L09-S-007-FB | L09 | CT-L09-S-007-FB | L09 | South | Curtain wall | 1400 | 50 | Blue-grey concept glass | CT-101 | CT-L09-S-007
CT-L09-S-007-FT | L09 | CT-L09-S-007-FT | L09 | South | Curtain wall | 1400 | 50 | Blue-grey concept glass | CT-101 | CT-L09-S-007
CT-L09-S-008-ML | L09 | CT-L09-S-008-ML | L09 | South | Curtain wall | 50 | 3300 | Blue-grey concept glass | CT-101 | CT-L09-S-008
CT-L09-S-008-MR | L09 | CT-L09-S-008-MR | L09 | South | Curtain wall | 50 | 3300 | Blue-grey concept glass | CT-101 | CT-L09-S-008
CT-L09-S-008-FB | L09 | CT-L09-S-008-FB | L09 | South | Curtain wall | 1400 | 50 | Blue-grey concept glass | CT-101 | CT-L09-S-008
CT-L09-S-008-FT | L09 | CT-L09-S-008-FT | L09 | South | Curtain wall | 1400 | 50 | Blue-grey concept glass | CT-101 | CT-L09-S-008
CT-L09-S-009-ML | L09 | CT-L09-S-009-ML | L09 | South | Curtain wall | 50 | 3300 | Blue-grey concept glass | CT-101 | CT-L09-S-009
CT-L09-S-009-MR | L09 | CT-L09-S-009-MR | L09 | South | Curtain wall | 50 | 3300 | Blue-grey concept glass | CT-101 | CT-L09-S-009
CT-L09-S-009-FB | L09 | CT-L09-S-009-FB | L09 | South | Curtain wall | 1400 | 50 | Blue-grey concept glass | CT-101 | CT-L09-S-009
CT-L09-S-009-FT | L09 | CT-L09-S-009-FT | L09 | South | Curtain wall | 1400 | 50 | Blue-grey concept glass | CT-101 | CT-L09-S-009
CT-L09-S-010-ML | L09 | CT-L09-S-010-ML | L09 | South | Metal rainscreen | 50 | 3300 | Olive powder coat | CT-101 | CT-L09-S-010
CT-L09-S-010-MR | L09 | CT-L09-S-010-MR | L09 | South | Metal rainscreen | 50 | 3300 | Olive powder coat | CT-101 | CT-L09-S-010
CT-L09-S-010-FB | L09 | CT-L09-S-010-FB | L09 | South | Metal rainscreen | 1400 | 50 | Olive powder coat | CT-101 | CT-L09-S-010
CT-L09-S-010-FT | L09 | CT-L09-S-010-FT | L09 | South | Metal rainscreen | 1400 | 50 | Olive powder coat | CT-101 | CT-L09-S-010
CT-L09-S-011-ML | L09 | CT-L09-S-011-ML | L09 | South | Curtain wall | 50 | 3300 | Blue-grey concept glass | CT-101 | CT-L09-S-011
CT-L09-S-011-MR | L09 | CT-L09-S-011-MR | L09 | South | Curtain wall | 50 | 3300 | Blue-grey concept glass | CT-101 | CT-L09-S-011
CT-L09-S-011-FB | L09 | CT-L09-S-011-FB | L09 | South | Curtain wall | 1400 | 50 | Blue-grey concept glass | CT-101 | CT-L09-S-011
CT-L09-S-011-FT | L09 | CT-L09-S-011-FT | L09 | South | Curtain wall | 1400 | 50 | Blue-grey concept glass | CT-101 | CT-L09-S-011
CT-L09-S-012-ML | L09 | CT-L09-S-012-ML | L09 | South | Curtain wall | 50 | 3300 | Blue-grey concept glass | CT-101 | CT-L09-S-012
CT-L09-S-012-MR | L09 | CT-L09-S-012-MR | L09 | South | Curtain wall | 50 | 3300 | Blue-grey concept glass | CT-101 | CT-L09-S-012
CT-L09-S-012-FB | L09 | CT-L09-S-012-FB | L09 | South | Curtain wall | 1400 | 50 | Blue-grey concept glass | CT-101 | CT-L09-S-012
CT-L09-S-012-FT | L09 | CT-L09-S-012-FT | L09 | South | Curtain wall | 1400 | 50 | Blue-grey concept glass | CT-101 | CT-L09-S-012
CT-L09-S-013-ML | L09 | CT-L09-S-013-ML | L09 | South | Curtain wall | 50 | 3300 | Blue-grey concept glass | CT-101 | CT-L09-S-013
CT-L09-S-013-MR | L09 | CT-L09-S-013-MR | L09 | South | Curtain wall | 50 | 3300 | Blue-grey concept glass | CT-101 | CT-L09-S-013
CT-L09-S-013-FB | L09 | CT-L09-S-013-FB | L09 | South | Curtain wall | 1400 | 50 | Blue-grey concept glass | CT-101 | CT-L09-S-013
CT-L09-S-013-FT | L09 | CT-L09-S-013-FT | L09 | South | Curtain wall | 1400 | 50 | Blue-grey concept glass | CT-101 | CT-L09-S-013
CT-L09-S-014-ML | L09 | CT-L09-S-014-ML | L09 | South | Curtain wall | 50 | 3300 | Blue-grey concept glass | CT-101 | CT-L09-S-014
CT-L09-S-014-MR | L09 | CT-L09-S-014-MR | L09 | South | Curtain wall | 50 | 3300 | Blue-grey concept glass | CT-101 | CT-L09-S-014
CT-L09-S-014-FB | L09 | CT-L09-S-014-FB | L09 | South | Curtain wall | 1250 | 50 | Blue-grey concept glass | CT-101 | CT-L09-S-014
CT-L09-S-014-FT | L09 | CT-L09-S-014-FT | L09 | South | Curtain wall | 1250 | 50 | Blue-grey concept glass | CT-101 | CT-L09-S-014
CT-L09-E-001-ML | L09 | CT-L09-E-001-ML | L09 | East | Curtain wall | 50 | 3300 | Blue-grey concept glass | CT-102 | CT-L09-E-001
CT-L09-E-001-MR | L09 | CT-L09-E-001-MR | L09 | East | Curtain wall | 50 | 3300 | Blue-grey concept glass | CT-102 | CT-L09-E-001
CT-L09-E-001-FB | L09 | CT-L09-E-001-FB | L09 | East | Curtain wall | 1250 | 50 | Blue-grey concept glass | CT-102 | CT-L09-E-001
CT-L09-E-001-FT | L09 | CT-L09-E-001-FT | L09 | East | Curtain wall | 1250 | 50 | Blue-grey concept glass | CT-102 | CT-L09-E-001
CT-L09-E-002-ML | L09 | CT-L09-E-002-ML | L09 | East | Curtain wall | 50 | 3300 | Blue-grey concept glass | CT-102 | CT-L09-E-002
CT-L09-E-002-MR | L09 | CT-L09-E-002-MR | L09 | East | Curtain wall | 50 | 3300 | Blue-grey concept glass | CT-102 | CT-L09-E-002
CT-L09-E-002-FB | L09 | CT-L09-E-002-FB | L09 | East | Curtain wall | 1400 | 50 | Blue-grey concept glass | CT-102 | CT-L09-E-002
CT-L09-E-002-FT | L09 | CT-L09-E-002-FT | L09 | East | Curtain wall | 1400 | 50 | Blue-grey concept glass | CT-102 | CT-L09-E-002
CT-L09-E-003-ML | L09 | CT-L09-E-003-ML | L09 | East | Curtain wall | 50 | 3300 | Blue-grey concept glass | CT-102 | CT-L09-E-003
CT-L09-E-003-MR | L09 | CT-L09-E-003-MR | L09 | East | Curtain wall | 50 | 3300 | Blue-grey concept glass | CT-102 | CT-L09-E-003
CT-L09-E-003-FB | L09 | CT-L09-E-003-FB | L09 | East | Curtain wall | 1400 | 50 | Blue-grey concept glass | CT-102 | CT-L09-E-003
CT-L09-E-003-FT | L09 | CT-L09-E-003-FT | L09 | East | Curtain wall | 1400 | 50 | Blue-grey concept glass | CT-102 | CT-L09-E-003
CT-L09-E-004-ML | L09 | CT-L09-E-004-ML | L09 | East | Curtain wall | 50 | 3300 | Blue-grey concept glass | CT-102 | CT-L09-E-004
CT-L09-E-004-MR | L09 | CT-L09-E-004-MR | L09 | East | Curtain wall | 50 | 3300 | Blue-grey concept glass | CT-102 | CT-L09-E-004
CT-L09-E-004-FB | L09 | CT-L09-E-004-FB | L09 | East | Curtain wall | 1400 | 50 | Blue-grey concept glass | CT-102 | CT-L09-E-004
CT-L09-E-004-FT | L09 | CT-L09-E-004-FT | L09 | East | Curtain wall | 1400 | 50 | Blue-grey concept glass | CT-102 | CT-L09-E-004
CT-L09-E-005-ML | L09 | CT-L09-E-005-ML | L09 | East | Metal rainscreen | 50 | 3300 | Olive powder coat | CT-102 | CT-L09-E-005
CT-L09-E-005-MR | L09 | CT-L09-E-005-MR | L09 | East | Metal rainscreen | 50 | 3300 | Olive powder coat | CT-102 | CT-L09-E-005
CT-L09-E-005-FB | L09 | CT-L09-E-005-FB | L09 | East | Metal rainscreen | 1400 | 50 | Olive powder coat | CT-102 | CT-L09-E-005
CT-L09-E-005-FT | L09 | CT-L09-E-005-FT | L09 | East | Metal rainscreen | 1400 | 50 | Olive powder coat | CT-102 | CT-L09-E-005
CT-L09-E-006-ML | L09 | CT-L09-E-006-ML | L09 | East | Curtain wall | 50 | 3300 | Blue-grey concept glass | CT-102 | CT-L09-E-006
CT-L09-E-006-MR | L09 | CT-L09-E-006-MR | L09 | East | Curtain wall | 50 | 3300 | Blue-grey concept glass | CT-102 | CT-L09-E-006
CT-L09-E-006-FB | L09 | CT-L09-E-006-FB | L09 | East | Curtain wall | 1400 | 50 | Blue-grey concept glass | CT-102 | CT-L09-E-006
CT-L09-E-006-FT | L09 | CT-L09-E-006-FT | L09 | East | Curtain wall | 1400 | 50 | Blue-grey concept glass | CT-102 | CT-L09-E-006
CT-L09-E-007-ML | L09 | CT-L09-E-007-ML | L09 | East | Curtain wall | 50 | 3300 | Blue-grey concept glass | CT-102 | CT-L09-E-007
CT-L09-E-007-MR | L09 | CT-L09-E-007-MR | L09 | East | Curtain wall | 50 | 3300 | Blue-grey concept glass | CT-102 | CT-L09-E-007
CT-L09-E-007-FB | L09 | CT-L09-E-007-FB | L09 | East | Curtain wall | 1400 | 50 | Blue-grey concept glass | CT-102 | CT-L09-E-007
CT-L09-E-007-FT | L09 | CT-L09-E-007-FT | L09 | East | Curtain wall | 1400 | 50 | Blue-grey concept glass | CT-102 | CT-L09-E-007
CT-L09-E-008-ML | L09 | CT-L09-E-008-ML | L09 | East | Curtain wall | 50 | 3300 | Blue-grey concept glass | CT-102 | CT-L09-E-008
CT-L09-E-008-MR | L09 | CT-L09-E-008-MR | L09 | East | Curtain wall | 50 | 3300 | Blue-grey concept glass | CT-102 | CT-L09-E-008
CT-L09-E-008-FB | L09 | CT-L09-E-008-FB | L09 | East | Curtain wall | 1400 | 50 | Blue-grey concept glass | CT-102 | CT-L09-E-008
CT-L09-E-008-FT | L09 | CT-L09-E-008-FT | L09 | East | Curtain wall | 1400 | 50 | Blue-grey concept glass | CT-102 | CT-L09-E-008
CT-L09-E-009-ML | L09 | CT-L09-E-009-ML | L09 | East | Curtain wall | 50 | 3300 | Blue-grey concept glass | CT-102 | CT-L09-E-009
CT-L09-E-009-MR | L09 | CT-L09-E-009-MR | L09 | East | Curtain wall | 50 | 3300 | Blue-grey concept glass | CT-102 | CT-L09-E-009
CT-L09-E-009-FB | L09 | CT-L09-E-009-FB | L09 | East | Curtain wall | 1400 | 50 | Blue-grey concept glass | CT-102 | CT-L09-E-009
CT-L09-E-009-FT | L09 | CT-L09-E-009-FT | L09 | East | Curtain wall | 1400 | 50 | Blue-grey concept glass | CT-102 | CT-L09-E-009
CT-L09-E-010-ML | L09 | CT-L09-E-010-ML | L09 | East | Metal rainscreen | 50 | 3300 | Olive powder coat | CT-102 | CT-L09-E-010
CT-L09-E-010-MR | L09 | CT-L09-E-010-MR | L09 | East | Metal rainscreen | 50 | 3300 | Olive powder coat | CT-102 | CT-L09-E-010
CT-L09-E-010-FB | L09 | CT-L09-E-010-FB | L09 | East | Metal rainscreen | 1250 | 50 | Olive powder coat | CT-102 | CT-L09-E-010
CT-L09-E-010-FT | L09 | CT-L09-E-010-FT | L09 | East | Metal rainscreen | 1250 | 50 | Olive powder coat | CT-102 | CT-L09-E-010
CT-L09-N-001-ML | L09 | CT-L09-N-001-ML | L09 | North | Curtain wall | 50 | 3300 | Blue-grey concept glass | CT-103 | CT-L09-N-001
CT-L09-N-001-MR | L09 | CT-L09-N-001-MR | L09 | North | Curtain wall | 50 | 3300 | Blue-grey concept glass | CT-103 | CT-L09-N-001
CT-L09-N-001-FB | L09 | CT-L09-N-001-FB | L09 | North | Curtain wall | 1250 | 50 | Blue-grey concept glass | CT-103 | CT-L09-N-001
CT-L09-N-001-FT | L09 | CT-L09-N-001-FT | L09 | North | Curtain wall | 1250 | 50 | Blue-grey concept glass | CT-103 | CT-L09-N-001
CT-L09-N-002-ML | L09 | CT-L09-N-002-ML | L09 | North | Curtain wall | 50 | 3300 | Blue-grey concept glass | CT-103 | CT-L09-N-002
CT-L09-N-002-MR | L09 | CT-L09-N-002-MR | L09 | North | Curtain wall | 50 | 3300 | Blue-grey concept glass | CT-103 | CT-L09-N-002
CT-L09-N-002-FB | L09 | CT-L09-N-002-FB | L09 | North | Curtain wall | 1400 | 50 | Blue-grey concept glass | CT-103 | CT-L09-N-002
CT-L09-N-002-FT | L09 | CT-L09-N-002-FT | L09 | North | Curtain wall | 1400 | 50 | Blue-grey concept glass | CT-103 | CT-L09-N-002
CT-L09-N-003-ML | L09 | CT-L09-N-003-ML | L09 | North | Curtain wall | 50 | 3300 | Blue-grey concept glass | CT-103 | CT-L09-N-003
CT-L09-N-003-MR | L09 | CT-L09-N-003-MR | L09 | North | Curtain wall | 50 | 3300 | Blue-grey concept glass | CT-103 | CT-L09-N-003
CT-L09-N-003-FB | L09 | CT-L09-N-003-FB | L09 | North | Curtain wall | 1400 | 50 | Blue-grey concept glass | CT-103 | CT-L09-N-003
CT-L09-N-003-FT | L09 | CT-L09-N-003-FT | L09 | North | Curtain wall | 1400 | 50 | Blue-grey concept glass | CT-103 | CT-L09-N-003
CT-L09-N-004-ML | L09 | CT-L09-N-004-ML | L09 | North | Curtain wall | 50 | 3300 | Blue-grey concept glass | CT-103 | CT-L09-N-004
CT-L09-N-004-MR | L09 | CT-L09-N-004-MR | L09 | North | Curtain wall | 50 | 3300 | Blue-grey concept glass | CT-103 | CT-L09-N-004
CT-L09-N-004-FB | L09 | CT-L09-N-004-FB | L09 | North | Curtain wall | 1400 | 50 | Blue-grey concept glass | CT-103 | CT-L09-N-004
CT-L09-N-004-FT | L09 | CT-L09-N-004-FT | L09 | North | Curtain wall | 1400 | 50 | Blue-grey concept glass | CT-103 | CT-L09-N-004
CT-L09-N-005-ML | L09 | CT-L09-N-005-ML | L09 | North | Metal rainscreen | 50 | 3300 | Olive powder coat | CT-103 | CT-L09-N-005
CT-L09-N-005-MR | L09 | CT-L09-N-005-MR | L09 | North | Metal rainscreen | 50 | 3300 | Olive powder coat | CT-103 | CT-L09-N-005
CT-L09-N-005-FB | L09 | CT-L09-N-005-FB | L09 | North | Metal rainscreen | 1400 | 50 | Olive powder coat | CT-103 | CT-L09-N-005
CT-L09-N-005-FT | L09 | CT-L09-N-005-FT | L09 | North | Metal rainscreen | 1400 | 50 | Olive powder coat | CT-103 | CT-L09-N-005
CT-L09-N-006-ML | L09 | CT-L09-N-006-ML | L09 | North | Curtain wall | 50 | 3300 | Blue-grey concept glass | CT-103 | CT-L09-N-006
CT-L09-N-006-MR | L09 | CT-L09-N-006-MR | L09 | North | Curtain wall | 50 | 3300 | Blue-grey concept glass | CT-103 | CT-L09-N-006
CT-L09-N-006-FB | L09 | CT-L09-N-006-FB | L09 | North | Curtain wall | 1400 | 50 | Blue-grey concept glass | CT-103 | CT-L09-N-006
CT-L09-N-006-FT | L09 | CT-L09-N-006-FT | L09 | North | Curtain wall | 1400 | 50 | Blue-grey concept glass | CT-103 | CT-L09-N-006
CT-L09-N-007-ML | L09 | CT-L09-N-007-ML | L09 | North | Curtain wall | 50 | 3300 | Blue-grey concept glass | CT-103 | CT-L09-N-007
CT-L09-N-007-MR | L09 | CT-L09-N-007-MR | L09 | North | Curtain wall | 50 | 3300 | Blue-grey concept glass | CT-103 | CT-L09-N-007
CT-L09-N-007-FB | L09 | CT-L09-N-007-FB | L09 | North | Curtain wall | 1400 | 50 | Blue-grey concept glass | CT-103 | CT-L09-N-007
CT-L09-N-007-FT | L09 | CT-L09-N-007-FT | L09 | North | Curtain wall | 1400 | 50 | Blue-grey concept glass | CT-103 | CT-L09-N-007
CT-L09-N-008-ML | L09 | CT-L09-N-008-ML | L09 | North | Curtain wall | 50 | 3300 | Blue-grey concept glass | CT-103 | CT-L09-N-008
CT-L09-N-008-MR | L09 | CT-L09-N-008-MR | L09 | North | Curtain wall | 50 | 3300 | Blue-grey concept glass | CT-103 | CT-L09-N-008
CT-L09-N-008-FB | L09 | CT-L09-N-008-FB | L09 | North | Curtain wall | 1400 | 50 | Blue-grey concept glass | CT-103 | CT-L09-N-008
CT-L09-N-008-FT | L09 | CT-L09-N-008-FT | L09 | North | Curtain wall | 1400 | 50 | Blue-grey concept glass | CT-103 | CT-L09-N-008
CT-L09-N-009-ML | L09 | CT-L09-N-009-ML | L09 | North | Curtain wall | 50 | 3300 | Blue-grey concept glass | CT-103 | CT-L09-N-009
CT-L09-N-009-MR | L09 | CT-L09-N-009-MR | L09 | North | Curtain wall | 50 | 3300 | Blue-grey concept glass | CT-103 | CT-L09-N-009
CT-L09-N-009-FB | L09 | CT-L09-N-009-FB | L09 | North | Curtain wall | 1400 | 50 | Blue-grey concept glass | CT-103 | CT-L09-N-009
CT-L09-N-009-FT | L09 | CT-L09-N-009-FT | L09 | North | Curtain wall | 1400 | 50 | Blue-grey concept glass | CT-103 | CT-L09-N-009
CT-L09-N-010-ML | L09 | CT-L09-N-010-ML | L09 | North | Metal rainscreen | 50 | 3300 | Olive powder coat | CT-103 | CT-L09-N-010
CT-L09-N-010-MR | L09 | CT-L09-N-010-MR | L09 | North | Metal rainscreen | 50 | 3300 | Olive powder coat | CT-103 | CT-L09-N-010
CT-L09-N-010-FB | L09 | CT-L09-N-010-FB | L09 | North | Metal rainscreen | 1400 | 50 | Olive powder coat | CT-103 | CT-L09-N-010
CT-L09-N-010-FT | L09 | CT-L09-N-010-FT | L09 | North | Metal rainscreen | 1400 | 50 | Olive powder coat | CT-103 | CT-L09-N-010
CT-L09-N-011-ML | L09 | CT-L09-N-011-ML | L09 | North | Curtain wall | 50 | 3300 | Blue-grey concept glass | CT-103 | CT-L09-N-011
CT-L09-N-011-MR | L09 | CT-L09-N-011-MR | L09 | North | Curtain wall | 50 | 3300 | Blue-grey concept glass | CT-103 | CT-L09-N-011
CT-L09-N-011-FB | L09 | CT-L09-N-011-FB | L09 | North | Curtain wall | 1400 | 50 | Blue-grey concept glass | CT-103 | CT-L09-N-011
CT-L09-N-011-FT | L09 | CT-L09-N-011-FT | L09 | North | Curtain wall | 1400 | 50 | Blue-grey concept glass | CT-103 | CT-L09-N-011
CT-L09-N-012-ML | L09 | CT-L09-N-012-ML | L09 | North | Curtain wall | 50 | 3300 | Blue-grey concept glass | CT-103 | CT-L09-N-012
CT-L09-N-012-MR | L09 | CT-L09-N-012-MR | L09 | North | Curtain wall | 50 | 3300 | Blue-grey concept glass | CT-103 | CT-L09-N-012
CT-L09-N-012-FB | L09 | CT-L09-N-012-FB | L09 | North | Curtain wall | 1400 | 50 | Blue-grey concept glass | CT-103 | CT-L09-N-012
CT-L09-N-012-FT | L09 | CT-L09-N-012-FT | L09 | North | Curtain wall | 1400 | 50 | Blue-grey concept glass | CT-103 | CT-L09-N-012
CT-L09-N-013-ML | L09 | CT-L09-N-013-ML | L09 | North | Curtain wall | 50 | 3300 | Blue-grey concept glass | CT-103 | CT-L09-N-013
CT-L09-N-013-MR | L09 | CT-L09-N-013-MR | L09 | North | Curtain wall | 50 | 3300 | Blue-grey concept glass | CT-103 | CT-L09-N-013
CT-L09-N-013-FB | L09 | CT-L09-N-013-FB | L09 | North | Curtain wall | 1400 | 50 | Blue-grey concept glass | CT-103 | CT-L09-N-013
CT-L09-N-013-FT | L09 | CT-L09-N-013-FT | L09 | North | Curtain wall | 1400 | 50 | Blue-grey concept glass | CT-103 | CT-L09-N-013
CT-L09-N-014-ML | L09 | CT-L09-N-014-ML | L09 | North | Curtain wall | 50 | 3300 | Blue-grey concept glass | CT-103 | CT-L09-N-014
CT-L09-N-014-MR | L09 | CT-L09-N-014-MR | L09 | North | Curtain wall | 50 | 3300 | Blue-grey concept glass | CT-103 | CT-L09-N-014
CT-L09-N-014-FB | L09 | CT-L09-N-014-FB | L09 | North | Curtain wall | 1250 | 50 | Blue-grey concept glass | CT-103 | CT-L09-N-014
CT-L09-N-014-FT | L09 | CT-L09-N-014-FT | L09 | North | Curtain wall | 1250 | 50 | Blue-grey concept glass | CT-103 | CT-L09-N-014
CT-L09-W-001-ML | L09 | CT-L09-W-001-ML | L09 | West | Curtain wall | 50 | 3300 | Blue-grey concept glass | CT-104 | CT-L09-W-001
CT-L09-W-001-MR | L09 | CT-L09-W-001-MR | L09 | West | Curtain wall | 50 | 3300 | Blue-grey concept glass | CT-104 | CT-L09-W-001
CT-L09-W-001-FB | L09 | CT-L09-W-001-FB | L09 | West | Curtain wall | 1250 | 50 | Blue-grey concept glass | CT-104 | CT-L09-W-001
CT-L09-W-001-FT | L09 | CT-L09-W-001-FT | L09 | West | Curtain wall | 1250 | 50 | Blue-grey concept glass | CT-104 | CT-L09-W-001
CT-L09-W-002-ML | L09 | CT-L09-W-002-ML | L09 | West | Curtain wall | 50 | 3300 | Blue-grey concept glass | CT-104 | CT-L09-W-002
CT-L09-W-002-MR | L09 | CT-L09-W-002-MR | L09 | West | Curtain wall | 50 | 3300 | Blue-grey concept glass | CT-104 | CT-L09-W-002
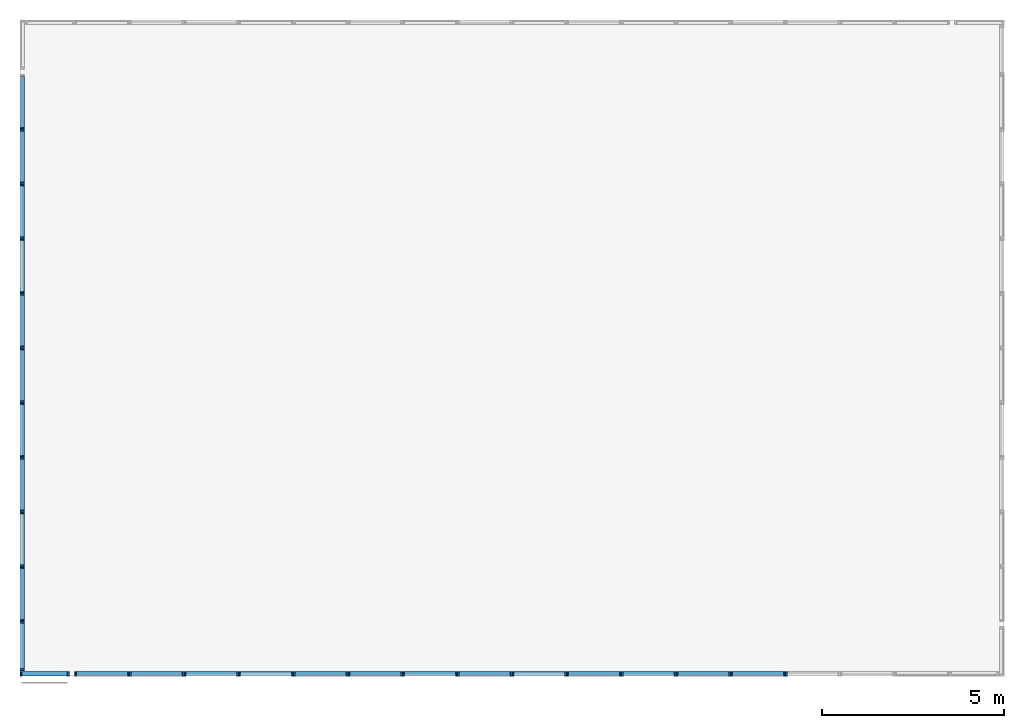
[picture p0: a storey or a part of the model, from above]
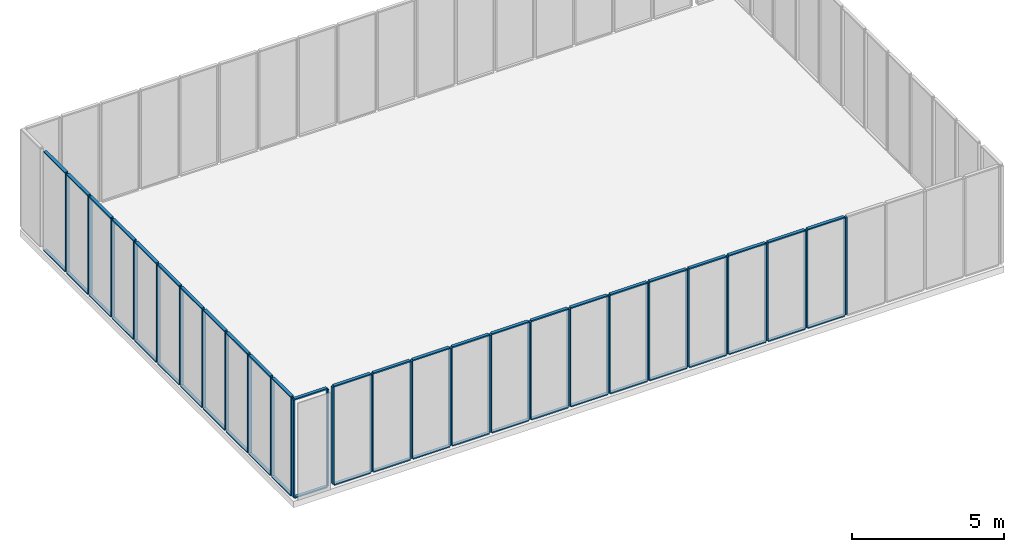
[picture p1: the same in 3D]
Properties of the parts of a building model (IFC4), part 5 of 7

# IfcMember (2304)
Name | In | ElementID | Floor | Elevation | System = Group | Width_mm | Height_mm | Finish | DrawingRef | ParentPanelID
CT-L09-W-002-FB | L09 | CT-L09-W-002-FB | L09 | West | Curtain wall | 1400 | 50 | Blue-grey concept glass | CT-104 | CT-L09-W-002
CT-L09-W-002-FT | L09 | CT-L09-W-002-FT | L09 | West | Curtain wall | 1400 | 50 | Blue-grey concept glass | CT-104 | CT-L09-W-002
CT-L09-W-003-ML | L09 | CT-L09-W-003-ML | L09 | West | Curtain wall | 50 | 3300 | Blue-grey concept glass | CT-104 | CT-L09-W-003
CT-L09-W-003-MR | L09 | CT-L09-W-003-MR | L09 | West | Curtain wall | 50 | 3300 | Blue-grey concept glass | CT-104 | CT-L09-W-003
CT-L09-W-003-FB | L09 | CT-L09-W-003-FB | L09 | West | Curtain wall | 1400 | 50 | Blue-grey concept glass | CT-104 | CT-L09-W-003
CT-L09-W-003-FT | L09 | CT-L09-W-003-FT | L09 | West | Curtain wall | 1400 | 50 | Blue-grey concept glass | CT-104 | CT-L09-W-003
CT-L09-W-004-ML | L09 | CT-L09-W-004-ML | L09 | West | Curtain wall | 50 | 3300 | Blue-grey concept glass | CT-104 | CT-L09-W-004
CT-L09-W-004-MR | L09 | CT-L09-W-004-MR | L09 | West | Curtain wall | 50 | 3300 | Blue-grey concept glass | CT-104 | CT-L09-W-004
CT-L09-W-004-FB | L09 | CT-L09-W-004-FB | L09 | West | Curtain wall | 1400 | 50 | Blue-grey concept glass | CT-104 | CT-L09-W-004
CT-L09-W-004-FT | L09 | CT-L09-W-004-FT | L09 | West | Curtain wall | 1400 | 50 | Blue-grey concept glass | CT-104 | CT-L09-W-004
CT-L09-W-005-ML | L09 | CT-L09-W-005-ML | L09 | West | Metal rainscreen | 50 | 3300 | Olive powder coat | CT-104 | CT-L09-W-005
CT-L09-W-005-MR | L09 | CT-L09-W-005-MR | L09 | West | Metal rainscreen | 50 | 3300 | Olive powder coat | CT-104 | CT-L09-W-005
CT-L09-W-005-FB | L09 | CT-L09-W-005-FB | L09 | West | Metal rainscreen | 1400 | 50 | Olive powder coat | CT-104 | CT-L09-W-005
CT-L09-W-005-FT | L09 | CT-L09-W-005-FT | L09 | West | Metal rainscreen | 1400 | 50 | Olive powder coat | CT-104 | CT-L09-W-005
CT-L09-W-006-ML | L09 | CT-L09-W-006-ML | L09 | West | Curtain wall | 50 | 3300 | Blue-grey concept glass | CT-104 | CT-L09-W-006
CT-L09-W-006-MR | L09 | CT-L09-W-006-MR | L09 | West | Curtain wall | 50 | 3300 | Blue-grey concept glass | CT-104 | CT-L09-W-006
CT-L09-W-006-FB | L09 | CT-L09-W-006-FB | L09 | West | Curtain wall | 1400 | 50 | Blue-grey concept glass | CT-104 | CT-L09-W-006
CT-L09-W-006-FT | L09 | CT-L09-W-006-FT | L09 | West | Curtain wall | 1400 | 50 | Blue-grey concept glass | CT-104 | CT-L09-W-006
CT-L09-W-007-ML | L09 | CT-L09-W-007-ML | L09 | West | Curtain wall | 50 | 3300 | Blue-grey concept glass | CT-104 | CT-L09-W-007
CT-L09-W-007-MR | L09 | CT-L09-W-007-MR | L09 | West | Curtain wall | 50 | 3300 | Blue-grey concept glass | CT-104 | CT-L09-W-007
CT-L09-W-007-FB | L09 | CT-L09-W-007-FB | L09 | West | Curtain wall | 1400 | 50 | Blue-grey concept glass | CT-104 | CT-L09-W-007
CT-L09-W-007-FT | L09 | CT-L09-W-007-FT | L09 | West | Curtain wall | 1400 | 50 | Blue-grey concept glass | CT-104 | CT-L09-W-007
CT-L09-W-008-ML | L09 | CT-L09-W-008-ML | L09 | West | Curtain wall | 50 | 3300 | Blue-grey concept glass | CT-104 | CT-L09-W-008
CT-L09-W-008-MR | L09 | CT-L09-W-008-MR | L09 | West | Curtain wall | 50 | 3300 | Blue-grey concept glass | CT-104 | CT-L09-W-008
CT-L09-W-008-FB | L09 | CT-L09-W-008-FB | L09 | West | Curtain wall | 1400 | 50 | Blue-grey concept glass | CT-104 | CT-L09-W-008
CT-L09-W-008-FT | L09 | CT-L09-W-008-FT | L09 | West | Curtain wall | 1400 | 50 | Blue-grey concept glass | CT-104 | CT-L09-W-008
CT-L09-W-009-ML | L09 | CT-L09-W-009-ML | L09 | West | Curtain wall | 50 | 3300 | Blue-grey concept glass | CT-104 | CT-L09-W-009
CT-L09-W-009-MR | L09 | CT-L09-W-009-MR | L09 | West | Curtain wall | 50 | 3300 | Blue-grey concept glass | CT-104 | CT-L09-W-009
CT-L09-W-009-FB | L09 | CT-L09-W-009-FB | L09 | West | Curtain wall | 1400 | 50 | Blue-grey concept glass | CT-104 | CT-L09-W-009
CT-L09-W-009-FT | L09 | CT-L09-W-009-FT | L09 | West | Curtain wall | 1400 | 50 | Blue-grey concept glass | CT-104 | CT-L09-W-009
CT-L09-W-010-ML | L09 | CT-L09-W-010-ML | L09 | West | Metal rainscreen | 50 | 3300 | Olive powder coat | CT-104 | CT-L09-W-010
CT-L09-W-010-MR | L09 | CT-L09-W-010-MR | L09 | West | Metal rainscreen | 50 | 3300 | Olive powder coat | CT-104 | CT-L09-W-010
CT-L09-W-010-FB | L09 | CT-L09-W-010-FB | L09 | West | Metal rainscreen | 1250 | 50 | Olive powder coat | CT-104 | CT-L09-W-010
CT-L09-W-010-FT | L09 | CT-L09-W-010-FT | L09 | West | Metal rainscreen | 1250 | 50 | Olive powder coat | CT-104 | CT-L09-W-010
CT-L10-S-001-ML | L10 | CT-L10-S-001-ML | L10 | South | Curtain wall | 50 | 3300 | Blue-grey concept glass | CT-101 | CT-L10-S-001
CT-L10-S-001-MR | L10 | CT-L10-S-001-MR | L10 | South | Curtain wall | 50 | 3300 | Blue-grey concept glass | CT-101 | CT-L10-S-001
CT-L10-S-001-FB | L10 | CT-L10-S-001-FB | L10 | South | Curtain wall | 1250 | 50 | Blue-grey concept glass | CT-101 | CT-L10-S-001
CT-L10-S-001-FT | L10 | CT-L10-S-001-FT | L10 | South | Curtain wall | 1250 | 50 | Blue-grey concept glass | CT-101 | CT-L10-S-001
CT-L10-S-002-ML | L10 | CT-L10-S-002-ML | L10 | South | Curtain wall | 50 | 3300 | Blue-grey concept glass | CT-101 | CT-L10-S-002
CT-L10-S-002-MR | L10 | CT-L10-S-002-MR | L10 | South | Curtain wall | 50 | 3300 | Blue-grey concept glass | CT-101 | CT-L10-S-002
CT-L10-S-002-FB | L10 | CT-L10-S-002-FB | L10 | South | Curtain wall | 1400 | 50 | Blue-grey concept glass | CT-101 | CT-L10-S-002
CT-L10-S-002-FT | L10 | CT-L10-S-002-FT | L10 | South | Curtain wall | 1400 | 50 | Blue-grey concept glass | CT-101 | CT-L10-S-002
CT-L10-S-003-ML | L10 | CT-L10-S-003-ML | L10 | South | Curtain wall | 50 | 3300 | Blue-grey concept glass | CT-101 | CT-L10-S-003
CT-L10-S-003-MR | L10 | CT-L10-S-003-MR | L10 | South | Curtain wall | 50 | 3300 | Blue-grey concept glass | CT-101 | CT-L10-S-003
CT-L10-S-003-FB | L10 | CT-L10-S-003-FB | L10 | South | Curtain wall | 1400 | 50 | Blue-grey concept glass | CT-101 | CT-L10-S-003
CT-L10-S-003-FT | L10 | CT-L10-S-003-FT | L10 | South | Curtain wall | 1400 | 50 | Blue-grey concept glass | CT-101 | CT-L10-S-003
CT-L10-S-004-ML | L10 | CT-L10-S-004-ML | L10 | South | Curtain wall | 50 | 3300 | Blue-grey concept glass | CT-101 | CT-L10-S-004
CT-L10-S-004-MR | L10 | CT-L10-S-004-MR | L10 | South | Curtain wall | 50 | 3300 | Blue-grey concept glass | CT-101 | CT-L10-S-004
CT-L10-S-004-FB | L10 | CT-L10-S-004-FB | L10 | South | Curtain wall | 1400 | 50 | Blue-grey concept glass | CT-101 | CT-L10-S-004
CT-L10-S-004-FT | L10 | CT-L10-S-004-FT | L10 | South | Curtain wall | 1400 | 50 | Blue-grey concept glass | CT-101 | CT-L10-S-004
CT-L10-S-005-ML | L10 | CT-L10-S-005-ML | L10 | South | Metal rainscreen | 50 | 3300 | Olive powder coat | CT-101 | CT-L10-S-005
CT-L10-S-005-MR | L10 | CT-L10-S-005-MR | L10 | South | Metal rainscreen | 50 | 3300 | Olive powder coat | CT-101 | CT-L10-S-005
CT-L10-S-005-FB | L10 | CT-L10-S-005-FB | L10 | South | Metal rainscreen | 1400 | 50 | Olive powder coat | CT-101 | CT-L10-S-005
CT-L10-S-005-FT | L10 | CT-L10-S-005-FT | L10 | South | Metal rainscreen | 1400 | 50 | Olive powder coat | CT-101 | CT-L10-S-005
CT-L10-S-006-ML | L10 | CT-L10-S-006-ML | L10 | South | Curtain wall | 50 | 3300 | Blue-grey concept glass | CT-101 | CT-L10-S-006
CT-L10-S-006-MR | L10 | CT-L10-S-006-MR | L10 | South | Curtain wall | 50 | 3300 | Blue-grey concept glass | CT-101 | CT-L10-S-006
CT-L10-S-006-FB | L10 | CT-L10-S-006-FB | L10 | South | Curtain wall | 1400 | 50 | Blue-grey concept glass | CT-101 | CT-L10-S-006
CT-L10-S-006-FT | L10 | CT-L10-S-006-FT | L10 | South | Curtain wall | 1400 | 50 | Blue-grey concept glass | CT-101 | CT-L10-S-006
CT-L10-S-007-ML | L10 | CT-L10-S-007-ML | L10 | South | Curtain wall | 50 | 3300 | Blue-grey concept glass | CT-101 | CT-L10-S-007
CT-L10-S-007-MR | L10 | CT-L10-S-007-MR | L10 | South | Curtain wall | 50 | 3300 | Blue-grey concept glass | CT-101 | CT-L10-S-007
CT-L10-S-007-FB | L10 | CT-L10-S-007-FB | L10 | South | Curtain wall | 1400 | 50 | Blue-grey concept glass | CT-101 | CT-L10-S-007
CT-L10-S-007-FT | L10 | CT-L10-S-007-FT | L10 | South | Curtain wall | 1400 | 50 | Blue-grey concept glass | CT-101 | CT-L10-S-007
CT-L10-S-008-ML | L10 | CT-L10-S-008-ML | L10 | South | Curtain wall | 50 | 3300 | Blue-grey concept glass | CT-101 | CT-L10-S-008
CT-L10-S-008-MR | L10 | CT-L10-S-008-MR | L10 | South | Curtain wall | 50 | 3300 | Blue-grey concept glass | CT-101 | CT-L10-S-008
CT-L10-S-008-FB | L10 | CT-L10-S-008-FB | L10 | South | Curtain wall | 1400 | 50 | Blue-grey concept glass | CT-101 | CT-L10-S-008
CT-L10-S-008-FT | L10 | CT-L10-S-008-FT | L10 | South | Curtain wall | 1400 | 50 | Blue-grey concept glass | CT-101 | CT-L10-S-008
CT-L10-S-009-ML | L10 | CT-L10-S-009-ML | L10 | South | Curtain wall | 50 | 3300 | Blue-grey concept glass | CT-101 | CT-L10-S-009
CT-L10-S-009-MR | L10 | CT-L10-S-009-MR | L10 | South | Curtain wall | 50 | 3300 | Blue-grey concept glass | CT-101 | CT-L10-S-009
CT-L10-S-009-FB | L10 | CT-L10-S-009-FB | L10 | South | Curtain wall | 1400 | 50 | Blue-grey concept glass | CT-101 | CT-L10-S-009
CT-L10-S-009-FT | L10 | CT-L10-S-009-FT | L10 | South | Curtain wall | 1400 | 50 | Blue-grey concept glass | CT-101 | CT-L10-S-009
CT-L10-S-010-ML | L10 | CT-L10-S-010-ML | L10 | South | Metal rainscreen | 50 | 3300 | Olive powder coat | CT-101 | CT-L10-S-010
CT-L10-S-010-MR | L10 | CT-L10-S-010-MR | L10 | South | Metal rainscreen | 50 | 3300 | Olive powder coat | CT-101 | CT-L10-S-010
CT-L10-S-010-FB | L10 | CT-L10-S-010-FB | L10 | South | Metal rainscreen | 1250 | 50 | Olive powder coat | CT-101 | CT-L10-S-010
CT-L10-S-010-FT | L10 | CT-L10-S-010-FT | L10 | South | Metal rainscreen | 1250 | 50 | Olive powder coat | CT-101 | CT-L10-S-010
CT-L10-E-001-ML | L10 | CT-L10-E-001-ML | L10 | East | Curtain wall | 50 | 3300 | Blue-grey concept glass | CT-102 | CT-L10-E-001
CT-L10-E-001-MR | L10 | CT-L10-E-001-MR | L10 | East | Curtain wall | 50 | 3300 | Blue-grey concept glass | CT-102 | CT-L10-E-001
CT-L10-E-001-FB | L10 | CT-L10-E-001-FB | L10 | East | Curtain wall | 1250 | 50 | Blue-grey concept glass | CT-102 | CT-L10-E-001
CT-L10-E-001-FT | L10 | CT-L10-E-001-FT | L10 | East | Curtain wall | 1250 | 50 | Blue-grey concept glass | CT-102 | CT-L10-E-001
CT-L10-E-002-ML | L10 | CT-L10-E-002-ML | L10 | East | Curtain wall | 50 | 3300 | Blue-grey concept glass | CT-102 | CT-L10-E-002
CT-L10-E-002-MR | L10 | CT-L10-E-002-MR | L10 | East | Curtain wall | 50 | 3300 | Blue-grey concept glass | CT-102 | CT-L10-E-002
CT-L10-E-002-FB | L10 | CT-L10-E-002-FB | L10 | East | Curtain wall | 1400 | 50 | Blue-grey concept glass | CT-102 | CT-L10-E-002
CT-L10-E-002-FT | L10 | CT-L10-E-002-FT | L10 | East | Curtain wall | 1400 | 50 | Blue-grey concept glass | CT-102 | CT-L10-E-002
CT-L10-E-003-ML | L10 | CT-L10-E-003-ML | L10 | East | Curtain wall | 50 | 3300 | Blue-grey concept glass | CT-102 | CT-L10-E-003
CT-L10-E-003-MR | L10 | CT-L10-E-003-MR | L10 | East | Curtain wall | 50 | 3300 | Blue-grey concept glass | CT-102 | CT-L10-E-003
CT-L10-E-003-FB | L10 | CT-L10-E-003-FB | L10 | East | Curtain wall | 1400 | 50 | Blue-grey concept glass | CT-102 | CT-L10-E-003
CT-L10-E-003-FT | L10 | CT-L10-E-003-FT | L10 | East | Curtain wall | 1400 | 50 | Blue-grey concept glass | CT-102 | CT-L10-E-003
CT-L10-E-004-ML | L10 | CT-L10-E-004-ML | L10 | East | Curtain wall | 50 | 3300 | Blue-grey concept glass | CT-102 | CT-L10-E-004
CT-L10-E-004-MR | L10 | CT-L10-E-004-MR | L10 | East | Curtain wall | 50 | 3300 | Blue-grey concept glass | CT-102 | CT-L10-E-004
CT-L10-E-004-FB | L10 | CT-L10-E-004-FB | L10 | East | Curtain wall | 1400 | 50 | Blue-grey concept glass | CT-102 | CT-L10-E-004
CT-L10-E-004-FT | L10 | CT-L10-E-004-FT | L10 | East | Curtain wall | 1400 | 50 | Blue-grey concept glass | CT-102 | CT-L10-E-004
CT-L10-E-005-ML | L10 | CT-L10-E-005-ML | L10 | East | Metal rainscreen | 50 | 3300 | Olive powder coat | CT-102 | CT-L10-E-005
CT-L10-E-005-MR | L10 | CT-L10-E-005-MR | L10 | East | Metal rainscreen | 50 | 3300 | Olive powder coat | CT-102 | CT-L10-E-005
CT-L10-E-005-FB | L10 | CT-L10-E-005-FB | L10 | East | Metal rainscreen | 1400 | 50 | Olive powder coat | CT-102 | CT-L10-E-005
CT-L10-E-005-FT | L10 | CT-L10-E-005-FT | L10 | East | Metal rainscreen | 1400 | 50 | Olive powder coat | CT-102 | CT-L10-E-005
CT-L10-E-006-ML | L10 | CT-L10-E-006-ML | L10 | East | Curtain wall | 50 | 3300 | Blue-grey concept glass | CT-102 | CT-L10-E-006
CT-L10-E-006-MR | L10 | CT-L10-E-006-MR | L10 | East | Curtain wall | 50 | 3300 | Blue-grey concept glass | CT-102 | CT-L10-E-006
CT-L10-E-006-FB | L10 | CT-L10-E-006-FB | L10 | East | Curtain wall | 1400 | 50 | Blue-grey concept glass | CT-102 | CT-L10-E-006
CT-L10-E-006-FT | L10 | CT-L10-E-006-FT | L10 | East | Curtain wall | 1400 | 50 | Blue-grey concept glass | CT-102 | CT-L10-E-006
CT-L10-E-007-ML | L10 | CT-L10-E-007-ML | L10 | East | Curtain wall | 50 | 3300 | Blue-grey concept glass | CT-102 | CT-L10-E-007
CT-L10-E-007-MR | L10 | CT-L10-E-007-MR | L10 | East | Curtain wall | 50 | 3300 | Blue-grey concept glass | CT-102 | CT-L10-E-007
CT-L10-E-007-FB | L10 | CT-L10-E-007-FB | L10 | East | Curtain wall | 1400 | 50 | Blue-grey concept glass | CT-102 | CT-L10-E-007
CT-L10-E-007-FT | L10 | CT-L10-E-007-FT | L10 | East | Curtain wall | 1400 | 50 | Blue-grey concept glass | CT-102 | CT-L10-E-007
CT-L10-E-008-ML | L10 | CT-L10-E-008-ML | L10 | East | Curtain wall | 50 | 3300 | Blue-grey concept glass | CT-102 | CT-L10-E-008
CT-L10-E-008-MR | L10 | CT-L10-E-008-MR | L10 | East | Curtain wall | 50 | 3300 | Blue-grey concept glass | CT-102 | CT-L10-E-008
CT-L10-E-008-FB | L10 | CT-L10-E-008-FB | L10 | East | Curtain wall | 1250 | 50 | Blue-grey concept glass | CT-102 | CT-L10-E-008
CT-L10-E-008-FT | L10 | CT-L10-E-008-FT | L10 | East | Curtain wall | 1250 | 50 | Blue-grey concept glass | CT-102 | CT-L10-E-008
CT-L10-N-001-ML | L10 | CT-L10-N-001-ML | L10 | North | Curtain wall | 50 | 3300 | Blue-grey concept glass | CT-103 | CT-L10-N-001
CT-L10-N-001-MR | L10 | CT-L10-N-001-MR | L10 | North | Curtain wall | 50 | 3300 | Blue-grey concept glass | CT-103 | CT-L10-N-001
CT-L10-N-001-FB | L10 | CT-L10-N-001-FB | L10 | North | Curtain wall | 1250 | 50 | Blue-grey concept glass | CT-103 | CT-L10-N-001
CT-L10-N-001-FT | L10 | CT-L10-N-001-FT | L10 | North | Curtain wall | 1250 | 50 | Blue-grey concept glass | CT-103 | CT-L10-N-001
CT-L10-N-002-ML | L10 | CT-L10-N-002-ML | L10 | North | Curtain wall | 50 | 3300 | Blue-grey concept glass | CT-103 | CT-L10-N-002
CT-L10-N-002-MR | L10 | CT-L10-N-002-MR | L10 | North | Curtain wall | 50 | 3300 | Blue-grey concept glass | CT-103 | CT-L10-N-002
CT-L10-N-002-FB | L10 | CT-L10-N-002-FB | L10 | North | Curtain wall | 1400 | 50 | Blue-grey concept glass | CT-103 | CT-L10-N-002
CT-L10-N-002-FT | L10 | CT-L10-N-002-FT | L10 | North | Curtain wall | 1400 | 50 | Blue-grey concept glass | CT-103 | CT-L10-N-002
CT-L10-N-003-ML | L10 | CT-L10-N-003-ML | L10 | North | Curtain wall | 50 | 3300 | Blue-grey concept glass | CT-103 | CT-L10-N-003
CT-L10-N-003-MR | L10 | CT-L10-N-003-MR | L10 | North | Curtain wall | 50 | 3300 | Blue-grey concept glass | CT-103 | CT-L10-N-003
CT-L10-N-003-FB | L10 | CT-L10-N-003-FB | L10 | North | Curtain wall | 1400 | 50 | Blue-grey concept glass | CT-103 | CT-L10-N-003
CT-L10-N-003-FT | L10 | CT-L10-N-003-FT | L10 | North | Curtain wall | 1400 | 50 | Blue-grey concept glass | CT-103 | CT-L10-N-003
CT-L10-N-004-ML | L10 | CT-L10-N-004-ML | L10 | North | Curtain wall | 50 | 3300 | Blue-grey concept glass | CT-103 | CT-L10-N-004
CT-L10-N-004-MR | L10 | CT-L10-N-004-MR | L10 | North | Curtain wall | 50 | 3300 | Blue-grey concept glass | CT-103 | CT-L10-N-004
CT-L10-N-004-FB | L10 | CT-L10-N-004-FB | L10 | North | Curtain wall | 1400 | 50 | Blue-grey concept glass | CT-103 | CT-L10-N-004
CT-L10-N-004-FT | L10 | CT-L10-N-004-FT | L10 | North | Curtain wall | 1400 | 50 | Blue-grey concept glass | CT-103 | CT-L10-N-004
CT-L10-N-005-ML | L10 | CT-L10-N-005-ML | L10 | North | Metal rainscreen | 50 | 3300 | Olive powder coat | CT-103 | CT-L10-N-005
CT-L10-N-005-MR | L10 | CT-L10-N-005-MR | L10 | North | Metal rainscreen | 50 | 3300 | Olive powder coat | CT-103 | CT-L10-N-005
CT-L10-N-005-FB | L10 | CT-L10-N-005-FB | L10 | North | Metal rainscreen | 1400 | 50 | Olive powder coat | CT-103 | CT-L10-N-005
CT-L10-N-005-FT | L10 | CT-L10-N-005-FT | L10 | North | Metal rainscreen | 1400 | 50 | Olive powder coat | CT-103 | CT-L10-N-005
CT-L10-N-006-ML | L10 | CT-L10-N-006-ML | L10 | North | Curtain wall | 50 | 3300 | Blue-grey concept glass | CT-103 | CT-L10-N-006
CT-L10-N-006-MR | L10 | CT-L10-N-006-MR | L10 | North | Curtain wall | 50 | 3300 | Blue-grey concept glass | CT-103 | CT-L10-N-006
CT-L10-N-006-FB | L10 | CT-L10-N-006-FB | L10 | North | Curtain wall | 1400 | 50 | Blue-grey concept glass | CT-103 | CT-L10-N-006
CT-L10-N-006-FT | L10 | CT-L10-N-006-FT | L10 | North | Curtain wall | 1400 | 50 | Blue-grey concept glass | CT-103 | CT-L10-N-006
CT-L10-N-007-ML | L10 | CT-L10-N-007-ML | L10 | North | Curtain wall | 50 | 3300 | Blue-grey concept glass | CT-103 | CT-L10-N-007
CT-L10-N-007-MR | L10 | CT-L10-N-007-MR | L10 | North | Curtain wall | 50 | 3300 | Blue-grey concept glass | CT-103 | CT-L10-N-007
CT-L10-N-007-FB | L10 | CT-L10-N-007-FB | L10 | North | Curtain wall | 1400 | 50 | Blue-grey concept glass | CT-103 | CT-L10-N-007
CT-L10-N-007-FT | L10 | CT-L10-N-007-FT | L10 | North | Curtain wall | 1400 | 50 | Blue-grey concept glass | CT-103 | CT-L10-N-007
CT-L10-N-008-ML | L10 | CT-L10-N-008-ML | L10 | North | Curtain wall | 50 | 3300 | Blue-grey concept glass | CT-103 | CT-L10-N-008
CT-L10-N-008-MR | L10 | CT-L10-N-008-MR | L10 | North | Curtain wall | 50 | 3300 | Blue-grey concept glass | CT-103 | CT-L10-N-008
CT-L10-N-008-FB | L10 | CT-L10-N-008-FB | L10 | North | Curtain wall | 1400 | 50 | Blue-grey concept glass | CT-103 | CT-L10-N-008
CT-L10-N-008-FT | L10 | CT-L10-N-008-FT | L10 | North | Curtain wall | 1400 | 50 | Blue-grey concept glass | CT-103 | CT-L10-N-008
CT-L10-N-009-ML | L10 | CT-L10-N-009-ML | L10 | North | Curtain wall | 50 | 3300 | Blue-grey concept glass | CT-103 | CT-L10-N-009
CT-L10-N-009-MR | L10 | CT-L10-N-009-MR | L10 | North | Curtain wall | 50 | 3300 | Blue-grey concept glass | CT-103 | CT-L10-N-009
CT-L10-N-009-FB | L10 | CT-L10-N-009-FB | L10 | North | Curtain wall | 1400 | 50 | Blue-grey concept glass | CT-103 | CT-L10-N-009
CT-L10-N-009-FT | L10 | CT-L10-N-009-FT | L10 | North | Curtain wall | 1400 | 50 | Blue-grey concept glass | CT-103 | CT-L10-N-009
CT-L10-N-010-ML | L10 | CT-L10-N-010-ML | L10 | North | Metal rainscreen | 50 | 3300 | Olive powder coat | CT-103 | CT-L10-N-010
CT-L10-N-010-MR | L10 | CT-L10-N-010-MR | L10 | North | Metal rainscreen | 50 | 3300 | Olive powder coat | CT-103 | CT-L10-N-010
CT-L10-N-010-FB | L10 | CT-L10-N-010-FB | L10 | North | Metal rainscreen | 1250 | 50 | Olive powder coat | CT-103 | CT-L10-N-010
CT-L10-N-010-FT | L10 | CT-L10-N-010-FT | L10 | North | Metal rainscreen | 1250 | 50 | Olive powder coat | CT-103 | CT-L10-N-010
CT-L10-W-001-ML | L10 | CT-L10-W-001-ML | L10 | West | Curtain wall | 50 | 3300 | Blue-grey concept glass | CT-104 | CT-L10-W-001
CT-L10-W-001-MR | L10 | CT-L10-W-001-MR | L10 | West | Curtain wall | 50 | 3300 | Blue-grey concept glass | CT-104 | CT-L10-W-001
CT-L10-W-001-FB | L10 | CT-L10-W-001-FB | L10 | West | Curtain wall | 1250 | 50 | Blue-grey concept glass | CT-104 | CT-L10-W-001
CT-L10-W-001-FT | L10 | CT-L10-W-001-FT | L10 | West | Curtain wall | 1250 | 50 | Blue-grey concept glass | CT-104 | CT-L10-W-001
CT-L10-W-002-ML | L10 | CT-L10-W-002-ML | L10 | West | Curtain wall | 50 | 3300 | Blue-grey concept glass | CT-104 | CT-L10-W-002
CT-L10-W-002-MR | L10 | CT-L10-W-002-MR | L10 | West | Curtain wall | 50 | 3300 | Blue-grey concept glass | CT-104 | CT-L10-W-002
CT-L10-W-002-FB | L10 | CT-L10-W-002-FB | L10 | West | Curtain wall | 1400 | 50 | Blue-grey concept glass | CT-104 | CT-L10-W-002
CT-L10-W-002-FT | L10 | CT-L10-W-002-FT | L10 | West | Curtain wall | 1400 | 50 | Blue-grey concept glass | CT-104 | CT-L10-W-002
CT-L10-W-003-ML | L10 | CT-L10-W-003-ML | L10 | West | Curtain wall | 50 | 3300 | Blue-grey concept glass | CT-104 | CT-L10-W-003
CT-L10-W-003-MR | L10 | CT-L10-W-003-MR | L10 | West | Curtain wall | 50 | 3300 | Blue-grey concept glass | CT-104 | CT-L10-W-003
CT-L10-W-003-FB | L10 | CT-L10-W-003-FB | L10 | West | Curtain wall | 1400 | 50 | Blue-grey concept glass | CT-104 | CT-L10-W-003
CT-L10-W-003-FT | L10 | CT-L10-W-003-FT | L10 | West | Curtain wall | 1400 | 50 | Blue-grey concept glass | CT-104 | CT-L10-W-003
CT-L10-W-004-ML | L10 | CT-L10-W-004-ML | L10 | West | Curtain wall | 50 | 3300 | Blue-grey concept glass | CT-104 | CT-L10-W-004
CT-L10-W-004-MR | L10 | CT-L10-W-004-MR | L10 | West | Curtain wall | 50 | 3300 | Blue-grey concept glass | CT-104 | CT-L10-W-004
CT-L10-W-004-FB | L10 | CT-L10-W-004-FB | L10 | West | Curtain wall | 1400 | 50 | Blue-grey concept glass | CT-104 | CT-L10-W-004
CT-L10-W-004-FT | L10 | CT-L10-W-004-FT | L10 | West | Curtain wall | 1400 | 50 | Blue-grey concept glass | CT-104 | CT-L10-W-004
CT-L10-W-005-ML | L10 | CT-L10-W-005-ML | L10 | West | Metal rainscreen | 50 | 3300 | Olive powder coat | CT-104 | CT-L10-W-005
CT-L10-W-005-MR | L10 | CT-L10-W-005-MR | L10 | West | Metal rainscreen | 50 | 3300 | Olive powder coat | CT-104 | CT-L10-W-005
CT-L10-W-005-FB | L10 | CT-L10-W-005-FB | L10 | West | Metal rainscreen | 1400 | 50 | Olive powder coat | CT-104 | CT-L10-W-005
CT-L10-W-005-FT | L10 | CT-L10-W-005-FT | L10 | West | Metal rainscreen | 1400 | 50 | Olive powder coat | CT-104 | CT-L10-W-005
CT-L10-W-006-ML | L10 | CT-L10-W-006-ML | L10 | West | Curtain wall | 50 | 3300 | Blue-grey concept glass | CT-104 | CT-L10-W-006
CT-L10-W-006-MR | L10 | CT-L10-W-006-MR | L10 | West | Curtain wall | 50 | 3300 | Blue-grey concept glass | CT-104 | CT-L10-W-006
CT-L10-W-006-FB | L10 | CT-L10-W-006-FB | L10 | West | Curtain wall | 1400 | 50 | Blue-grey concept glass | CT-104 | CT-L10-W-006
CT-L10-W-006-FT | L10 | CT-L10-W-006-FT | L10 | West | Curtain wall | 1400 | 50 | Blue-grey concept glass | CT-104 | CT-L10-W-006
CT-L10-W-007-ML | L10 | CT-L10-W-007-ML | L10 | West | Curtain wall | 50 | 3300 | Blue-grey concept glass | CT-104 | CT-L10-W-007
CT-L10-W-007-MR | L10 | CT-L10-W-007-MR | L10 | West | Curtain wall | 50 | 3300 | Blue-grey concept glass | CT-104 | CT-L10-W-007
CT-L10-W-007-FB | L10 | CT-L10-W-007-FB | L10 | West | Curtain wall | 1400 | 50 | Blue-grey concept glass | CT-104 | CT-L10-W-007
CT-L10-W-007-FT | L10 | CT-L10-W-007-FT | L10 | West | Curtain wall | 1400 | 50 | Blue-grey concept glass | CT-104 | CT-L10-W-007
CT-L10-W-008-ML | L10 | CT-L10-W-008-ML | L10 | West | Curtain wall | 50 | 3300 | Blue-grey concept glass | CT-104 | CT-L10-W-008
CT-L10-W-008-MR | L10 | CT-L10-W-008-MR | L10 | West | Curtain wall | 50 | 3300 | Blue-grey concept glass | CT-104 | CT-L10-W-008
CT-L10-W-008-FB | L10 | CT-L10-W-008-FB | L10 | West | Curtain wall | 1250 | 50 | Blue-grey concept glass | CT-104 | CT-L10-W-008
CT-L10-W-008-FT | L10 | CT-L10-W-008-FT | L10 | West | Curtain wall | 1250 | 50 | Blue-grey concept glass | CT-104 | CT-L10-W-008
CT-L11-S-001-ML | L11 | CT-L11-S-001-ML | L11 | South | Curtain wall | 50 | 3300 | Blue-grey concept glass | CT-101 | CT-L11-S-001
CT-L11-S-001-MR | L11 | CT-L11-S-001-MR | L11 | South | Curtain wall | 50 | 3300 | Blue-grey concept glass | CT-101 | CT-L11-S-001
CT-L11-S-001-FB | L11 | CT-L11-S-001-FB | L11 | South | Curtain wall | 1250 | 50 | Blue-grey concept glass | CT-101 | CT-L11-S-001
CT-L11-S-001-FT | L11 | CT-L11-S-001-FT | L11 | South | Curtain wall | 1250 | 50 | Blue-grey concept glass | CT-101 | CT-L11-S-001
CT-L11-S-002-ML | L11 | CT-L11-S-002-ML | L11 | South | Curtain wall | 50 | 3300 | Blue-grey concept glass | CT-101 | CT-L11-S-002
CT-L11-S-002-MR | L11 | CT-L11-S-002-MR | L11 | South | Curtain wall | 50 | 3300 | Blue-grey concept glass | CT-101 | CT-L11-S-002
CT-L11-S-002-FB | L11 | CT-L11-S-002-FB | L11 | South | Curtain wall | 1400 | 50 | Blue-grey concept glass | CT-101 | CT-L11-S-002
CT-L11-S-002-FT | L11 | CT-L11-S-002-FT | L11 | South | Curtain wall | 1400 | 50 | Blue-grey concept glass | CT-101 | CT-L11-S-002
CT-L11-S-003-ML | L11 | CT-L11-S-003-ML | L11 | South | Curtain wall | 50 | 3300 | Blue-grey concept glass | CT-101 | CT-L11-S-003
CT-L11-S-003-MR | L11 | CT-L11-S-003-MR | L11 | South | Curtain wall | 50 | 3300 | Blue-grey concept glass | CT-101 | CT-L11-S-003
CT-L11-S-003-FB | L11 | CT-L11-S-003-FB | L11 | South | Curtain wall | 1400 | 50 | Blue-grey concept glass | CT-101 | CT-L11-S-003
CT-L11-S-003-FT | L11 | CT-L11-S-003-FT | L11 | South | Curtain wall | 1400 | 50 | Blue-grey concept glass | CT-101 | CT-L11-S-003
CT-L11-S-004-ML | L11 | CT-L11-S-004-ML | L11 | South | Curtain wall | 50 | 3300 | Blue-grey concept glass | CT-101 | CT-L11-S-004
CT-L11-S-004-MR | L11 | CT-L11-S-004-MR | L11 | South | Curtain wall | 50 | 3300 | Blue-grey concept glass | CT-101 | CT-L11-S-004
CT-L11-S-004-FB | L11 | CT-L11-S-004-FB | L11 | South | Curtain wall | 1400 | 50 | Blue-grey concept glass | CT-101 | CT-L11-S-004
CT-L11-S-004-FT | L11 | CT-L11-S-004-FT | L11 | South | Curtain wall | 1400 | 50 | Blue-grey concept glass | CT-101 | CT-L11-S-004
CT-L11-S-005-ML | L11 | CT-L11-S-005-ML | L11 | South | Metal rainscreen | 50 | 3300 | Olive powder coat | CT-101 | CT-L11-S-005
CT-L11-S-005-MR | L11 | CT-L11-S-005-MR | L11 | South | Metal rainscreen | 50 | 3300 | Olive powder coat | CT-101 | CT-L11-S-005
CT-L11-S-005-FB | L11 | CT-L11-S-005-FB | L11 | South | Metal rainscreen | 1400 | 50 | Olive powder coat | CT-101 | CT-L11-S-005
CT-L11-S-005-FT | L11 | CT-L11-S-005-FT | L11 | South | Metal rainscreen | 1400 | 50 | Olive powder coat | CT-101 | CT-L11-S-005
CT-L11-S-006-ML | L11 | CT-L11-S-006-ML | L11 | South | Curtain wall | 50 | 3300 | Blue-grey concept glass | CT-101 | CT-L11-S-006
CT-L11-S-006-MR | L11 | CT-L11-S-006-MR | L11 | South | Curtain wall | 50 | 3300 | Blue-grey concept glass | CT-101 | CT-L11-S-006
CT-L11-S-006-FB | L11 | CT-L11-S-006-FB | L11 | South | Curtain wall | 1400 | 50 | Blue-grey concept glass | CT-101 | CT-L11-S-006
CT-L11-S-006-FT | L11 | CT-L11-S-006-FT | L11 | South | Curtain wall | 1400 | 50 | Blue-grey concept glass | CT-101 | CT-L11-S-006
CT-L11-S-007-ML | L11 | CT-L11-S-007-ML | L11 | South | Curtain wall | 50 | 3300 | Blue-grey concept glass | CT-101 | CT-L11-S-007
CT-L11-S-007-MR | L11 | CT-L11-S-007-MR | L11 | South | Curtain wall | 50 | 3300 | Blue-grey concept glass | CT-101 | CT-L11-S-007
CT-L11-S-007-FB | L11 | CT-L11-S-007-FB | L11 | South | Curtain wall | 1400 | 50 | Blue-grey concept glass | CT-101 | CT-L11-S-007
CT-L11-S-007-FT | L11 | CT-L11-S-007-FT | L11 | South | Curtain wall | 1400 | 50 | Blue-grey concept glass | CT-101 | CT-L11-S-007
CT-L11-S-008-ML | L11 | CT-L11-S-008-ML | L11 | South | Curtain wall | 50 | 3300 | Blue-grey concept glass | CT-101 | CT-L11-S-008
CT-L11-S-008-MR | L11 | CT-L11-S-008-MR | L11 | South | Curtain wall | 50 | 3300 | Blue-grey concept glass | CT-101 | CT-L11-S-008
CT-L11-S-008-FB | L11 | CT-L11-S-008-FB | L11 | South | Curtain wall | 1400 | 50 | Blue-grey concept glass | CT-101 | CT-L11-S-008
CT-L11-S-008-FT | L11 | CT-L11-S-008-FT | L11 | South | Curtain wall | 1400 | 50 | Blue-grey concept glass | CT-101 | CT-L11-S-008
CT-L11-S-009-ML | L11 | CT-L11-S-009-ML | L11 | South | Curtain wall | 50 | 3300 | Blue-grey concept glass | CT-101 | CT-L11-S-009
CT-L11-S-009-MR | L11 | CT-L11-S-009-MR | L11 | South | Curtain wall | 50 | 3300 | Blue-grey concept glass | CT-101 | CT-L11-S-009
CT-L11-S-009-FB | L11 | CT-L11-S-009-FB | L11 | South | Curtain wall | 1400 | 50 | Blue-grey concept glass | CT-101 | CT-L11-S-009
CT-L11-S-009-FT | L11 | CT-L11-S-009-FT | L11 | South | Curtain wall | 1400 | 50 | Blue-grey concept glass | CT-101 | CT-L11-S-009
CT-L11-S-010-ML | L11 | CT-L11-S-010-ML | L11 | South | Metal rainscreen | 50 | 3300 | Olive powder coat | CT-101 | CT-L11-S-010
CT-L11-S-010-MR | L11 | CT-L11-S-010-MR | L11 | South | Metal rainscreen | 50 | 3300 | Olive powder coat | CT-101 | CT-L11-S-010
CT-L11-S-010-FB | L11 | CT-L11-S-010-FB | L11 | South | Metal rainscreen | 1250 | 50 | Olive powder coat | CT-101 | CT-L11-S-010
CT-L11-S-010-FT | L11 | CT-L11-S-010-FT | L11 | South | Metal rainscreen | 1250 | 50 | Olive powder coat | CT-101 | CT-L11-S-010
CT-L11-E-001-ML | L11 | CT-L11-E-001-ML | L11 | East | Curtain wall | 50 | 3300 | Blue-grey concept glass | CT-102 | CT-L11-E-001
CT-L11-E-001-MR | L11 | CT-L11-E-001-MR | L11 | East | Curtain wall | 50 | 3300 | Blue-grey concept glass | CT-102 | CT-L11-E-001
CT-L11-E-001-FB | L11 | CT-L11-E-001-FB | L11 | East | Curtain wall | 1250 | 50 | Blue-grey concept glass | CT-102 | CT-L11-E-001
CT-L11-E-001-FT | L11 | CT-L11-E-001-FT | L11 | East | Curtain wall | 1250 | 50 | Blue-grey concept glass | CT-102 | CT-L11-E-001
CT-L11-E-002-ML | L11 | CT-L11-E-002-ML | L11 | East | Curtain wall | 50 | 3300 | Blue-grey concept glass | CT-102 | CT-L11-E-002
CT-L11-E-002-MR | L11 | CT-L11-E-002-MR | L11 | East | Curtain wall | 50 | 3300 | Blue-grey concept glass | CT-102 | CT-L11-E-002
CT-L11-E-002-FB | L11 | CT-L11-E-002-FB | L11 | East | Curtain wall | 1400 | 50 | Blue-grey concept glass | CT-102 | CT-L11-E-002
CT-L11-E-002-FT | L11 | CT-L11-E-002-FT | L11 | East | Curtain wall | 1400 | 50 | Blue-grey concept glass | CT-102 | CT-L11-E-002
CT-L11-E-003-ML | L11 | CT-L11-E-003-ML | L11 | East | Curtain wall | 50 | 3300 | Blue-grey concept glass | CT-102 | CT-L11-E-003
CT-L11-E-003-MR | L11 | CT-L11-E-003-MR | L11 | East | Curtain wall | 50 | 3300 | Blue-grey concept glass | CT-102 | CT-L11-E-003
CT-L11-E-003-FB | L11 | CT-L11-E-003-FB | L11 | East | Curtain wall | 1400 | 50 | Blue-grey concept glass | CT-102 | CT-L11-E-003
CT-L11-E-003-FT | L11 | CT-L11-E-003-FT | L11 | East | Curtain wall | 1400 | 50 | Blue-grey concept glass | CT-102 | CT-L11-E-003
CT-L11-E-004-ML | L11 | CT-L11-E-004-ML | L11 | East | Curtain wall | 50 | 3300 | Blue-grey concept glass | CT-102 | CT-L11-E-004
CT-L11-E-004-MR | L11 | CT-L11-E-004-MR | L11 | East | Curtain wall | 50 | 3300 | Blue-grey concept glass | CT-102 | CT-L11-E-004
CT-L11-E-004-FB | L11 | CT-L11-E-004-FB | L11 | East | Curtain wall | 1400 | 50 | Blue-grey concept glass | CT-102 | CT-L11-E-004
CT-L11-E-004-FT | L11 | CT-L11-E-004-FT | L11 | East | Curtain wall | 1400 | 50 | Blue-grey concept glass | CT-102 | CT-L11-E-004
CT-L11-E-005-ML | L11 | CT-L11-E-005-ML | L11 | East | Metal rainscreen | 50 | 3300 | Olive powder coat | CT-102 | CT-L11-E-005
CT-L11-E-005-MR | L11 | CT-L11-E-005-MR | L11 | East | Metal rainscreen | 50 | 3300 | Olive powder coat | CT-102 | CT-L11-E-005
CT-L11-E-005-FB | L11 | CT-L11-E-005-FB | L11 | East | Metal rainscreen | 1400 | 50 | Olive powder coat | CT-102 | CT-L11-E-005
CT-L11-E-005-FT | L11 | CT-L11-E-005-FT | L11 | East | Metal rainscreen | 1400 | 50 | Olive powder coat | CT-102 | CT-L11-E-005
CT-L11-E-006-ML | L11 | CT-L11-E-006-ML | L11 | East | Curtain wall | 50 | 3300 | Blue-grey concept glass | CT-102 | CT-L11-E-006
CT-L11-E-006-MR | L11 | CT-L11-E-006-MR | L11 | East | Curtain wall | 50 | 3300 | Blue-grey concept glass | CT-102 | CT-L11-E-006
CT-L11-E-006-FB | L11 | CT-L11-E-006-FB | L11 | East | Curtain wall | 1400 | 50 | Blue-grey concept glass | CT-102 | CT-L11-E-006
CT-L11-E-006-FT | L11 | CT-L11-E-006-FT | L11 | East | Curtain wall | 1400 | 50 | Blue-grey concept glass | CT-102 | CT-L11-E-006
CT-L11-E-007-ML | L11 | CT-L11-E-007-ML | L11 | East | Curtain wall | 50 | 3300 | Blue-grey concept glass | CT-102 | CT-L11-E-007
CT-L11-E-007-MR | L11 | CT-L11-E-007-MR | L11 | East | Curtain wall | 50 | 3300 | Blue-grey concept glass | CT-102 | CT-L11-E-007
CT-L11-E-007-FB | L11 | CT-L11-E-007-FB | L11 | East | Curtain wall | 1400 | 50 | Blue-grey concept glass | CT-102 | CT-L11-E-007
CT-L11-E-007-FT | L11 | CT-L11-E-007-FT | L11 | East | Curtain wall | 1400 | 50 | Blue-grey concept glass | CT-102 | CT-L11-E-007
CT-L11-E-008-ML | L11 | CT-L11-E-008-ML | L11 | East | Curtain wall | 50 | 3300 | Blue-grey concept glass | CT-102 | CT-L11-E-008
CT-L11-E-008-MR | L11 | CT-L11-E-008-MR | L11 | East | Curtain wall | 50 | 3300 | Blue-grey concept glass | CT-102 | CT-L11-E-008
CT-L11-E-008-FB | L11 | CT-L11-E-008-FB | L11 | East | Curtain wall | 1250 | 50 | Blue-grey concept glass | CT-102 | CT-L11-E-008
CT-L11-E-008-FT | L11 | CT-L11-E-008-FT | L11 | East | Curtain wall | 1250 | 50 | Blue-grey concept glass | CT-102 | CT-L11-E-008
CT-L11-N-001-ML | L11 | CT-L11-N-001-ML | L11 | North | Curtain wall | 50 | 3300 | Blue-grey concept glass | CT-103 | CT-L11-N-001
CT-L11-N-001-MR | L11 | CT-L11-N-001-MR | L11 | North | Curtain wall | 50 | 3300 | Blue-grey concept glass | CT-103 | CT-L11-N-001
CT-L11-N-001-FB | L11 | CT-L11-N-001-FB | L11 | North | Curtain wall | 1250 | 50 | Blue-grey concept glass | CT-103 | CT-L11-N-001
CT-L11-N-001-FT | L11 | CT-L11-N-001-FT | L11 | North | Curtain wall | 1250 | 50 | Blue-grey concept glass | CT-103 | CT-L11-N-001
CT-L11-N-002-ML | L11 | CT-L11-N-002-ML | L11 | North | Curtain wall | 50 | 3300 | Blue-grey concept glass | CT-103 | CT-L11-N-002
CT-L11-N-002-MR | L11 | CT-L11-N-002-MR | L11 | North | Curtain wall | 50 | 3300 | Blue-grey concept glass | CT-103 | CT-L11-N-002
CT-L11-N-002-FB | L11 | CT-L11-N-002-FB | L11 | North | Curtain wall | 1400 | 50 | Blue-grey concept glass | CT-103 | CT-L11-N-002
CT-L11-N-002-FT | L11 | CT-L11-N-002-FT | L11 | North | Curtain wall | 1400 | 50 | Blue-grey concept glass | CT-103 | CT-L11-N-002
CT-L11-N-003-ML | L11 | CT-L11-N-003-ML | L11 | North | Curtain wall | 50 | 3300 | Blue-grey concept glass | CT-103 | CT-L11-N-003
CT-L11-N-003-MR | L11 | CT-L11-N-003-MR | L11 | North | Curtain wall | 50 | 3300 | Blue-grey concept glass | CT-103 | CT-L11-N-003
CT-L11-N-003-FB | L11 | CT-L11-N-003-FB | L11 | North | Curtain wall | 1400 | 50 | Blue-grey concept glass | CT-103 | CT-L11-N-003
CT-L11-N-003-FT | L11 | CT-L11-N-003-FT | L11 | North | Curtain wall | 1400 | 50 | Blue-grey concept glass | CT-103 | CT-L11-N-003
CT-L11-N-004-ML | L11 | CT-L11-N-004-ML | L11 | North | Curtain wall | 50 | 3300 | Blue-grey concept glass | CT-103 | CT-L11-N-004
CT-L11-N-004-MR | L11 | CT-L11-N-004-MR | L11 | North | Curtain wall | 50 | 3300 | Blue-grey concept glass | CT-103 | CT-L11-N-004
CT-L11-N-004-FB | L11 | CT-L11-N-004-FB | L11 | North | Curtain wall | 1400 | 50 | Blue-grey concept glass | CT-103 | CT-L11-N-004
CT-L11-N-004-FT | L11 | CT-L11-N-004-FT | L11 | North | Curtain wall | 1400 | 50 | Blue-grey concept glass | CT-103 | CT-L11-N-004
CT-L11-N-005-ML | L11 | CT-L11-N-005-ML | L11 | North | Metal rainscreen | 50 | 3300 | Olive powder coat | CT-103 | CT-L11-N-005
CT-L11-N-005-MR | L11 | CT-L11-N-005-MR | L11 | North | Metal rainscreen | 50 | 3300 | Olive powder coat | CT-103 | CT-L11-N-005
CT-L11-N-005-FB | L11 | CT-L11-N-005-FB | L11 | North | Metal rainscreen | 1400 | 50 | Olive powder coat | CT-103 | CT-L11-N-005
CT-L11-N-005-FT | L11 | CT-L11-N-005-FT | L11 | North | Metal rainscreen | 1400 | 50 | Olive powder coat | CT-103 | CT-L11-N-005
CT-L11-N-006-ML | L11 | CT-L11-N-006-ML | L11 | North | Curtain wall | 50 | 3300 | Blue-grey concept glass | CT-103 | CT-L11-N-006
CT-L11-N-006-MR | L11 | CT-L11-N-006-MR | L11 | North | Curtain wall | 50 | 3300 | Blue-grey concept glass | CT-103 | CT-L11-N-006
CT-L11-N-006-FB | L11 | CT-L11-N-006-FB | L11 | North | Curtain wall | 1400 | 50 | Blue-grey concept glass | CT-103 | CT-L11-N-006
CT-L11-N-006-FT | L11 | CT-L11-N-006-FT | L11 | North | Curtain wall | 1400 | 50 | Blue-grey concept glass | CT-103 | CT-L11-N-006
CT-L11-N-007-ML | L11 | CT-L11-N-007-ML | L11 | North | Curtain wall | 50 | 3300 | Blue-grey concept glass | CT-103 | CT-L11-N-007
CT-L11-N-007-MR | L11 | CT-L11-N-007-MR | L11 | North | Curtain wall | 50 | 3300 | Blue-grey concept glass | CT-103 | CT-L11-N-007
CT-L11-N-007-FB | L11 | CT-L11-N-007-FB | L11 | North | Curtain wall | 1400 | 50 | Blue-grey concept glass | CT-103 | CT-L11-N-007
CT-L11-N-007-FT | L11 | CT-L11-N-007-FT | L11 | North | Curtain wall | 1400 | 50 | Blue-grey concept glass | CT-103 | CT-L11-N-007
CT-L11-N-008-ML | L11 | CT-L11-N-008-ML | L11 | North | Curtain wall | 50 | 3300 | Blue-grey concept glass | CT-103 | CT-L11-N-008
CT-L11-N-008-MR | L11 | CT-L11-N-008-MR | L11 | North | Curtain wall | 50 | 3300 | Blue-grey concept glass | CT-103 | CT-L11-N-008
CT-L11-N-008-FB | L11 | CT-L11-N-008-FB | L11 | North | Curtain wall | 1400 | 50 | Blue-grey concept glass | CT-103 | CT-L11-N-008
CT-L11-N-008-FT | L11 | CT-L11-N-008-FT | L11 | North | Curtain wall | 1400 | 50 | Blue-grey concept glass | CT-103 | CT-L11-N-008
CT-L11-N-009-ML | L11 | CT-L11-N-009-ML | L11 | North | Curtain wall | 50 | 3300 | Blue-grey concept glass | CT-103 | CT-L11-N-009
CT-L11-N-009-MR | L11 | CT-L11-N-009-MR | L11 | North | Curtain wall | 50 | 3300 | Blue-grey concept glass | CT-103 | CT-L11-N-009
CT-L11-N-009-FB | L11 | CT-L11-N-009-FB | L11 | North | Curtain wall | 1400 | 50 | Blue-grey concept glass | CT-103 | CT-L11-N-009
CT-L11-N-009-FT | L11 | CT-L11-N-009-FT | L11 | North | Curtain wall | 1400 | 50 | Blue-grey concept glass | CT-103 | CT-L11-N-009
CT-L11-N-010-ML | L11 | CT-L11-N-010-ML | L11 | North | Metal rainscreen | 50 | 3300 | Olive powder coat | CT-103 | CT-L11-N-010
CT-L11-N-010-MR | L11 | CT-L11-N-010-MR | L11 | North | Metal rainscreen | 50 | 3300 | Olive powder coat | CT-103 | CT-L11-N-010
CT-L11-N-010-FB | L11 | CT-L11-N-010-FB | L11 | North | Metal rainscreen | 1250 | 50 | Olive powder coat | CT-103 | CT-L11-N-010
CT-L11-N-010-FT | L11 | CT-L11-N-010-FT | L11 | North | Metal rainscreen | 1250 | 50 | Olive powder coat | CT-103 | CT-L11-N-010
CT-L11-W-001-ML | L11 | CT-L11-W-001-ML | L11 | West | Curtain wall | 50 | 3300 | Blue-grey concept glass | CT-104 | CT-L11-W-001
CT-L11-W-001-MR | L11 | CT-L11-W-001-MR | L11 | West | Curtain wall | 50 | 3300 | Blue-grey concept glass | CT-104 | CT-L11-W-001
CT-L11-W-001-FB | L11 | CT-L11-W-001-FB | L11 | West | Curtain wall | 1250 | 50 | Blue-grey concept glass | CT-104 | CT-L11-W-001
CT-L11-W-001-FT | L11 | CT-L11-W-001-FT | L11 | West | Curtain wall | 1250 | 50 | Blue-grey concept glass | CT-104 | CT-L11-W-001
CT-L11-W-002-ML | L11 | CT-L11-W-002-ML | L11 | West | Curtain wall | 50 | 3300 | Blue-grey concept glass | CT-104 | CT-L11-W-002
CT-L11-W-002-MR | L11 | CT-L11-W-002-MR | L11 | West | Curtain wall | 50 | 3300 | Blue-grey concept glass | CT-104 | CT-L11-W-002
CT-L11-W-002-FB | L11 | CT-L11-W-002-FB | L11 | West | Curtain wall | 1400 | 50 | Blue-grey concept glass | CT-104 | CT-L11-W-002
CT-L11-W-002-FT | L11 | CT-L11-W-002-FT | L11 | West | Curtain wall | 1400 | 50 | Blue-grey concept glass | CT-104 | CT-L11-W-002
CT-L11-W-003-ML | L11 | CT-L11-W-003-ML | L11 | West | Curtain wall | 50 | 3300 | Blue-grey concept glass | CT-104 | CT-L11-W-003
CT-L11-W-003-MR | L11 | CT-L11-W-003-MR | L11 | West | Curtain wall | 50 | 3300 | Blue-grey concept glass | CT-104 | CT-L11-W-003
CT-L11-W-003-FB | L11 | CT-L11-W-003-FB | L11 | West | Curtain wall | 1400 | 50 | Blue-grey concept glass | CT-104 | CT-L11-W-003
CT-L11-W-003-FT | L11 | CT-L11-W-003-FT | L11 | West | Curtain wall | 1400 | 50 | Blue-grey concept glass | CT-104 | CT-L11-W-003
CT-L11-W-004-ML | L11 | CT-L11-W-004-ML | L11 | West | Curtain wall | 50 | 3300 | Blue-grey concept glass | CT-104 | CT-L11-W-004
CT-L11-W-004-MR | L11 | CT-L11-W-004-MR | L11 | West | Curtain wall | 50 | 3300 | Blue-grey concept glass | CT-104 | CT-L11-W-004
CT-L11-W-004-FB | L11 | CT-L11-W-004-FB | L11 | West | Curtain wall | 1400 | 50 | Blue-grey concept glass | CT-104 | CT-L11-W-004
CT-L11-W-004-FT | L11 | CT-L11-W-004-FT | L11 | West | Curtain wall | 1400 | 50 | Blue-grey concept glass | CT-104 | CT-L11-W-004
CT-L11-W-005-ML | L11 | CT-L11-W-005-ML | L11 | West | Metal rainscreen | 50 | 3300 | Olive powder coat | CT-104 | CT-L11-W-005
CT-L11-W-005-MR | L11 | CT-L11-W-005-MR | L11 | West | Metal rainscreen | 50 | 3300 | Olive powder coat | CT-104 | CT-L11-W-005
CT-L11-W-005-FB | L11 | CT-L11-W-005-FB | L11 | West | Metal rainscreen | 1400 | 50 | Olive powder coat | CT-104 | CT-L11-W-005
CT-L11-W-005-FT | L11 | CT-L11-W-005-FT | L11 | West | Metal rainscreen | 1400 | 50 | Olive powder coat | CT-104 | CT-L11-W-005
CT-L11-W-006-ML | L11 | CT-L11-W-006-ML | L11 | West | Curtain wall | 50 | 3300 | Blue-grey concept glass | CT-104 | CT-L11-W-006
CT-L11-W-006-MR | L11 | CT-L11-W-006-MR | L11 | West | Curtain wall | 50 | 3300 | Blue-grey concept glass | CT-104 | CT-L11-W-006
CT-L11-W-006-FB | L11 | CT-L11-W-006-FB | L11 | West | Curtain wall | 1400 | 50 | Blue-grey concept glass | CT-104 | CT-L11-W-006
CT-L11-W-006-FT | L11 | CT-L11-W-006-FT | L11 | West | Curtain wall | 1400 | 50 | Blue-grey concept glass | CT-104 | CT-L11-W-006
CT-L11-W-007-ML | L11 | CT-L11-W-007-ML | L11 | West | Curtain wall | 50 | 3300 | Blue-grey concept glass | CT-104 | CT-L11-W-007
CT-L11-W-007-MR | L11 | CT-L11-W-007-MR | L11 | West | Curtain wall | 50 | 3300 | Blue-grey concept glass | CT-104 | CT-L11-W-007
CT-L11-W-007-FB | L11 | CT-L11-W-007-FB | L11 | West | Curtain wall | 1400 | 50 | Blue-grey concept glass | CT-104 | CT-L11-W-007
CT-L11-W-007-FT | L11 | CT-L11-W-007-FT | L11 | West | Curtain wall | 1400 | 50 | Blue-grey concept glass | CT-104 | CT-L11-W-007
CT-L11-W-008-ML | L11 | CT-L11-W-008-ML | L11 | West | Curtain wall | 50 | 3300 | Blue-grey concept glass | CT-104 | CT-L11-W-008
CT-L11-W-008-MR | L11 | CT-L11-W-008-MR | L11 | West | Curtain wall | 50 | 3300 | Blue-grey concept glass | CT-104 | CT-L11-W-008
CT-L11-W-008-FB | L11 | CT-L11-W-008-FB | L11 | West | Curtain wall | 1250 | 50 | Blue-grey concept glass | CT-104 | CT-L11-W-008
CT-L11-W-008-FT | L11 | CT-L11-W-008-FT | L11 | West | Curtain wall | 1250 | 50 | Blue-grey concept glass | CT-104 | CT-L11-W-008
CT-L12-S-001-ML | L12 | CT-L12-S-001-ML | L12 | South | Curtain wall | 50 | 3300 | Blue-grey concept glass | CT-101 | CT-L12-S-001
CT-L12-S-001-MR | L12 | CT-L12-S-001-MR | L12 | South | Curtain wall | 50 | 3300 | Blue-grey concept glass | CT-101 | CT-L12-S-001
CT-L12-S-001-FB | L12 | CT-L12-S-001-FB | L12 | South | Curtain wall | 1250 | 50 | Blue-grey concept glass | CT-101 | CT-L12-S-001
CT-L12-S-001-FT | L12 | CT-L12-S-001-FT | L12 | South | Curtain wall | 1250 | 50 | Blue-grey concept glass | CT-101 | CT-L12-S-001
CT-L12-S-002-ML | L12 | CT-L12-S-002-ML | L12 | South | Curtain wall | 50 | 3300 | Blue-grey concept glass | CT-101 | CT-L12-S-002
CT-L12-S-002-MR | L12 | CT-L12-S-002-MR | L12 | South | Curtain wall | 50 | 3300 | Blue-grey concept glass | CT-101 | CT-L12-S-002
CT-L12-S-002-FB | L12 | CT-L12-S-002-FB | L12 | South | Curtain wall | 1400 | 50 | Blue-grey concept glass | CT-101 | CT-L12-S-002
CT-L12-S-002-FT | L12 | CT-L12-S-002-FT | L12 | South | Curtain wall | 1400 | 50 | Blue-grey concept glass | CT-101 | CT-L12-S-002
CT-L12-S-003-ML | L12 | CT-L12-S-003-ML | L12 | South | Curtain wall | 50 | 3300 | Blue-grey concept glass | CT-101 | CT-L12-S-003
CT-L12-S-003-MR | L12 | CT-L12-S-003-MR | L12 | South | Curtain wall | 50 | 3300 | Blue-grey concept glass | CT-101 | CT-L12-S-003
CT-L12-S-003-FB | L12 | CT-L12-S-003-FB | L12 | South | Curtain wall | 1400 | 50 | Blue-grey concept glass | CT-101 | CT-L12-S-003
CT-L12-S-003-FT | L12 | CT-L12-S-003-FT | L12 | South | Curtain wall | 1400 | 50 | Blue-grey concept glass | CT-101 | CT-L12-S-003
CT-L12-S-004-ML | L12 | CT-L12-S-004-ML | L12 | South | Curtain wall | 50 | 3300 | Blue-grey concept glass | CT-101 | CT-L12-S-004
CT-L12-S-004-MR | L12 | CT-L12-S-004-MR | L12 | South | Curtain wall | 50 | 3300 | Blue-grey concept glass | CT-101 | CT-L12-S-004
CT-L12-S-004-FB | L12 | CT-L12-S-004-FB | L12 | South | Curtain wall | 1400 | 50 | Blue-grey concept glass | CT-101 | CT-L12-S-004
CT-L12-S-004-FT | L12 | CT-L12-S-004-FT | L12 | South | Curtain wall | 1400 | 50 | Blue-grey concept glass | CT-101 | CT-L12-S-004
CT-L12-S-005-ML | L12 | CT-L12-S-005-ML | L12 | South | Metal rainscreen | 50 | 3300 | Olive powder coat | CT-101 | CT-L12-S-005
CT-L12-S-005-MR | L12 | CT-L12-S-005-MR | L12 | South | Metal rainscreen | 50 | 3300 | Olive powder coat | CT-101 | CT-L12-S-005
CT-L12-S-005-FB | L12 | CT-L12-S-005-FB | L12 | South | Metal rainscreen | 1400 | 50 | Olive powder coat | CT-101 | CT-L12-S-005
CT-L12-S-005-FT | L12 | CT-L12-S-005-FT | L12 | South | Metal rainscreen | 1400 | 50 | Olive powder coat | CT-101 | CT-L12-S-005
CT-L12-S-006-ML | L12 | CT-L12-S-006-ML | L12 | South | Curtain wall | 50 | 3300 | Blue-grey concept glass | CT-101 | CT-L12-S-006
CT-L12-S-006-MR | L12 | CT-L12-S-006-MR | L12 | South | Curtain wall | 50 | 3300 | Blue-grey concept glass | CT-101 | CT-L12-S-006
CT-L12-S-006-FB | L12 | CT-L12-S-006-FB | L12 | South | Curtain wall | 1400 | 50 | Blue-grey concept glass | CT-101 | CT-L12-S-006
CT-L12-S-006-FT | L12 | CT-L12-S-006-FT | L12 | South | Curtain wall | 1400 | 50 | Blue-grey concept glass | CT-101 | CT-L12-S-006
CT-L12-S-007-ML | L12 | CT-L12-S-007-ML | L12 | South | Curtain wall | 50 | 3300 | Blue-grey concept glass | CT-101 | CT-L12-S-007
CT-L12-S-007-MR | L12 | CT-L12-S-007-MR | L12 | South | Curtain wall | 50 | 3300 | Blue-grey concept glass | CT-101 | CT-L12-S-007
CT-L12-S-007-FB | L12 | CT-L12-S-007-FB | L12 | South | Curtain wall | 1400 | 50 | Blue-grey concept glass | CT-101 | CT-L12-S-007
CT-L12-S-007-FT | L12 | CT-L12-S-007-FT | L12 | South | Curtain wall | 1400 | 50 | Blue-grey concept glass | CT-101 | CT-L12-S-007
CT-L12-S-008-ML | L12 | CT-L12-S-008-ML | L12 | South | Curtain wall | 50 | 3300 | Blue-grey concept glass | CT-101 | CT-L12-S-008
CT-L12-S-008-MR | L12 | CT-L12-S-008-MR | L12 | South | Curtain wall | 50 | 3300 | Blue-grey concept glass | CT-101 | CT-L12-S-008
CT-L12-S-008-FB | L12 | CT-L12-S-008-FB | L12 | South | Curtain wall | 1400 | 50 | Blue-grey concept glass | CT-101 | CT-L12-S-008
CT-L12-S-008-FT | L12 | CT-L12-S-008-FT | L12 | South | Curtain wall | 1400 | 50 | Blue-grey concept glass | CT-101 | CT-L12-S-008
CT-L12-S-009-ML | L12 | CT-L12-S-009-ML | L12 | South | Curtain wall | 50 | 3300 | Blue-grey concept glass | CT-101 | CT-L12-S-009
CT-L12-S-009-MR | L12 | CT-L12-S-009-MR | L12 | South | Curtain wall | 50 | 3300 | Blue-grey concept glass | CT-101 | CT-L12-S-009
CT-L12-S-009-FB | L12 | CT-L12-S-009-FB | L12 | South | Curtain wall | 1400 | 50 | Blue-grey concept glass | CT-101 | CT-L12-S-009
CT-L12-S-009-FT | L12 | CT-L12-S-009-FT | L12 | South | Curtain wall | 1400 | 50 | Blue-grey concept glass | CT-101 | CT-L12-S-009
CT-L12-S-010-ML | L12 | CT-L12-S-010-ML | L12 | South | Metal rainscreen | 50 | 3300 | Olive powder coat | CT-101 | CT-L12-S-010
CT-L12-S-010-MR | L12 | CT-L12-S-010-MR | L12 | South | Metal rainscreen | 50 | 3300 | Olive powder coat | CT-101 | CT-L12-S-010
CT-L12-S-010-FB | L12 | CT-L12-S-010-FB | L12 | South | Metal rainscreen | 1250 | 50 | Olive powder coat | CT-101 | CT-L12-S-010
CT-L12-S-010-FT | L12 | CT-L12-S-010-FT | L12 | South | Metal rainscreen | 1250 | 50 | Olive powder coat | CT-101 | CT-L12-S-010
CT-L12-E-001-ML | L12 | CT-L12-E-001-ML | L12 | East | Curtain wall | 50 | 3300 | Blue-grey concept glass | CT-102 | CT-L12-E-001
CT-L12-E-001-MR | L12 | CT-L12-E-001-MR | L12 | East | Curtain wall | 50 | 3300 | Blue-grey concept glass | CT-102 | CT-L12-E-001
CT-L12-E-001-FB | L12 | CT-L12-E-001-FB | L12 | East | Curtain wall | 1250 | 50 | Blue-grey concept glass | CT-102 | CT-L12-E-001
CT-L12-E-001-FT | L12 | CT-L12-E-001-FT | L12 | East | Curtain wall | 1250 | 50 | Blue-grey concept glass | CT-102 | CT-L12-E-001
CT-L12-E-002-ML | L12 | CT-L12-E-002-ML | L12 | East | Curtain wall | 50 | 3300 | Blue-grey concept glass | CT-102 | CT-L12-E-002
CT-L12-E-002-MR | L12 | CT-L12-E-002-MR | L12 | East | Curtain wall | 50 | 3300 | Blue-grey concept glass | CT-102 | CT-L12-E-002
CT-L12-E-002-FB | L12 | CT-L12-E-002-FB | L12 | East | Curtain wall | 1400 | 50 | Blue-grey concept glass | CT-102 | CT-L12-E-002
CT-L12-E-002-FT | L12 | CT-L12-E-002-FT | L12 | East | Curtain wall | 1400 | 50 | Blue-grey concept glass | CT-102 | CT-L12-E-002
CT-L12-E-003-ML | L12 | CT-L12-E-003-ML | L12 | East | Curtain wall | 50 | 3300 | Blue-grey concept glass | CT-102 | CT-L12-E-003
CT-L12-E-003-MR | L12 | CT-L12-E-003-MR | L12 | East | Curtain wall | 50 | 3300 | Blue-grey concept glass | CT-102 | CT-L12-E-003
CT-L12-E-003-FB | L12 | CT-L12-E-003-FB | L12 | East | Curtain wall | 1400 | 50 | Blue-grey concept glass | CT-102 | CT-L12-E-003
CT-L12-E-003-FT | L12 | CT-L12-E-003-FT | L12 | East | Curtain wall | 1400 | 50 | Blue-grey concept glass | CT-102 | CT-L12-E-003
CT-L12-E-004-ML | L12 | CT-L12-E-004-ML | L12 | East | Curtain wall | 50 | 3300 | Blue-grey concept glass | CT-102 | CT-L12-E-004
CT-L12-E-004-MR | L12 | CT-L12-E-004-MR | L12 | East | Curtain wall | 50 | 3300 | Blue-grey concept glass | CT-102 | CT-L12-E-004
CT-L12-E-004-FB | L12 | CT-L12-E-004-FB | L12 | East | Curtain wall | 1400 | 50 | Blue-grey concept glass | CT-102 | CT-L12-E-004
CT-L12-E-004-FT | L12 | CT-L12-E-004-FT | L12 | East | Curtain wall | 1400 | 50 | Blue-grey concept glass | CT-102 | CT-L12-E-004
CT-L12-E-005-ML | L12 | CT-L12-E-005-ML | L12 | East | Metal rainscreen | 50 | 3300 | Olive powder coat | CT-102 | CT-L12-E-005
CT-L12-E-005-MR | L12 | CT-L12-E-005-MR | L12 | East | Metal rainscreen | 50 | 3300 | Olive powder coat | CT-102 | CT-L12-E-005
CT-L12-E-005-FB | L12 | CT-L12-E-005-FB | L12 | East | Metal rainscreen | 1400 | 50 | Olive powder coat | CT-102 | CT-L12-E-005
CT-L12-E-005-FT | L12 | CT-L12-E-005-FT | L12 | East | Metal rainscreen | 1400 | 50 | Olive powder coat | CT-102 | CT-L12-E-005
CT-L12-E-006-ML | L12 | CT-L12-E-006-ML | L12 | East | Curtain wall | 50 | 3300 | Blue-grey concept glass | CT-102 | CT-L12-E-006
CT-L12-E-006-MR | L12 | CT-L12-E-006-MR | L12 | East | Curtain wall | 50 | 3300 | Blue-grey concept glass | CT-102 | CT-L12-E-006
CT-L12-E-006-FB | L12 | CT-L12-E-006-FB | L12 | East | Curtain wall | 1400 | 50 | Blue-grey concept glass | CT-102 | CT-L12-E-006
CT-L12-E-006-FT | L12 | CT-L12-E-006-FT | L12 | East | Curtain wall | 1400 | 50 | Blue-grey concept glass | CT-102 | CT-L12-E-006
CT-L12-E-007-ML | L12 | CT-L12-E-007-ML | L12 | East | Curtain wall | 50 | 3300 | Blue-grey concept glass | CT-102 | CT-L12-E-007
CT-L12-E-007-MR | L12 | CT-L12-E-007-MR | L12 | East | Curtain wall | 50 | 3300 | Blue-grey concept glass | CT-102 | CT-L12-E-007
CT-L12-E-007-FB | L12 | CT-L12-E-007-FB | L12 | East | Curtain wall | 1400 | 50 | Blue-grey concept glass | CT-102 | CT-L12-E-007
CT-L12-E-007-FT | L12 | CT-L12-E-007-FT | L12 | East | Curtain wall | 1400 | 50 | Blue-grey concept glass | CT-102 | CT-L12-E-007
CT-L12-E-008-ML | L12 | CT-L12-E-008-ML | L12 | East | Curtain wall | 50 | 3300 | Blue-grey concept glass | CT-102 | CT-L12-E-008
CT-L12-E-008-MR | L12 | CT-L12-E-008-MR | L12 | East | Curtain wall | 50 | 3300 | Blue-grey concept glass | CT-102 | CT-L12-E-008
CT-L12-E-008-FB | L12 | CT-L12-E-008-FB | L12 | East | Curtain wall | 1250 | 50 | Blue-grey concept glass | CT-102 | CT-L12-E-008
CT-L12-E-008-FT | L12 | CT-L12-E-008-FT | L12 | East | Curtain wall | 1250 | 50 | Blue-grey concept glass | CT-102 | CT-L12-E-008
CT-L12-N-001-ML | L12 | CT-L12-N-001-ML | L12 | North | Curtain wall | 50 | 3300 | Blue-grey concept glass | CT-103 | CT-L12-N-001
CT-L12-N-001-MR | L12 | CT-L12-N-001-MR | L12 | North | Curtain wall | 50 | 3300 | Blue-grey concept glass | CT-103 | CT-L12-N-001
CT-L12-N-001-FB | L12 | CT-L12-N-001-FB | L12 | North | Curtain wall | 1250 | 50 | Blue-grey concept glass | CT-103 | CT-L12-N-001
CT-L12-N-001-FT | L12 | CT-L12-N-001-FT | L12 | North | Curtain wall | 1250 | 50 | Blue-grey concept glass | CT-103 | CT-L12-N-001
CT-L12-N-002-ML | L12 | CT-L12-N-002-ML | L12 | North | Curtain wall | 50 | 3300 | Blue-grey concept glass | CT-103 | CT-L12-N-002
CT-L12-N-002-MR | L12 | CT-L12-N-002-MR | L12 | North | Curtain wall | 50 | 3300 | Blue-grey concept glass | CT-103 | CT-L12-N-002
CT-L12-N-002-FB | L12 | CT-L12-N-002-FB | L12 | North | Curtain wall | 1400 | 50 | Blue-grey concept glass | CT-103 | CT-L12-N-002
CT-L12-N-002-FT | L12 | CT-L12-N-002-FT | L12 | North | Curtain wall | 1400 | 50 | Blue-grey concept glass | CT-103 | CT-L12-N-002
CT-L12-N-003-ML | L12 | CT-L12-N-003-ML | L12 | North | Curtain wall | 50 | 3300 | Blue-grey concept glass | CT-103 | CT-L12-N-003
CT-L12-N-003-MR | L12 | CT-L12-N-003-MR | L12 | North | Curtain wall | 50 | 3300 | Blue-grey concept glass | CT-103 | CT-L12-N-003
CT-L12-N-003-FB | L12 | CT-L12-N-003-FB | L12 | North | Curtain wall | 1400 | 50 | Blue-grey concept glass | CT-103 | CT-L12-N-003
CT-L12-N-003-FT | L12 | CT-L12-N-003-FT | L12 | North | Curtain wall | 1400 | 50 | Blue-grey concept glass | CT-103 | CT-L12-N-003
CT-L12-N-004-ML | L12 | CT-L12-N-004-ML | L12 | North | Curtain wall | 50 | 3300 | Blue-grey concept glass | CT-103 | CT-L12-N-004
CT-L12-N-004-MR | L12 | CT-L12-N-004-MR | L12 | North | Curtain wall | 50 | 3300 | Blue-grey concept glass | CT-103 | CT-L12-N-004
CT-L12-N-004-FB | L12 | CT-L12-N-004-FB | L12 | North | Curtain wall | 1400 | 50 | Blue-grey concept glass | CT-103 | CT-L12-N-004
CT-L12-N-004-FT | L12 | CT-L12-N-004-FT | L12 | North | Curtain wall | 1400 | 50 | Blue-grey concept glass | CT-103 | CT-L12-N-004
CT-L12-N-005-ML | L12 | CT-L12-N-005-ML | L12 | North | Metal rainscreen | 50 | 3300 | Olive powder coat | CT-103 | CT-L12-N-005
CT-L12-N-005-MR | L12 | CT-L12-N-005-MR | L12 | North | Metal rainscreen | 50 | 3300 | Olive powder coat | CT-103 | CT-L12-N-005
CT-L12-N-005-FB | L12 | CT-L12-N-005-FB | L12 | North | Metal rainscreen | 1400 | 50 | Olive powder coat | CT-103 | CT-L12-N-005
CT-L12-N-005-FT | L12 | CT-L12-N-005-FT | L12 | North | Metal rainscreen | 1400 | 50 | Olive powder coat | CT-103 | CT-L12-N-005
CT-L12-N-006-ML | L12 | CT-L12-N-006-ML | L12 | North | Curtain wall | 50 | 3300 | Blue-grey concept glass | CT-103 | CT-L12-N-006
CT-L12-N-006-MR | L12 | CT-L12-N-006-MR | L12 | North | Curtain wall | 50 | 3300 | Blue-grey concept glass | CT-103 | CT-L12-N-006
CT-L12-N-006-FB | L12 | CT-L12-N-006-FB | L12 | North | Curtain wall | 1400 | 50 | Blue-grey concept glass | CT-103 | CT-L12-N-006
CT-L12-N-006-FT | L12 | CT-L12-N-006-FT | L12 | North | Curtain wall | 1400 | 50 | Blue-grey concept glass | CT-103 | CT-L12-N-006
CT-L12-N-007-ML | L12 | CT-L12-N-007-ML | L12 | North | Curtain wall | 50 | 3300 | Blue-grey concept glass | CT-103 | CT-L12-N-007
CT-L12-N-007-MR | L12 | CT-L12-N-007-MR | L12 | North | Curtain wall | 50 | 3300 | Blue-grey concept glass | CT-103 | CT-L12-N-007
CT-L12-N-007-FB | L12 | CT-L12-N-007-FB | L12 | North | Curtain wall | 1400 | 50 | Blue-grey concept glass | CT-103 | CT-L12-N-007
CT-L12-N-007-FT | L12 | CT-L12-N-007-FT | L12 | North | Curtain wall | 1400 | 50 | Blue-grey concept glass | CT-103 | CT-L12-N-007
CT-L12-N-008-ML | L12 | CT-L12-N-008-ML | L12 | North | Curtain wall | 50 | 3300 | Blue-grey concept glass | CT-103 | CT-L12-N-008
CT-L12-N-008-MR | L12 | CT-L12-N-008-MR | L12 | North | Curtain wall | 50 | 3300 | Blue-grey concept glass | CT-103 | CT-L12-N-008
CT-L12-N-008-FB | L12 | CT-L12-N-008-FB | L12 | North | Curtain wall | 1400 | 50 | Blue-grey concept glass | CT-103 | CT-L12-N-008
CT-L12-N-008-FT | L12 | CT-L12-N-008-FT | L12 | North | Curtain wall | 1400 | 50 | Blue-grey concept glass | CT-103 | CT-L12-N-008
CT-L12-N-009-ML | L12 | CT-L12-N-009-ML | L12 | North | Curtain wall | 50 | 3300 | Blue-grey concept glass | CT-103 | CT-L12-N-009
CT-L12-N-009-MR | L12 | CT-L12-N-009-MR | L12 | North | Curtain wall | 50 | 3300 | Blue-grey concept glass | CT-103 | CT-L12-N-009
CT-L12-N-009-FB | L12 | CT-L12-N-009-FB | L12 | North | Curtain wall | 1400 | 50 | Blue-grey concept glass | CT-103 | CT-L12-N-009
CT-L12-N-009-FT | L12 | CT-L12-N-009-FT | L12 | North | Curtain wall | 1400 | 50 | Blue-grey concept glass | CT-103 | CT-L12-N-009
CT-L12-N-010-ML | L12 | CT-L12-N-010-ML | L12 | North | Metal rainscreen | 50 | 3300 | Olive powder coat | CT-103 | CT-L12-N-010
CT-L12-N-010-MR | L12 | CT-L12-N-010-MR | L12 | North | Metal rainscreen | 50 | 3300 | Olive powder coat | CT-103 | CT-L12-N-010
CT-L12-N-010-FB | L12 | CT-L12-N-010-FB | L12 | North | Metal rainscreen | 1250 | 50 | Olive powder coat | CT-103 | CT-L12-N-010
CT-L12-N-010-FT | L12 | CT-L12-N-010-FT | L12 | North | Metal rainscreen | 1250 | 50 | Olive powder coat | CT-103 | CT-L12-N-010
CT-L12-W-001-ML | L12 | CT-L12-W-001-ML | L12 | West | Curtain wall | 50 | 3300 | Blue-grey concept glass | CT-104 | CT-L12-W-001
CT-L12-W-001-MR | L12 | CT-L12-W-001-MR | L12 | West | Curtain wall | 50 | 3300 | Blue-grey concept glass | CT-104 | CT-L12-W-001
CT-L12-W-001-FB | L12 | CT-L12-W-001-FB | L12 | West | Curtain wall | 1250 | 50 | Blue-grey concept glass | CT-104 | CT-L12-W-001
CT-L12-W-001-FT | L12 | CT-L12-W-001-FT | L12 | West | Curtain wall | 1250 | 50 | Blue-grey concept glass | CT-104 | CT-L12-W-001
CT-L12-W-002-ML | L12 | CT-L12-W-002-ML | L12 | West | Curtain wall | 50 | 3300 | Blue-grey concept glass | CT-104 | CT-L12-W-002
CT-L12-W-002-MR | L12 | CT-L12-W-002-MR | L12 | West | Curtain wall | 50 | 3300 | Blue-grey concept glass | CT-104 | CT-L12-W-002
CT-L12-W-002-FB | L12 | CT-L12-W-002-FB | L12 | West | Curtain wall | 1400 | 50 | Blue-grey concept glass | CT-104 | CT-L12-W-002
CT-L12-W-002-FT | L12 | CT-L12-W-002-FT | L12 | West | Curtain wall | 1400 | 50 | Blue-grey concept glass | CT-104 | CT-L12-W-002
CT-L12-W-003-ML | L12 | CT-L12-W-003-ML | L12 | West | Curtain wall | 50 | 3300 | Blue-grey concept glass | CT-104 | CT-L12-W-003
CT-L12-W-003-MR | L12 | CT-L12-W-003-MR | L12 | West | Curtain wall | 50 | 3300 | Blue-grey concept glass | CT-104 | CT-L12-W-003
CT-L12-W-003-FB | L12 | CT-L12-W-003-FB | L12 | West | Curtain wall | 1400 | 50 | Blue-grey concept glass | CT-104 | CT-L12-W-003
CT-L12-W-003-FT | L12 | CT-L12-W-003-FT | L12 | West | Curtain wall | 1400 | 50 | Blue-grey concept glass | CT-104 | CT-L12-W-003
CT-L12-W-004-ML | L12 | CT-L12-W-004-ML | L12 | West | Curtain wall | 50 | 3300 | Blue-grey concept glass | CT-104 | CT-L12-W-004
CT-L12-W-004-MR | L12 | CT-L12-W-004-MR | L12 | West | Curtain wall | 50 | 3300 | Blue-grey concept glass | CT-104 | CT-L12-W-004
CT-L12-W-004-FB | L12 | CT-L12-W-004-FB | L12 | West | Curtain wall | 1400 | 50 | Blue-grey concept glass | CT-104 | CT-L12-W-004
CT-L12-W-004-FT | L12 | CT-L12-W-004-FT | L12 | West | Curtain wall | 1400 | 50 | Blue-grey concept glass | CT-104 | CT-L12-W-004
CT-L12-W-005-ML | L12 | CT-L12-W-005-ML | L12 | West | Metal rainscreen | 50 | 3300 | Olive powder coat | CT-104 | CT-L12-W-005
CT-L12-W-005-MR | L12 | CT-L12-W-005-MR | L12 | West | Metal rainscreen | 50 | 3300 | Olive powder coat | CT-104 | CT-L12-W-005
CT-L12-W-005-FB | L12 | CT-L12-W-005-FB | L12 | West | Metal rainscreen | 1400 | 50 | Olive powder coat | CT-104 | CT-L12-W-005
CT-L12-W-005-FT | L12 | CT-L12-W-005-FT | L12 | West | Metal rainscreen | 1400 | 50 | Olive powder coat | CT-104 | CT-L12-W-005
CT-L12-W-006-ML | L12 | CT-L12-W-006-ML | L12 | West | Curtain wall | 50 | 3300 | Blue-grey concept glass | CT-104 | CT-L12-W-006
CT-L12-W-006-MR | L12 | CT-L12-W-006-MR | L12 | West | Curtain wall | 50 | 3300 | Blue-grey concept glass | CT-104 | CT-L12-W-006
CT-L12-W-006-FB | L12 | CT-L12-W-006-FB | L12 | West | Curtain wall | 1400 | 50 | Blue-grey concept glass | CT-104 | CT-L12-W-006
CT-L12-W-006-FT | L12 | CT-L12-W-006-FT | L12 | West | Curtain wall | 1400 | 50 | Blue-grey concept glass | CT-104 | CT-L12-W-006
CT-L12-W-007-ML | L12 | CT-L12-W-007-ML | L12 | West | Curtain wall | 50 | 3300 | Blue-grey concept glass | CT-104 | CT-L12-W-007
